VERSION 5.8 ;
BUSBITCHARS "[]" ;
DIVIDERCHAR "/" ;
UNITS
    DATABASE MICRONS 1000 ;
END UNITS

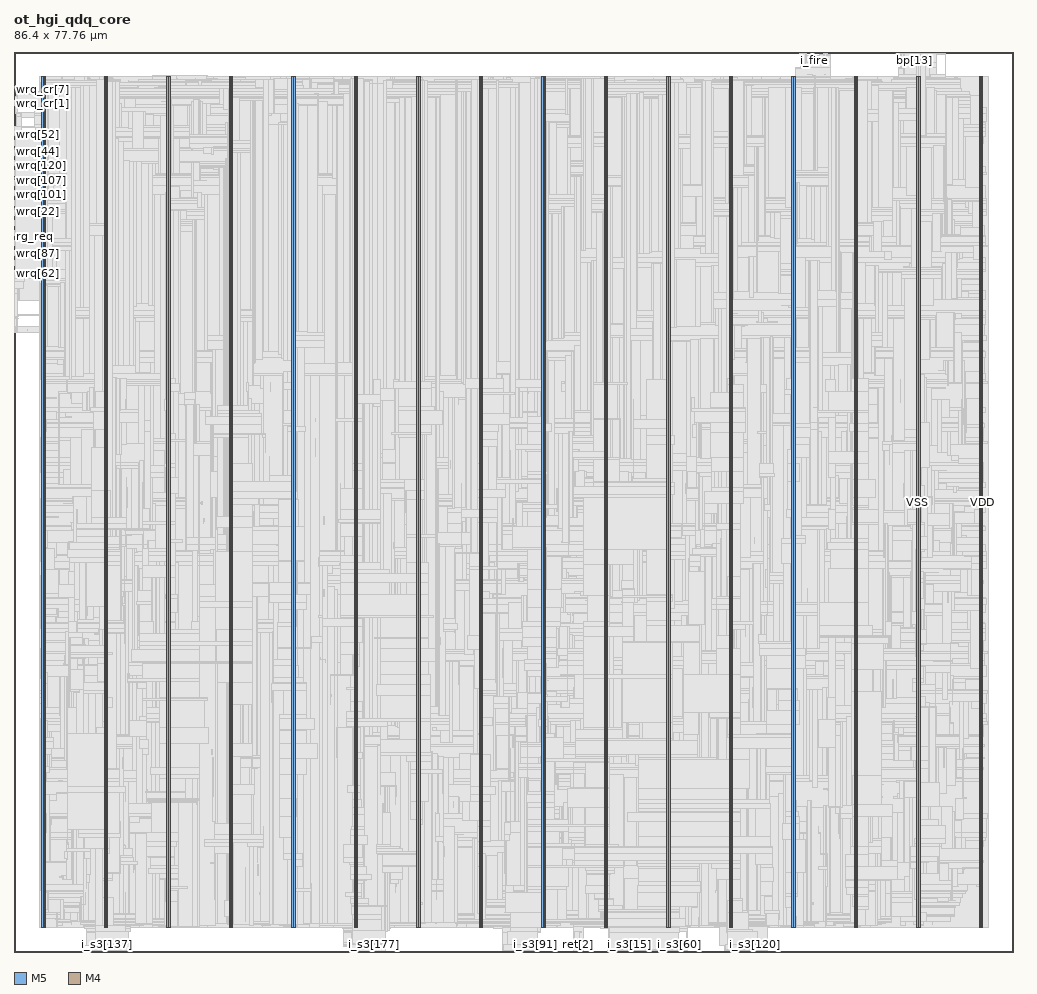
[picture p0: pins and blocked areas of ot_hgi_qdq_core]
MACRO ot_hgi_qdq_core
  FOREIGN ot_hgi_qdq_core 0 0 ;
  CLASS BLOCK ;
  SIZE 86.4 BY 77.76 ;
  PIN asm_rst_n
    DIRECTION OUTPUT ;
    USE SIGNAL ;
    PORT
      LAYER M5 ;
        RECT  76.464 77.676 76.488 77.76 ;
    END
  END asm_rst_n
  PIN bp[0]
    DIRECTION OUTPUT ;
    USE SIGNAL ;
    PORT
      LAYER M5 ;
        RECT  76.56 77.676 76.584 77.76 ;
    END
  END bp[0]
  PIN bp[10]
    DIRECTION OUTPUT ;
    USE SIGNAL ;
    PORT
      LAYER M5 ;
        RECT  77.52 77.676 77.544 77.76 ;
    END
  END bp[10]
  PIN bp[11]
    DIRECTION OUTPUT ;
    USE SIGNAL ;
    PORT
      LAYER M5 ;
        RECT  77.616 77.676 77.64 77.76 ;
    END
  END bp[11]
  PIN bp[12]
    DIRECTION OUTPUT ;
    USE SIGNAL ;
    PORT
      LAYER M5 ;
        RECT  77.712 77.676 77.736 77.76 ;
    END
  END bp[12]
  PIN bp[13]
    DIRECTION OUTPUT ;
    USE SIGNAL ;
    PORT
      LAYER M5 ;
        RECT  77.808 77.676 77.832 77.76 ;
    END
  END bp[13]
  PIN bp[14]
    DIRECTION OUTPUT ;
    USE SIGNAL ;
    PORT
      LAYER M5 ;
        RECT  77.904 77.676 77.928 77.76 ;
    END
  END bp[14]
  PIN bp[15]
    DIRECTION OUTPUT ;
    USE SIGNAL ;
    PORT
      LAYER M5 ;
        RECT  78 77.676 78.024 77.76 ;
    END
  END bp[15]
  PIN bp[16]
    DIRECTION OUTPUT ;
    USE SIGNAL ;
    PORT
      LAYER M5 ;
        RECT  78.096 77.676 78.12 77.76 ;
    END
  END bp[16]
  PIN bp[17]
    DIRECTION OUTPUT ;
    USE SIGNAL ;
    PORT
      LAYER M5 ;
        RECT  78.192 77.676 78.216 77.76 ;
    END
  END bp[17]
  PIN bp[18]
    DIRECTION OUTPUT ;
    USE SIGNAL ;
    PORT
      LAYER M5 ;
        RECT  78.288 77.676 78.312 77.76 ;
    END
  END bp[18]
  PIN bp[19]
    DIRECTION OUTPUT ;
    USE SIGNAL ;
    PORT
      LAYER M5 ;
        RECT  78.384 77.676 78.408 77.76 ;
    END
  END bp[19]
  PIN bp[1]
    DIRECTION OUTPUT ;
    USE SIGNAL ;
    PORT
      LAYER M5 ;
        RECT  76.656 77.676 76.68 77.76 ;
    END
  END bp[1]
  PIN bp[20]
    DIRECTION OUTPUT ;
    USE SIGNAL ;
    PORT
      LAYER M5 ;
        RECT  78.48 77.676 78.504 77.76 ;
    END
  END bp[20]
  PIN bp[21]
    DIRECTION OUTPUT ;
    USE SIGNAL ;
    PORT
      LAYER M5 ;
        RECT  78.576 77.676 78.6 77.76 ;
    END
  END bp[21]
  PIN bp[22]
    DIRECTION OUTPUT ;
    USE SIGNAL ;
    PORT
      LAYER M5 ;
        RECT  78.672 77.676 78.696 77.76 ;
    END
  END bp[22]
  PIN bp[23]
    DIRECTION OUTPUT ;
    USE SIGNAL ;
    PORT
      LAYER M5 ;
        RECT  78.768 77.676 78.792 77.76 ;
    END
  END bp[23]
  PIN bp[24]
    DIRECTION OUTPUT ;
    USE SIGNAL ;
    PORT
      LAYER M5 ;
        RECT  78.864 77.676 78.888 77.76 ;
    END
  END bp[24]
  PIN bp[25]
    DIRECTION OUTPUT ;
    USE SIGNAL ;
    PORT
      LAYER M5 ;
        RECT  78.96 77.676 78.984 77.76 ;
    END
  END bp[25]
  PIN bp[26]
    DIRECTION OUTPUT ;
    USE SIGNAL ;
    PORT
      LAYER M5 ;
        RECT  79.056 77.676 79.08 77.76 ;
    END
  END bp[26]
  PIN bp[27]
    DIRECTION OUTPUT ;
    USE SIGNAL ;
    PORT
      LAYER M5 ;
        RECT  79.152 77.676 79.176 77.76 ;
    END
  END bp[27]
  PIN bp[28]
    DIRECTION OUTPUT ;
    USE SIGNAL ;
    PORT
      LAYER M5 ;
        RECT  79.248 77.676 79.272 77.76 ;
    END
  END bp[28]
  PIN bp[29]
    DIRECTION OUTPUT ;
    USE SIGNAL ;
    PORT
      LAYER M5 ;
        RECT  79.344 77.676 79.368 77.76 ;
    END
  END bp[29]
  PIN bp[2]
    DIRECTION OUTPUT ;
    USE SIGNAL ;
    PORT
      LAYER M5 ;
        RECT  76.752 77.676 76.776 77.76 ;
    END
  END bp[2]
  PIN bp[30]
    DIRECTION OUTPUT ;
    USE SIGNAL ;
    PORT
      LAYER M5 ;
        RECT  79.44 77.676 79.464 77.76 ;
    END
  END bp[30]
  PIN bp[31]
    DIRECTION OUTPUT ;
    USE SIGNAL ;
    PORT
      LAYER M5 ;
        RECT  67.92 77.676 67.944 77.76 ;
    END
  END bp[31]
  PIN bp[32]
    DIRECTION OUTPUT ;
    USE SIGNAL ;
    PORT
      LAYER M5 ;
        RECT  68.016 77.676 68.04 77.76 ;
    END
  END bp[32]
  PIN bp[33]
    DIRECTION OUTPUT ;
    USE SIGNAL ;
    PORT
      LAYER M5 ;
        RECT  68.112 77.676 68.136 77.76 ;
    END
  END bp[33]
  PIN bp[34]
    DIRECTION OUTPUT ;
    USE SIGNAL ;
    PORT
      LAYER M5 ;
        RECT  68.208 77.676 68.232 77.76 ;
    END
  END bp[34]
  PIN bp[35]
    DIRECTION OUTPUT ;
    USE SIGNAL ;
    PORT
      LAYER M5 ;
        RECT  68.304 77.676 68.328 77.76 ;
    END
  END bp[35]
  PIN bp[36]
    DIRECTION OUTPUT ;
    USE SIGNAL ;
    PORT
      LAYER M5 ;
        RECT  68.4 77.676 68.424 77.76 ;
    END
  END bp[36]
  PIN bp[37]
    DIRECTION OUTPUT ;
    USE SIGNAL ;
    PORT
      LAYER M5 ;
        RECT  68.496 77.676 68.52 77.76 ;
    END
  END bp[37]
  PIN bp[38]
    DIRECTION OUTPUT ;
    USE SIGNAL ;
    PORT
      LAYER M5 ;
        RECT  68.592 77.676 68.616 77.76 ;
    END
  END bp[38]
  PIN bp[39]
    DIRECTION OUTPUT ;
    USE SIGNAL ;
    PORT
      LAYER M5 ;
        RECT  68.688 77.676 68.712 77.76 ;
    END
  END bp[39]
  PIN bp[3]
    DIRECTION OUTPUT ;
    USE SIGNAL ;
    PORT
      LAYER M5 ;
        RECT  76.848 77.676 76.872 77.76 ;
    END
  END bp[3]
  PIN bp[4]
    DIRECTION OUTPUT ;
    USE SIGNAL ;
    PORT
      LAYER M5 ;
        RECT  76.944 77.676 76.968 77.76 ;
    END
  END bp[4]
  PIN bp[5]
    DIRECTION OUTPUT ;
    USE SIGNAL ;
    PORT
      LAYER M5 ;
        RECT  77.04 77.676 77.064 77.76 ;
    END
  END bp[5]
  PIN bp[6]
    DIRECTION OUTPUT ;
    USE SIGNAL ;
    PORT
      LAYER M5 ;
        RECT  77.136 77.676 77.16 77.76 ;
    END
  END bp[6]
  PIN bp[7]
    DIRECTION OUTPUT ;
    USE SIGNAL ;
    PORT
      LAYER M5 ;
        RECT  77.232 77.676 77.256 77.76 ;
    END
  END bp[7]
  PIN bp[8]
    DIRECTION OUTPUT ;
    USE SIGNAL ;
    PORT
      LAYER M5 ;
        RECT  77.328 77.676 77.352 77.76 ;
    END
  END bp[8]
  PIN bp[9]
    DIRECTION OUTPUT ;
    USE SIGNAL ;
    PORT
      LAYER M5 ;
        RECT  77.424 77.676 77.448 77.76 ;
    END
  END bp[9]
  PIN bp_v
    DIRECTION OUTPUT ;
    USE SIGNAL ;
    PORT
      LAYER M5 ;
        RECT  68.784 77.676 68.808 77.76 ;
    END
  END bp_v
  PIN clk
    DIRECTION INPUT ;
    USE SIGNAL ;
    PORT
      LAYER M5 ;
        RECT  51.408 0 51.432 0.084 ;
    END
  END clk
  PIN i_abad
    DIRECTION INPUT ;
    USE SIGNAL ;
    PORT
      LAYER M5 ;
        RECT  68.88 77.676 68.904 77.76 ;
    END
  END i_abad
  PIN i_aidle
    DIRECTION INPUT ;
    USE SIGNAL ;
    PORT
      LAYER M5 ;
        RECT  68.976 77.676 69 77.76 ;
    END
  END i_aidle
  PIN i_fin
    DIRECTION INPUT ;
    USE SIGNAL ;
    PORT
      LAYER M5 ;
        RECT  69.072 77.676 69.096 77.76 ;
    END
  END i_fin
  PIN i_fire
    DIRECTION INPUT ;
    USE SIGNAL ;
    PORT
      LAYER M5 ;
        RECT  69.168 77.676 69.192 77.76 ;
    END
  END i_fire
  PIN i_nfault
    DIRECTION INPUT ;
    USE SIGNAL ;
    PORT
      LAYER M5 ;
        RECT  51.504 0 51.528 0.084 ;
    END
  END i_nfault
  PIN i_pop[0]
    DIRECTION INPUT ;
    USE SIGNAL ;
    PORT
      LAYER M5 ;
        RECT  69.264 77.676 69.288 77.76 ;
    END
  END i_pop[0]
  PIN i_pop[1]
    DIRECTION INPUT ;
    USE SIGNAL ;
    PORT
      LAYER M5 ;
        RECT  69.36 77.676 69.384 77.76 ;
    END
  END i_pop[1]
  PIN i_pop[2]
    DIRECTION INPUT ;
    USE SIGNAL ;
    PORT
      LAYER M5 ;
        RECT  69.456 77.676 69.48 77.76 ;
    END
  END i_pop[2]
  PIN i_pop[3]
    DIRECTION INPUT ;
    USE SIGNAL ;
    PORT
      LAYER M5 ;
        RECT  69.552 77.676 69.576 77.76 ;
    END
  END i_pop[3]
  PIN i_pop[4]
    DIRECTION INPUT ;
    USE SIGNAL ;
    PORT
      LAYER M5 ;
        RECT  69.648 77.676 69.672 77.76 ;
    END
  END i_pop[4]
  PIN i_pop[5]
    DIRECTION INPUT ;
    USE SIGNAL ;
    PORT
      LAYER M5 ;
        RECT  69.744 77.676 69.768 77.76 ;
    END
  END i_pop[5]
  PIN i_pop[6]
    DIRECTION INPUT ;
    USE SIGNAL ;
    PORT
      LAYER M5 ;
        RECT  69.84 77.676 69.864 77.76 ;
    END
  END i_pop[6]
  PIN i_pop[7]
    DIRECTION INPUT ;
    USE SIGNAL ;
    PORT
      LAYER M5 ;
        RECT  69.936 77.676 69.96 77.76 ;
    END
  END i_pop[7]
  PIN i_s1_v
    DIRECTION INPUT ;
    USE SIGNAL ;
    PORT
      LAYER M5 ;
        RECT  51.6 0 51.624 0.084 ;
    END
  END i_s1_v
  PIN i_s3[0]
    DIRECTION INPUT ;
    USE SIGNAL ;
    PORT
      LAYER M5 ;
        RECT  51.696 0 51.72 0.084 ;
    END
  END i_s3[0]
  PIN i_s3[100]
    DIRECTION INPUT ;
    USE SIGNAL ;
    PORT
      LAYER M5 ;
        RECT  62.064 0 62.088 0.084 ;
    END
  END i_s3[100]
  PIN i_s3[101]
    DIRECTION INPUT ;
    USE SIGNAL ;
    PORT
      LAYER M5 ;
        RECT  62.16 0 62.184 0.084 ;
    END
  END i_s3[101]
  PIN i_s3[102]
    DIRECTION INPUT ;
    USE SIGNAL ;
    PORT
      LAYER M5 ;
        RECT  62.256 0 62.28 0.084 ;
    END
  END i_s3[102]
  PIN i_s3[103]
    DIRECTION INPUT ;
    USE SIGNAL ;
    PORT
      LAYER M5 ;
        RECT  62.352 0 62.376 0.084 ;
    END
  END i_s3[103]
  PIN i_s3[104]
    DIRECTION INPUT ;
    USE SIGNAL ;
    PORT
      LAYER M5 ;
        RECT  62.448 0 62.472 0.084 ;
    END
  END i_s3[104]
  PIN i_s3[105]
    DIRECTION INPUT ;
    USE SIGNAL ;
    PORT
      LAYER M5 ;
        RECT  62.544 0 62.568 0.084 ;
    END
  END i_s3[105]
  PIN i_s3[106]
    DIRECTION INPUT ;
    USE SIGNAL ;
    PORT
      LAYER M5 ;
        RECT  62.64 0 62.664 0.084 ;
    END
  END i_s3[106]
  PIN i_s3[107]
    DIRECTION INPUT ;
    USE SIGNAL ;
    PORT
      LAYER M5 ;
        RECT  62.736 0 62.76 0.084 ;
    END
  END i_s3[107]
  PIN i_s3[108]
    DIRECTION INPUT ;
    USE SIGNAL ;
    PORT
      LAYER M5 ;
        RECT  62.832 0 62.856 0.084 ;
    END
  END i_s3[108]
  PIN i_s3[109]
    DIRECTION INPUT ;
    USE SIGNAL ;
    PORT
      LAYER M5 ;
        RECT  62.928 0 62.952 0.084 ;
    END
  END i_s3[109]
  PIN i_s3[10]
    DIRECTION INPUT ;
    USE SIGNAL ;
    PORT
      LAYER M5 ;
        RECT  52.656 0 52.68 0.084 ;
    END
  END i_s3[10]
  PIN i_s3[110]
    DIRECTION INPUT ;
    USE SIGNAL ;
    PORT
      LAYER M5 ;
        RECT  63.024 0 63.048 0.084 ;
    END
  END i_s3[110]
  PIN i_s3[111]
    DIRECTION INPUT ;
    USE SIGNAL ;
    PORT
      LAYER M5 ;
        RECT  63.12 0 63.144 0.084 ;
    END
  END i_s3[111]
  PIN i_s3[112]
    DIRECTION INPUT ;
    USE SIGNAL ;
    PORT
      LAYER M5 ;
        RECT  63.216 0 63.24 0.084 ;
    END
  END i_s3[112]
  PIN i_s3[113]
    DIRECTION INPUT ;
    USE SIGNAL ;
    PORT
      LAYER M5 ;
        RECT  63.312 0 63.336 0.084 ;
    END
  END i_s3[113]
  PIN i_s3[114]
    DIRECTION INPUT ;
    USE SIGNAL ;
    PORT
      LAYER M5 ;
        RECT  63.408 0 63.432 0.084 ;
    END
  END i_s3[114]
  PIN i_s3[115]
    DIRECTION INPUT ;
    USE SIGNAL ;
    PORT
      LAYER M5 ;
        RECT  63.504 0 63.528 0.084 ;
    END
  END i_s3[115]
  PIN i_s3[116]
    DIRECTION INPUT ;
    USE SIGNAL ;
    PORT
      LAYER M5 ;
        RECT  63.6 0 63.624 0.084 ;
    END
  END i_s3[116]
  PIN i_s3[117]
    DIRECTION INPUT ;
    USE SIGNAL ;
    PORT
      LAYER M5 ;
        RECT  63.696 0 63.72 0.084 ;
    END
  END i_s3[117]
  PIN i_s3[118]
    DIRECTION INPUT ;
    USE SIGNAL ;
    PORT
      LAYER M5 ;
        RECT  63.792 0 63.816 0.084 ;
    END
  END i_s3[118]
  PIN i_s3[119]
    DIRECTION INPUT ;
    USE SIGNAL ;
    PORT
      LAYER M5 ;
        RECT  63.888 0 63.912 0.084 ;
    END
  END i_s3[119]
  PIN i_s3[11]
    DIRECTION INPUT ;
    USE SIGNAL ;
    PORT
      LAYER M5 ;
        RECT  52.752 0 52.776 0.084 ;
    END
  END i_s3[11]
  PIN i_s3[120]
    DIRECTION INPUT ;
    USE SIGNAL ;
    PORT
      LAYER M5 ;
        RECT  63.984 0 64.008 0.084 ;
    END
  END i_s3[120]
  PIN i_s3[121]
    DIRECTION INPUT ;
    USE SIGNAL ;
    PORT
      LAYER M5 ;
        RECT  64.08 0 64.104 0.084 ;
    END
  END i_s3[121]
  PIN i_s3[122]
    DIRECTION INPUT ;
    USE SIGNAL ;
    PORT
      LAYER M5 ;
        RECT  64.176 0 64.2 0.084 ;
    END
  END i_s3[122]
  PIN i_s3[123]
    DIRECTION INPUT ;
    USE SIGNAL ;
    PORT
      LAYER M5 ;
        RECT  64.272 0 64.296 0.084 ;
    END
  END i_s3[123]
  PIN i_s3[124]
    DIRECTION INPUT ;
    USE SIGNAL ;
    PORT
      LAYER M5 ;
        RECT  64.368 0 64.392 0.084 ;
    END
  END i_s3[124]
  PIN i_s3[125]
    DIRECTION INPUT ;
    USE SIGNAL ;
    PORT
      LAYER M5 ;
        RECT  6.864 0 6.888 0.084 ;
    END
  END i_s3[125]
  PIN i_s3[126]
    DIRECTION INPUT ;
    USE SIGNAL ;
    PORT
      LAYER M5 ;
        RECT  6.96 0 6.984 0.084 ;
    END
  END i_s3[126]
  PIN i_s3[127]
    DIRECTION INPUT ;
    USE SIGNAL ;
    PORT
      LAYER M5 ;
        RECT  7.056 0 7.08 0.084 ;
    END
  END i_s3[127]
  PIN i_s3[128]
    DIRECTION INPUT ;
    USE SIGNAL ;
    PORT
      LAYER M5 ;
        RECT  7.152 0 7.176 0.084 ;
    END
  END i_s3[128]
  PIN i_s3[129]
    DIRECTION INPUT ;
    USE SIGNAL ;
    PORT
      LAYER M5 ;
        RECT  7.248 0 7.272 0.084 ;
    END
  END i_s3[129]
  PIN i_s3[12]
    DIRECTION INPUT ;
    USE SIGNAL ;
    PORT
      LAYER M5 ;
        RECT  52.848 0 52.872 0.084 ;
    END
  END i_s3[12]
  PIN i_s3[130]
    DIRECTION INPUT ;
    USE SIGNAL ;
    PORT
      LAYER M5 ;
        RECT  7.344 0 7.368 0.084 ;
    END
  END i_s3[130]
  PIN i_s3[131]
    DIRECTION INPUT ;
    USE SIGNAL ;
    PORT
      LAYER M5 ;
        RECT  7.44 0 7.464 0.084 ;
    END
  END i_s3[131]
  PIN i_s3[132]
    DIRECTION INPUT ;
    USE SIGNAL ;
    PORT
      LAYER M5 ;
        RECT  7.536 0 7.56 0.084 ;
    END
  END i_s3[132]
  PIN i_s3[133]
    DIRECTION INPUT ;
    USE SIGNAL ;
    PORT
      LAYER M5 ;
        RECT  7.632 0 7.656 0.084 ;
    END
  END i_s3[133]
  PIN i_s3[134]
    DIRECTION INPUT ;
    USE SIGNAL ;
    PORT
      LAYER M5 ;
        RECT  7.728 0 7.752 0.084 ;
    END
  END i_s3[134]
  PIN i_s3[135]
    DIRECTION INPUT ;
    USE SIGNAL ;
    PORT
      LAYER M5 ;
        RECT  7.824 0 7.848 0.084 ;
    END
  END i_s3[135]
  PIN i_s3[136]
    DIRECTION INPUT ;
    USE SIGNAL ;
    PORT
      LAYER M5 ;
        RECT  7.92 0 7.944 0.084 ;
    END
  END i_s3[136]
  PIN i_s3[137]
    DIRECTION INPUT ;
    USE SIGNAL ;
    PORT
      LAYER M5 ;
        RECT  8.016 0 8.04 0.084 ;
    END
  END i_s3[137]
  PIN i_s3[138]
    DIRECTION INPUT ;
    USE SIGNAL ;
    PORT
      LAYER M5 ;
        RECT  8.112 0 8.136 0.084 ;
    END
  END i_s3[138]
  PIN i_s3[139]
    DIRECTION INPUT ;
    USE SIGNAL ;
    PORT
      LAYER M5 ;
        RECT  8.208 0 8.232 0.084 ;
    END
  END i_s3[139]
  PIN i_s3[13]
    DIRECTION INPUT ;
    USE SIGNAL ;
    PORT
      LAYER M5 ;
        RECT  52.944 0 52.968 0.084 ;
    END
  END i_s3[13]
  PIN i_s3[140]
    DIRECTION INPUT ;
    USE SIGNAL ;
    PORT
      LAYER M5 ;
        RECT  8.304 0 8.328 0.084 ;
    END
  END i_s3[140]
  PIN i_s3[141]
    DIRECTION INPUT ;
    USE SIGNAL ;
    PORT
      LAYER M5 ;
        RECT  8.4 0 8.424 0.084 ;
    END
  END i_s3[141]
  PIN i_s3[142]
    DIRECTION INPUT ;
    USE SIGNAL ;
    PORT
      LAYER M5 ;
        RECT  8.496 0 8.52 0.084 ;
    END
  END i_s3[142]
  PIN i_s3[143]
    DIRECTION INPUT ;
    USE SIGNAL ;
    PORT
      LAYER M5 ;
        RECT  8.592 0 8.616 0.084 ;
    END
  END i_s3[143]
  PIN i_s3[144]
    DIRECTION INPUT ;
    USE SIGNAL ;
    PORT
      LAYER M5 ;
        RECT  8.688 0 8.712 0.084 ;
    END
  END i_s3[144]
  PIN i_s3[145]
    DIRECTION INPUT ;
    USE SIGNAL ;
    PORT
      LAYER M5 ;
        RECT  8.784 0 8.808 0.084 ;
    END
  END i_s3[145]
  PIN i_s3[146]
    DIRECTION INPUT ;
    USE SIGNAL ;
    PORT
      LAYER M5 ;
        RECT  8.88 0 8.904 0.084 ;
    END
  END i_s3[146]
  PIN i_s3[147]
    DIRECTION INPUT ;
    USE SIGNAL ;
    PORT
      LAYER M5 ;
        RECT  8.976 0 9 0.084 ;
    END
  END i_s3[147]
  PIN i_s3[148]
    DIRECTION INPUT ;
    USE SIGNAL ;
    PORT
      LAYER M5 ;
        RECT  9.072 0 9.096 0.084 ;
    END
  END i_s3[148]
  PIN i_s3[149]
    DIRECTION INPUT ;
    USE SIGNAL ;
    PORT
      LAYER M5 ;
        RECT  9.168 0 9.192 0.084 ;
    END
  END i_s3[149]
  PIN i_s3[14]
    DIRECTION INPUT ;
    USE SIGNAL ;
    PORT
      LAYER M5 ;
        RECT  53.04 0 53.064 0.084 ;
    END
  END i_s3[14]
  PIN i_s3[150]
    DIRECTION INPUT ;
    USE SIGNAL ;
    PORT
      LAYER M5 ;
        RECT  9.264 0 9.288 0.084 ;
    END
  END i_s3[150]
  PIN i_s3[151]
    DIRECTION INPUT ;
    USE SIGNAL ;
    PORT
      LAYER M5 ;
        RECT  9.36 0 9.384 0.084 ;
    END
  END i_s3[151]
  PIN i_s3[152]
    DIRECTION INPUT ;
    USE SIGNAL ;
    PORT
      LAYER M5 ;
        RECT  9.456 0 9.48 0.084 ;
    END
  END i_s3[152]
  PIN i_s3[153]
    DIRECTION INPUT ;
    USE SIGNAL ;
    PORT
      LAYER M5 ;
        RECT  9.552 0 9.576 0.084 ;
    END
  END i_s3[153]
  PIN i_s3[154]
    DIRECTION INPUT ;
    USE SIGNAL ;
    PORT
      LAYER M5 ;
        RECT  9.648 0 9.672 0.084 ;
    END
  END i_s3[154]
  PIN i_s3[155]
    DIRECTION INPUT ;
    USE SIGNAL ;
    PORT
      LAYER M5 ;
        RECT  9.744 0 9.768 0.084 ;
    END
  END i_s3[155]
  PIN i_s3[156]
    DIRECTION INPUT ;
    USE SIGNAL ;
    PORT
      LAYER M5 ;
        RECT  9.84 0 9.864 0.084 ;
    END
  END i_s3[156]
  PIN i_s3[157]
    DIRECTION INPUT ;
    USE SIGNAL ;
    PORT
      LAYER M5 ;
        RECT  29.136 0 29.16 0.084 ;
    END
  END i_s3[157]
  PIN i_s3[158]
    DIRECTION INPUT ;
    USE SIGNAL ;
    PORT
      LAYER M5 ;
        RECT  29.232 0 29.256 0.084 ;
    END
  END i_s3[158]
  PIN i_s3[159]
    DIRECTION INPUT ;
    USE SIGNAL ;
    PORT
      LAYER M5 ;
        RECT  29.328 0 29.352 0.084 ;
    END
  END i_s3[159]
  PIN i_s3[15]
    DIRECTION INPUT ;
    USE SIGNAL ;
    PORT
      LAYER M5 ;
        RECT  53.136 0 53.16 0.084 ;
    END
  END i_s3[15]
  PIN i_s3[160]
    DIRECTION INPUT ;
    USE SIGNAL ;
    PORT
      LAYER M5 ;
        RECT  29.424 0 29.448 0.084 ;
    END
  END i_s3[160]
  PIN i_s3[161]
    DIRECTION INPUT ;
    USE SIGNAL ;
    PORT
      LAYER M5 ;
        RECT  29.52 0 29.544 0.084 ;
    END
  END i_s3[161]
  PIN i_s3[162]
    DIRECTION INPUT ;
    USE SIGNAL ;
    PORT
      LAYER M5 ;
        RECT  29.616 0 29.64 0.084 ;
    END
  END i_s3[162]
  PIN i_s3[163]
    DIRECTION INPUT ;
    USE SIGNAL ;
    PORT
      LAYER M5 ;
        RECT  29.712 0 29.736 0.084 ;
    END
  END i_s3[163]
  PIN i_s3[164]
    DIRECTION INPUT ;
    USE SIGNAL ;
    PORT
      LAYER M5 ;
        RECT  29.808 0 29.832 0.084 ;
    END
  END i_s3[164]
  PIN i_s3[165]
    DIRECTION INPUT ;
    USE SIGNAL ;
    PORT
      LAYER M5 ;
        RECT  29.904 0 29.928 0.084 ;
    END
  END i_s3[165]
  PIN i_s3[166]
    DIRECTION INPUT ;
    USE SIGNAL ;
    PORT
      LAYER M5 ;
        RECT  30 0 30.024 0.084 ;
    END
  END i_s3[166]
  PIN i_s3[167]
    DIRECTION INPUT ;
    USE SIGNAL ;
    PORT
      LAYER M5 ;
        RECT  30.096 0 30.12 0.084 ;
    END
  END i_s3[167]
  PIN i_s3[168]
    DIRECTION INPUT ;
    USE SIGNAL ;
    PORT
      LAYER M5 ;
        RECT  30.192 0 30.216 0.084 ;
    END
  END i_s3[168]
  PIN i_s3[169]
    DIRECTION INPUT ;
    USE SIGNAL ;
    PORT
      LAYER M5 ;
        RECT  30.288 0 30.312 0.084 ;
    END
  END i_s3[169]
  PIN i_s3[16]
    DIRECTION INPUT ;
    USE SIGNAL ;
    PORT
      LAYER M5 ;
        RECT  53.232 0 53.256 0.084 ;
    END
  END i_s3[16]
  PIN i_s3[170]
    DIRECTION INPUT ;
    USE SIGNAL ;
    PORT
      LAYER M5 ;
        RECT  30.384 0 30.408 0.084 ;
    END
  END i_s3[170]
  PIN i_s3[171]
    DIRECTION INPUT ;
    USE SIGNAL ;
    PORT
      LAYER M5 ;
        RECT  30.48 0 30.504 0.084 ;
    END
  END i_s3[171]
  PIN i_s3[172]
    DIRECTION INPUT ;
    USE SIGNAL ;
    PORT
      LAYER M5 ;
        RECT  30.576 0 30.6 0.084 ;
    END
  END i_s3[172]
  PIN i_s3[173]
    DIRECTION INPUT ;
    USE SIGNAL ;
    PORT
      LAYER M5 ;
        RECT  30.672 0 30.696 0.084 ;
    END
  END i_s3[173]
  PIN i_s3[174]
    DIRECTION INPUT ;
    USE SIGNAL ;
    PORT
      LAYER M5 ;
        RECT  30.768 0 30.792 0.084 ;
    END
  END i_s3[174]
  PIN i_s3[175]
    DIRECTION INPUT ;
    USE SIGNAL ;
    PORT
      LAYER M5 ;
        RECT  30.864 0 30.888 0.084 ;
    END
  END i_s3[175]
  PIN i_s3[176]
    DIRECTION INPUT ;
    USE SIGNAL ;
    PORT
      LAYER M5 ;
        RECT  30.96 0 30.984 0.084 ;
    END
  END i_s3[176]
  PIN i_s3[177]
    DIRECTION INPUT ;
    USE SIGNAL ;
    PORT
      LAYER M5 ;
        RECT  31.056 0 31.08 0.084 ;
    END
  END i_s3[177]
  PIN i_s3[178]
    DIRECTION INPUT ;
    USE SIGNAL ;
    PORT
      LAYER M5 ;
        RECT  31.152 0 31.176 0.084 ;
    END
  END i_s3[178]
  PIN i_s3[179]
    DIRECTION INPUT ;
    USE SIGNAL ;
    PORT
      LAYER M5 ;
        RECT  31.248 0 31.272 0.084 ;
    END
  END i_s3[179]
  PIN i_s3[17]
    DIRECTION INPUT ;
    USE SIGNAL ;
    PORT
      LAYER M5 ;
        RECT  53.328 0 53.352 0.084 ;
    END
  END i_s3[17]
  PIN i_s3[180]
    DIRECTION INPUT ;
    USE SIGNAL ;
    PORT
      LAYER M5 ;
        RECT  31.344 0 31.368 0.084 ;
    END
  END i_s3[180]
  PIN i_s3[181]
    DIRECTION INPUT ;
    USE SIGNAL ;
    PORT
      LAYER M5 ;
        RECT  31.44 0 31.464 0.084 ;
    END
  END i_s3[181]
  PIN i_s3[182]
    DIRECTION INPUT ;
    USE SIGNAL ;
    PORT
      LAYER M5 ;
        RECT  31.536 0 31.56 0.084 ;
    END
  END i_s3[182]
  PIN i_s3[183]
    DIRECTION INPUT ;
    USE SIGNAL ;
    PORT
      LAYER M5 ;
        RECT  31.632 0 31.656 0.084 ;
    END
  END i_s3[183]
  PIN i_s3[184]
    DIRECTION INPUT ;
    USE SIGNAL ;
    PORT
      LAYER M5 ;
        RECT  31.728 0 31.752 0.084 ;
    END
  END i_s3[184]
  PIN i_s3[185]
    DIRECTION INPUT ;
    USE SIGNAL ;
    PORT
      LAYER M5 ;
        RECT  31.824 0 31.848 0.084 ;
    END
  END i_s3[185]
  PIN i_s3[186]
    DIRECTION INPUT ;
    USE SIGNAL ;
    PORT
      LAYER M5 ;
        RECT  31.92 0 31.944 0.084 ;
    END
  END i_s3[186]
  PIN i_s3[187]
    DIRECTION INPUT ;
    USE SIGNAL ;
    PORT
      LAYER M5 ;
        RECT  32.016 0 32.04 0.084 ;
    END
  END i_s3[187]
  PIN i_s3[188]
    DIRECTION INPUT ;
    USE SIGNAL ;
    PORT
      LAYER M5 ;
        RECT  32.112 0 32.136 0.084 ;
    END
  END i_s3[188]
  PIN i_s3[189]
    DIRECTION INPUT ;
    USE SIGNAL ;
    PORT
      LAYER M5 ;
        RECT  48.336 0 48.36 0.084 ;
    END
  END i_s3[189]
  PIN i_s3[18]
    DIRECTION INPUT ;
    USE SIGNAL ;
    PORT
      LAYER M5 ;
        RECT  53.424 0 53.448 0.084 ;
    END
  END i_s3[18]
  PIN i_s3[19]
    DIRECTION INPUT ;
    USE SIGNAL ;
    PORT
      LAYER M5 ;
        RECT  53.52 0 53.544 0.084 ;
    END
  END i_s3[19]
  PIN i_s3[1]
    DIRECTION INPUT ;
    USE SIGNAL ;
    PORT
      LAYER M5 ;
        RECT  51.792 0 51.816 0.084 ;
    END
  END i_s3[1]
  PIN i_s3[20]
    DIRECTION INPUT ;
    USE SIGNAL ;
    PORT
      LAYER M5 ;
        RECT  53.616 0 53.64 0.084 ;
    END
  END i_s3[20]
  PIN i_s3[21]
    DIRECTION INPUT ;
    USE SIGNAL ;
    PORT
      LAYER M5 ;
        RECT  53.712 0 53.736 0.084 ;
    END
  END i_s3[21]
  PIN i_s3[22]
    DIRECTION INPUT ;
    USE SIGNAL ;
    PORT
      LAYER M5 ;
        RECT  53.808 0 53.832 0.084 ;
    END
  END i_s3[22]
  PIN i_s3[23]
    DIRECTION INPUT ;
    USE SIGNAL ;
    PORT
      LAYER M5 ;
        RECT  53.904 0 53.928 0.084 ;
    END
  END i_s3[23]
  PIN i_s3[24]
    DIRECTION INPUT ;
    USE SIGNAL ;
    PORT
      LAYER M5 ;
        RECT  54 0 54.024 0.084 ;
    END
  END i_s3[24]
  PIN i_s3[25]
    DIRECTION INPUT ;
    USE SIGNAL ;
    PORT
      LAYER M5 ;
        RECT  54.096 0 54.12 0.084 ;
    END
  END i_s3[25]
  PIN i_s3[26]
    DIRECTION INPUT ;
    USE SIGNAL ;
    PORT
      LAYER M5 ;
        RECT  54.192 0 54.216 0.084 ;
    END
  END i_s3[26]
  PIN i_s3[27]
    DIRECTION INPUT ;
    USE SIGNAL ;
    PORT
      LAYER M5 ;
        RECT  54.288 0 54.312 0.084 ;
    END
  END i_s3[27]
  PIN i_s3[28]
    DIRECTION INPUT ;
    USE SIGNAL ;
    PORT
      LAYER M5 ;
        RECT  54.384 0 54.408 0.084 ;
    END
  END i_s3[28]
  PIN i_s3[29]
    DIRECTION INPUT ;
    USE SIGNAL ;
    PORT
      LAYER M5 ;
        RECT  54.48 0 54.504 0.084 ;
    END
  END i_s3[29]
  PIN i_s3[2]
    DIRECTION INPUT ;
    USE SIGNAL ;
    PORT
      LAYER M5 ;
        RECT  51.888 0 51.912 0.084 ;
    END
  END i_s3[2]
  PIN i_s3[30]
    DIRECTION INPUT ;
    USE SIGNAL ;
    PORT
      LAYER M5 ;
        RECT  54.576 0 54.6 0.084 ;
    END
  END i_s3[30]
  PIN i_s3[31]
    DIRECTION INPUT ;
    USE SIGNAL ;
    PORT
      LAYER M5 ;
        RECT  54.672 0 54.696 0.084 ;
    END
  END i_s3[31]
  PIN i_s3[32]
    DIRECTION INPUT ;
    USE SIGNAL ;
    PORT
      LAYER M5 ;
        RECT  54.768 0 54.792 0.084 ;
    END
  END i_s3[32]
  PIN i_s3[33]
    DIRECTION INPUT ;
    USE SIGNAL ;
    PORT
      LAYER M5 ;
        RECT  54.864 0 54.888 0.084 ;
    END
  END i_s3[33]
  PIN i_s3[34]
    DIRECTION INPUT ;
    USE SIGNAL ;
    PORT
      LAYER M5 ;
        RECT  54.96 0 54.984 0.084 ;
    END
  END i_s3[34]
  PIN i_s3[35]
    DIRECTION INPUT ;
    USE SIGNAL ;
    PORT
      LAYER M5 ;
        RECT  55.056 0 55.08 0.084 ;
    END
  END i_s3[35]
  PIN i_s3[36]
    DIRECTION INPUT ;
    USE SIGNAL ;
    PORT
      LAYER M5 ;
        RECT  55.152 0 55.176 0.084 ;
    END
  END i_s3[36]
  PIN i_s3[37]
    DIRECTION INPUT ;
    USE SIGNAL ;
    PORT
      LAYER M5 ;
        RECT  55.248 0 55.272 0.084 ;
    END
  END i_s3[37]
  PIN i_s3[38]
    DIRECTION INPUT ;
    USE SIGNAL ;
    PORT
      LAYER M5 ;
        RECT  55.344 0 55.368 0.084 ;
    END
  END i_s3[38]
  PIN i_s3[39]
    DIRECTION INPUT ;
    USE SIGNAL ;
    PORT
      LAYER M5 ;
        RECT  55.44 0 55.464 0.084 ;
    END
  END i_s3[39]
  PIN i_s3[3]
    DIRECTION INPUT ;
    USE SIGNAL ;
    PORT
      LAYER M5 ;
        RECT  51.984 0 52.008 0.084 ;
    END
  END i_s3[3]
  PIN i_s3[40]
    DIRECTION INPUT ;
    USE SIGNAL ;
    PORT
      LAYER M5 ;
        RECT  55.536 0 55.56 0.084 ;
    END
  END i_s3[40]
  PIN i_s3[41]
    DIRECTION INPUT ;
    USE SIGNAL ;
    PORT
      LAYER M5 ;
        RECT  55.632 0 55.656 0.084 ;
    END
  END i_s3[41]
  PIN i_s3[42]
    DIRECTION INPUT ;
    USE SIGNAL ;
    PORT
      LAYER M5 ;
        RECT  55.728 0 55.752 0.084 ;
    END
  END i_s3[42]
  PIN i_s3[43]
    DIRECTION INPUT ;
    USE SIGNAL ;
    PORT
      LAYER M5 ;
        RECT  55.824 0 55.848 0.084 ;
    END
  END i_s3[43]
  PIN i_s3[44]
    DIRECTION INPUT ;
    USE SIGNAL ;
    PORT
      LAYER M5 ;
        RECT  55.92 0 55.944 0.084 ;
    END
  END i_s3[44]
  PIN i_s3[45]
    DIRECTION INPUT ;
    USE SIGNAL ;
    PORT
      LAYER M5 ;
        RECT  56.016 0 56.04 0.084 ;
    END
  END i_s3[45]
  PIN i_s3[46]
    DIRECTION INPUT ;
    USE SIGNAL ;
    PORT
      LAYER M5 ;
        RECT  56.112 0 56.136 0.084 ;
    END
  END i_s3[46]
  PIN i_s3[47]
    DIRECTION INPUT ;
    USE SIGNAL ;
    PORT
      LAYER M5 ;
        RECT  56.208 0 56.232 0.084 ;
    END
  END i_s3[47]
  PIN i_s3[48]
    DIRECTION INPUT ;
    USE SIGNAL ;
    PORT
      LAYER M5 ;
        RECT  56.304 0 56.328 0.084 ;
    END
  END i_s3[48]
  PIN i_s3[49]
    DIRECTION INPUT ;
    USE SIGNAL ;
    PORT
      LAYER M5 ;
        RECT  56.4 0 56.424 0.084 ;
    END
  END i_s3[49]
  PIN i_s3[4]
    DIRECTION INPUT ;
    USE SIGNAL ;
    PORT
      LAYER M5 ;
        RECT  52.08 0 52.104 0.084 ;
    END
  END i_s3[4]
  PIN i_s3[50]
    DIRECTION INPUT ;
    USE SIGNAL ;
    PORT
      LAYER M5 ;
        RECT  56.496 0 56.52 0.084 ;
    END
  END i_s3[50]
  PIN i_s3[51]
    DIRECTION INPUT ;
    USE SIGNAL ;
    PORT
      LAYER M5 ;
        RECT  56.592 0 56.616 0.084 ;
    END
  END i_s3[51]
  PIN i_s3[52]
    DIRECTION INPUT ;
    USE SIGNAL ;
    PORT
      LAYER M5 ;
        RECT  56.688 0 56.712 0.084 ;
    END
  END i_s3[52]
  PIN i_s3[53]
    DIRECTION INPUT ;
    USE SIGNAL ;
    PORT
      LAYER M5 ;
        RECT  56.784 0 56.808 0.084 ;
    END
  END i_s3[53]
  PIN i_s3[54]
    DIRECTION INPUT ;
    USE SIGNAL ;
    PORT
      LAYER M5 ;
        RECT  56.88 0 56.904 0.084 ;
    END
  END i_s3[54]
  PIN i_s3[55]
    DIRECTION INPUT ;
    USE SIGNAL ;
    PORT
      LAYER M5 ;
        RECT  56.976 0 57 0.084 ;
    END
  END i_s3[55]
  PIN i_s3[56]
    DIRECTION INPUT ;
    USE SIGNAL ;
    PORT
      LAYER M5 ;
        RECT  57.072 0 57.096 0.084 ;
    END
  END i_s3[56]
  PIN i_s3[57]
    DIRECTION INPUT ;
    USE SIGNAL ;
    PORT
      LAYER M5 ;
        RECT  57.168 0 57.192 0.084 ;
    END
  END i_s3[57]
  PIN i_s3[58]
    DIRECTION INPUT ;
    USE SIGNAL ;
    PORT
      LAYER M5 ;
        RECT  57.264 0 57.288 0.084 ;
    END
  END i_s3[58]
  PIN i_s3[59]
    DIRECTION INPUT ;
    USE SIGNAL ;
    PORT
      LAYER M5 ;
        RECT  57.36 0 57.384 0.084 ;
    END
  END i_s3[59]
  PIN i_s3[5]
    DIRECTION INPUT ;
    USE SIGNAL ;
    PORT
      LAYER M5 ;
        RECT  52.176 0 52.2 0.084 ;
    END
  END i_s3[5]
  PIN i_s3[60]
    DIRECTION INPUT ;
    USE SIGNAL ;
    PORT
      LAYER M5 ;
        RECT  57.456 0 57.48 0.084 ;
    END
  END i_s3[60]
  PIN i_s3[61]
    DIRECTION INPUT ;
    USE SIGNAL ;
    PORT
      LAYER M5 ;
        RECT  42.192 0 42.216 0.084 ;
    END
  END i_s3[61]
  PIN i_s3[62]
    DIRECTION INPUT ;
    USE SIGNAL ;
    PORT
      LAYER M5 ;
        RECT  42.288 0 42.312 0.084 ;
    END
  END i_s3[62]
  PIN i_s3[63]
    DIRECTION INPUT ;
    USE SIGNAL ;
    PORT
      LAYER M5 ;
        RECT  42.384 0 42.408 0.084 ;
    END
  END i_s3[63]
  PIN i_s3[64]
    DIRECTION INPUT ;
    USE SIGNAL ;
    PORT
      LAYER M5 ;
        RECT  42.48 0 42.504 0.084 ;
    END
  END i_s3[64]
  PIN i_s3[65]
    DIRECTION INPUT ;
    USE SIGNAL ;
    PORT
      LAYER M5 ;
        RECT  42.576 0 42.6 0.084 ;
    END
  END i_s3[65]
  PIN i_s3[66]
    DIRECTION INPUT ;
    USE SIGNAL ;
    PORT
      LAYER M5 ;
        RECT  42.672 0 42.696 0.084 ;
    END
  END i_s3[66]
  PIN i_s3[67]
    DIRECTION INPUT ;
    USE SIGNAL ;
    PORT
      LAYER M5 ;
        RECT  42.768 0 42.792 0.084 ;
    END
  END i_s3[67]
  PIN i_s3[68]
    DIRECTION INPUT ;
    USE SIGNAL ;
    PORT
      LAYER M5 ;
        RECT  42.864 0 42.888 0.084 ;
    END
  END i_s3[68]
  PIN i_s3[69]
    DIRECTION INPUT ;
    USE SIGNAL ;
    PORT
      LAYER M5 ;
        RECT  42.96 0 42.984 0.084 ;
    END
  END i_s3[69]
  PIN i_s3[6]
    DIRECTION INPUT ;
    USE SIGNAL ;
    PORT
      LAYER M5 ;
        RECT  52.272 0 52.296 0.084 ;
    END
  END i_s3[6]
  PIN i_s3[70]
    DIRECTION INPUT ;
    USE SIGNAL ;
    PORT
      LAYER M5 ;
        RECT  43.056 0 43.08 0.084 ;
    END
  END i_s3[70]
  PIN i_s3[71]
    DIRECTION INPUT ;
    USE SIGNAL ;
    PORT
      LAYER M5 ;
        RECT  43.152 0 43.176 0.084 ;
    END
  END i_s3[71]
  PIN i_s3[72]
    DIRECTION INPUT ;
    USE SIGNAL ;
    PORT
      LAYER M5 ;
        RECT  43.248 0 43.272 0.084 ;
    END
  END i_s3[72]
  PIN i_s3[73]
    DIRECTION INPUT ;
    USE SIGNAL ;
    PORT
      LAYER M5 ;
        RECT  43.344 0 43.368 0.084 ;
    END
  END i_s3[73]
  PIN i_s3[74]
    DIRECTION INPUT ;
    USE SIGNAL ;
    PORT
      LAYER M5 ;
        RECT  43.44 0 43.464 0.084 ;
    END
  END i_s3[74]
  PIN i_s3[75]
    DIRECTION INPUT ;
    USE SIGNAL ;
    PORT
      LAYER M5 ;
        RECT  43.536 0 43.56 0.084 ;
    END
  END i_s3[75]
  PIN i_s3[76]
    DIRECTION INPUT ;
    USE SIGNAL ;
    PORT
      LAYER M5 ;
        RECT  43.632 0 43.656 0.084 ;
    END
  END i_s3[76]
  PIN i_s3[77]
    DIRECTION INPUT ;
    USE SIGNAL ;
    PORT
      LAYER M5 ;
        RECT  43.728 0 43.752 0.084 ;
    END
  END i_s3[77]
  PIN i_s3[78]
    DIRECTION INPUT ;
    USE SIGNAL ;
    PORT
      LAYER M5 ;
        RECT  43.824 0 43.848 0.084 ;
    END
  END i_s3[78]
  PIN i_s3[79]
    DIRECTION INPUT ;
    USE SIGNAL ;
    PORT
      LAYER M5 ;
        RECT  43.92 0 43.944 0.084 ;
    END
  END i_s3[79]
  PIN i_s3[7]
    DIRECTION INPUT ;
    USE SIGNAL ;
    PORT
      LAYER M5 ;
        RECT  52.368 0 52.392 0.084 ;
    END
  END i_s3[7]
  PIN i_s3[80]
    DIRECTION INPUT ;
    USE SIGNAL ;
    PORT
      LAYER M5 ;
        RECT  44.016 0 44.04 0.084 ;
    END
  END i_s3[80]
  PIN i_s3[81]
    DIRECTION INPUT ;
    USE SIGNAL ;
    PORT
      LAYER M5 ;
        RECT  44.112 0 44.136 0.084 ;
    END
  END i_s3[81]
  PIN i_s3[82]
    DIRECTION INPUT ;
    USE SIGNAL ;
    PORT
      LAYER M5 ;
        RECT  44.208 0 44.232 0.084 ;
    END
  END i_s3[82]
  PIN i_s3[83]
    DIRECTION INPUT ;
    USE SIGNAL ;
    PORT
      LAYER M5 ;
        RECT  44.304 0 44.328 0.084 ;
    END
  END i_s3[83]
  PIN i_s3[84]
    DIRECTION INPUT ;
    USE SIGNAL ;
    PORT
      LAYER M5 ;
        RECT  44.4 0 44.424 0.084 ;
    END
  END i_s3[84]
  PIN i_s3[85]
    DIRECTION INPUT ;
    USE SIGNAL ;
    PORT
      LAYER M5 ;
        RECT  44.496 0 44.52 0.084 ;
    END
  END i_s3[85]
  PIN i_s3[86]
    DIRECTION INPUT ;
    USE SIGNAL ;
    PORT
      LAYER M5 ;
        RECT  44.592 0 44.616 0.084 ;
    END
  END i_s3[86]
  PIN i_s3[87]
    DIRECTION INPUT ;
    USE SIGNAL ;
    PORT
      LAYER M5 ;
        RECT  44.688 0 44.712 0.084 ;
    END
  END i_s3[87]
  PIN i_s3[88]
    DIRECTION INPUT ;
    USE SIGNAL ;
    PORT
      LAYER M5 ;
        RECT  44.784 0 44.808 0.084 ;
    END
  END i_s3[88]
  PIN i_s3[89]
    DIRECTION INPUT ;
    USE SIGNAL ;
    PORT
      LAYER M5 ;
        RECT  44.88 0 44.904 0.084 ;
    END
  END i_s3[89]
  PIN i_s3[8]
    DIRECTION INPUT ;
    USE SIGNAL ;
    PORT
      LAYER M5 ;
        RECT  52.464 0 52.488 0.084 ;
    END
  END i_s3[8]
  PIN i_s3[90]
    DIRECTION INPUT ;
    USE SIGNAL ;
    PORT
      LAYER M5 ;
        RECT  44.976 0 45 0.084 ;
    END
  END i_s3[90]
  PIN i_s3[91]
    DIRECTION INPUT ;
    USE SIGNAL ;
    PORT
      LAYER M5 ;
        RECT  45.072 0 45.096 0.084 ;
    END
  END i_s3[91]
  PIN i_s3[92]
    DIRECTION INPUT ;
    USE SIGNAL ;
    PORT
      LAYER M5 ;
        RECT  45.168 0 45.192 0.084 ;
    END
  END i_s3[92]
  PIN i_s3[93]
    DIRECTION INPUT ;
    USE SIGNAL ;
    PORT
      LAYER M5 ;
        RECT  61.392 0 61.416 0.084 ;
    END
  END i_s3[93]
  PIN i_s3[94]
    DIRECTION INPUT ;
    USE SIGNAL ;
    PORT
      LAYER M5 ;
        RECT  61.488 0 61.512 0.084 ;
    END
  END i_s3[94]
  PIN i_s3[95]
    DIRECTION INPUT ;
    USE SIGNAL ;
    PORT
      LAYER M5 ;
        RECT  61.584 0 61.608 0.084 ;
    END
  END i_s3[95]
  PIN i_s3[96]
    DIRECTION INPUT ;
    USE SIGNAL ;
    PORT
      LAYER M5 ;
        RECT  61.68 0 61.704 0.084 ;
    END
  END i_s3[96]
  PIN i_s3[97]
    DIRECTION INPUT ;
    USE SIGNAL ;
    PORT
      LAYER M5 ;
        RECT  61.776 0 61.8 0.084 ;
    END
  END i_s3[97]
  PIN i_s3[98]
    DIRECTION INPUT ;
    USE SIGNAL ;
    PORT
      LAYER M5 ;
        RECT  61.872 0 61.896 0.084 ;
    END
  END i_s3[98]
  PIN i_s3[99]
    DIRECTION INPUT ;
    USE SIGNAL ;
    PORT
      LAYER M5 ;
        RECT  61.968 0 61.992 0.084 ;
    END
  END i_s3[99]
  PIN i_s3[9]
    DIRECTION INPUT ;
    USE SIGNAL ;
    PORT
      LAYER M5 ;
        RECT  52.56 0 52.584 0.084 ;
    END
  END i_s3[9]
  PIN i_s3_v
    DIRECTION INPUT ;
    USE SIGNAL ;
    PORT
      LAYER M5 ;
        RECT  48.432 0 48.456 0.084 ;
    END
  END i_s3_v
  PIN i_wbad
    DIRECTION INPUT ;
    USE SIGNAL ;
    PORT
      LAYER M5 ;
        RECT  70.032 77.676 70.056 77.76 ;
    END
  END i_wbad
  PIN i_widle
    DIRECTION INPUT ;
    USE SIGNAL ;
    PORT
      LAYER M5 ;
        RECT  70.128 77.676 70.152 77.76 ;
    END
  END i_widle
  PIN o_act
    DIRECTION OUTPUT ;
    USE SIGNAL ;
    PORT
      LAYER M5 ;
        RECT  70.224 77.676 70.248 77.76 ;
    END
  END o_act
  PIN ret[0]
    DIRECTION OUTPUT ;
    USE SIGNAL ;
    PORT
      LAYER M5 ;
        RECT  48.528 0 48.552 0.084 ;
    END
  END ret[0]
  PIN ret[1]
    DIRECTION OUTPUT ;
    USE SIGNAL ;
    PORT
      LAYER M5 ;
        RECT  48.624 0 48.648 0.084 ;
    END
  END ret[1]
  PIN ret[2]
    DIRECTION OUTPUT ;
    USE SIGNAL ;
    PORT
      LAYER M5 ;
        RECT  48.72 0 48.744 0.084 ;
    END
  END ret[2]
  PIN rg_gnt
    DIRECTION INPUT ;
    USE SIGNAL ;
    PORT
      LAYER M4 ;
        RECT  0 61.68 0.084 61.704 ;
    END
  END rg_gnt
  PIN rg_req
    DIRECTION OUTPUT ;
    USE SIGNAL ;
    PORT
      LAYER M4 ;
        RECT  0 61.776 0.084 61.8 ;
    END
  END rg_req
  PIN rst_n
    DIRECTION INPUT ;
    USE SIGNAL ;
    PORT
      LAYER M5 ;
        RECT  48.816 0 48.84 0.084 ;
    END
  END rst_n
  PIN wrq[0]
    DIRECTION OUTPUT ;
    USE SIGNAL ;
    PORT
      LAYER M4 ;
        RECT  0 61.872 0.084 61.896 ;
    END
  END wrq[0]
  PIN wrq[100]
    DIRECTION OUTPUT ;
    USE SIGNAL ;
    PORT
      LAYER M4 ;
        RECT  0 65.328 0.084 65.352 ;
    END
  END wrq[100]
  PIN wrq[101]
    DIRECTION OUTPUT ;
    USE SIGNAL ;
    PORT
      LAYER M4 ;
        RECT  0 65.424 0.084 65.448 ;
    END
  END wrq[101]
  PIN wrq[102]
    DIRECTION OUTPUT ;
    USE SIGNAL ;
    PORT
      LAYER M4 ;
        RECT  0 65.52 0.084 65.544 ;
    END
  END wrq[102]
  PIN wrq[103]
    DIRECTION OUTPUT ;
    USE SIGNAL ;
    PORT
      LAYER M4 ;
        RECT  0 65.616 0.084 65.64 ;
    END
  END wrq[103]
  PIN wrq[104]
    DIRECTION OUTPUT ;
    USE SIGNAL ;
    PORT
      LAYER M4 ;
        RECT  0 65.712 0.084 65.736 ;
    END
  END wrq[104]
  PIN wrq[105]
    DIRECTION OUTPUT ;
    USE SIGNAL ;
    PORT
      LAYER M4 ;
        RECT  0 65.808 0.084 65.832 ;
    END
  END wrq[105]
  PIN wrq[106]
    DIRECTION OUTPUT ;
    USE SIGNAL ;
    PORT
      LAYER M4 ;
        RECT  0 65.904 0.084 65.928 ;
    END
  END wrq[106]
  PIN wrq[107]
    DIRECTION OUTPUT ;
    USE SIGNAL ;
    PORT
      LAYER M4 ;
        RECT  0 66 0.084 66.024 ;
    END
  END wrq[107]
  PIN wrq[108]
    DIRECTION OUTPUT ;
    USE SIGNAL ;
    PORT
      LAYER M4 ;
        RECT  0 66.096 0.084 66.12 ;
    END
  END wrq[108]
  PIN wrq[109]
    DIRECTION OUTPUT ;
    USE SIGNAL ;
    PORT
      LAYER M4 ;
        RECT  0 66.192 0.084 66.216 ;
    END
  END wrq[109]
  PIN wrq[10]
    DIRECTION OUTPUT ;
    USE SIGNAL ;
    PORT
      LAYER M4 ;
        RECT  0 62.832 0.084 62.856 ;
    END
  END wrq[10]
  PIN wrq[110]
    DIRECTION OUTPUT ;
    USE SIGNAL ;
    PORT
      LAYER M4 ;
        RECT  0 66.288 0.084 66.312 ;
    END
  END wrq[110]
  PIN wrq[111]
    DIRECTION OUTPUT ;
    USE SIGNAL ;
    PORT
      LAYER M4 ;
        RECT  0 66.384 0.084 66.408 ;
    END
  END wrq[111]
  PIN wrq[112]
    DIRECTION OUTPUT ;
    USE SIGNAL ;
    PORT
      LAYER M4 ;
        RECT  0 66.48 0.084 66.504 ;
    END
  END wrq[112]
  PIN wrq[113]
    DIRECTION OUTPUT ;
    USE SIGNAL ;
    PORT
      LAYER M4 ;
        RECT  0 66.576 0.084 66.6 ;
    END
  END wrq[113]
  PIN wrq[114]
    DIRECTION OUTPUT ;
    USE SIGNAL ;
    PORT
      LAYER M4 ;
        RECT  0 66.672 0.084 66.696 ;
    END
  END wrq[114]
  PIN wrq[115]
    DIRECTION OUTPUT ;
    USE SIGNAL ;
    PORT
      LAYER M4 ;
        RECT  0 66.768 0.084 66.792 ;
    END
  END wrq[115]
  PIN wrq[116]
    DIRECTION OUTPUT ;
    USE SIGNAL ;
    PORT
      LAYER M4 ;
        RECT  0 66.864 0.084 66.888 ;
    END
  END wrq[116]
  PIN wrq[117]
    DIRECTION OUTPUT ;
    USE SIGNAL ;
    PORT
      LAYER M4 ;
        RECT  0 66.96 0.084 66.984 ;
    END
  END wrq[117]
  PIN wrq[118]
    DIRECTION OUTPUT ;
    USE SIGNAL ;
    PORT
      LAYER M4 ;
        RECT  0 67.056 0.084 67.08 ;
    END
  END wrq[118]
  PIN wrq[119]
    DIRECTION OUTPUT ;
    USE SIGNAL ;
    PORT
      LAYER M4 ;
        RECT  0 67.152 0.084 67.176 ;
    END
  END wrq[119]
  PIN wrq[11]
    DIRECTION OUTPUT ;
    USE SIGNAL ;
    PORT
      LAYER M4 ;
        RECT  0 62.928 0.084 62.952 ;
    END
  END wrq[11]
  PIN wrq[120]
    DIRECTION OUTPUT ;
    USE SIGNAL ;
    PORT
      LAYER M4 ;
        RECT  0 67.248 0.084 67.272 ;
    END
  END wrq[120]
  PIN wrq[121]
    DIRECTION OUTPUT ;
    USE SIGNAL ;
    PORT
      LAYER M4 ;
        RECT  0 67.344 0.084 67.368 ;
    END
  END wrq[121]
  PIN wrq[122]
    DIRECTION OUTPUT ;
    USE SIGNAL ;
    PORT
      LAYER M4 ;
        RECT  0 67.44 0.084 67.464 ;
    END
  END wrq[122]
  PIN wrq[123]
    DIRECTION OUTPUT ;
    USE SIGNAL ;
    PORT
      LAYER M4 ;
        RECT  0 67.536 0.084 67.56 ;
    END
  END wrq[123]
  PIN wrq[124]
    DIRECTION OUTPUT ;
    USE SIGNAL ;
    PORT
      LAYER M4 ;
        RECT  0 67.632 0.084 67.656 ;
    END
  END wrq[124]
  PIN wrq[125]
    DIRECTION OUTPUT ;
    USE SIGNAL ;
    PORT
      LAYER M4 ;
        RECT  0 67.728 0.084 67.752 ;
    END
  END wrq[125]
  PIN wrq[126]
    DIRECTION OUTPUT ;
    USE SIGNAL ;
    PORT
      LAYER M4 ;
        RECT  0 73.008 0.084 73.032 ;
    END
  END wrq[126]
  PIN wrq[127]
    DIRECTION OUTPUT ;
    USE SIGNAL ;
    PORT
      LAYER M4 ;
        RECT  0 73.104 0.084 73.128 ;
    END
  END wrq[127]
  PIN wrq[12]
    DIRECTION OUTPUT ;
    USE SIGNAL ;
    PORT
      LAYER M4 ;
        RECT  0 63.024 0.084 63.048 ;
    END
  END wrq[12]
  PIN wrq[13]
    DIRECTION OUTPUT ;
    USE SIGNAL ;
    PORT
      LAYER M4 ;
        RECT  0 63.12 0.084 63.144 ;
    END
  END wrq[13]
  PIN wrq[14]
    DIRECTION OUTPUT ;
    USE SIGNAL ;
    PORT
      LAYER M4 ;
        RECT  0 63.216 0.084 63.24 ;
    END
  END wrq[14]
  PIN wrq[15]
    DIRECTION OUTPUT ;
    USE SIGNAL ;
    PORT
      LAYER M4 ;
        RECT  0 63.312 0.084 63.336 ;
    END
  END wrq[15]
  PIN wrq[16]
    DIRECTION OUTPUT ;
    USE SIGNAL ;
    PORT
      LAYER M4 ;
        RECT  0 63.408 0.084 63.432 ;
    END
  END wrq[16]
  PIN wrq[17]
    DIRECTION OUTPUT ;
    USE SIGNAL ;
    PORT
      LAYER M4 ;
        RECT  0 63.504 0.084 63.528 ;
    END
  END wrq[17]
  PIN wrq[18]
    DIRECTION OUTPUT ;
    USE SIGNAL ;
    PORT
      LAYER M4 ;
        RECT  0 63.6 0.084 63.624 ;
    END
  END wrq[18]
  PIN wrq[19]
    DIRECTION OUTPUT ;
    USE SIGNAL ;
    PORT
      LAYER M4 ;
        RECT  0 63.696 0.084 63.72 ;
    END
  END wrq[19]
  PIN wrq[1]
    DIRECTION OUTPUT ;
    USE SIGNAL ;
    PORT
      LAYER M4 ;
        RECT  0 61.968 0.084 61.992 ;
    END
  END wrq[1]
  PIN wrq[20]
    DIRECTION OUTPUT ;
    USE SIGNAL ;
    PORT
      LAYER M4 ;
        RECT  0 63.792 0.084 63.816 ;
    END
  END wrq[20]
  PIN wrq[21]
    DIRECTION OUTPUT ;
    USE SIGNAL ;
    PORT
      LAYER M4 ;
        RECT  0 63.888 0.084 63.912 ;
    END
  END wrq[21]
  PIN wrq[22]
    DIRECTION OUTPUT ;
    USE SIGNAL ;
    PORT
      LAYER M4 ;
        RECT  0 63.984 0.084 64.008 ;
    END
  END wrq[22]
  PIN wrq[23]
    DIRECTION OUTPUT ;
    USE SIGNAL ;
    PORT
      LAYER M4 ;
        RECT  0 64.08 0.084 64.104 ;
    END
  END wrq[23]
  PIN wrq[24]
    DIRECTION OUTPUT ;
    USE SIGNAL ;
    PORT
      LAYER M4 ;
        RECT  0 64.176 0.084 64.2 ;
    END
  END wrq[24]
  PIN wrq[25]
    DIRECTION OUTPUT ;
    USE SIGNAL ;
    PORT
      LAYER M4 ;
        RECT  0 64.272 0.084 64.296 ;
    END
  END wrq[25]
  PIN wrq[26]
    DIRECTION OUTPUT ;
    USE SIGNAL ;
    PORT
      LAYER M4 ;
        RECT  0 64.368 0.084 64.392 ;
    END
  END wrq[26]
  PIN wrq[27]
    DIRECTION OUTPUT ;
    USE SIGNAL ;
    PORT
      LAYER M4 ;
        RECT  0 64.464 0.084 64.488 ;
    END
  END wrq[27]
  PIN wrq[28]
    DIRECTION OUTPUT ;
    USE SIGNAL ;
    PORT
      LAYER M4 ;
        RECT  0 64.56 0.084 64.584 ;
    END
  END wrq[28]
  PIN wrq[29]
    DIRECTION OUTPUT ;
    USE SIGNAL ;
    PORT
      LAYER M4 ;
        RECT  0 64.656 0.084 64.68 ;
    END
  END wrq[29]
  PIN wrq[2]
    DIRECTION OUTPUT ;
    USE SIGNAL ;
    PORT
      LAYER M4 ;
        RECT  0 62.064 0.084 62.088 ;
    END
  END wrq[2]
  PIN wrq[30]
    DIRECTION OUTPUT ;
    USE SIGNAL ;
    PORT
      LAYER M4 ;
        RECT  0 67.824 0.084 67.848 ;
    END
  END wrq[30]
  PIN wrq[31]
    DIRECTION OUTPUT ;
    USE SIGNAL ;
    PORT
      LAYER M4 ;
        RECT  0 67.92 0.084 67.944 ;
    END
  END wrq[31]
  PIN wrq[32]
    DIRECTION OUTPUT ;
    USE SIGNAL ;
    PORT
      LAYER M4 ;
        RECT  0 68.016 0.084 68.04 ;
    END
  END wrq[32]
  PIN wrq[33]
    DIRECTION OUTPUT ;
    USE SIGNAL ;
    PORT
      LAYER M4 ;
        RECT  0 68.112 0.084 68.136 ;
    END
  END wrq[33]
  PIN wrq[34]
    DIRECTION OUTPUT ;
    USE SIGNAL ;
    PORT
      LAYER M4 ;
        RECT  0 68.208 0.084 68.232 ;
    END
  END wrq[34]
  PIN wrq[35]
    DIRECTION OUTPUT ;
    USE SIGNAL ;
    PORT
      LAYER M4 ;
        RECT  0 68.304 0.084 68.328 ;
    END
  END wrq[35]
  PIN wrq[36]
    DIRECTION OUTPUT ;
    USE SIGNAL ;
    PORT
      LAYER M4 ;
        RECT  0 68.4 0.084 68.424 ;
    END
  END wrq[36]
  PIN wrq[37]
    DIRECTION OUTPUT ;
    USE SIGNAL ;
    PORT
      LAYER M4 ;
        RECT  0 68.496 0.084 68.52 ;
    END
  END wrq[37]
  PIN wrq[38]
    DIRECTION OUTPUT ;
    USE SIGNAL ;
    PORT
      LAYER M4 ;
        RECT  0 68.592 0.084 68.616 ;
    END
  END wrq[38]
  PIN wrq[39]
    DIRECTION OUTPUT ;
    USE SIGNAL ;
    PORT
      LAYER M4 ;
        RECT  0 68.688 0.084 68.712 ;
    END
  END wrq[39]
  PIN wrq[3]
    DIRECTION OUTPUT ;
    USE SIGNAL ;
    PORT
      LAYER M4 ;
        RECT  0 62.16 0.084 62.184 ;
    END
  END wrq[3]
  PIN wrq[40]
    DIRECTION OUTPUT ;
    USE SIGNAL ;
    PORT
      LAYER M4 ;
        RECT  0 68.784 0.084 68.808 ;
    END
  END wrq[40]
  PIN wrq[41]
    DIRECTION OUTPUT ;
    USE SIGNAL ;
    PORT
      LAYER M4 ;
        RECT  0 68.88 0.084 68.904 ;
    END
  END wrq[41]
  PIN wrq[42]
    DIRECTION OUTPUT ;
    USE SIGNAL ;
    PORT
      LAYER M4 ;
        RECT  0 68.976 0.084 69 ;
    END
  END wrq[42]
  PIN wrq[43]
    DIRECTION OUTPUT ;
    USE SIGNAL ;
    PORT
      LAYER M4 ;
        RECT  0 69.072 0.084 69.096 ;
    END
  END wrq[43]
  PIN wrq[44]
    DIRECTION OUTPUT ;
    USE SIGNAL ;
    PORT
      LAYER M4 ;
        RECT  0 69.168 0.084 69.192 ;
    END
  END wrq[44]
  PIN wrq[45]
    DIRECTION OUTPUT ;
    USE SIGNAL ;
    PORT
      LAYER M4 ;
        RECT  0 69.264 0.084 69.288 ;
    END
  END wrq[45]
  PIN wrq[46]
    DIRECTION OUTPUT ;
    USE SIGNAL ;
    PORT
      LAYER M4 ;
        RECT  0 69.36 0.084 69.384 ;
    END
  END wrq[46]
  PIN wrq[47]
    DIRECTION OUTPUT ;
    USE SIGNAL ;
    PORT
      LAYER M4 ;
        RECT  0 69.456 0.084 69.48 ;
    END
  END wrq[47]
  PIN wrq[48]
    DIRECTION OUTPUT ;
    USE SIGNAL ;
    PORT
      LAYER M4 ;
        RECT  0 69.552 0.084 69.576 ;
    END
  END wrq[48]
  PIN wrq[49]
    DIRECTION OUTPUT ;
    USE SIGNAL ;
    PORT
      LAYER M4 ;
        RECT  0 69.648 0.084 69.672 ;
    END
  END wrq[49]
  PIN wrq[4]
    DIRECTION OUTPUT ;
    USE SIGNAL ;
    PORT
      LAYER M4 ;
        RECT  0 62.256 0.084 62.28 ;
    END
  END wrq[4]
  PIN wrq[50]
    DIRECTION OUTPUT ;
    USE SIGNAL ;
    PORT
      LAYER M4 ;
        RECT  0 69.744 0.084 69.768 ;
    END
  END wrq[50]
  PIN wrq[51]
    DIRECTION OUTPUT ;
    USE SIGNAL ;
    PORT
      LAYER M4 ;
        RECT  0 69.84 0.084 69.864 ;
    END
  END wrq[51]
  PIN wrq[52]
    DIRECTION OUTPUT ;
    USE SIGNAL ;
    PORT
      LAYER M4 ;
        RECT  0 69.936 0.084 69.96 ;
    END
  END wrq[52]
  PIN wrq[53]
    DIRECTION OUTPUT ;
    USE SIGNAL ;
    PORT
      LAYER M4 ;
        RECT  0 70.032 0.084 70.056 ;
    END
  END wrq[53]
  PIN wrq[54]
    DIRECTION OUTPUT ;
    USE SIGNAL ;
    PORT
      LAYER M4 ;
        RECT  0 70.128 0.084 70.152 ;
    END
  END wrq[54]
  PIN wrq[55]
    DIRECTION OUTPUT ;
    USE SIGNAL ;
    PORT
      LAYER M4 ;
        RECT  0 70.224 0.084 70.248 ;
    END
  END wrq[55]
  PIN wrq[56]
    DIRECTION OUTPUT ;
    USE SIGNAL ;
    PORT
      LAYER M4 ;
        RECT  0 70.32 0.084 70.344 ;
    END
  END wrq[56]
  PIN wrq[57]
    DIRECTION OUTPUT ;
    USE SIGNAL ;
    PORT
      LAYER M4 ;
        RECT  0 70.416 0.084 70.44 ;
    END
  END wrq[57]
  PIN wrq[58]
    DIRECTION OUTPUT ;
    USE SIGNAL ;
    PORT
      LAYER M4 ;
        RECT  0 70.512 0.084 70.536 ;
    END
  END wrq[58]
  PIN wrq[59]
    DIRECTION OUTPUT ;
    USE SIGNAL ;
    PORT
      LAYER M4 ;
        RECT  0 70.608 0.084 70.632 ;
    END
  END wrq[59]
  PIN wrq[5]
    DIRECTION OUTPUT ;
    USE SIGNAL ;
    PORT
      LAYER M4 ;
        RECT  0 62.352 0.084 62.376 ;
    END
  END wrq[5]
  PIN wrq[60]
    DIRECTION OUTPUT ;
    USE SIGNAL ;
    PORT
      LAYER M4 ;
        RECT  0 70.704 0.084 70.728 ;
    END
  END wrq[60]
  PIN wrq[61]
    DIRECTION OUTPUT ;
    USE SIGNAL ;
    PORT
      LAYER M4 ;
        RECT  0 70.8 0.084 70.824 ;
    END
  END wrq[61]
  PIN wrq[62]
    DIRECTION OUTPUT ;
    USE SIGNAL ;
    PORT
      LAYER M4 ;
        RECT  0 58.608 0.084 58.632 ;
    END
  END wrq[62]
  PIN wrq[63]
    DIRECTION OUTPUT ;
    USE SIGNAL ;
    PORT
      LAYER M4 ;
        RECT  0 58.704 0.084 58.728 ;
    END
  END wrq[63]
  PIN wrq[64]
    DIRECTION OUTPUT ;
    USE SIGNAL ;
    PORT
      LAYER M4 ;
        RECT  0 58.8 0.084 58.824 ;
    END
  END wrq[64]
  PIN wrq[65]
    DIRECTION OUTPUT ;
    USE SIGNAL ;
    PORT
      LAYER M4 ;
        RECT  0 58.896 0.084 58.92 ;
    END
  END wrq[65]
  PIN wrq[66]
    DIRECTION OUTPUT ;
    USE SIGNAL ;
    PORT
      LAYER M4 ;
        RECT  0 58.992 0.084 59.016 ;
    END
  END wrq[66]
  PIN wrq[67]
    DIRECTION OUTPUT ;
    USE SIGNAL ;
    PORT
      LAYER M4 ;
        RECT  0 59.088 0.084 59.112 ;
    END
  END wrq[67]
  PIN wrq[68]
    DIRECTION OUTPUT ;
    USE SIGNAL ;
    PORT
      LAYER M4 ;
        RECT  0 59.184 0.084 59.208 ;
    END
  END wrq[68]
  PIN wrq[69]
    DIRECTION OUTPUT ;
    USE SIGNAL ;
    PORT
      LAYER M4 ;
        RECT  0 59.28 0.084 59.304 ;
    END
  END wrq[69]
  PIN wrq[6]
    DIRECTION OUTPUT ;
    USE SIGNAL ;
    PORT
      LAYER M4 ;
        RECT  0 62.448 0.084 62.472 ;
    END
  END wrq[6]
  PIN wrq[70]
    DIRECTION OUTPUT ;
    USE SIGNAL ;
    PORT
      LAYER M4 ;
        RECT  0 59.376 0.084 59.4 ;
    END
  END wrq[70]
  PIN wrq[71]
    DIRECTION OUTPUT ;
    USE SIGNAL ;
    PORT
      LAYER M4 ;
        RECT  0 59.472 0.084 59.496 ;
    END
  END wrq[71]
  PIN wrq[72]
    DIRECTION OUTPUT ;
    USE SIGNAL ;
    PORT
      LAYER M4 ;
        RECT  0 59.568 0.084 59.592 ;
    END
  END wrq[72]
  PIN wrq[73]
    DIRECTION OUTPUT ;
    USE SIGNAL ;
    PORT
      LAYER M4 ;
        RECT  0 59.664 0.084 59.688 ;
    END
  END wrq[73]
  PIN wrq[74]
    DIRECTION OUTPUT ;
    USE SIGNAL ;
    PORT
      LAYER M4 ;
        RECT  0 59.76 0.084 59.784 ;
    END
  END wrq[74]
  PIN wrq[75]
    DIRECTION OUTPUT ;
    USE SIGNAL ;
    PORT
      LAYER M4 ;
        RECT  0 59.856 0.084 59.88 ;
    END
  END wrq[75]
  PIN wrq[76]
    DIRECTION OUTPUT ;
    USE SIGNAL ;
    PORT
      LAYER M4 ;
        RECT  0 59.952 0.084 59.976 ;
    END
  END wrq[76]
  PIN wrq[77]
    DIRECTION OUTPUT ;
    USE SIGNAL ;
    PORT
      LAYER M4 ;
        RECT  0 60.048 0.084 60.072 ;
    END
  END wrq[77]
  PIN wrq[78]
    DIRECTION OUTPUT ;
    USE SIGNAL ;
    PORT
      LAYER M4 ;
        RECT  0 60.144 0.084 60.168 ;
    END
  END wrq[78]
  PIN wrq[79]
    DIRECTION OUTPUT ;
    USE SIGNAL ;
    PORT
      LAYER M4 ;
        RECT  0 60.24 0.084 60.264 ;
    END
  END wrq[79]
  PIN wrq[7]
    DIRECTION OUTPUT ;
    USE SIGNAL ;
    PORT
      LAYER M4 ;
        RECT  0 62.544 0.084 62.568 ;
    END
  END wrq[7]
  PIN wrq[80]
    DIRECTION OUTPUT ;
    USE SIGNAL ;
    PORT
      LAYER M4 ;
        RECT  0 60.336 0.084 60.36 ;
    END
  END wrq[80]
  PIN wrq[81]
    DIRECTION OUTPUT ;
    USE SIGNAL ;
    PORT
      LAYER M4 ;
        RECT  0 60.432 0.084 60.456 ;
    END
  END wrq[81]
  PIN wrq[82]
    DIRECTION OUTPUT ;
    USE SIGNAL ;
    PORT
      LAYER M4 ;
        RECT  0 60.528 0.084 60.552 ;
    END
  END wrq[82]
  PIN wrq[83]
    DIRECTION OUTPUT ;
    USE SIGNAL ;
    PORT
      LAYER M4 ;
        RECT  0 60.624 0.084 60.648 ;
    END
  END wrq[83]
  PIN wrq[84]
    DIRECTION OUTPUT ;
    USE SIGNAL ;
    PORT
      LAYER M4 ;
        RECT  0 60.72 0.084 60.744 ;
    END
  END wrq[84]
  PIN wrq[85]
    DIRECTION OUTPUT ;
    USE SIGNAL ;
    PORT
      LAYER M4 ;
        RECT  0 60.816 0.084 60.84 ;
    END
  END wrq[85]
  PIN wrq[86]
    DIRECTION OUTPUT ;
    USE SIGNAL ;
    PORT
      LAYER M4 ;
        RECT  0 60.912 0.084 60.936 ;
    END
  END wrq[86]
  PIN wrq[87]
    DIRECTION OUTPUT ;
    USE SIGNAL ;
    PORT
      LAYER M4 ;
        RECT  0 61.008 0.084 61.032 ;
    END
  END wrq[87]
  PIN wrq[88]
    DIRECTION OUTPUT ;
    USE SIGNAL ;
    PORT
      LAYER M4 ;
        RECT  0 61.104 0.084 61.128 ;
    END
  END wrq[88]
  PIN wrq[89]
    DIRECTION OUTPUT ;
    USE SIGNAL ;
    PORT
      LAYER M4 ;
        RECT  0 61.2 0.084 61.224 ;
    END
  END wrq[89]
  PIN wrq[8]
    DIRECTION OUTPUT ;
    USE SIGNAL ;
    PORT
      LAYER M4 ;
        RECT  0 62.64 0.084 62.664 ;
    END
  END wrq[8]
  PIN wrq[90]
    DIRECTION OUTPUT ;
    USE SIGNAL ;
    PORT
      LAYER M4 ;
        RECT  0 61.296 0.084 61.32 ;
    END
  END wrq[90]
  PIN wrq[91]
    DIRECTION OUTPUT ;
    USE SIGNAL ;
    PORT
      LAYER M4 ;
        RECT  0 61.392 0.084 61.416 ;
    END
  END wrq[91]
  PIN wrq[92]
    DIRECTION OUTPUT ;
    USE SIGNAL ;
    PORT
      LAYER M4 ;
        RECT  0 61.488 0.084 61.512 ;
    END
  END wrq[92]
  PIN wrq[93]
    DIRECTION OUTPUT ;
    USE SIGNAL ;
    PORT
      LAYER M4 ;
        RECT  0 61.584 0.084 61.608 ;
    END
  END wrq[93]
  PIN wrq[94]
    DIRECTION OUTPUT ;
    USE SIGNAL ;
    PORT
      LAYER M4 ;
        RECT  0 64.752 0.084 64.776 ;
    END
  END wrq[94]
  PIN wrq[95]
    DIRECTION OUTPUT ;
    USE SIGNAL ;
    PORT
      LAYER M4 ;
        RECT  0 64.848 0.084 64.872 ;
    END
  END wrq[95]
  PIN wrq[96]
    DIRECTION OUTPUT ;
    USE SIGNAL ;
    PORT
      LAYER M4 ;
        RECT  0 64.944 0.084 64.968 ;
    END
  END wrq[96]
  PIN wrq[97]
    DIRECTION OUTPUT ;
    USE SIGNAL ;
    PORT
      LAYER M4 ;
        RECT  0 65.04 0.084 65.064 ;
    END
  END wrq[97]
  PIN wrq[98]
    DIRECTION OUTPUT ;
    USE SIGNAL ;
    PORT
      LAYER M4 ;
        RECT  0 65.136 0.084 65.16 ;
    END
  END wrq[98]
  PIN wrq[99]
    DIRECTION OUTPUT ;
    USE SIGNAL ;
    PORT
      LAYER M4 ;
        RECT  0 65.232 0.084 65.256 ;
    END
  END wrq[99]
  PIN wrq[9]
    DIRECTION OUTPUT ;
    USE SIGNAL ;
    PORT
      LAYER M4 ;
        RECT  0 62.736 0.084 62.76 ;
    END
  END wrq[9]
  PIN wrq_cr[0]
    DIRECTION INPUT ;
    USE SIGNAL ;
    PORT
      LAYER M4 ;
        RECT  0 73.2 0.084 73.224 ;
    END
  END wrq_cr[0]
  PIN wrq_cr[1]
    DIRECTION INPUT ;
    USE SIGNAL ;
    PORT
      LAYER M4 ;
        RECT  0 73.296 0.084 73.32 ;
    END
  END wrq_cr[1]
  PIN wrq_cr[2]
    DIRECTION INPUT ;
    USE SIGNAL ;
    PORT
      LAYER M4 ;
        RECT  0 73.392 0.084 73.416 ;
    END
  END wrq_cr[2]
  PIN wrq_cr[3]
    DIRECTION INPUT ;
    USE SIGNAL ;
    PORT
      LAYER M4 ;
        RECT  0 73.488 0.084 73.512 ;
    END
  END wrq_cr[3]
  PIN wrq_cr[4]
    DIRECTION INPUT ;
    USE SIGNAL ;
    PORT
      LAYER M4 ;
        RECT  0 73.584 0.084 73.608 ;
    END
  END wrq_cr[4]
  PIN wrq_cr[5]
    DIRECTION INPUT ;
    USE SIGNAL ;
    PORT
      LAYER M4 ;
        RECT  0 73.68 0.084 73.704 ;
    END
  END wrq_cr[5]
  PIN wrq_cr[6]
    DIRECTION INPUT ;
    USE SIGNAL ;
    PORT
      LAYER M4 ;
        RECT  0 73.776 0.084 73.8 ;
    END
  END wrq_cr[6]
  PIN wrq_cr[7]
    DIRECTION INPUT ;
    USE SIGNAL ;
    PORT
      LAYER M4 ;
        RECT  0 73.872 0.084 73.896 ;
    END
  END wrq_cr[7]
  PIN VDD
    DIRECTION INOUT ;
    USE POWER ;
    PORT
      LAYER M5 ;
        RECT  83.592 2.151 83.712 75.609 ;
        RECT  78.192 2.151 78.312 75.609 ;
        RECT  72.792 2.151 72.912 75.609 ;
        RECT  67.392 2.151 67.512 75.609 ;
        RECT  61.992 2.151 62.112 75.609 ;
        RECT  56.592 2.151 56.712 75.609 ;
        RECT  51.192 2.151 51.312 75.609 ;
        RECT  45.792 2.151 45.912 75.609 ;
        RECT  40.392 2.151 40.512 75.609 ;
        RECT  34.992 2.151 35.112 75.609 ;
        RECT  29.592 2.151 29.712 75.609 ;
        RECT  24.192 2.151 24.312 75.609 ;
        RECT  18.792 2.151 18.912 75.609 ;
        RECT  13.392 2.151 13.512 75.609 ;
        RECT  7.992 2.151 8.112 75.609 ;
        RECT  2.592 2.151 2.712 75.609 ;
    END
  END VDD
  PIN VSS
    DIRECTION INOUT ;
    USE GROUND ;
    PORT
      LAYER M5 ;
        RECT  83.4 2.137 83.52 75.623 ;
        RECT  78 2.137 78.12 75.623 ;
        RECT  72.6 2.137 72.72 75.623 ;
        RECT  67.2 2.137 67.32 75.623 ;
        RECT  61.8 2.137 61.92 75.623 ;
        RECT  56.4 2.137 56.52 75.623 ;
        RECT  51 2.137 51.12 75.623 ;
        RECT  45.6 2.137 45.72 75.623 ;
        RECT  40.2 2.137 40.32 75.623 ;
        RECT  34.8 2.137 34.92 75.623 ;
        RECT  29.4 2.137 29.52 75.623 ;
        RECT  24 2.137 24.12 75.623 ;
        RECT  18.6 2.137 18.72 75.623 ;
        RECT  13.2 2.137 13.32 75.623 ;
        RECT  7.8 2.137 7.92 75.623 ;
        RECT  2.4 2.137 2.52 75.623 ;
    END
  END VSS
  # OT_OBS_CLOSED layer=M5 d_um=1.536 added=846
  OBS
    LAYER RVTN ;
     RECT  2.16 2.16 84.24 2.295 ;
     RECT  2.16 2.565 84.24 2.835 ;
     RECT  2.16 3.105 84.24 3.375 ;
     RECT  2.16 3.645 84.24 3.915 ;
     RECT  2.16 4.185 84.24 4.455 ;
     RECT  2.16 4.725 84.24 4.995 ;
     RECT  2.16 5.265 84.24 5.535 ;
     RECT  2.16 5.805 84.24 6.075 ;
     RECT  2.16 6.345 84.24 6.615 ;
     RECT  2.16 6.885 84.24 7.155 ;
     RECT  2.16 7.425 84.24 7.695 ;
     RECT  2.16 7.965 84.24 8.235 ;
     RECT  2.16 8.505 84.24 8.775 ;
     RECT  2.16 9.045 84.24 9.315 ;
     RECT  2.16 9.585 84.24 9.855 ;
     RECT  2.16 10.125 84.24 10.395 ;
     RECT  2.16 10.665 84.24 10.935 ;
     RECT  2.16 11.205 84.24 11.475 ;
     RECT  2.16 11.745 84.24 12.015 ;
     RECT  2.16 12.285 84.24 12.555 ;
     RECT  2.16 12.825 84.24 13.095 ;
     RECT  2.16 13.365 84.24 13.635 ;
     RECT  2.16 13.905 84.24 14.175 ;
     RECT  2.16 14.445 84.24 14.715 ;
     RECT  2.16 14.985 84.24 15.255 ;
     RECT  2.16 15.525 84.24 15.795 ;
     RECT  2.16 16.065 84.24 16.335 ;
     RECT  2.16 16.605 84.24 16.875 ;
     RECT  2.16 17.145 84.24 17.415 ;
     RECT  2.16 17.685 84.24 17.955 ;
     RECT  2.16 18.225 84.24 18.495 ;
     RECT  2.16 18.765 84.24 19.035 ;
     RECT  2.16 19.305 84.24 19.575 ;
     RECT  2.16 19.845 84.24 20.115 ;
     RECT  2.16 20.385 84.24 20.655 ;
     RECT  2.16 20.925 84.24 21.195 ;
     RECT  2.16 21.465 84.24 21.735 ;
     RECT  2.16 22.005 84.24 22.275 ;
     RECT  2.16 22.545 84.24 22.815 ;
     RECT  2.16 23.085 84.24 23.355 ;
     RECT  2.16 23.625 84.24 23.895 ;
     RECT  2.16 24.165 84.24 24.435 ;
     RECT  2.16 24.705 84.24 24.975 ;
     RECT  2.16 25.245 84.24 25.515 ;
     RECT  2.16 25.785 84.24 26.055 ;
     RECT  2.16 26.325 84.24 26.595 ;
     RECT  2.16 26.865 84.24 27.135 ;
     RECT  2.16 27.405 84.24 27.675 ;
     RECT  2.16 27.945 84.24 28.215 ;
     RECT  2.16 28.485 84.24 28.755 ;
     RECT  2.16 29.025 84.24 29.295 ;
     RECT  2.16 29.565 84.24 29.835 ;
     RECT  2.16 30.105 84.24 30.375 ;
     RECT  2.16 30.645 84.24 30.915 ;
     RECT  2.16 31.185 84.24 31.455 ;
     RECT  2.16 31.725 84.24 31.995 ;
     RECT  2.16 32.265 84.24 32.535 ;
     RECT  2.16 32.805 84.24 33.075 ;
     RECT  2.16 33.345 84.24 33.615 ;
     RECT  2.16 33.885 84.24 34.155 ;
     RECT  2.16 34.425 84.24 34.695 ;
     RECT  2.16 34.965 84.24 35.235 ;
     RECT  2.16 35.505 84.24 35.775 ;
     RECT  2.16 36.045 84.24 36.315 ;
     RECT  2.16 36.585 84.24 36.855 ;
     RECT  2.16 37.125 84.24 37.395 ;
     RECT  2.16 37.665 84.24 37.935 ;
     RECT  2.16 38.205 84.24 38.475 ;
     RECT  2.16 38.745 84.24 39.015 ;
     RECT  2.16 39.285 84.24 39.555 ;
     RECT  2.16 39.825 84.24 40.095 ;
     RECT  2.16 40.365 84.24 40.635 ;
     RECT  2.16 40.905 84.24 41.175 ;
     RECT  2.16 41.445 84.24 41.715 ;
     RECT  2.16 41.985 84.24 42.255 ;
     RECT  2.16 42.525 84.24 42.795 ;
     RECT  2.16 43.065 84.24 43.335 ;
     RECT  2.16 43.605 84.24 43.875 ;
     RECT  2.16 44.145 84.24 44.415 ;
     RECT  2.16 44.685 84.24 44.955 ;
     RECT  2.16 45.225 84.24 45.495 ;
     RECT  2.16 45.765 84.24 46.035 ;
     RECT  2.16 46.305 84.24 46.575 ;
     RECT  2.16 46.845 84.24 47.115 ;
     RECT  2.16 47.385 84.24 47.655 ;
     RECT  2.16 47.925 84.24 48.195 ;
     RECT  2.16 48.465 84.24 48.735 ;
     RECT  2.16 49.005 84.24 49.275 ;
     RECT  2.16 49.545 84.24 49.815 ;
     RECT  2.16 50.085 84.24 50.355 ;
     RECT  2.16 50.625 84.24 50.895 ;
     RECT  2.16 51.165 84.24 51.435 ;
     RECT  2.16 51.705 84.24 51.975 ;
     RECT  2.16 52.245 84.24 52.515 ;
     RECT  2.16 52.785 84.24 53.055 ;
     RECT  2.16 53.325 84.24 53.595 ;
     RECT  2.16 53.865 84.24 54.135 ;
     RECT  2.16 54.405 84.24 54.675 ;
     RECT  2.16 54.945 84.24 55.215 ;
     RECT  2.16 55.485 84.24 55.755 ;
     RECT  2.16 56.025 84.24 56.295 ;
     RECT  2.16 56.565 84.24 56.835 ;
     RECT  2.16 57.105 84.24 57.375 ;
     RECT  2.16 57.645 84.24 57.915 ;
     RECT  2.16 58.185 84.24 58.455 ;
     RECT  2.16 58.725 84.24 58.995 ;
     RECT  2.16 59.265 84.24 59.535 ;
     RECT  2.16 59.805 84.24 60.075 ;
     RECT  2.16 60.345 84.24 60.615 ;
     RECT  2.16 60.885 84.24 61.155 ;
     RECT  2.16 61.425 84.24 61.695 ;
     RECT  2.16 61.965 84.24 62.235 ;
     RECT  2.16 62.505 84.24 62.775 ;
     RECT  2.16 63.045 84.24 63.315 ;
     RECT  2.16 63.585 84.24 63.855 ;
     RECT  2.16 64.125 84.24 64.395 ;
     RECT  2.16 64.665 84.24 64.935 ;
     RECT  2.16 65.205 84.24 65.475 ;
     RECT  2.16 65.745 84.24 66.015 ;
     RECT  2.16 66.285 84.24 66.555 ;
     RECT  2.16 66.825 84.24 67.095 ;
     RECT  2.16 67.365 84.24 67.635 ;
     RECT  2.16 67.905 84.24 68.175 ;
     RECT  2.16 68.445 84.24 68.715 ;
     RECT  2.16 68.985 84.24 69.255 ;
     RECT  2.16 69.525 84.24 69.795 ;
     RECT  2.16 70.065 84.24 70.335 ;
     RECT  2.16 70.605 84.24 70.875 ;
     RECT  2.16 71.145 84.24 71.415 ;
     RECT  2.16 71.685 84.24 71.955 ;
     RECT  2.16 72.225 84.24 72.495 ;
     RECT  2.16 72.765 84.24 73.035 ;
     RECT  2.16 73.305 84.24 73.575 ;
     RECT  2.16 73.845 84.24 74.115 ;
     RECT  2.16 74.385 84.24 74.655 ;
     RECT  2.16 74.925 84.24 75.195 ;
     RECT  2.16 75.465 84.24 75.6 ;
    LAYER RVTP ;
     RECT  2.16 2.295 84.24 2.565 ;
     RECT  2.16 2.835 84.24 3.105 ;
     RECT  2.16 3.375 84.24 3.645 ;
     RECT  2.16 3.915 84.24 4.185 ;
     RECT  2.16 4.455 84.24 4.725 ;
     RECT  2.16 4.995 84.24 5.265 ;
     RECT  2.16 5.535 84.24 5.805 ;
     RECT  2.16 6.075 84.24 6.345 ;
     RECT  2.16 6.615 84.24 6.885 ;
     RECT  2.16 7.155 84.24 7.425 ;
     RECT  2.16 7.695 84.24 7.965 ;
     RECT  2.16 8.235 84.24 8.505 ;
     RECT  2.16 8.775 84.24 9.045 ;
     RECT  2.16 9.315 84.24 9.585 ;
     RECT  2.16 9.855 84.24 10.125 ;
     RECT  2.16 10.395 84.24 10.665 ;
     RECT  2.16 10.935 84.24 11.205 ;
     RECT  2.16 11.475 84.24 11.745 ;
     RECT  2.16 12.015 84.24 12.285 ;
     RECT  2.16 12.555 84.24 12.825 ;
     RECT  2.16 13.095 84.24 13.365 ;
     RECT  2.16 13.635 84.24 13.905 ;
     RECT  2.16 14.175 84.24 14.445 ;
     RECT  2.16 14.715 84.24 14.985 ;
     RECT  2.16 15.255 84.24 15.525 ;
     RECT  2.16 15.795 84.24 16.065 ;
     RECT  2.16 16.335 84.24 16.605 ;
     RECT  2.16 16.875 84.24 17.145 ;
     RECT  2.16 17.415 84.24 17.685 ;
     RECT  2.16 17.955 84.24 18.225 ;
     RECT  2.16 18.495 84.24 18.765 ;
     RECT  2.16 19.035 84.24 19.305 ;
     RECT  2.16 19.575 84.24 19.845 ;
     RECT  2.16 20.115 84.24 20.385 ;
     RECT  2.16 20.655 84.24 20.925 ;
     RECT  2.16 21.195 84.24 21.465 ;
     RECT  2.16 21.735 84.24 22.005 ;
     RECT  2.16 22.275 84.24 22.545 ;
     RECT  2.16 22.815 84.24 23.085 ;
     RECT  2.16 23.355 84.24 23.625 ;
     RECT  2.16 23.895 84.24 24.165 ;
     RECT  2.16 24.435 84.24 24.705 ;
     RECT  2.16 24.975 84.24 25.245 ;
     RECT  2.16 25.515 84.24 25.785 ;
     RECT  2.16 26.055 84.24 26.325 ;
     RECT  2.16 26.595 84.24 26.865 ;
     RECT  2.16 27.135 84.24 27.405 ;
     RECT  2.16 27.675 84.24 27.945 ;
     RECT  2.16 28.215 84.24 28.485 ;
     RECT  2.16 28.755 84.24 29.025 ;
     RECT  2.16 29.295 84.24 29.565 ;
     RECT  2.16 29.835 84.24 30.105 ;
     RECT  2.16 30.375 84.24 30.645 ;
     RECT  2.16 30.915 84.24 31.185 ;
     RECT  2.16 31.455 84.24 31.725 ;
     RECT  2.16 31.995 84.24 32.265 ;
     RECT  2.16 32.535 84.24 32.805 ;
     RECT  2.16 33.075 84.24 33.345 ;
     RECT  2.16 33.615 84.24 33.885 ;
     RECT  2.16 34.155 84.24 34.425 ;
     RECT  2.16 34.695 84.24 34.965 ;
     RECT  2.16 35.235 84.24 35.505 ;
     RECT  2.16 35.775 84.24 36.045 ;
     RECT  2.16 36.315 84.24 36.585 ;
     RECT  2.16 36.855 84.24 37.125 ;
     RECT  2.16 37.395 84.24 37.665 ;
     RECT  2.16 37.935 84.24 38.205 ;
     RECT  2.16 38.475 84.24 38.745 ;
     RECT  2.16 39.015 84.24 39.285 ;
     RECT  2.16 39.555 84.24 39.825 ;
     RECT  2.16 40.095 84.24 40.365 ;
     RECT  2.16 40.635 84.24 40.905 ;
     RECT  2.16 41.175 84.24 41.445 ;
     RECT  2.16 41.715 84.24 41.985 ;
     RECT  2.16 42.255 84.24 42.525 ;
     RECT  2.16 42.795 84.24 43.065 ;
     RECT  2.16 43.335 84.24 43.605 ;
     RECT  2.16 43.875 84.24 44.145 ;
     RECT  2.16 44.415 84.24 44.685 ;
     RECT  2.16 44.955 84.24 45.225 ;
     RECT  2.16 45.495 84.24 45.765 ;
     RECT  2.16 46.035 84.24 46.305 ;
     RECT  2.16 46.575 84.24 46.845 ;
     RECT  2.16 47.115 84.24 47.385 ;
     RECT  2.16 47.655 84.24 47.925 ;
     RECT  2.16 48.195 84.24 48.465 ;
     RECT  2.16 48.735 84.24 49.005 ;
     RECT  2.16 49.275 84.24 49.545 ;
     RECT  2.16 49.815 84.24 50.085 ;
     RECT  2.16 50.355 84.24 50.625 ;
     RECT  2.16 50.895 84.24 51.165 ;
     RECT  2.16 51.435 84.24 51.705 ;
     RECT  2.16 51.975 84.24 52.245 ;
     RECT  2.16 52.515 84.24 52.785 ;
     RECT  2.16 53.055 84.24 53.325 ;
     RECT  2.16 53.595 84.24 53.865 ;
     RECT  2.16 54.135 84.24 54.405 ;
     RECT  2.16 54.675 84.24 54.945 ;
     RECT  2.16 55.215 84.24 55.485 ;
     RECT  2.16 55.755 84.24 56.025 ;
     RECT  2.16 56.295 84.24 56.565 ;
     RECT  2.16 56.835 84.24 57.105 ;
     RECT  2.16 57.375 84.24 57.645 ;
     RECT  2.16 57.915 84.24 58.185 ;
     RECT  2.16 58.455 84.24 58.725 ;
     RECT  2.16 58.995 84.24 59.265 ;
     RECT  2.16 59.535 84.24 59.805 ;
     RECT  2.16 60.075 84.24 60.345 ;
     RECT  2.16 60.615 84.24 60.885 ;
     RECT  2.16 61.155 84.24 61.425 ;
     RECT  2.16 61.695 84.24 61.965 ;
     RECT  2.16 62.235 84.24 62.505 ;
     RECT  2.16 62.775 84.24 63.045 ;
     RECT  2.16 63.315 84.24 63.585 ;
     RECT  2.16 63.855 84.24 64.125 ;
     RECT  2.16 64.395 84.24 64.665 ;
     RECT  2.16 64.935 84.24 65.205 ;
     RECT  2.16 65.475 84.24 65.745 ;
     RECT  2.16 66.015 84.24 66.285 ;
     RECT  2.16 66.555 84.24 66.825 ;
     RECT  2.16 67.095 84.24 67.365 ;
     RECT  2.16 67.635 84.24 67.905 ;
     RECT  2.16 68.175 84.24 68.445 ;
     RECT  2.16 68.715 84.24 68.985 ;
     RECT  2.16 69.255 84.24 69.525 ;
     RECT  2.16 69.795 84.24 70.065 ;
     RECT  2.16 70.335 84.24 70.605 ;
     RECT  2.16 70.875 84.24 71.145 ;
     RECT  2.16 71.415 84.24 71.685 ;
     RECT  2.16 71.955 84.24 72.225 ;
     RECT  2.16 72.495 84.24 72.765 ;
     RECT  2.16 73.035 84.24 73.305 ;
     RECT  2.16 73.575 84.24 73.845 ;
     RECT  2.16 74.115 84.24 74.385 ;
     RECT  2.16 74.655 84.24 74.925 ;
     RECT  2.16 75.195 84.24 75.465 ;
    LAYER M1 ;
     RECT  2.16 2.151 84.24 75.609 ;
    LAYER M2 ;
     RECT  0.031 54.801 0.067 54.819 ;
     RECT  0.031 60.048 0.067 60.066 ;
     RECT  0.031 53.496 0.103 53.514 ;
     RECT  0.067 54.801 0.103 55.044 ;
     RECT  0.067 59.742 0.103 60.066 ;
     RECT  0.067 71.271 0.103 71.289 ;
     RECT  0.103 59.742 0.139 60.714 ;
     RECT  0.103 61.551 0.139 62.424 ;
     RECT  0.103 70.686 0.139 71.289 ;
     RECT  0.139 59.742 0.167 62.424 ;
     RECT  0.067 67.446 0.167 67.464 ;
     RECT  0.103 53.496 0.175 53.694 ;
     RECT  0.103 54.72 0.175 55.044 ;
     RECT  0.103 64.566 0.175 64.584 ;
     RECT  0.031 63.288 0.239 63.306 ;
     RECT  0.175 64.566 0.247 64.926 ;
     RECT  0.175 53.496 0.275 55.044 ;
     RECT  0.211 56.304 0.319 56.322 ;
     RECT  0.283 57.276 0.319 57.294 ;
     RECT  0.275 54.882 0.347 55.044 ;
     RECT  0.139 58.536 0.355 58.554 ;
     RECT  0.355 58.464 0.391 58.554 ;
     RECT  0.319 56.304 0.427 57.294 ;
     RECT  0.391 58.086 0.427 58.554 ;
     RECT  0.427 56.304 0.463 58.554 ;
     RECT  0.247 64.206 0.535 64.926 ;
     RECT  0.139 70.686 0.535 71.334 ;
     RECT  0.103 72.432 0.571 72.45 ;
     RECT  0.535 70.074 0.599 71.334 ;
     RECT  0.571 72.432 0.607 72.522 ;
     RECT  0.607 72.198 0.643 72.522 ;
     RECT  0.103 65.826 1.147 65.844 ;
     RECT  0.211 67.716 1.147 67.734 ;
     RECT  1.147 65.718 1.175 65.844 ;
     RECT  1.147 67.536 1.175 67.734 ;
     RECT  0.175 74.196 1.723 74.214 ;
     RECT  1.723 73.854 1.759 74.214 ;
     RECT  1.759 73.854 1.795 74.304 ;
     RECT  0.643 72.126 1.831 72.522 ;
     RECT  1.795 73.818 1.831 74.304 ;
     RECT  0.275 53.496 2.16 54.054 ;
     RECT  0.347 55.026 2.16 55.044 ;
     RECT  0.463 56.304 2.16 58.644 ;
     RECT  0.167 59.814 2.16 62.424 ;
     RECT  0.535 63.666 2.16 64.926 ;
     RECT  1.175 65.718 2.16 65.736 ;
     RECT  1.175 67.536 2.16 67.554 ;
     RECT  1.723 69.264 2.16 69.282 ;
     RECT  0.599 70.074 2.16 70.092 ;
     RECT  0.599 71.271 2.16 71.334 ;
     RECT  1.831 72.126 2.16 74.304 ;
     RECT  2.16 2.151 6.115 75.609 ;
     RECT  6.115 2.034 6.475 75.609 ;
     RECT  6.475 2.034 7.367 75.654 ;
     RECT  7.367 2.151 11.947 75.654 ;
     RECT  11.947 2.151 16.691 75.726 ;
     RECT  16.691 2.151 23.539 75.654 ;
     RECT  23.539 2.106 23.963 75.654 ;
     RECT  23.963 2.106 25.547 75.609 ;
     RECT  25.547 2.151 27.643 75.609 ;
     RECT  27.643 2.106 28.363 75.609 ;
     RECT  28.363 2.07 29.147 75.609 ;
     RECT  29.147 2.106 31.387 75.609 ;
     RECT  31.963 1.152 32.063 1.17 ;
     RECT  31.387 2.07 32.567 75.609 ;
     RECT  32.567 2.106 32.891 75.609 ;
     RECT  32.891 2.151 40.999 75.609 ;
     RECT  40.999 2.106 41.395 75.609 ;
     RECT  41.395 2.034 42.287 75.609 ;
     RECT  42.287 2.106 44.635 75.609 ;
     RECT  44.635 2.07 45.383 75.609 ;
     RECT  45.383 2.106 50.647 75.609 ;
     RECT  50.647 2.07 51.899 75.609 ;
     RECT  54.823 1.152 54.959 1.17 ;
     RECT  51.899 2.106 61.051 75.609 ;
     RECT  61.051 2.07 61.267 75.609 ;
     RECT  61.267 1.998 62.123 75.609 ;
     RECT  63.859 1.152 63.959 1.17 ;
     RECT  62.123 2.106 66.227 75.609 ;
     RECT  76.747 76.896 76.883 76.914 ;
     RECT  66.227 2.151 84.24 75.609 ;
    LAYER M3 ;
     RECT  30.348 0.091 30.798 0.139 ;
     RECT  31.968 0.091 31.986 0.139 ;
     RECT  48.744 0.091 48.762 0.139 ;
     RECT  53.46 0.091 54.162 0.139 ;
     RECT  57.276 0.091 57.294 0.139 ;
     RECT  63.54 0.091 63.558 0.139 ;
     RECT  65.052 0.091 65.07 0.139 ;
     RECT  6.768 0.091 7.506 0.187 ;
     RECT  53.172 0.139 54.162 0.187 ;
     RECT  42.192 0.091 42.606 0.475 ;
     RECT  43.344 0.091 43.974 0.475 ;
     RECT  52.884 0.187 54.162 0.475 ;
     RECT  55.332 0.091 55.53 0.475 ;
     RECT  6.732 0.187 7.614 0.523 ;
     RECT  28.476 0.475 28.494 0.523 ;
     RECT  48.744 0.139 49.194 0.523 ;
     RECT  51.552 0.091 52.11 0.523 ;
     RECT  52.884 0.475 55.53 0.523 ;
     RECT  57.204 0.139 57.294 0.523 ;
     RECT  61.452 0.091 61.47 0.523 ;
     RECT  62.964 0.139 63.558 0.523 ;
     RECT  64.404 0.139 65.07 0.523 ;
     RECT  28.476 0.523 28.89 0.571 ;
     RECT  42.192 0.475 43.974 0.571 ;
     RECT  61.452 0.523 65.07 0.571 ;
     RECT  28.476 0.571 29.142 0.667 ;
     RECT  28.476 0.667 29.358 0.797 ;
     RECT  8.388 0.091 8.406 1.099 ;
     RECT  30.348 0.139 31.986 1.147 ;
     RECT  6.228 0.523 7.614 1.723 ;
     RECT  8.388 1.099 9.126 1.723 ;
     RECT  28.476 0.797 29.178 1.723 ;
     RECT  30.348 1.147 32.058 1.723 ;
     RECT  42.192 0.571 44.514 1.723 ;
     RECT  6.228 1.723 9.774 1.771 ;
     RECT  28.476 1.723 32.058 1.771 ;
     RECT  51.372 0.523 57.294 1.771 ;
     RECT  58.14 0.091 58.158 1.771 ;
     RECT  28.476 1.771 32.238 1.819 ;
     RECT  6.228 1.771 10.026 2.029 ;
     RECT  28.476 1.819 32.454 2.065 ;
     RECT  51.372 1.771 58.158 2.065 ;
     RECT  28.368 2.065 32.562 2.101 ;
     RECT  41.4 2.029 41.418 2.101 ;
     RECT  23.544 2.101 23.562 2.143 ;
     RECT  24.516 2.101 24.534 2.143 ;
     RECT  41.004 2.101 41.418 2.143 ;
     RECT  42.192 1.723 45.45 2.143 ;
     RECT  23.544 2.143 24.534 2.191 ;
     RECT  40.215 2.143 41.418 2.191 ;
     RECT  42.192 2.143 45.705 2.191 ;
     RECT  48.312 0.523 49.194 2.191 ;
     RECT  50.652 2.065 58.158 2.191 ;
     RECT  60.984 0.571 65.07 2.191 ;
     RECT  67.215 2.143 67.305 2.191 ;
     RECT  72.615 2.143 72.705 2.191 ;
     RECT  6.12 2.029 10.026 2.227 ;
     RECT  13.215 2.143 13.305 2.227 ;
     RECT  60.552 2.191 65.07 2.227 ;
     RECT  66.204 2.101 66.222 2.227 ;
     RECT  67.215 2.191 67.374 2.227 ;
     RECT  71.712 2.191 72.705 2.227 ;
     RECT  60.552 2.227 65.286 2.251 ;
     RECT  3.708 2.227 3.726 2.263 ;
     RECT  5.976 2.227 10.026 2.263 ;
     RECT  10.8 2.191 10.818 2.263 ;
     RECT  12.492 2.227 13.305 2.263 ;
     RECT  23.292 2.191 24.534 2.263 ;
     RECT  26.388 2.191 26.406 2.263 ;
     RECT  27.648 2.101 32.886 2.263 ;
     RECT  34.815 2.143 34.905 2.263 ;
     RECT  38.196 2.227 38.214 2.263 ;
     RECT  40.215 2.191 45.705 2.263 ;
     RECT  46.908 2.191 46.926 2.263 ;
     RECT  59.94 2.251 65.286 2.263 ;
     RECT  68.184 2.227 68.202 2.263 ;
     RECT  69.12 2.191 69.138 2.263 ;
     RECT  74.016 2.227 74.034 2.263 ;
     RECT  78.015 2.143 78.105 2.263 ;
     RECT  15.408 2.203 16.002 2.299 ;
     RECT  20.34 2.293 20.358 2.299 ;
     RECT  21.492 2.227 21.51 2.299 ;
     RECT  26.388 2.263 26.766 2.299 ;
     RECT  27.648 2.263 33.066 2.299 ;
     RECT  34.092 2.263 34.905 2.299 ;
     RECT  59.868 2.263 65.286 2.299 ;
     RECT  74.016 2.263 74.538 2.299 ;
     RECT  5.976 2.263 11.214 2.335 ;
     RECT  12.024 2.263 13.305 2.335 ;
     RECT  15.336 2.299 16.434 2.335 ;
     RECT  17.388 2.299 17.406 2.335 ;
     RECT  18.615 2.143 18.705 2.335 ;
     RECT  22.968 2.263 24.534 2.335 ;
     RECT  25.524 2.101 25.542 2.335 ;
     RECT  68.184 2.263 69.138 2.335 ;
     RECT  70.92 2.251 70.938 2.335 ;
     RECT  20.34 2.299 20.646 2.347 ;
     RECT  21.42 2.299 22.158 2.347 ;
     RECT  5.976 2.335 13.305 2.371 ;
     RECT  14.256 2.191 14.274 2.371 ;
     RECT  15.336 2.335 17.406 2.371 ;
     RECT  20.34 2.347 22.158 2.371 ;
     RECT  22.968 2.335 25.542 2.371 ;
     RECT  48.312 2.191 58.482 2.371 ;
     RECT  59.4 2.299 65.286 2.371 ;
     RECT  74.016 2.299 74.574 2.371 ;
     RECT  78.015 2.263 78.606 2.371 ;
     RECT  2.415 2.143 2.505 2.413 ;
     RECT  5.724 2.371 13.374 2.413 ;
     RECT  66.204 2.227 67.374 2.413 ;
     RECT  68.184 2.335 69.174 2.413 ;
     RECT  83.415 2.143 83.505 2.413 ;
     RECT  26.388 2.299 35.154 2.461 ;
     RECT  38.196 2.263 38.322 2.461 ;
     RECT  39.096 2.191 39.114 2.461 ;
     RECT  48.096 2.371 58.59 2.461 ;
     RECT  59.328 2.371 65.286 2.461 ;
     RECT  66.204 2.413 69.174 2.461 ;
     RECT  70.812 2.335 70.938 2.461 ;
     RECT  71.712 2.227 73.134 2.461 ;
     RECT  73.98 2.371 74.97 2.461 ;
     RECT  20.16 2.371 25.542 2.489 ;
     RECT  18.432 2.335 19.422 2.491 ;
     RECT  36.468 2.461 36.486 2.497 ;
     RECT  38.196 2.461 39.114 2.497 ;
     RECT  40.215 2.263 47.214 2.497 ;
     RECT  3.708 2.263 4.194 2.533 ;
     RECT  4.932 2.371 4.95 2.533 ;
     RECT  5.724 2.413 13.497 2.533 ;
     RECT  14.256 2.371 17.406 2.533 ;
     RECT  38.124 2.497 47.214 2.533 ;
     RECT  48.096 2.461 65.286 2.533 ;
     RECT  66.204 2.461 69.534 2.533 ;
     RECT  36.432 2.497 36.486 2.539 ;
     RECT  22.932 2.489 25.542 2.569 ;
     RECT  38.124 2.533 65.286 2.569 ;
     RECT  66.132 2.533 69.534 2.569 ;
     RECT  73.98 2.461 75.258 2.569 ;
     RECT  70.812 2.461 73.134 2.587 ;
     RECT  73.98 2.569 75.798 2.587 ;
     RECT  3.708 2.533 4.95 2.605 ;
     RECT  5.724 2.533 17.406 2.605 ;
     RECT  18.36 2.491 19.422 2.605 ;
     RECT  38.124 2.569 69.534 2.605 ;
     RECT  79.38 2.371 79.398 2.605 ;
     RECT  77.724 2.371 78.606 2.632 ;
     RECT  79.38 2.605 80.118 2.632 ;
     RECT  3.708 2.605 19.422 2.641 ;
     RECT  20.16 2.489 22.194 2.641 ;
     RECT  22.932 2.569 25.578 2.641 ;
     RECT  26.388 2.461 35.514 2.641 ;
     RECT  37.8 2.605 70.038 2.641 ;
     RECT  70.812 2.587 75.798 2.641 ;
     RECT  76.572 2.299 76.986 2.641 ;
     RECT  77.724 2.632 80.118 2.641 ;
     RECT  22.932 2.641 35.658 2.731 ;
     RECT  36.432 2.539 36.522 2.731 ;
     RECT  3.708 2.641 22.194 2.767 ;
     RECT  22.932 2.731 36.522 2.767 ;
     RECT  37.8 2.641 75.798 2.839 ;
     RECT  2.415 2.413 2.697 2.875 ;
     RECT  3.564 2.767 22.194 2.875 ;
     RECT  37.62 2.839 75.798 2.875 ;
     RECT  22.932 2.767 36.63 2.911 ;
     RECT  37.44 2.875 75.798 2.911 ;
     RECT  76.572 2.641 80.946 3.073 ;
     RECT  76.572 3.073 81.09 3.109 ;
     RECT  22.932 2.911 75.834 3.181 ;
     RECT  76.572 3.109 81.27 3.181 ;
     RECT  2.415 2.875 22.194 3.259 ;
     RECT  22.932 3.181 81.27 3.259 ;
     RECT  2.415 3.259 81.27 3.883 ;
     RECT  2.415 3.883 81.306 3.955 ;
     RECT  2.376 3.955 81.306 3.991 ;
     RECT  2.376 3.991 81.702 4.261 ;
     RECT  2.376 4.261 81.81 4.693 ;
     RECT  2.376 4.693 81.918 5.071 ;
     RECT  2.376 5.071 82.206 5.233 ;
     RECT  2.376 5.233 82.314 5.305 ;
     RECT  83.415 2.413 83.697 5.701 ;
     RECT  2.304 5.305 82.422 5.845 ;
     RECT  83.196 5.701 83.697 5.845 ;
     RECT  2.304 5.845 83.697 7.771 ;
     RECT  2.304 7.771 83.79 7.925 ;
     RECT  2.304 7.925 83.697 9.085 ;
     RECT  2.304 9.085 83.754 9.661 ;
     RECT  2.304 9.661 83.898 9.859 ;
     RECT  2.304 9.859 84.042 10.319 ;
     RECT  2.304 10.319 84.006 11.515 ;
     RECT  2.304 11.515 84.114 11.939 ;
     RECT  2.304 11.939 83.697 14.719 ;
     RECT  2.232 14.719 83.697 14.957 ;
     RECT  2.304 14.957 83.697 15.799 ;
     RECT  2.304 15.799 83.754 15.899 ;
     RECT  2.304 15.899 83.697 16.681 ;
     RECT  2.304 16.681 83.862 16.835 ;
     RECT  2.304 16.835 83.697 17.761 ;
     RECT  2.304 17.761 83.826 17.915 ;
     RECT  2.304 17.915 83.697 18.661 ;
     RECT  2.304 18.661 83.754 18.733 ;
     RECT  2.268 18.733 83.754 19.651 ;
     RECT  2.268 19.651 84.114 19.913 ;
     RECT  2.268 19.913 84.042 20.155 ;
     RECT  2.232 20.155 84.042 20.579 ;
     RECT  2.232 20.579 83.898 20.615 ;
     RECT  2.232 20.615 83.826 21.433 ;
     RECT  2.232 21.433 84.006 22.351 ;
     RECT  2.232 22.351 84.114 22.613 ;
     RECT  2.232 22.613 83.697 23.657 ;
     RECT  2.304 23.657 83.697 23.827 ;
     RECT  2.304 23.827 84.006 24.773 ;
     RECT  2.304 24.773 83.862 25.169 ;
     RECT  2.415 25.169 83.862 25.825 ;
     RECT  2.415 25.825 84.114 25.979 ;
     RECT  2.415 25.979 83.754 26.941 ;
     RECT  2.415 26.941 83.97 27.607 ;
     RECT  2.34 27.607 83.97 27.913 ;
     RECT  2.304 27.913 83.97 28.409 ;
     RECT  2.304 28.409 83.862 28.445 ;
     RECT  2.304 28.445 83.697 29.371 ;
     RECT  2.304 29.371 83.898 30.001 ;
     RECT  2.304 30.001 84.042 30.569 ;
     RECT  2.304 30.569 83.898 30.605 ;
     RECT  2.304 30.605 83.697 31.801 ;
     RECT  2.304 31.801 83.754 32.099 ;
     RECT  2.304 32.099 83.697 32.531 ;
     RECT  2.34 32.531 83.697 33.115 ;
     RECT  2.34 33.115 84.006 33.781 ;
     RECT  2.304 33.781 84.006 34.231 ;
     RECT  2.304 34.231 84.042 34.619 ;
     RECT  2.304 34.619 83.898 35.195 ;
     RECT  2.304 35.195 83.697 36.391 ;
     RECT  2.304 36.391 83.97 36.779 ;
     RECT  2.304 36.779 83.862 36.815 ;
     RECT  2.304 36.815 83.697 37.975 ;
     RECT  2.304 37.975 83.97 38.551 ;
     RECT  2.304 38.551 84.042 38.939 ;
     RECT  2.304 38.939 83.898 38.975 ;
     RECT  2.304 38.975 83.697 39.209 ;
     RECT  2.34 39.209 83.697 40.055 ;
     RECT  2.415 40.055 83.697 40.099 ;
     RECT  2.415 40.099 83.934 40.559 ;
     RECT  2.415 40.559 83.79 40.595 ;
     RECT  2.415 40.595 83.754 40.945 ;
     RECT  2.376 40.945 83.754 41.449 ;
     RECT  2.304 41.449 83.754 42.061 ;
     RECT  2.304 42.061 83.79 42.323 ;
     RECT  2.304 42.323 83.697 43.915 ;
     RECT  2.304 43.915 84.114 44.069 ;
     RECT  2.304 44.069 83.754 44.447 ;
     RECT  2.34 44.447 83.754 45.301 ;
     RECT  2.34 45.301 83.826 45.689 ;
     RECT  2.34 45.689 83.754 45.725 ;
     RECT  2.34 45.725 83.697 46.651 ;
     RECT  2.34 46.651 83.934 47.039 ;
     RECT  2.34 47.039 83.79 47.075 ;
     RECT  2.34 47.075 83.697 49.081 ;
     RECT  2.34 49.081 84.114 49.271 ;
     RECT  2.34 49.271 83.934 49.441 ;
     RECT  2.304 49.441 83.934 50.009 ;
     RECT  2.304 50.009 83.826 51.331 ;
     RECT  2.304 51.331 83.97 51.899 ;
     RECT  2.304 51.899 83.862 51.935 ;
     RECT  2.304 51.935 83.697 52.861 ;
     RECT  2.304 52.861 84.042 53.249 ;
     RECT  2.304 53.249 83.898 53.285 ;
     RECT  0.036 53.491 0.054 53.671 ;
     RECT  1.152 53.671 1.17 53.789 ;
     RECT  0.036 53.671 0.126 54.031 ;
     RECT  2.304 53.285 83.826 54.175 ;
     RECT  2.268 54.175 83.826 54.211 ;
     RECT  0.036 54.031 0.198 54.715 ;
     RECT  0.036 54.715 0.342 54.824 ;
     RECT  2.268 54.211 83.934 54.841 ;
     RECT  0.072 54.824 0.342 54.905 ;
     RECT  2.268 54.841 83.97 54.977 ;
     RECT  2.304 54.977 83.97 55.409 ;
     RECT  2.304 55.409 83.862 55.445 ;
     RECT  2.304 55.445 83.697 56.371 ;
     RECT  0.072 54.905 0.27 56.911 ;
     RECT  2.304 56.371 83.898 57.173 ;
     RECT  0.072 56.911 0.342 57.307 ;
     RECT  2.304 57.173 83.697 57.649 ;
     RECT  2.268 57.649 83.697 57.713 ;
     RECT  2.268 57.713 17.226 57.721 ;
     RECT  0.072 57.307 0.846 57.919 ;
     RECT  2.232 57.721 17.226 57.991 ;
     RECT  0.072 57.919 0.882 58.189 ;
     RECT  1.764 57.991 17.226 58.189 ;
     RECT  18.432 57.713 83.697 58.495 ;
     RECT  17.964 58.495 83.697 58.801 ;
     RECT  0.072 58.189 17.226 58.999 ;
     RECT  17.964 58.801 83.934 58.999 ;
     RECT  0.072 58.999 83.934 59.611 ;
     RECT  0.072 59.611 83.97 59.999 ;
     RECT  0.072 59.999 83.862 60.035 ;
     RECT  0.072 60.035 83.697 60.043 ;
     RECT  0.036 60.043 83.697 60.925 ;
     RECT  0.036 60.925 84.114 61.079 ;
     RECT  0.036 61.079 83.97 61.325 ;
     RECT  1.404 61.325 83.97 61.805 ;
     RECT  1.764 61.805 83.97 61.889 ;
     RECT  1.764 61.889 83.898 61.925 ;
     RECT  0.036 61.325 0.594 62.669 ;
     RECT  1.764 61.925 83.862 62.735 ;
     RECT  1.764 62.735 83.697 62.957 ;
     RECT  2.268 62.957 83.697 63.149 ;
     RECT  0.036 62.669 0.558 63.311 ;
     RECT  2.304 63.149 83.697 63.661 ;
     RECT  0.108 63.311 0.558 63.821 ;
     RECT  0.144 63.821 0.558 64.013 ;
     RECT  2.304 63.661 84.042 64.021 ;
     RECT  2.268 64.021 84.042 64.171 ;
     RECT  0.144 64.013 0.27 64.561 ;
     RECT  2.232 64.171 84.042 64.699 ;
     RECT  0.108 64.561 0.27 64.877 ;
     RECT  2.196 64.699 84.042 64.931 ;
     RECT  0.108 64.877 0.198 65.069 ;
     RECT  2.268 64.931 84.042 65.129 ;
     RECT  1.152 65.713 1.17 65.849 ;
     RECT  0.108 65.069 0.162 66.187 ;
     RECT  2.268 65.129 83.97 66.209 ;
     RECT  2.304 66.209 83.862 66.245 ;
     RECT  0.108 66.187 0.342 66.317 ;
     RECT  0.108 66.317 0.126 66.701 ;
     RECT  2.304 66.245 83.697 66.955 ;
     RECT  2.268 66.955 83.697 67.051 ;
     RECT  2.232 67.051 83.697 67.171 ;
     RECT  2.232 67.171 84.042 67.361 ;
     RECT  0.216 67.387 0.234 67.432 ;
     RECT  0.144 67.432 0.234 67.441 ;
     RECT  2.232 67.361 83.934 67.865 ;
     RECT  2.232 67.865 83.697 67.915 ;
     RECT  1.152 67.531 1.17 68.107 ;
     RECT  2.196 67.915 83.697 68.107 ;
     RECT  0.072 67.441 0.234 68.237 ;
     RECT  1.152 68.107 83.697 68.333 ;
     RECT  0.072 68.237 0.162 69.067 ;
     RECT  1.728 68.333 83.697 69.287 ;
     RECT  2.268 69.287 83.697 69.449 ;
     RECT  0.072 69.067 0.63 69.835 ;
     RECT  2.304 69.449 83.697 69.871 ;
     RECT  2.304 69.871 83.754 70.411 ;
     RECT  1.98 70.411 83.754 70.501 ;
     RECT  1.98 70.501 83.97 70.891 ;
     RECT  1.836 70.891 83.97 71.266 ;
     RECT  0.072 69.835 0.666 71.294 ;
     RECT  0.144 71.294 0.666 71.339 ;
     RECT  1.728 71.266 83.97 71.501 ;
     RECT  22.86 71.501 83.97 71.681 ;
     RECT  23.04 71.681 83.97 71.761 ;
     RECT  0.18 71.339 0.666 72.149 ;
     RECT  0.18 72.149 0.63 72.221 ;
     RECT  1.728 71.501 22.014 72.301 ;
     RECT  23.04 71.761 84.042 72.419 ;
     RECT  0.18 72.221 0.594 72.427 ;
     RECT  1.728 72.301 22.23 72.463 ;
     RECT  23.04 72.419 49.878 72.463 ;
     RECT  0.108 72.427 0.594 72.527 ;
     RECT  1.728 72.463 49.878 72.959 ;
     RECT  50.832 72.419 84.042 72.959 ;
     RECT  10.296 72.959 49.878 72.995 ;
     RECT  50.832 72.959 83.898 72.995 ;
     RECT  10.476 72.995 49.878 73.237 ;
     RECT  50.832 72.995 83.697 73.237 ;
     RECT  0.108 72.527 0.342 73.325 ;
     RECT  0.108 73.325 0.306 73.517 ;
     RECT  1.728 72.959 9.558 73.741 ;
     RECT  10.476 73.237 83.697 73.741 ;
     RECT  1.728 73.741 83.697 73.841 ;
     RECT  0.144 73.517 0.306 73.853 ;
     RECT  1.728 73.841 82.674 73.877 ;
     RECT  1.764 73.877 82.674 74.048 ;
     RECT  0.18 73.853 0.306 74.093 ;
     RECT  0.18 74.093 0.198 74.219 ;
     RECT  1.764 74.048 82.53 74.309 ;
     RECT  2.304 74.309 81.882 74.579 ;
     RECT  2.304 74.579 81.738 74.638 ;
     RECT  2.304 74.638 25.002 74.885 ;
     RECT  26.208 74.638 81.738 74.921 ;
     RECT  26.208 74.921 31.194 75.029 ;
     RECT  2.304 74.885 24.966 75.119 ;
     RECT  31.932 74.921 81.738 75.155 ;
     RECT  58.752 75.155 75.042 75.191 ;
     RECT  9.9 75.119 24.966 75.227 ;
     RECT  31.932 75.155 43.038 75.227 ;
     RECT  2.415 75.119 9.162 75.263 ;
     RECT  9.9 75.227 9.918 75.263 ;
     RECT  44.604 75.155 51.858 75.263 ;
     RECT  31.932 75.227 35.406 75.293 ;
     RECT  58.752 75.191 74.97 75.293 ;
     RECT  26.208 75.029 31.014 75.299 ;
     RECT  36.324 75.227 43.038 75.347 ;
     RECT  44.604 75.263 46.746 75.347 ;
     RECT  47.52 75.263 51.858 75.347 ;
     RECT  83.415 73.841 83.697 75.347 ;
     RECT  75.78 75.155 81.738 75.361 ;
     RECT  2.415 75.263 5.238 75.389 ;
     RECT  6.372 75.263 9.162 75.389 ;
     RECT  10.764 75.227 24.966 75.389 ;
     RECT  26.208 75.299 26.298 75.389 ;
     RECT  27.072 75.299 31.014 75.389 ;
     RECT  32.148 75.293 35.406 75.389 ;
     RECT  36.324 75.347 40.305 75.389 ;
     RECT  41.184 75.347 43.038 75.389 ;
     RECT  46.584 75.347 46.746 75.389 ;
     RECT  47.52 75.347 51.105 75.389 ;
     RECT  52.776 75.155 57.87 75.389 ;
     RECT  58.752 75.293 59.562 75.389 ;
     RECT  60.336 75.293 74.97 75.389 ;
     RECT  75.78 75.361 81.81 75.389 ;
     RECT  6.372 75.389 8.91 75.395 ;
     RECT  37.044 75.389 37.062 75.395 ;
     RECT  38.34 75.389 38.358 75.395 ;
     RECT  39.528 75.389 40.305 75.395 ;
     RECT  2.415 75.389 4.158 75.425 ;
     RECT  7.704 75.395 8.91 75.425 ;
     RECT  10.764 75.389 10.782 75.425 ;
     RECT  11.916 75.389 14.67 75.425 ;
     RECT  15.696 75.389 20.214 75.425 ;
     RECT  21.636 75.389 24.426 75.425 ;
     RECT  29.088 75.389 30.87 75.425 ;
     RECT  32.688 75.389 32.814 75.425 ;
     RECT  41.184 75.389 42.858 75.425 ;
     RECT  52.776 75.389 52.794 75.425 ;
     RECT  55.224 75.389 56.505 75.425 ;
     RECT  57.564 75.389 57.87 75.425 ;
     RECT  58.752 75.389 58.842 75.425 ;
     RECT  60.552 75.389 63.846 75.425 ;
     RECT  67.215 75.389 72.99 75.425 ;
     RECT  74.628 75.389 74.79 75.425 ;
     RECT  23.004 75.425 24.138 75.437 ;
     RECT  26.1 75.397 26.118 75.437 ;
     RECT  27.684 75.389 27.702 75.437 ;
     RECT  29.088 75.425 30.186 75.437 ;
     RECT  44.604 75.347 45.705 75.437 ;
     RECT  46.584 75.389 46.602 75.437 ;
     RECT  47.772 75.389 48.942 75.437 ;
     RECT  50.256 75.389 50.274 75.437 ;
     RECT  51.84 75.347 51.858 75.437 ;
     RECT  15.696 75.425 15.714 75.461 ;
     RECT  16.668 75.425 17.622 75.461 ;
     RECT  23.94 75.437 24.138 75.461 ;
     RECT  75.96 75.389 81.81 75.461 ;
     RECT  6.372 75.395 6.606 75.497 ;
     RECT  7.704 75.425 8.586 75.497 ;
     RECT  14.04 75.425 14.166 75.497 ;
     RECT  47.772 75.437 48.366 75.497 ;
     RECT  55.224 75.425 55.242 75.497 ;
     RECT  57.564 75.425 57.726 75.497 ;
     RECT  58.752 75.425 58.77 75.497 ;
     RECT  60.552 75.425 60.57 75.497 ;
     RECT  66.132 75.389 66.15 75.497 ;
     RECT  71.82 75.425 72.705 75.497 ;
     RECT  4.14 75.425 4.158 75.533 ;
     RECT  5.22 75.389 5.238 75.533 ;
     RECT  7.704 75.497 8.478 75.533 ;
     RECT  32.688 75.425 32.706 75.533 ;
     RECT  34.815 75.389 35.262 75.533 ;
     RECT  41.184 75.425 41.346 75.533 ;
     RECT  42.588 75.425 42.858 75.533 ;
     RECT  61.815 75.425 62.478 75.533 ;
     RECT  63.828 75.425 63.846 75.533 ;
     RECT  64.584 75.389 64.602 75.533 ;
     RECT  74.628 75.425 74.646 75.533 ;
     RECT  75.96 75.461 80.478 75.533 ;
     RECT  6.372 75.497 6.498 75.569 ;
     RECT  7.704 75.533 7.905 75.569 ;
     RECT  18.615 75.425 20.034 75.569 ;
     RECT  41.328 75.533 41.346 75.569 ;
     RECT  42.588 75.533 42.606 75.569 ;
     RECT  45.036 75.437 45.705 75.569 ;
     RECT  57.564 75.497 57.582 75.569 ;
     RECT  67.215 75.425 70.578 75.569 ;
     RECT  72.432 75.497 72.705 75.569 ;
     RECT  81.288 75.461 81.522 75.569 ;
     RECT  2.415 75.425 2.505 75.617 ;
     RECT  7.815 75.569 7.905 75.617 ;
     RECT  11.952 75.425 13.305 75.617 ;
     RECT  18.615 75.569 19.926 75.617 ;
     RECT  23.94 75.461 24.105 75.617 ;
     RECT  29.415 75.437 29.505 75.617 ;
     RECT  34.815 75.533 34.905 75.617 ;
     RECT  40.215 75.395 40.305 75.617 ;
     RECT  45.615 75.569 45.705 75.617 ;
     RECT  51.015 75.389 51.105 75.617 ;
     RECT  56.415 75.425 56.505 75.617 ;
     RECT  61.815 75.533 61.905 75.617 ;
     RECT  67.215 75.569 70.542 75.617 ;
     RECT  72.615 75.569 72.705 75.617 ;
     RECT  83.415 75.347 83.505 75.617 ;
     RECT  6.48 75.569 6.498 75.659 ;
     RECT  11.952 75.617 12.654 75.659 ;
     RECT  16.668 75.461 17.226 75.659 ;
     RECT  19.26 75.617 19.926 75.659 ;
     RECT  22.176 75.425 22.194 75.659 ;
     RECT  23.004 75.437 23.022 75.659 ;
     RECT  23.94 75.617 23.958 75.659 ;
     RECT  11.952 75.659 11.97 75.731 ;
     RECT  14.04 75.497 14.058 75.731 ;
     RECT  16.668 75.659 16.686 75.731 ;
     RECT  76.464 75.533 80.478 75.821 ;
     RECT  67.536 75.617 70.542 76.397 ;
     RECT  76.464 75.821 79.722 76.397 ;
     RECT  76.572 76.397 77.922 76.925 ;
     RECT  78.66 76.397 79.722 76.925 ;
     RECT  67.932 76.397 70.542 76.973 ;
     RECT  69.912 76.973 70.542 77.453 ;
     RECT  69.912 77.453 70.506 77.501 ;
     RECT  70.02 77.501 70.506 77.549 ;
     RECT  78.66 76.925 79.686 77.549 ;
     RECT  70.02 77.549 70.11 77.597 ;
     RECT  78.66 77.549 78.822 77.597 ;
     RECT  80.46 75.821 80.478 77.597 ;
     RECT  67.932 76.973 68.49 77.645 ;
     RECT  70.02 77.597 70.038 77.645 ;
     RECT  76.572 76.925 77.85 77.645 ;
     RECT  78.804 77.597 78.822 77.645 ;
     RECT  79.668 77.549 79.686 77.645 ;
    LAYER M4 ;
     RECT  0.06 58.608 0.097 70.824 ;
     RECT  0.06 73.008 0.277 73.896 ;
     RECT  0.169 54.72 0.353 54.744 ;
     RECT  2.221 14.928 2.329 14.952 ;
     RECT  2.293 12.48 2.365 12.504 ;
     RECT  2.365 10.992 2.401 12.552 ;
     RECT  2.329 14.736 2.401 14.952 ;
     RECT  2.401 7.92 2.408 7.944 ;
     RECT  2.401 10.32 2.408 12.552 ;
     RECT  2.401 14.736 2.408 15.576 ;
     RECT  2.293 18.192 2.408 18.216 ;
     RECT  2.329 21.984 2.408 22.008 ;
     RECT  2.293 25.056 2.408 25.224 ;
     RECT  2.293 26.208 2.408 26.232 ;
     RECT  2.365 28.464 2.408 28.488 ;
     RECT  2.293 32.208 2.408 32.232 ;
     RECT  2.365 34.896 2.408 34.92 ;
     RECT  2.365 43.296 2.408 43.32 ;
     RECT  2.293 52.176 2.408 52.2 ;
     RECT  2.293 57.024 2.408 57.624 ;
     RECT  0.097 58.608 2.408 70.92 ;
     RECT  0.277 73.008 2.408 74.088 ;
     RECT  2.408 2.148 2.512 75.612 ;
     RECT  2.512 2.418 2.704 75.342 ;
     RECT  2.704 14.736 2.801 19.992 ;
     RECT  2.704 44.976 2.837 45 ;
     RECT  2.801 15.552 2.867 19.992 ;
     RECT  2.704 21.168 2.867 24.12 ;
     RECT  2.704 52.32 2.867 57.624 ;
     RECT  2.867 15.552 2.909 19.368 ;
     RECT  2.704 34.128 2.909 36.408 ;
     RECT  2.704 58.992 2.909 74.376 ;
     RECT  2.704 3.408 2.945 5.16 ;
     RECT  2.909 64.896 3.017 74.376 ;
     RECT  2.704 7.824 3.053 13.608 ;
     RECT  2.909 15.552 3.059 19.032 ;
     RECT  3.053 7.824 3.161 11.688 ;
     RECT  3.059 15.984 3.233 19.032 ;
     RECT  3.233 16.512 3.251 19.032 ;
     RECT  3.161 10.992 3.269 11.688 ;
     RECT  2.704 25.2 3.305 25.224 ;
     RECT  2.909 58.992 3.305 63.816 ;
     RECT  3.017 64.896 3.413 66.312 ;
     RECT  2.909 36.384 3.557 36.408 ;
     RECT  3.053 13.104 3.629 13.608 ;
     RECT  2.909 34.128 3.629 35.352 ;
     RECT  2.704 45.984 3.629 46.728 ;
     RECT  2.704 47.856 3.629 47.88 ;
     RECT  2.704 28.464 3.635 29.688 ;
     RECT  3.305 58.992 3.665 60.648 ;
     RECT  2.704 50.88 3.733 51.192 ;
     RECT  3.653 2.256 3.737 2.28 ;
     RECT  2.704 30.96 3.829 33.048 ;
     RECT  3.629 45.984 3.836 46.632 ;
     RECT  2.704 37.584 3.845 37.608 ;
     RECT  2.704 40.464 3.877 41.016 ;
     RECT  2.704 42.768 3.877 43.32 ;
     RECT  2.867 52.32 3.877 57.48 ;
     RECT  3.635 28.944 3.881 29.688 ;
     RECT  3.017 67.296 3.905 74.376 ;
     RECT  2.867 21.168 3.913 23.832 ;
     RECT  3.829 30.672 3.916 33.048 ;
     RECT  3.836 45.36 3.923 46.632 ;
     RECT  2.945 3.408 3.985 4.536 ;
     RECT  3.251 17.616 4.021 19.032 ;
     RECT  3.913 20.4 4.021 23.832 ;
     RECT  3.877 52.272 4.021 57.48 ;
     RECT  3.949 6.48 4.129 6.504 ;
     RECT  3.805 14.832 4.169 14.856 ;
     RECT  4.129 6.48 4.201 6.6 ;
     RECT  4.201 6.288 4.237 6.6 ;
     RECT  3.877 40.416 4.237 41.016 ;
     RECT  2.704 49.728 4.273 49.752 ;
     RECT  3.733 50.736 4.273 51.192 ;
     RECT  3.985 2.784 4.277 4.536 ;
     RECT  3.251 16.512 4.345 16.536 ;
     RECT  4.021 17.616 4.345 23.832 ;
     RECT  4.237 24.864 4.345 24.888 ;
     RECT  4.273 49.728 4.345 51.192 ;
     RECT  4.021 52.272 4.345 57.864 ;
     RECT  4.277 2.784 4.385 3.672 ;
     RECT  4.345 49.728 4.417 57.864 ;
     RECT  3.665 58.992 4.417 60.6 ;
     RECT  3.923 46.224 4.421 46.632 ;
     RECT  4.345 24.864 4.453 25.608 ;
     RECT  2.704 26.736 4.453 26.76 ;
     RECT  3.305 61.632 4.453 63.816 ;
     RECT  3.413 64.896 4.453 66.216 ;
     RECT  4.237 6.288 4.525 6.648 ;
     RECT  3.161 7.824 4.525 9.72 ;
     RECT  4.453 61.632 4.525 66.216 ;
     RECT  3.905 67.296 4.525 74.712 ;
     RECT  4.345 16.512 4.556 23.832 ;
     RECT  3.877 48.288 4.595 48.456 ;
     RECT  3.697 13.728 4.597 13.752 ;
     RECT  4.597 13.056 4.633 13.752 ;
     RECT  4.556 15.84 4.643 23.832 ;
     RECT  3.629 34.368 4.645 35.352 ;
     RECT  4.643 15.936 4.705 23.832 ;
     RECT  4.453 24.864 4.705 27.672 ;
     RECT  4.417 5.28 4.709 5.304 ;
     RECT  3.269 11.664 4.741 11.688 ;
     RECT  4.645 34.128 4.741 35.352 ;
     RECT  4.417 49.728 4.789 60.6 ;
     RECT  4.705 15.936 4.813 27.672 ;
     RECT  4.385 2.784 4.849 3.432 ;
     RECT  4.237 40.416 4.849 41.688 ;
     RECT  3.877 42.768 4.849 44.184 ;
     RECT  3.916 30.912 4.885 33.048 ;
     RECT  4.595 48.288 4.885 48.312 ;
     RECT  4.849 40.416 4.921 44.184 ;
     RECT  4.813 15.936 4.925 27.864 ;
     RECT  4.421 46.224 4.925 46.248 ;
     RECT  4.789 49.488 4.925 60.6 ;
     RECT  4.921 37.104 4.957 37.128 ;
     RECT  4.925 49.728 4.957 60.6 ;
     RECT  4.525 61.632 4.957 74.712 ;
     RECT  4.525 6.288 4.981 9.72 ;
     RECT  4.741 11.424 4.981 11.688 ;
     RECT  4.885 47.808 4.993 48.312 ;
     RECT  4.237 38.736 5.029 38.76 ;
     RECT  4.981 6.288 5.065 11.688 ;
     RECT  4.741 34.128 5.065 35.448 ;
     RECT  5.065 34.128 5.105 35.496 ;
     RECT  5.105 35.328 5.137 35.496 ;
     RECT  4.957 36.48 5.137 37.128 ;
     RECT  5.029 38.736 5.137 39.336 ;
     RECT  5.065 5.856 5.173 11.688 ;
     RECT  4.633 13.056 5.173 14.184 ;
     RECT  4.925 24.864 5.173 27.864 ;
     RECT  3.881 28.944 5.173 29.4 ;
     RECT  4.885 30.432 5.209 33.048 ;
     RECT  4.957 49.728 5.285 74.712 ;
     RECT  5.173 5.856 5.365 14.184 ;
     RECT  4.849 2.688 5.461 3.432 ;
     RECT  5.173 24.864 5.501 29.4 ;
     RECT  5.461 2.64 5.641 3.432 ;
     RECT  5.501 28.752 5.677 29.4 ;
     RECT  5.209 30.432 5.677 34.008 ;
     RECT  5.285 55.68 5.708 74.712 ;
     RECT  5.641 2.64 5.749 4.296 ;
     RECT  5.749 2.64 5.785 4.584 ;
     RECT  4.921 40.416 5.821 44.472 ;
     RECT  5.785 2.64 5.825 4.824 ;
     RECT  5.501 24.864 5.891 27.576 ;
     RECT  4.993 47.424 5.893 48.312 ;
     RECT  5.285 49.728 5.969 54.696 ;
     RECT  4.925 15.936 5.989 23.88 ;
     RECT  5.891 24.864 5.989 27.096 ;
     RECT  5.825 2.688 6.001 4.824 ;
     RECT  5.365 5.856 6.001 14.52 ;
     RECT  5.989 15.936 6.035 27.096 ;
     RECT  5.708 55.68 6.037 74.856 ;
     RECT  6.035 23.328 6.077 27.096 ;
     RECT  5.677 28.752 6.145 34.008 ;
     RECT  6.145 28.752 6.245 34.248 ;
     RECT  5.137 35.328 6.245 39.336 ;
     RECT  5.893 46.8 6.289 48.312 ;
     RECT  6.289 46.752 6.361 48.312 ;
     RECT  6.077 24.864 6.401 27.096 ;
     RECT  6.001 2.688 6.469 14.52 ;
     RECT  6.035 15.936 6.469 22.296 ;
     RECT  6.361 46.752 6.505 48.456 ;
     RECT  5.969 50.016 6.505 54.696 ;
     RECT  6.037 55.68 6.505 74.904 ;
     RECT  6.505 50.016 6.545 74.904 ;
     RECT  6.217 0.528 6.721 0.552 ;
     RECT  6.721 0.192 6.757 0.552 ;
     RECT  5.821 40.416 6.829 45.144 ;
     RECT  6.505 46.752 6.829 48.792 ;
     RECT  6.245 28.752 6.833 39.336 ;
     RECT  6.757 0.096 6.937 0.552 ;
     RECT  6.829 40.416 6.973 48.792 ;
     RECT  6.545 50.016 6.973 61.944 ;
     RECT  6.469 2.688 7.004 22.296 ;
     RECT  6.545 62.976 7.093 74.904 ;
     RECT  6.077 23.328 7.189 23.88 ;
     RECT  6.401 24.864 7.189 26.472 ;
     RECT  6.937 27.456 7.292 27.48 ;
     RECT  7.189 23.328 7.405 26.472 ;
     RECT  7.292 27.456 7.405 27.912 ;
     RECT  6.937 0.096 7.417 0.6 ;
     RECT  7.417 0.096 7.475 0.504 ;
     RECT  6.833 28.944 7.621 39.336 ;
     RECT  6.973 40.416 7.621 61.944 ;
     RECT  7.004 2.256 7.685 22.296 ;
     RECT  7.685 1.728 7.808 22.296 ;
     RECT  7.405 23.328 7.808 27.912 ;
     RECT  7.621 28.944 7.808 61.944 ;
     RECT  7.093 62.976 7.808 75.384 ;
     RECT  7.808 1.728 7.912 75.612 ;
     RECT  7.912 1.728 8.104 75.342 ;
     RECT  7.475 0.096 8.243 0.216 ;
     RECT  8.104 35.904 8.489 75.24 ;
     RECT  8.243 0.096 8.723 0.12 ;
     RECT  8.489 35.904 8.777 49.608 ;
     RECT  8.489 50.64 8.777 75.24 ;
     RECT  8.104 15.84 8.849 27.48 ;
     RECT  8.777 35.904 8.849 41.928 ;
     RECT  8.777 42.96 8.885 49.608 ;
     RECT  8.777 50.64 9.029 70.248 ;
     RECT  8.104 1.728 9.097 2.28 ;
     RECT  8.104 3.36 9.097 14.712 ;
     RECT  8.849 15.84 9.097 17.592 ;
     RECT  8.885 42.96 9.101 49.512 ;
     RECT  9.097 1.104 9.107 2.28 ;
     RECT  8.777 71.232 9.107 75.24 ;
     RECT  8.104 34.752 9.133 34.92 ;
     RECT  8.849 35.904 9.133 41.784 ;
     RECT  9.107 74.688 9.137 75.24 ;
     RECT  8.104 28.608 9.205 33.384 ;
     RECT  9.133 34.752 9.205 41.784 ;
     RECT  8.849 18.816 9.208 27.48 ;
     RECT  9.101 46.752 9.209 49.512 ;
     RECT  9.101 42.96 9.251 45.768 ;
     RECT  9.205 28.608 9.281 41.784 ;
     RECT  9.107 71.232 9.317 73.272 ;
     RECT  9.107 1.104 9.395 1.8 ;
     RECT  9.281 28.608 9.421 31.176 ;
     RECT  9.097 3.36 9.425 17.592 ;
     RECT  9.029 50.64 9.461 70.056 ;
     RECT  9.208 18.816 9.601 27.528 ;
     RECT  9.421 28.512 9.601 31.176 ;
     RECT  9.281 32.208 9.677 35.016 ;
     RECT  9.209 46.896 9.677 49.512 ;
     RECT  9.251 43.872 9.713 45.768 ;
     RECT  9.395 1.728 9.82 1.8 ;
     RECT  9.425 3.36 9.857 14.712 ;
     RECT  9.317 71.232 9.889 72.648 ;
     RECT  9.601 18.816 9.929 31.176 ;
     RECT  9.929 18.816 9.936 24.072 ;
     RECT  9.857 3.36 9.965 11.736 ;
     RECT  9.936 18.816 9.973 23.88 ;
     RECT  9.461 50.64 10.001 68.424 ;
     RECT  9.82 1.776 10.037 1.8 ;
     RECT  9.281 36 10.109 41.784 ;
     RECT  9.425 15.696 10.213 17.592 ;
     RECT  9.973 18.672 10.213 23.88 ;
     RECT  9.461 69.456 10.213 70.056 ;
     RECT  9.889 71.136 10.213 72.648 ;
     RECT  9.929 25.056 10.249 31.176 ;
     RECT  9.677 32.208 10.249 34.824 ;
     RECT  10.001 50.64 10.289 68.28 ;
     RECT  10.249 25.056 10.433 34.824 ;
     RECT  9.965 3.36 10.469 10.248 ;
     RECT  10.289 50.64 10.469 54.744 ;
     RECT  10.469 50.64 10.501 54.504 ;
     RECT  10.469 3.36 10.537 10.2 ;
     RECT  10.433 34.512 10.541 34.824 ;
     RECT  10.289 55.776 10.577 68.28 ;
     RECT  9.857 12.816 10.609 14.712 ;
     RECT  10.213 15.696 10.609 23.88 ;
     RECT  9.137 74.688 10.681 74.712 ;
     RECT  10.433 25.056 10.685 33.384 ;
     RECT  10.541 34.512 10.685 34.536 ;
     RECT  10.109 36.096 10.717 41.784 ;
     RECT  10.685 27.36 10.721 33.384 ;
     RECT  9.713 43.92 10.753 45.768 ;
     RECT  10.721 27.36 10.757 33.144 ;
     RECT  10.753 43.92 10.789 45.864 ;
     RECT  9.677 46.896 10.789 48.984 ;
     RECT  10.681 74.688 10.793 74.856 ;
     RECT  10.717 36.096 10.825 42.168 ;
     RECT  9.965 11.232 10.865 11.736 ;
     RECT  10.757 27.408 10.865 33.144 ;
     RECT  10.501 50.112 10.883 54.504 ;
     RECT  10.577 56.016 10.973 68.28 ;
     RECT  10.793 74.832 11.045 74.856 ;
     RECT  10.609 12.816 11.077 23.88 ;
     RECT  10.685 25.056 11.077 26.328 ;
     RECT  10.825 36.096 11.189 42.504 ;
     RECT  10.213 69.456 11.225 72.648 ;
     RECT  11.189 36.528 11.257 42.504 ;
     RECT  10.789 43.92 11.257 48.984 ;
     RECT  11.225 71.424 11.369 72.648 ;
     RECT  10.537 2.448 11.461 10.2 ;
     RECT  11.077 12.816 11.477 26.328 ;
     RECT  10.973 56.016 11.617 68.136 ;
     RECT  11.545 34.8 11.651 35.544 ;
     RECT  11.257 36.528 11.765 48.984 ;
     RECT  10.883 50.112 11.797 50.904 ;
     RECT  10.865 11.664 11.845 11.736 ;
     RECT  11.477 12.816 11.845 19.848 ;
     RECT  11.617 55.824 11.939 68.136 ;
     RECT  11.461 2.448 11.945 10.296 ;
     RECT  11.765 36.528 11.945 41.016 ;
     RECT  11.939 66.72 11.945 68.136 ;
     RECT  11.477 21.12 11.989 26.328 ;
     RECT  10.865 27.456 11.989 33.144 ;
     RECT  11.765 42.048 12.017 48.984 ;
     RECT  11.369 71.424 12.017 72.36 ;
     RECT  11.797 49.968 12.157 50.904 ;
     RECT  10.883 51.984 12.157 54.504 ;
     RECT  11.939 55.824 12.157 65.448 ;
     RECT  11.945 2.928 12.193 10.296 ;
     RECT  11.845 11.664 12.193 19.848 ;
     RECT  11.945 36.528 12.197 38.712 ;
     RECT  11.945 67.056 12.197 68.136 ;
     RECT  11.989 21.12 12.229 33.144 ;
     RECT  11.651 34.848 12.265 35.544 ;
     RECT  12.197 36.528 12.265 38.616 ;
     RECT  12.229 21.12 12.337 33.384 ;
     RECT  12.121 74.688 12.445 74.712 ;
     RECT  12.197 67.296 12.517 68.136 ;
     RECT  11.225 69.456 12.517 70.296 ;
     RECT  12.193 2.928 12.589 19.848 ;
     RECT  12.337 21.12 12.589 33.72 ;
     RECT  12.517 67.296 12.661 70.296 ;
     RECT  12.017 71.424 12.661 72.264 ;
     RECT  12.017 44.352 12.697 48.984 ;
     RECT  12.157 49.968 12.697 65.448 ;
     RECT  12.589 2.928 12.985 33.72 ;
     RECT  11.945 39.744 12.997 41.016 ;
     RECT  12.017 42.048 12.997 43.32 ;
     RECT  12.997 39.744 13.052 43.32 ;
     RECT  12.697 44.352 13.052 65.448 ;
     RECT  13.052 39.744 13.085 65.448 ;
     RECT  12.985 2.304 13.208 33.72 ;
     RECT  12.265 34.848 13.208 38.616 ;
     RECT  13.085 39.744 13.208 65.592 ;
     RECT  12.661 67.296 13.208 72.264 ;
     RECT  12.733 73.488 13.208 73.512 ;
     RECT  12.445 74.688 13.208 74.76 ;
     RECT  13.208 2.148 13.312 75.612 ;
     RECT  13.312 2.208 13.504 75.342 ;
     RECT  13.504 34.704 13.529 64.152 ;
     RECT  13.504 67.248 13.601 73.848 ;
     RECT  13.529 34.704 13.745 64.104 ;
     RECT  13.601 67.248 13.781 73.128 ;
     RECT  13.504 2.208 14.213 33.672 ;
     RECT  13.745 39.312 14.213 64.104 ;
     RECT  13.504 65.136 14.285 66.12 ;
     RECT  13.781 67.248 14.321 70.296 ;
     RECT  14.213 48.288 14.357 64.104 ;
     RECT  14.285 65.136 14.357 65.832 ;
     RECT  13.504 74.832 14.821 74.856 ;
     RECT  13.745 34.704 14.857 38.28 ;
     RECT  14.213 39.312 14.857 47.304 ;
     RECT  14.857 34.704 14.861 47.304 ;
     RECT  14.821 74.832 14.861 75.288 ;
     RECT  14.357 63.264 14.897 64.104 ;
     RECT  13.781 71.424 15.001 73.128 ;
     RECT  14.321 69.504 15.157 70.296 ;
     RECT  15.001 71.376 15.157 73.128 ;
     RECT  15.157 69.504 15.203 73.128 ;
     RECT  15.203 69.504 15.257 69.528 ;
     RECT  14.357 65.232 15.325 65.832 ;
     RECT  14.321 67.248 15.325 68.232 ;
     RECT  15.203 70.656 15.361 73.128 ;
     RECT  15.325 65.232 15.365 68.232 ;
     RECT  15.301 69.36 15.388 69.384 ;
     RECT  14.357 48.288 15.397 62.28 ;
     RECT  14.897 63.264 15.397 63.288 ;
     RECT  14.213 2.208 15.433 33.432 ;
     RECT  14.861 34.704 15.433 34.728 ;
     RECT  15.361 70.656 15.469 73.512 ;
     RECT  14.861 35.808 15.473 47.304 ;
     RECT  15.365 65.232 15.473 68.184 ;
     RECT  15.473 44.064 15.637 47.304 ;
     RECT  15.397 48.288 15.637 63.288 ;
     RECT  15.637 44.064 15.724 63.288 ;
     RECT  15.724 48.432 15.725 63.288 ;
     RECT  15.724 44.064 15.761 47.304 ;
     RECT  15.433 2.208 15.833 34.728 ;
     RECT  15.473 65.232 15.865 65.592 ;
     RECT  15.833 34.464 15.901 34.728 ;
     RECT  15.473 35.808 15.901 42.888 ;
     RECT  15.469 70.656 15.932 73.656 ;
     RECT  14.861 75.264 15.973 75.288 ;
     RECT  15.901 34.464 16.012 42.888 ;
     RECT  15.833 2.208 16.013 33.432 ;
     RECT  15.761 44.112 16.013 47.304 ;
     RECT  15.932 70.656 16.019 73.752 ;
     RECT  15.473 66.672 16.049 68.184 ;
     RECT  16.049 66.672 16.085 67.8 ;
     RECT  16.019 70.656 16.121 73.608 ;
     RECT  15.973 74.832 16.157 75.288 ;
     RECT  15.865 64.368 16.163 65.592 ;
     RECT  16.121 70.656 16.265 73.512 ;
     RECT  15.725 51.984 16.477 63.288 ;
     RECT  16.163 64.368 16.477 65.448 ;
     RECT  16.085 66.672 16.589 66.696 ;
     RECT  16.265 70.656 16.625 73.272 ;
     RECT  16.477 51.984 16.697 65.448 ;
     RECT  16.625 72.24 16.979 73.272 ;
     RECT  16.012 34.464 17.017 34.728 ;
     RECT  16.012 35.808 17.017 42.888 ;
     RECT  16.013 44.112 17.017 46.776 ;
     RECT  15.725 48.432 17.017 50.952 ;
     RECT  17.017 35.808 17.053 46.776 ;
     RECT  17.017 48.288 17.053 50.952 ;
     RECT  16.157 75.264 17.057 75.288 ;
     RECT  16.405 68.976 17.077 69.528 ;
     RECT  17.053 35.808 17.161 50.952 ;
     RECT  16.697 51.984 17.161 52.056 ;
     RECT  16.085 67.68 17.197 67.8 ;
     RECT  17.077 68.88 17.219 69.528 ;
     RECT  16.013 31.776 17.269 33.432 ;
     RECT  17.017 34.464 17.269 34.776 ;
     RECT  17.219 69.504 17.269 69.528 ;
     RECT  17.161 35.808 17.381 52.056 ;
     RECT  16.013 2.304 17.417 30.696 ;
     RECT  17.417 2.496 17.557 30.696 ;
     RECT  17.269 31.776 17.557 34.776 ;
     RECT  17.197 67.584 17.629 67.8 ;
     RECT  16.697 53.232 17.729 65.448 ;
     RECT  17.629 67.056 17.729 67.8 ;
     RECT  16.979 73.248 17.737 73.272 ;
     RECT  17.381 36.048 18.061 52.056 ;
     RECT  17.729 53.232 18.061 67.8 ;
     RECT  17.737 73.248 18.097 74.616 ;
     RECT  18.061 36.048 18.205 67.8 ;
     RECT  18.205 36.048 18.277 67.848 ;
     RECT  16.625 70.656 18.277 71.016 ;
     RECT  17.557 2.496 18.349 34.776 ;
     RECT  18.277 36.048 18.349 68.52 ;
     RECT  18.349 2.496 18.421 68.52 ;
     RECT  17.269 69.504 18.421 69.576 ;
     RECT  18.277 70.656 18.421 71.688 ;
     RECT  18.421 2.352 18.457 68.52 ;
     RECT  18.421 69.504 18.457 71.688 ;
     RECT  18.457 2.352 18.529 71.688 ;
     RECT  18.097 72.816 18.529 74.616 ;
     RECT  18.529 2.352 18.608 74.616 ;
     RECT  18.608 2.148 18.712 75.612 ;
     RECT  18.712 2.352 18.904 75.384 ;
     RECT  18.904 2.352 19.001 34.2 ;
     RECT  18.904 35.184 19.325 69.096 ;
     RECT  19.325 35.184 19.397 37.656 ;
     RECT  18.904 70.08 19.516 73.848 ;
     RECT  18.904 75.216 19.533 75.384 ;
     RECT  19.325 38.736 19.577 69.096 ;
     RECT  19.001 17.04 19.721 34.2 ;
     RECT  19.721 17.04 19.829 33.96 ;
     RECT  19.577 38.736 19.829 54.504 ;
     RECT  19.397 35.184 20.044 37.608 ;
     RECT  19.829 39.024 20.189 54.504 ;
     RECT  19.829 17.04 20.221 33.432 ;
     RECT  20.044 36.24 20.297 37.608 ;
     RECT  19.001 2.352 20.329 15.96 ;
     RECT  19.577 55.488 20.437 69.096 ;
     RECT  19.516 70.08 20.437 73.56 ;
     RECT  20.189 39.024 20.513 47.832 ;
     RECT  20.221 16.944 20.549 33.432 ;
     RECT  20.297 36.624 20.549 37.608 ;
     RECT  20.189 48.96 20.617 54.504 ;
     RECT  20.437 55.488 20.617 73.56 ;
     RECT  20.329 2.304 20.657 15.96 ;
     RECT  20.549 36.768 20.689 37.608 ;
     RECT  20.617 48.96 20.693 73.56 ;
     RECT  20.657 2.352 20.729 15.96 ;
     RECT  20.693 50.88 20.765 73.56 ;
     RECT  20.689 36.768 20.797 38.04 ;
     RECT  20.513 39.024 20.797 47.352 ;
     RECT  20.765 50.928 20.873 73.56 ;
     RECT  19.533 75.36 20.905 75.384 ;
     RECT  20.044 35.184 20.909 35.208 ;
     RECT  20.549 16.944 20.945 30.744 ;
     RECT  20.945 16.944 21.053 30.696 ;
     RECT  20.797 36.768 21.197 47.352 ;
     RECT  21.197 36.768 21.233 37.416 ;
     RECT  20.693 48.96 21.301 49.848 ;
     RECT  20.729 2.64 21.337 15.96 ;
     RECT  21.053 16.944 21.337 27.624 ;
     RECT  20.873 51.216 21.485 73.56 ;
     RECT  21.197 38.64 21.553 47.352 ;
     RECT  21.301 48.72 21.553 49.848 ;
     RECT  21.485 51.888 21.553 73.56 ;
     RECT  20.905 74.688 21.553 75.384 ;
     RECT  21.053 28.704 21.98 30.696 ;
     RECT  20.549 31.968 21.98 33.432 ;
     RECT  21.553 51.888 22.025 75.384 ;
     RECT  21.337 2.64 22.093 27.624 ;
     RECT  22.093 2.352 22.345 27.624 ;
     RECT  22.345 2.352 22.417 27.672 ;
     RECT  21.98 28.704 22.417 33.432 ;
     RECT  21.233 36.864 22.453 37.416 ;
     RECT  22.025 72.48 22.453 75.384 ;
     RECT  22.453 72.48 22.499 75.432 ;
     RECT  22.669 35.136 22.885 35.16 ;
     RECT  22.025 51.888 22.885 71.496 ;
     RECT  22.885 35.136 22.921 35.304 ;
     RECT  22.453 36.816 22.921 37.416 ;
     RECT  22.921 35.136 23.029 37.416 ;
     RECT  22.885 51.648 23.137 71.496 ;
     RECT  23.029 34.464 23.209 37.416 ;
     RECT  21.553 38.64 23.209 49.848 ;
     RECT  23.137 51.312 23.245 71.496 ;
     RECT  23.209 34.464 23.281 49.992 ;
     RECT  23.245 51.12 23.605 71.496 ;
     RECT  22.499 72.48 23.605 73.224 ;
     RECT  22.417 2.352 23.641 33.432 ;
     RECT  23.281 34.464 23.641 50.136 ;
     RECT  23.605 51.12 23.641 73.224 ;
     RECT  22.499 74.544 23.641 75.432 ;
     RECT  23.641 2.352 24.008 50.136 ;
     RECT  23.641 51.12 24.008 75.432 ;
     RECT  24.008 2.148 24.112 75.612 ;
     RECT  24.112 2.352 24.304 75.432 ;
     RECT  24.304 53.616 24.437 73.848 ;
     RECT  24.304 2.352 24.473 52.2 ;
     RECT  24.473 31.92 24.509 52.2 ;
     RECT  24.437 53.616 24.581 73.272 ;
     RECT  24.473 2.352 25.049 30.888 ;
     RECT  24.509 31.968 25.085 52.2 ;
     RECT  24.581 53.616 25.369 73.128 ;
     RECT  25.049 2.496 25.621 30.888 ;
     RECT  25.085 31.968 25.621 49.848 ;
     RECT  24.304 75.408 25.621 75.432 ;
     RECT  25.621 74.592 25.715 75.432 ;
     RECT  25.369 53.52 26.197 73.128 ;
     RECT  25.981 74.112 26.197 74.136 ;
     RECT  26.197 53.52 26.237 74.136 ;
     RECT  26.237 67.296 26.273 74.136 ;
     RECT  25.621 2.496 26.417 49.848 ;
     RECT  26.237 53.52 26.633 66.264 ;
     RECT  26.417 2.496 26.665 33.432 ;
     RECT  25.085 50.88 26.845 52.2 ;
     RECT  26.633 53.52 26.845 65.448 ;
     RECT  26.665 2.448 27.065 33.432 ;
     RECT  26.273 67.296 27.101 73.512 ;
     RECT  27.065 32.736 27.497 33.432 ;
     RECT  27.101 67.296 27.529 73.128 ;
     RECT  27.457 74.112 27.637 74.136 ;
     RECT  25.715 75.168 27.637 75.432 ;
     RECT  27.065 2.448 27.677 31.56 ;
     RECT  27.637 74.112 27.713 75.432 ;
     RECT  26.417 34.704 27.781 49.848 ;
     RECT  26.845 50.88 27.781 65.448 ;
     RECT  27.781 34.704 27.889 65.448 ;
     RECT  27.529 66.864 27.889 73.128 ;
     RECT  27.677 2.448 27.929 31.32 ;
     RECT  27.929 2.448 27.965 31.176 ;
     RECT  27.889 34.704 27.965 73.128 ;
     RECT  27.713 74.112 28.019 75.24 ;
     RECT  27.497 33.36 28.105 33.432 ;
     RECT  27.965 50.928 28.453 73.128 ;
     RECT  28.019 74.112 28.453 74.136 ;
     RECT  28.321 32.304 28.465 32.328 ;
     RECT  28.105 33.36 28.465 33.576 ;
     RECT  28.465 32.304 28.549 33.576 ;
     RECT  27.965 34.704 28.549 49.848 ;
     RECT  28.465 0.48 28.861 0.504 ;
     RECT  28.453 50.928 29.005 74.136 ;
     RECT  28.019 75.168 29.005 75.24 ;
     RECT  29.005 50.928 29.077 75.24 ;
     RECT  28.861 0.48 29.113 0.552 ;
     RECT  29.113 0.48 29.149 0.6 ;
     RECT  27.965 2.448 29.221 30.888 ;
     RECT  29.221 1.728 29.257 30.984 ;
     RECT  28.549 32.304 29.257 49.848 ;
     RECT  29.077 50.928 29.257 75.432 ;
     RECT  29.149 0.48 29.269 0.696 ;
     RECT  29.257 1.728 29.269 31.224 ;
     RECT  29.269 0.48 29.369 31.224 ;
     RECT  29.369 0.48 29.404 0.696 ;
     RECT  29.369 1.728 29.408 31.224 ;
     RECT  29.257 32.304 29.408 75.432 ;
     RECT  29.404 0.48 29.459 0.552 ;
     RECT  29.408 1.728 29.512 75.612 ;
     RECT  29.459 0.48 29.747 0.504 ;
     RECT  29.512 1.728 30.197 75.432 ;
     RECT  30.197 1.728 30.269 75.192 ;
     RECT  30.269 18.72 30.701 75.192 ;
     RECT  30.337 0.096 30.812 0.12 ;
     RECT  30.701 18.72 30.989 75 ;
     RECT  30.269 1.728 31.381 17.736 ;
     RECT  30.989 19.008 31.421 75 ;
     RECT  30.812 0.096 31.571 0.552 ;
     RECT  31.421 19.008 31.673 47.64 ;
     RECT  31.673 40.848 31.852 47.64 ;
     RECT  31.421 48.672 31.921 75 ;
     RECT  31.673 19.008 31.925 39.624 ;
     RECT  31.571 0.096 31.997 0.12 ;
     RECT  31.381 1.728 32.053 17.88 ;
     RECT  32.053 1.728 32.077 18.408 ;
     RECT  31.921 48.672 32.213 75.288 ;
     RECT  32.077 1.776 32.249 18.408 ;
     RECT  32.249 1.824 32.465 18.408 ;
     RECT  31.925 19.536 32.573 39.624 ;
     RECT  32.213 74.592 32.681 75.288 ;
     RECT  32.681 74.928 32.825 75.288 ;
     RECT  32.573 19.536 32.867 39.048 ;
     RECT  31.852 43.392 32.893 47.64 ;
     RECT  32.213 48.672 32.893 73.416 ;
     RECT  31.852 40.848 32.965 42.168 ;
     RECT  32.893 43.392 32.965 73.416 ;
     RECT  32.867 19.536 33.001 33.96 ;
     RECT  33.001 19.488 33.145 33.96 ;
     RECT  32.825 74.928 33.221 74.952 ;
     RECT  32.965 40.848 33.325 73.416 ;
     RECT  32.465 2.544 33.361 18.408 ;
     RECT  33.145 19.44 33.361 33.96 ;
     RECT  32.867 34.944 33.733 39.048 ;
     RECT  33.325 40.848 33.733 73.848 ;
     RECT  33.733 34.944 33.761 73.848 ;
     RECT  33.761 38.016 33.833 73.848 ;
     RECT  33.361 2.544 34.045 33.96 ;
     RECT  33.761 34.944 34.045 36.936 ;
     RECT  33.833 40.416 34.333 73.848 ;
     RECT  34.045 2.544 34.765 36.936 ;
     RECT  34.765 2.544 34.808 37.032 ;
     RECT  33.833 38.016 34.808 39.096 ;
     RECT  34.333 40.416 34.808 73.944 ;
     RECT  34.808 2.148 34.912 75.612 ;
     RECT  34.912 2.418 35.104 75.342 ;
     RECT  35.104 19.536 35.315 75.288 ;
     RECT  35.104 2.544 35.453 18.024 ;
     RECT  35.315 20.592 35.453 75.288 ;
     RECT  35.453 2.544 35.489 17.736 ;
     RECT  35.453 20.592 35.633 48.744 ;
     RECT  35.315 19.536 35.669 19.56 ;
     RECT  35.453 49.728 35.699 75.288 ;
     RECT  35.699 49.728 35.741 75.144 ;
     RECT  35.489 2.544 36.101 17.352 ;
     RECT  36.101 6.24 36.137 17.352 ;
     RECT  35.633 21.216 36.457 48.744 ;
     RECT  35.741 49.728 36.457 73.848 ;
     RECT  36.169 19.104 36.533 19.368 ;
     RECT  36.457 21.216 36.533 73.848 ;
     RECT  36.533 21.216 36.569 41.784 ;
     RECT  36.137 6.24 36.605 17.16 ;
     RECT  36.569 21.216 36.637 35.304 ;
     RECT  35.741 75.12 36.641 75.144 ;
     RECT  36.569 36.288 36.677 41.784 ;
     RECT  36.605 6.24 36.713 16.968 ;
     RECT  36.637 20.4 36.785 35.304 ;
     RECT  36.533 42.768 36.785 73.848 ;
     RECT  36.533 19.104 36.817 19.128 ;
     RECT  36.785 49.824 36.817 73.848 ;
     RECT  36.713 6.24 37.073 16.92 ;
     RECT  36.785 42.768 37.073 48.456 ;
     RECT  36.101 2.544 37.105 5.256 ;
     RECT  37.073 6.24 37.105 10.872 ;
     RECT  37.073 42.768 37.132 48.12 ;
     RECT  37.073 11.952 37.145 16.92 ;
     RECT  36.785 20.4 37.289 35.064 ;
     RECT  36.677 36.288 37.469 38.472 ;
     RECT  37.145 11.952 37.505 16.824 ;
     RECT  36.677 39.504 37.573 41.784 ;
     RECT  37.132 42.768 37.573 47.88 ;
     RECT  36.817 18.144 37.609 19.128 ;
     RECT  37.289 20.4 37.609 25.128 ;
     RECT  37.469 38.304 37.861 38.472 ;
     RECT  37.573 39.504 37.861 47.88 ;
     RECT  37.609 18.144 37.865 25.128 ;
     RECT  37.505 14.448 37.973 16.824 ;
     RECT  37.105 2.544 38.081 10.872 ;
     RECT  37.861 38.304 38.081 47.88 ;
     RECT  36.817 49.824 38.113 74.088 ;
     RECT  37.033 75.36 38.113 75.384 ;
     RECT  37.289 26.112 38.153 35.064 ;
     RECT  38.113 49.824 38.257 75.384 ;
     RECT  38.081 2.544 38.297 10.152 ;
     RECT  38.257 49.488 38.297 75.384 ;
     RECT  38.297 3.312 38.333 10.152 ;
     RECT  37.505 11.952 38.441 13.464 ;
     RECT  38.441 11.952 38.477 13.368 ;
     RECT  37.865 19.104 38.505 25.128 ;
     RECT  37.973 15.744 38.509 16.824 ;
     RECT  38.477 11.952 38.513 13.176 ;
     RECT  38.297 49.488 38.689 74.376 ;
     RECT  37.469 36.288 38.725 36.984 ;
     RECT  38.513 11.952 38.761 12.984 ;
     RECT  38.153 32.208 38.761 35.064 ;
     RECT  38.689 49.248 38.797 74.376 ;
     RECT  38.333 10.128 38.837 10.152 ;
     RECT  38.153 26.112 38.941 31.224 ;
     RECT  38.081 38.448 39.013 47.88 ;
     RECT  38.797 49.008 39.013 74.376 ;
     RECT  38.725 36.288 39.049 37.176 ;
     RECT  38.761 32.208 39.089 35.208 ;
     RECT  39.049 36.288 39.121 37.464 ;
     RECT  39.013 38.448 39.121 74.376 ;
     RECT  39.089 33.6 39.445 35.208 ;
     RECT  39.121 36.288 39.445 74.376 ;
     RECT  39.445 33.6 39.541 74.376 ;
     RECT  38.297 75.36 39.541 75.384 ;
     RECT  38.761 11.376 39.553 12.984 ;
     RECT  38.333 3.312 39.589 9 ;
     RECT  38.505 19.104 39.661 24.648 ;
     RECT  38.509 15.744 39.697 17.16 ;
     RECT  39.661 18.192 39.697 24.648 ;
     RECT  38.941 25.728 39.697 31.224 ;
     RECT  39.089 32.208 39.697 32.616 ;
     RECT  39.589 3.312 39.805 9.816 ;
     RECT  39.553 11.376 39.841 13.368 ;
     RECT  37.973 14.448 39.841 14.712 ;
     RECT  39.841 11.376 40.021 14.712 ;
     RECT  39.697 15.744 40.021 24.648 ;
     RECT  40.021 15.744 40.057 24.744 ;
     RECT  39.697 25.728 40.057 32.616 ;
     RECT  40.057 15.744 40.069 32.616 ;
     RECT  39.541 33.6 40.069 75.384 ;
     RECT  39.805 2.832 40.208 9.816 ;
     RECT  40.021 10.896 40.208 14.712 ;
     RECT  40.069 15.744 40.208 75.384 ;
     RECT  40.208 2.148 40.312 75.612 ;
     RECT  40.312 2.418 40.504 75.342 ;
     RECT  40.504 2.832 40.709 8.52 ;
     RECT  40.709 2.832 40.745 8.328 ;
     RECT  40.745 3.888 40.781 8.328 ;
     RECT  40.745 2.832 40.925 2.856 ;
     RECT  40.504 32.208 41.033 74.616 ;
     RECT  40.504 30.576 41.105 31.176 ;
     RECT  41.033 32.208 41.105 34.2 ;
     RECT  41.105 30.576 41.357 30.936 ;
     RECT  40.504 15.696 41.429 22.152 ;
     RECT  41.357 30.672 41.429 30.936 ;
     RECT  41.105 32.208 41.501 33.624 ;
     RECT  41.429 15.696 41.573 21.048 ;
     RECT  40.504 23.52 41.641 29.256 ;
     RECT  41.033 35.184 41.653 74.616 ;
     RECT  41.653 35.184 41.681 75.288 ;
     RECT  41.641 23.328 41.701 29.256 ;
     RECT  41.429 22.08 41.713 22.152 ;
     RECT  41.701 23.328 41.713 29.592 ;
     RECT  41.573 15.696 41.717 18.744 ;
     RECT  40.781 4.512 41.749 8.328 ;
     RECT  41.749 4.512 41.785 8.472 ;
     RECT  41.713 22.08 41.788 29.592 ;
     RECT  40.504 9.6 41.821 14.712 ;
     RECT  41.681 51.024 41.897 75.288 ;
     RECT  41.788 22.08 41.933 29.256 ;
     RECT  41.429 30.912 42.109 30.936 ;
     RECT  41.501 32.208 42.109 33.048 ;
     RECT  41.681 35.184 42.145 49.896 ;
     RECT  41.821 9.6 42.149 14.856 ;
     RECT  41.785 4.512 42.221 8.616 ;
     RECT  42.145 34.8 42.221 49.896 ;
     RECT  42.181 0.096 42.253 0.12 ;
     RECT  41.933 22.08 42.257 26.952 ;
     RECT  42.253 0.096 42.325 0.6 ;
     RECT  42.325 0.096 42.419 0.648 ;
     RECT  42.109 30.912 42.473 33.048 ;
     RECT  42.221 5.712 42.505 8.616 ;
     RECT  42.149 9.6 42.505 13.848 ;
     RECT  42.505 5.712 42.545 13.848 ;
     RECT  42.397 3.408 42.685 3.432 ;
     RECT  42.221 4.512 42.685 4.728 ;
     RECT  41.573 19.872 42.721 21.048 ;
     RECT  42.257 22.08 42.721 22.104 ;
     RECT  42.149 14.832 42.757 14.856 ;
     RECT  41.717 15.84 42.757 18.744 ;
     RECT  42.721 19.872 42.757 22.104 ;
     RECT  41.933 27.984 42.757 29.256 ;
     RECT  42.221 37.056 42.803 49.896 ;
     RECT  42.757 14.832 42.833 22.104 ;
     RECT  42.419 0.096 42.841 0.552 ;
     RECT  42.803 46.224 42.865 49.896 ;
     RECT  41.897 51.024 42.865 74.664 ;
     RECT  42.841 0.096 42.995 0.504 ;
     RECT  42.833 20.688 43.013 22.104 ;
     RECT  42.257 23.232 43.049 26.952 ;
     RECT  42.545 11.28 43.261 13.848 ;
     RECT  42.833 14.832 43.261 19.512 ;
     RECT  43.261 11.28 43.301 19.512 ;
     RECT  42.803 37.056 43.301 45.192 ;
     RECT  42.221 34.8 43.333 36.072 ;
     RECT  42.865 46.224 43.333 74.664 ;
     RECT  43.013 21.024 43.441 22.104 ;
     RECT  43.049 23.232 43.441 25.224 ;
     RECT  43.333 34.752 43.441 36.072 ;
     RECT  43.301 37.056 43.441 38.808 ;
     RECT  42.473 32.304 43.513 33.048 ;
     RECT  43.301 39.792 43.553 45.192 ;
     RECT  43.441 21.024 43.571 25.224 ;
     RECT  43.513 32.304 43.585 33.576 ;
     RECT  43.333 46.224 43.585 74.712 ;
     RECT  43.301 11.28 43.589 18.168 ;
     RECT  43.585 46.224 43.667 75.144 ;
     RECT  43.585 32.016 43.697 33.576 ;
     RECT  42.641 1.728 43.729 1.752 ;
     RECT  42.545 5.712 43.729 10.296 ;
     RECT  43.589 11.28 43.729 15.048 ;
     RECT  43.589 16.272 43.733 18.168 ;
     RECT  42.757 27.984 43.837 30.168 ;
     RECT  43.049 26.208 43.841 26.952 ;
     RECT  43.553 40.032 43.877 45.192 ;
     RECT  43.441 34.752 43.907 38.808 ;
     RECT  43.667 46.224 43.913 48.456 ;
     RECT  42.995 0.096 43.985 0.12 ;
     RECT  43.697 32.016 44.021 32.376 ;
     RECT  43.837 27.984 44.053 30.84 ;
     RECT  42.685 3.408 44.089 4.728 ;
     RECT  43.729 5.712 44.089 15.048 ;
     RECT  44.021 32.064 44.093 32.376 ;
     RECT  43.907 34.752 44.165 35.448 ;
     RECT  43.301 19.488 44.233 19.512 ;
     RECT  44.053 27.84 44.237 30.84 ;
     RECT  44.089 3.408 44.243 15.048 ;
     RECT  43.733 18.144 44.269 18.168 ;
     RECT  44.233 19.488 44.269 20.424 ;
     RECT  43.729 1.728 44.305 1.8 ;
     RECT  43.571 21.744 44.309 25.224 ;
     RECT  44.309 22.416 44.348 25.224 ;
     RECT  43.841 26.208 44.348 26.616 ;
     RECT  43.877 41.088 44.413 45.192 ;
     RECT  44.413 41.088 44.417 45.288 ;
     RECT  43.697 33.36 44.449 33.576 ;
     RECT  44.237 28.512 44.453 30.84 ;
     RECT  44.243 3.6 44.489 15.048 ;
     RECT  44.485 0.576 44.569 0.6 ;
     RECT  43.667 49.488 44.593 75.144 ;
     RECT  44.305 1.728 44.627 2.28 ;
     RECT  44.165 34.752 44.633 34.92 ;
     RECT  43.877 40.032 44.633 40.056 ;
     RECT  43.913 46.704 44.953 48.456 ;
     RECT  44.593 49.488 44.953 75.432 ;
     RECT  44.093 32.16 45.025 32.376 ;
     RECT  44.449 33.36 45.025 33.768 ;
     RECT  44.348 22.416 45.061 26.616 ;
     RECT  44.269 18.144 45.169 20.424 ;
     RECT  44.489 3.6 45.205 11.16 ;
     RECT  44.417 42.288 45.205 45.288 ;
     RECT  44.953 46.704 45.205 75.432 ;
     RECT  43.733 16.272 45.349 16.776 ;
     RECT  45.169 18.144 45.385 21.144 ;
     RECT  45.025 32.16 45.385 33.768 ;
     RECT  45.385 31.92 45.421 33.768 ;
     RECT  44.633 34.752 45.421 34.776 ;
     RECT  45.205 2.784 45.452 11.16 ;
     RECT  44.489 12.144 45.452 14.808 ;
     RECT  45.205 42.288 45.452 75.432 ;
     RECT  44.417 41.088 45.457 41.112 ;
     RECT  45.452 42.144 45.457 75.432 ;
     RECT  44.627 1.728 45.461 1.8 ;
     RECT  45.349 16.272 45.493 16.824 ;
     RECT  45.385 18.144 45.529 21.384 ;
     RECT  45.061 22.416 45.529 26.952 ;
     RECT  45.452 2.784 45.608 14.808 ;
     RECT  45.493 16.272 45.608 16.92 ;
     RECT  45.529 18.144 45.608 21.432 ;
     RECT  45.529 22.416 45.608 27.624 ;
     RECT  44.453 28.656 45.608 30.84 ;
     RECT  45.421 31.92 45.608 34.776 ;
     RECT  43.907 36.576 45.608 38.808 ;
     RECT  45.205 39.84 45.608 39.864 ;
     RECT  45.457 41.088 45.608 75.432 ;
     RECT  45.608 2.148 45.712 75.612 ;
     RECT  45.712 2.418 45.904 75.432 ;
     RECT  45.904 12.24 45.929 13.416 ;
     RECT  45.904 37.584 45.965 51.768 ;
     RECT  45.929 12.336 46.037 13.416 ;
     RECT  45.904 29.808 46.037 34.968 ;
     RECT  45.904 52.752 46.037 71.736 ;
     RECT  45.965 37.68 46.109 51.768 ;
     RECT  45.904 14.448 46.145 20.376 ;
     RECT  45.904 10.656 46.181 11.208 ;
     RECT  45.904 23.472 46.181 23.496 ;
     RECT  46.109 37.68 46.181 51.192 ;
     RECT  46.037 52.8 46.181 71.736 ;
     RECT  46.181 65.424 46.253 71.736 ;
     RECT  46.145 14.448 46.361 19.896 ;
     RECT  46.181 52.8 46.469 63.768 ;
     RECT  46.469 52.896 46.541 63.768 ;
     RECT  46.181 37.68 46.685 51.144 ;
     RECT  46.361 14.448 46.757 19.656 ;
     RECT  46.253 65.424 46.829 71.688 ;
     RECT  46.757 14.448 46.865 15.432 ;
     RECT  45.904 24.624 46.892 25.32 ;
     RECT  45.904 26.352 46.892 27.96 ;
     RECT  46.757 16.512 46.901 19.656 ;
     RECT  45.904 21.408 46.901 22.488 ;
     RECT  46.865 14.448 46.969 15.384 ;
     RECT  45.904 2.832 46.988 9.624 ;
     RECT  46.933 36.624 47.005 36.648 ;
     RECT  46.685 37.68 47.005 44.808 ;
     RECT  46.969 14.016 47.009 15.384 ;
     RECT  46.541 52.992 47.009 63.768 ;
     RECT  47.009 15.264 47.045 15.384 ;
     RECT  46.892 24.624 47.081 27.96 ;
     RECT  46.181 10.8 47.105 11.208 ;
     RECT  46.037 12.336 47.105 12.552 ;
     RECT  47.081 25.104 47.113 27.96 ;
     RECT  47.113 25.104 47.117 28.152 ;
     RECT  46.901 21.408 47.221 22.296 ;
     RECT  47.221 21.168 47.297 22.296 ;
     RECT  46.037 29.808 47.315 34.2 ;
     RECT  46.988 2.832 47.329 9.768 ;
     RECT  47.105 10.8 47.329 12.552 ;
     RECT  47.009 53.04 47.329 63.768 ;
     RECT  47.329 35.424 47.401 35.448 ;
     RECT  47.005 36.624 47.401 44.808 ;
     RECT  47.315 32.256 47.404 34.2 ;
     RECT  47.329 2.832 47.405 12.552 ;
     RECT  47.405 8.976 47.437 12.552 ;
     RECT  46.901 16.512 47.459 19.512 ;
     RECT  47.329 53.04 47.477 64.392 ;
     RECT  47.459 16.56 47.5 19.512 ;
     RECT  47.315 29.808 47.509 30.984 ;
     RECT  47.477 53.088 47.603 64.392 ;
     RECT  45.904 72.768 47.612 74.328 ;
     RECT  47.509 29.328 47.621 30.984 ;
     RECT  46.685 46.128 47.653 51.144 ;
     RECT  47.612 72.384 47.689 74.328 ;
     RECT  45.904 75.408 47.689 75.432 ;
     RECT  47.405 2.832 47.747 7.992 ;
     RECT  47.404 32.256 47.765 33.096 ;
     RECT  47.621 29.328 47.797 29.352 ;
     RECT  46.829 65.424 47.836 71.256 ;
     RECT  47.689 72.384 47.837 75.432 ;
     RECT  47.117 25.296 47.843 28.152 ;
     RECT  47.765 32.256 47.873 32.808 ;
     RECT  47.401 35.424 47.893 44.808 ;
     RECT  47.437 8.976 47.939 12.888 ;
     RECT  47.836 70.512 47.977 71.256 ;
     RECT  47.837 72.384 47.977 74.616 ;
     RECT  47.893 35.232 47.98 45 ;
     RECT  47.297 21.168 47.981 22.2 ;
     RECT  47.843 26.208 47.981 28.152 ;
     RECT  47.98 35.232 47.987 36.216 ;
     RECT  47.797 29.184 48.049 29.352 ;
     RECT  47.977 70.512 48.053 74.616 ;
     RECT  47.836 65.424 48.076 69.48 ;
     RECT  47.939 10.848 48.085 12.888 ;
     RECT  47.009 14.016 48.085 14.28 ;
     RECT  47.5 18.144 48.085 19.512 ;
     RECT  47.404 34.08 48.121 34.2 ;
     RECT  47.653 46.128 48.157 51.528 ;
     RECT  47.939 8.976 48.205 9.72 ;
     RECT  47.747 3.552 48.269 7.992 ;
     RECT  47.981 26.208 48.269 27.432 ;
     RECT  47.98 37.584 48.275 45 ;
     RECT  48.085 10.848 48.284 14.28 ;
     RECT  47.045 15.36 48.284 15.384 ;
     RECT  47.981 21.936 48.301 22.2 ;
     RECT  48.049 28.416 48.305 29.352 ;
     RECT  48.275 37.584 48.371 43.416 ;
     RECT  48.275 44.64 48.373 45 ;
     RECT  48.157 46.128 48.373 51.912 ;
     RECT  48.301 21.936 48.409 22.824 ;
     RECT  47.221 23.904 48.409 23.976 ;
     RECT  47.621 30.96 48.409 30.984 ;
     RECT  48.371 39.6 48.413 41.592 ;
     RECT  48.373 44.64 48.419 51.912 ;
     RECT  48.205 8.976 48.421 9.384 ;
     RECT  48.419 46.8 48.445 51.912 ;
     RECT  47.603 53.568 48.445 64.392 ;
     RECT  48.076 65.424 48.445 67.032 ;
     RECT  48.269 26.208 48.449 27.336 ;
     RECT  48.419 44.64 48.46 45.576 ;
     RECT  48.413 39.792 48.485 41.592 ;
     RECT  48.284 0.528 48.517 0.552 ;
     RECT  47.5 16.56 48.553 17.064 ;
     RECT  48.085 18.144 48.553 19.992 ;
     RECT  48.121 34.08 48.557 34.248 ;
     RECT  48.517 0.096 48.572 0.552 ;
     RECT  48.337 1.728 48.572 1.752 ;
     RECT  48.371 37.584 48.593 38.568 ;
     RECT  48.445 53.568 48.62 67.032 ;
     RECT  47.873 32.256 48.629 32.472 ;
     RECT  48.572 0.096 48.659 1.752 ;
     RECT  48.593 37.584 48.701 38.472 ;
     RECT  48.269 3.552 48.769 7.464 ;
     RECT  48.659 0.096 48.773 0.168 ;
     RECT  48.371 42.72 48.864 43.416 ;
     RECT  48.553 16.56 48.913 19.992 ;
     RECT  48.053 70.56 48.913 74.616 ;
     RECT  48.409 30.96 48.949 31.128 ;
     RECT  48.62 53.52 48.953 67.032 ;
     RECT  48.445 46.8 48.985 52.44 ;
     RECT  48.953 53.52 48.985 59.592 ;
     RECT  48.659 1.728 48.989 1.752 ;
     RECT  48.076 68.352 48.997 69.48 ;
     RECT  48.997 68.352 49.021 69.528 ;
     RECT  48.913 70.56 49.021 75.432 ;
     RECT  48.953 60.576 49.057 67.032 ;
     RECT  49.057 60.576 49.165 67.08 ;
     RECT  49.021 68.352 49.165 75.432 ;
     RECT  48.913 16.56 49.201 20.184 ;
     RECT  48.773 0.144 49.205 0.168 ;
     RECT  49.201 16.56 49.237 20.328 ;
     RECT  48.409 21.936 49.237 23.976 ;
     RECT  49.237 16.368 49.283 23.976 ;
     RECT  48.485 40.224 49.313 41.592 ;
     RECT  49.313 40.224 49.324 41.544 ;
     RECT  48.421 8.88 49.333 9.384 ;
     RECT  48.284 10.848 49.333 15.384 ;
     RECT  49.333 8.88 49.34 15.384 ;
     RECT  49.283 16.368 49.34 21.672 ;
     RECT  48.864 42.72 49.34 43.272 ;
     RECT  48.949 30.816 49.345 31.128 ;
     RECT  48.629 32.256 49.345 32.28 ;
     RECT  49.165 60.576 49.349 75.432 ;
     RECT  49.345 30.816 49.385 32.28 ;
     RECT  49.34 42.576 49.427 43.272 ;
     RECT  49.324 41.04 49.493 41.544 ;
     RECT  48.769 2.88 49.497 7.464 ;
     RECT  49.283 22.8 49.529 23.976 ;
     RECT  49.529 23.952 49.561 23.976 ;
     RECT  48.985 46.8 49.561 59.592 ;
     RECT  49.34 8.88 49.571 21.672 ;
     RECT  49.497 2.88 49.597 7.656 ;
     RECT  49.571 8.88 49.597 15.48 ;
     RECT  49.417 30.336 49.619 30.36 ;
     RECT  49.597 2.88 49.637 15.48 ;
     RECT  48.449 27.312 49.673 27.336 ;
     RECT  48.557 34.128 49.705 34.248 ;
     RECT  49.571 16.896 49.709 21.672 ;
     RECT  48.449 26.208 49.717 26.232 ;
     RECT  49.717 26.112 49.741 26.232 ;
     RECT  47.987 35.232 49.741 35.448 ;
     RECT  49.453 37.152 49.741 37.176 ;
     RECT  49.561 23.952 49.777 24.552 ;
     RECT  49.529 22.8 49.811 22.92 ;
     RECT  49.705 34.08 49.849 34.248 ;
     RECT  49.741 35.232 49.849 35.544 ;
     RECT  49.741 37.056 49.849 37.176 ;
     RECT  48.46 44.64 49.849 45 ;
     RECT  49.561 46.752 49.849 59.592 ;
     RECT  49.385 31.344 49.909 32.28 ;
     RECT  49.849 34.08 49.909 35.544 ;
     RECT  49.849 37.008 49.921 37.176 ;
     RECT  48.701 38.208 49.921 38.472 ;
     RECT  49.849 44.64 49.921 59.592 ;
     RECT  49.349 60.768 49.925 75.432 ;
     RECT  49.427 42.72 50.029 43.272 ;
     RECT  49.925 65.424 50.033 75.432 ;
     RECT  49.921 44.64 50.065 59.784 ;
     RECT  50.065 44.352 50.353 59.784 ;
     RECT  49.925 60.768 50.353 63.864 ;
     RECT  49.777 23.952 50.389 25.08 ;
     RECT  49.921 37.008 50.425 38.472 ;
     RECT  49.709 16.896 50.533 21.48 ;
     RECT  50.389 23.952 50.533 25.128 ;
     RECT  49.741 26.112 50.641 26.28 ;
     RECT  50.533 23.856 50.677 25.128 ;
     RECT  50.641 26.112 50.677 26.904 ;
     RECT  50.029 42.72 50.677 43.32 ;
     RECT  49.493 41.04 50.684 41.064 ;
     RECT  50.677 42.24 50.684 43.32 ;
     RECT  49.637 2.88 50.713 15.336 ;
     RECT  50.713 2.88 50.741 15.432 ;
     RECT  50.533 16.512 50.741 21.48 ;
     RECT  50.741 2.88 50.773 21.48 ;
     RECT  50.425 37.008 50.785 38.808 ;
     RECT  49.813 39.936 50.785 39.96 ;
     RECT  50.785 37.008 50.821 39.96 ;
     RECT  50.773 2.88 50.857 21.528 ;
     RECT  49.811 22.8 50.857 22.824 ;
     RECT  50.684 41.04 50.869 43.32 ;
     RECT  50.353 44.352 50.869 63.864 ;
     RECT  50.857 2.88 50.929 22.824 ;
     RECT  50.677 23.856 50.929 26.904 ;
     RECT  48.305 28.416 50.965 29.256 ;
     RECT  49.909 31.344 50.965 35.544 ;
     RECT  50.869 41.04 50.965 63.864 ;
     RECT  50.929 2.88 51.008 26.904 ;
     RECT  50.965 27.936 51.008 29.256 ;
     RECT  50.965 31.344 51.008 36.024 ;
     RECT  50.821 37.008 51.008 40.056 ;
     RECT  50.965 41.04 51.008 64.152 ;
     RECT  50.033 65.424 51.008 69.576 ;
     RECT  50.033 70.848 51.008 75.432 ;
     RECT  51.008 2.148 51.112 75.612 ;
     RECT  51.112 2.418 51.304 75.432 ;
     RECT  51.301 0.096 51.361 0.216 ;
     RECT  51.304 30.72 51.509 66.12 ;
     RECT  51.509 30.72 51.689 53.064 ;
     RECT  51.509 54.288 51.689 66.12 ;
     RECT  51.304 16.32 51.833 28.152 ;
     RECT  51.361 0.096 51.865 0.552 ;
     RECT  51.304 75.264 51.869 75.432 ;
     RECT  51.865 0.096 51.937 0.6 ;
     RECT  51.689 31.248 52.301 53.064 ;
     RECT  51.833 16.32 52.451 24.408 ;
     RECT  51.689 60 52.513 66.12 ;
     RECT  51.304 67.104 52.513 73.8 ;
     RECT  51.937 0.096 52.525 0.648 ;
     RECT  52.513 60 52.585 73.8 ;
     RECT  51.304 3.84 52.621 15.336 ;
     RECT  52.301 42.672 52.657 53.064 ;
     RECT  51.689 54.288 52.657 59.016 ;
     RECT  52.621 3.408 52.697 15.336 ;
     RECT  52.657 42.672 52.729 59.016 ;
     RECT  52.585 60 52.729 73.944 ;
     RECT  52.697 7.392 52.769 15.048 ;
     RECT  52.697 3.408 52.787 6.36 ;
     RECT  51.869 75.264 52.805 75.288 ;
     RECT  51.833 25.488 52.837 28.152 ;
     RECT  52.729 42.672 52.909 73.944 ;
     RECT  52.451 18.192 52.913 24.408 ;
     RECT  52.913 18.384 52.933 24.408 ;
     RECT  52.837 25.488 52.933 28.488 ;
     RECT  52.933 18.384 53.029 28.488 ;
     RECT  52.189 1.728 53.053 1.752 ;
     RECT  52.451 16.32 53.057 17.112 ;
     RECT  53.029 18.384 53.057 29.208 ;
     RECT  52.301 31.248 53.129 41.496 ;
     RECT  53.057 19.824 53.171 29.208 ;
     RECT  52.909 42.672 53.273 74.136 ;
     RECT  53.129 31.248 53.309 41.448 ;
     RECT  53.171 19.824 53.363 29.112 ;
     RECT  53.273 42.672 53.377 52.824 ;
     RECT  52.477 30.24 53.509 30.264 ;
     RECT  53.309 31.248 53.509 38.712 ;
     RECT  53.309 40.032 53.555 41.448 ;
     RECT  53.363 21.264 53.597 29.112 ;
     RECT  53.057 16.32 53.737 17.064 ;
     RECT  53.273 53.904 53.741 74.136 ;
     RECT  53.053 1.728 53.797 1.8 ;
     RECT  52.769 7.488 53.809 15.048 ;
     RECT  53.509 30.24 53.849 38.712 ;
     RECT  53.741 55.44 53.885 74.136 ;
     RECT  52.787 3.648 53.917 6.36 ;
     RECT  53.809 7.44 53.917 15.048 ;
     RECT  53.885 60.336 54.025 74.136 ;
     RECT  53.797 1.728 54.053 2.28 ;
     RECT  53.917 3.648 54.053 15.048 ;
     RECT  53.057 18.384 54.061 18.456 ;
     RECT  53.363 19.824 54.061 20.184 ;
     RECT  53.849 30.336 54.065 38.712 ;
     RECT  53.377 42.576 54.101 52.824 ;
     RECT  54.053 1.728 54.137 15.048 ;
     RECT  52.525 0.096 54.173 0.552 ;
     RECT  54.137 1.728 54.245 2.28 ;
     RECT  54.137 3.312 54.281 15.048 ;
     RECT  54.065 30.576 54.281 38.712 ;
     RECT  53.737 16.08 54.313 17.064 ;
     RECT  54.313 16.08 54.349 17.16 ;
     RECT  54.061 18.384 54.349 20.184 ;
     RECT  54.025 60.336 54.353 74.28 ;
     RECT  54.281 10.608 54.421 15.048 ;
     RECT  54.349 16.08 54.421 20.184 ;
     RECT  54.281 34.656 54.421 38.712 ;
     RECT  54.421 34.656 54.529 39.048 ;
     RECT  53.555 40.032 54.529 41.4 ;
     RECT  54.245 1.728 54.641 1.8 ;
     RECT  54.529 34.656 54.673 41.4 ;
     RECT  54.101 42.576 54.673 45.288 ;
     RECT  53.597 21.84 54.677 29.112 ;
     RECT  54.673 34.656 54.803 45.288 ;
     RECT  54.353 60.336 54.893 73.752 ;
     RECT  54.893 60.432 55.037 73.752 ;
     RECT  53.885 55.44 55.093 59.112 ;
     RECT  54.101 46.368 55.141 52.824 ;
     RECT  53.741 53.904 55.141 54.456 ;
     RECT  54.803 35.76 55.213 45.288 ;
     RECT  55.141 46.368 55.213 54.456 ;
     RECT  54.803 34.656 55.217 34.68 ;
     RECT  54.173 0.48 55.237 0.552 ;
     RECT  54.281 30.576 55.249 33.624 ;
     RECT  55.213 35.76 55.249 54.456 ;
     RECT  55.093 55.44 55.249 59.448 ;
     RECT  54.421 10.608 55.289 20.184 ;
     RECT  54.281 3.312 55.388 9.624 ;
     RECT  55.289 10.608 55.388 14.472 ;
     RECT  55.237 0.096 55.585 0.552 ;
     RECT  54.641 1.728 55.621 1.752 ;
     RECT  55.037 60.528 55.645 73.752 ;
     RECT  53.881 75.264 55.789 75.288 ;
     RECT  55.249 35.76 55.861 59.448 ;
     RECT  55.621 1.728 56.005 2.328 ;
     RECT  55.388 3.312 56.005 14.472 ;
     RECT  55.861 35.424 56.041 59.448 ;
     RECT  55.645 60.528 56.041 74.088 ;
     RECT  55.585 0.528 56.197 0.552 ;
     RECT  55.289 15.456 56.329 20.184 ;
     RECT  56.005 1.728 56.408 14.472 ;
     RECT  56.329 15.456 56.408 20.616 ;
     RECT  54.677 21.84 56.408 29.064 ;
     RECT  55.249 30.048 56.408 33.912 ;
     RECT  56.041 35.424 56.408 74.088 ;
     RECT  55.789 75.12 56.408 75.288 ;
     RECT  56.197 0.528 56.435 0.648 ;
     RECT  56.408 1.728 56.512 75.612 ;
     RECT  56.512 1.728 56.704 75.342 ;
     RECT  56.704 1.728 56.837 18.984 ;
     RECT  56.704 20.352 56.909 28.632 ;
     RECT  56.704 37.008 56.909 52.776 ;
     RECT  56.837 2.832 56.915 18.984 ;
     RECT  56.915 2.88 56.963 18.984 ;
     RECT  56.435 0.528 56.965 0.6 ;
     RECT  56.704 29.712 57.089 33.912 ;
     RECT  56.704 54 57.089 75.144 ;
     RECT  56.965 0.096 57.133 0.6 ;
     RECT  57.133 0.096 57.233 0.168 ;
     RECT  57.089 54 57.269 59.832 ;
     RECT  57.089 60.816 57.413 75.144 ;
     RECT  56.837 1.728 57.491 1.848 ;
     RECT  56.963 17.52 57.491 18.984 ;
     RECT  57.413 60.816 57.557 69.432 ;
     RECT  57.557 60.816 57.593 61.992 ;
     RECT  56.704 35.76 57.685 35.832 ;
     RECT  56.909 25.536 57.697 28.632 ;
     RECT  56.909 37.008 57.731 41.64 ;
     RECT  56.909 20.352 57.733 24.504 ;
     RECT  57.089 30.288 57.737 33.912 ;
     RECT  57.557 63.072 57.773 69.432 ;
     RECT  57.491 17.616 57.805 18.984 ;
     RECT  57.733 20.304 57.805 24.504 ;
     RECT  57.737 30.384 57.985 33.912 ;
     RECT  56.963 2.88 58.021 16.536 ;
     RECT  57.985 30.384 58.057 34.728 ;
     RECT  57.685 35.76 58.057 36.024 ;
     RECT  57.731 37.056 58.067 41.64 ;
     RECT  57.805 17.616 58.093 24.504 ;
     RECT  57.697 25.536 58.093 29.112 ;
     RECT  58.093 17.616 58.097 29.112 ;
     RECT  57.413 70.608 58.097 75.144 ;
     RECT  56.909 43.104 58.117 52.776 ;
     RECT  58.067 40.128 58.163 41.64 ;
     RECT  57.233 0.096 58.169 0.12 ;
     RECT  58.097 21.456 58.169 29.112 ;
     RECT  58.021 2.256 58.258 16.536 ;
     RECT  58.057 30.384 58.393 36.024 ;
     RECT  58.117 42.768 58.453 52.776 ;
     RECT  57.773 66.336 58.453 69.432 ;
     RECT  58.097 70.608 58.453 74.712 ;
     RECT  58.097 17.616 58.549 20.424 ;
     RECT  58.258 2.256 58.561 16.584 ;
     RECT  58.549 17.568 58.561 20.424 ;
     RECT  57.593 60.816 58.691 61.944 ;
     RECT  58.393 34.368 58.849 36.024 ;
     RECT  58.067 37.056 58.849 39 ;
     RECT  57.773 63.072 58.849 65.304 ;
     RECT  57.269 54.048 58.853 59.832 ;
     RECT  58.849 34.368 58.889 39 ;
     RECT  58.691 61.92 58.933 61.944 ;
     RECT  58.849 63.024 58.933 65.304 ;
     RECT  58.163 40.128 58.979 41.592 ;
     RECT  58.889 34.368 58.997 35.208 ;
     RECT  58.453 42.768 59.105 52.92 ;
     RECT  58.169 21.504 59.173 29.112 ;
     RECT  58.393 30.384 59.173 33.336 ;
     RECT  58.889 36.384 59.173 39 ;
     RECT  58.979 40.128 59.173 41.304 ;
     RECT  59.105 46.8 59.177 52.92 ;
     RECT  59.173 36.384 59.213 41.304 ;
     RECT  58.561 2.256 59.221 20.424 ;
     RECT  59.173 21.504 59.221 33.336 ;
     RECT  59.105 42.768 59.267 45.768 ;
     RECT  59.267 42.768 59.281 45.576 ;
     RECT  58.853 54.048 59.285 59.208 ;
     RECT  59.177 46.848 59.317 52.92 ;
     RECT  58.691 60.816 59.353 60.936 ;
     RECT  59.281 42.672 59.357 45.576 ;
     RECT  58.453 66.336 59.389 74.712 ;
     RECT  59.221 2.256 59.393 33.336 ;
     RECT  58.933 61.92 59.461 65.304 ;
     RECT  59.389 66.336 59.461 75.288 ;
     RECT  59.213 36.384 59.501 41.112 ;
     RECT  59.353 60.336 59.713 60.936 ;
     RECT  59.461 61.92 59.713 75.288 ;
     RECT  59.393 26.064 59.749 33.336 ;
     RECT  58.997 34.368 59.749 35.016 ;
     RECT  59.393 2.256 59.969 24.936 ;
     RECT  59.749 26.064 60.253 35.016 ;
     RECT  59.501 37.008 60.253 41.112 ;
     RECT  59.357 42.672 60.253 45.144 ;
     RECT  60.253 26.064 60.257 35.16 ;
     RECT  59.713 60.336 60.257 75.288 ;
     RECT  59.285 54.384 60.289 59.208 ;
     RECT  60.257 30.576 60.325 35.16 ;
     RECT  60.257 60.336 60.419 74.664 ;
     RECT  59.317 46.848 60.469 53.016 ;
     RECT  60.289 54.384 60.473 59.304 ;
     RECT  60.419 60.336 60.473 69.48 ;
     RECT  60.419 70.896 60.473 74.664 ;
     RECT  60.253 37.008 60.476 45.144 ;
     RECT  60.476 37.008 60.505 45.432 ;
     RECT  60.469 46.656 60.505 53.016 ;
     RECT  60.473 54.384 60.613 55.56 ;
     RECT  59.969 2.592 60.793 24.936 ;
     RECT  60.505 37.008 60.829 53.016 ;
     RECT  60.613 54.144 60.829 55.56 ;
     RECT  60.473 57.024 60.829 59.304 ;
     RECT  60.473 60.336 60.829 63.576 ;
     RECT  60.793 2.592 60.865 25.08 ;
     RECT  60.257 26.064 60.865 29.592 ;
     RECT  60.325 30.576 61.009 35.256 ;
     RECT  60.829 37.008 61.117 55.56 ;
     RECT  61.009 30.576 61.153 35.736 ;
     RECT  61.117 36.96 61.153 55.56 ;
     RECT  60.973 0.576 61.381 0.6 ;
     RECT  60.473 65.184 61.477 69.48 ;
     RECT  61.381 0.096 61.481 0.6 ;
     RECT  61.481 0.528 61.522 0.6 ;
     RECT  61.153 30.576 61.573 55.56 ;
     RECT  60.829 57.024 61.573 63.576 ;
     RECT  60.865 2.592 61.585 29.592 ;
     RECT  61.522 0.528 61.633 0.648 ;
     RECT  61.477 64.704 61.765 69.48 ;
     RECT  60.473 70.896 61.765 74.616 ;
     RECT  61.585 1.728 61.808 29.592 ;
     RECT  61.573 30.576 61.808 63.576 ;
     RECT  61.765 64.704 61.808 74.616 ;
     RECT  61.633 0.528 61.849 0.6 ;
     RECT  61.808 1.728 61.912 75.612 ;
     RECT  61.912 1.728 62.104 75.342 ;
     RECT  62.104 56.352 62.165 66.072 ;
     RECT  62.104 19.824 62.201 21.576 ;
     RECT  62.104 22.56 62.201 49.848 ;
     RECT  62.201 44.112 62.237 49.848 ;
     RECT  62.104 51.216 62.237 54.168 ;
     RECT  62.104 3.12 62.273 18.552 ;
     RECT  62.201 22.56 62.273 43.128 ;
     RECT  62.104 1.728 62.387 1.8 ;
     RECT  62.273 22.56 62.453 33.048 ;
     RECT  62.104 55.152 62.483 55.176 ;
     RECT  62.165 57.072 62.489 66.072 ;
     RECT  62.453 22.8 62.741 33.048 ;
     RECT  62.273 34.128 62.741 43.128 ;
     RECT  61.849 0.528 62.785 0.552 ;
     RECT  62.489 61.008 62.813 66.072 ;
     RECT  62.237 52.176 62.885 54.168 ;
     RECT  62.104 67.056 62.993 75.288 ;
     RECT  62.885 54.048 63.137 54.168 ;
     RECT  62.993 68.064 63.137 75.288 ;
     RECT  62.953 0.144 63.205 0.168 ;
     RECT  62.273 3.552 63.277 18.552 ;
     RECT  63.241 50.928 63.313 50.952 ;
     RECT  62.885 52.176 63.313 53.016 ;
     RECT  63.137 54.096 63.313 54.168 ;
     RECT  63.137 68.064 63.317 74.856 ;
     RECT  62.741 40.416 63.349 43.128 ;
     RECT  62.237 44.304 63.349 49.848 ;
     RECT  63.313 50.928 63.349 53.016 ;
     RECT  63.313 54.096 63.353 54.216 ;
     RECT  63.277 3.552 63.377 18.744 ;
     RECT  62.813 61.344 63.457 66.072 ;
     RECT  62.993 67.056 63.457 67.08 ;
     RECT  63.377 3.408 63.461 18.744 ;
     RECT  63.353 54.192 63.461 54.216 ;
     RECT  62.201 19.92 63.493 21.576 ;
     RECT  62.489 57.072 63.493 60.024 ;
     RECT  63.493 57.072 63.529 60.072 ;
     RECT  63.493 19.92 63.565 21.816 ;
     RECT  62.741 22.8 63.565 23.688 ;
     RECT  62.741 25.056 63.565 33.048 ;
     RECT  62.741 34.128 63.605 39.288 ;
     RECT  62.387 1.728 63.637 1.752 ;
     RECT  63.637 1.728 63.673 1.8 ;
     RECT  63.317 70.56 63.677 74.856 ;
     RECT  63.565 25.056 63.781 33.096 ;
     RECT  63.673 1.728 63.827 1.896 ;
     RECT  63.205 0.096 63.836 0.168 ;
     RECT  63.529 56.592 63.857 60.072 ;
     RECT  63.677 74.832 63.893 74.856 ;
     RECT  63.836 0.096 63.923 0.552 ;
     RECT  63.565 19.92 63.925 23.688 ;
     RECT  63.781 25.056 63.925 33.576 ;
     RECT  63.457 61.344 63.961 67.08 ;
     RECT  63.317 68.064 63.961 69.576 ;
     RECT  63.461 3.552 64.133 18.744 ;
     RECT  63.857 57.024 64.177 60.072 ;
     RECT  63.961 61.344 64.177 69.576 ;
     RECT  63.827 1.728 64.211 1.752 ;
     RECT  64.133 3.552 64.217 18.84 ;
     RECT  64.177 57.024 64.253 69.576 ;
     RECT  64.177 54.432 64.285 54.456 ;
     RECT  64.253 61.488 64.325 69.576 ;
     RECT  64.217 3.552 64.465 18.552 ;
     RECT  63.349 40.416 64.465 53.016 ;
     RECT  63.925 19.92 64.469 33.576 ;
     RECT  64.465 3.216 64.537 18.552 ;
     RECT  64.469 19.92 64.541 29.16 ;
     RECT  63.605 34.608 64.609 39.288 ;
     RECT  64.465 40.416 64.609 53.112 ;
     RECT  64.285 54.432 64.613 55.416 ;
     RECT  63.677 70.56 64.645 73.8 ;
     RECT  63.923 0.096 64.649 0.216 ;
     RECT  64.469 30.288 64.717 33.576 ;
     RECT  64.609 34.608 64.717 53.112 ;
     RECT  64.613 54.432 64.721 55.272 ;
     RECT  64.541 19.92 64.829 29.112 ;
     RECT  64.325 61.92 64.861 69.576 ;
     RECT  64.645 70.56 64.861 73.848 ;
     RECT  64.537 3.168 64.933 18.552 ;
     RECT  64.861 61.92 64.937 73.848 ;
     RECT  64.829 19.92 64.981 24.744 ;
     RECT  64.933 2.256 65.009 18.552 ;
     RECT  64.981 19.68 65.068 24.744 ;
     RECT  64.649 0.096 65.081 0.12 ;
     RECT  64.721 54.432 65.117 54.696 ;
     RECT  65.068 20.016 65.123 24.744 ;
     RECT  65.009 14.784 65.217 18.552 ;
     RECT  64.937 65.184 65.221 73.848 ;
     RECT  64.717 30.288 65.261 53.112 ;
     RECT  64.937 61.92 65.365 63.864 ;
     RECT  65.261 32.832 65.401 53.112 ;
     RECT  65.217 18.096 65.437 18.552 ;
     RECT  65.401 32.832 65.549 53.16 ;
     RECT  65.549 46.512 65.555 53.16 ;
     RECT  64.829 25.776 65.581 29.112 ;
     RECT  65.261 30.288 65.581 31.8 ;
     RECT  65.555 46.512 65.621 53.112 ;
     RECT  65.365 61.728 65.689 63.864 ;
     RECT  65.123 20.016 65.873 24.648 ;
     RECT  65.117 54.432 65.945 54.456 ;
     RECT  65.009 2.256 66.013 13.464 ;
     RECT  65.437 18.096 66.037 18.84 ;
     RECT  64.253 57.024 66.049 60.504 ;
     RECT  66.037 18.096 66.121 18.984 ;
     RECT  65.873 20.016 66.121 20.04 ;
     RECT  65.873 21.36 66.157 24.648 ;
     RECT  65.581 25.776 66.157 31.8 ;
     RECT  66.049 56.88 66.197 60.504 ;
     RECT  65.689 61.68 66.197 63.864 ;
     RECT  66.197 59.52 66.265 60.504 ;
     RECT  66.197 61.68 66.265 63.384 ;
     RECT  66.013 2.256 66.445 13.656 ;
     RECT  65.217 14.784 66.445 16.392 ;
     RECT  66.157 21.36 66.481 31.8 ;
     RECT  65.549 32.832 66.481 45.48 ;
     RECT  66.445 2.256 66.517 16.392 ;
     RECT  65.621 46.512 66.613 51.288 ;
     RECT  65.621 52.272 66.613 53.112 ;
     RECT  65.221 65.184 66.661 74.712 ;
     RECT  66.517 2.256 66.733 16.632 ;
     RECT  66.301 55.824 66.913 55.848 ;
     RECT  66.121 18.096 67.093 20.04 ;
     RECT  66.481 21.36 67.093 45.48 ;
     RECT  66.613 46.512 67.093 53.112 ;
     RECT  66.733 2.256 67.201 16.728 ;
     RECT  67.093 18.096 67.201 20.328 ;
     RECT  67.201 2.256 67.208 20.328 ;
     RECT  67.093 21.36 67.208 53.112 ;
     RECT  66.913 55.728 67.208 55.848 ;
     RECT  66.197 56.88 67.208 58.488 ;
     RECT  66.265 59.52 67.208 63.384 ;
     RECT  66.661 64.368 67.208 74.712 ;
     RECT  67.208 2.148 67.312 75.612 ;
     RECT  67.312 2.256 67.504 75.342 ;
     RECT  67.504 11.28 67.565 13.08 ;
     RECT  67.504 52.224 67.637 54.744 ;
     RECT  67.504 61.152 67.637 66.504 ;
     RECT  67.637 61.2 67.709 66.504 ;
     RECT  67.709 61.68 67.853 66.504 ;
     RECT  67.877 77.616 67.96 77.64 ;
     RECT  67.525 76.368 67.993 76.392 ;
     RECT  67.96 77.568 67.993 77.64 ;
     RECT  67.504 30.24 68.033 42.744 ;
     RECT  67.504 67.536 68.033 74.712 ;
     RECT  67.504 2.256 68.213 10.248 ;
     RECT  67.504 15.216 68.213 29.064 ;
     RECT  68.213 2.592 68.249 10.248 ;
     RECT  67.504 55.728 68.357 60.024 ;
     RECT  67.993 76.368 68.38 77.64 ;
     RECT  68.213 15.216 68.429 24.504 ;
     RECT  68.033 37.536 68.429 42.744 ;
     RECT  67.853 61.68 68.429 66.264 ;
     RECT  68.213 25.68 68.465 29.064 ;
     RECT  68.249 2.64 68.497 10.248 ;
     RECT  67.565 11.28 68.497 12.6 ;
     RECT  68.38 76.848 68.501 77.64 ;
     RECT  68.497 2.64 68.569 12.6 ;
     RECT  67.637 52.272 68.605 54.744 ;
     RECT  68.357 55.728 68.605 59.736 ;
     RECT  67.504 45.696 68.713 50.952 ;
     RECT  68.605 52.272 68.713 59.736 ;
     RECT  68.429 15.216 68.749 22.68 ;
     RECT  68.429 38.64 68.749 42.744 ;
     RECT  67.504 43.872 68.749 44.424 ;
     RECT  68.749 38.64 68.78 44.424 ;
     RECT  68.713 45.696 68.78 59.736 ;
     RECT  68.569 2.64 68.821 13.08 ;
     RECT  68.429 61.68 68.893 66.12 ;
     RECT  68.821 2.64 68.933 13.128 ;
     RECT  68.561 75.792 68.965 75.816 ;
     RECT  68.965 75.744 68.969 75.816 ;
     RECT  68.749 14.784 69.001 22.68 ;
     RECT  68.033 67.536 69.073 74.136 ;
     RECT  69.073 67.536 69.145 74.712 ;
     RECT  68.969 75.744 69.145 75.768 ;
     RECT  68.893 61.584 69.205 66.12 ;
     RECT  69.145 67.536 69.229 75.768 ;
     RECT  68.429 24 69.253 24.504 ;
     RECT  68.501 76.848 69.397 77.496 ;
     RECT  69.001 14.256 69.401 22.68 ;
     RECT  69.229 67.536 69.401 74.712 ;
     RECT  68.465 26.208 69.433 29.064 ;
     RECT  68.033 30.24 69.433 36.504 ;
     RECT  68.78 38.64 69.436 59.736 ;
     RECT  69.397 76.8 69.484 77.496 ;
     RECT  69.436 38.64 69.509 55.8 ;
     RECT  69.484 76.896 69.517 77.496 ;
     RECT  69.433 26.208 69.587 36.504 ;
     RECT  69.587 26.208 69.617 29.064 ;
     RECT  69.436 57.12 69.617 59.736 ;
     RECT  69.517 76.944 69.637 77.496 ;
     RECT  69.205 61.296 69.649 66.12 ;
     RECT  69.509 38.64 69.725 45 ;
     RECT  69.509 46.176 69.833 55.8 ;
     RECT  69.401 15.216 69.865 22.68 ;
     RECT  69.253 24 69.901 25.128 ;
     RECT  69.637 76.944 69.925 77.544 ;
     RECT  68.933 2.64 69.937 12.504 ;
     RECT  69.587 30.192 70.049 36.504 ;
     RECT  69.925 76.944 70.049 77.64 ;
     RECT  70.001 75.792 70.085 75.816 ;
     RECT  69.937 2.64 70.117 12.696 ;
     RECT  70.117 2.256 70.163 12.696 ;
     RECT  70.049 76.944 70.163 77.592 ;
     RECT  69.865 15.216 70.193 22.824 ;
     RECT  69.725 38.64 70.193 44.472 ;
     RECT  70.049 34.752 70.225 36.504 ;
     RECT  69.649 61.296 70.225 66.168 ;
     RECT  70.163 77.424 70.259 77.592 ;
     RECT  69.937 14.064 70.297 14.088 ;
     RECT  70.193 15.216 70.307 20.136 ;
     RECT  70.297 13.968 70.369 14.088 ;
     RECT  70.307 15.216 70.369 18.696 ;
     RECT  68.429 37.536 70.369 37.56 ;
     RECT  70.225 60.96 70.369 66.168 ;
     RECT  69.401 67.776 70.369 74.712 ;
     RECT  70.163 3.36 70.441 12.696 ;
     RECT  70.369 13.968 70.441 18.696 ;
     RECT  70.369 37.536 70.451 38.328 ;
     RECT  70.193 21.312 70.453 22.824 ;
     RECT  69.901 23.904 70.453 25.128 ;
     RECT  70.453 21.312 70.481 25.128 ;
     RECT  70.451 38.208 70.481 38.328 ;
     RECT  70.259 77.424 70.517 77.544 ;
     RECT  70.481 21.312 70.525 24.552 ;
     RECT  69.833 46.176 70.549 50.664 ;
     RECT  70.441 3.36 70.553 18.696 ;
     RECT  70.517 77.424 70.553 77.448 ;
     RECT  70.049 30.192 70.657 33.768 ;
     RECT  69.617 57.12 70.657 59.592 ;
     RECT  70.369 60.96 70.657 74.712 ;
     RECT  70.193 39.312 70.661 44.472 ;
     RECT  70.225 34.752 70.729 36.552 ;
     RECT  70.307 19.872 70.733 20.04 ;
     RECT  70.481 38.304 70.805 38.328 ;
     RECT  70.549 45.936 70.913 50.664 ;
     RECT  70.163 2.256 70.949 2.28 ;
     RECT  70.657 57.12 71.02 74.712 ;
     RECT  70.657 30.144 71.021 33.768 ;
     RECT  69.833 51.84 71.053 55.8 ;
     RECT  71.02 57.072 71.053 74.712 ;
     RECT  70.913 46.368 71.197 50.664 ;
     RECT  70.729 34.752 71.237 37.032 ;
     RECT  70.661 39.312 71.237 41.16 ;
     RECT  71.053 51.84 71.273 74.712 ;
     RECT  71.237 39.312 71.341 40.92 ;
     RECT  71.273 51.84 71.345 74.424 ;
     RECT  70.553 3.408 71.377 18.696 ;
     RECT  70.733 19.872 71.377 19.896 ;
     RECT  71.377 3.408 71.381 19.896 ;
     RECT  71.345 51.84 71.381 60.504 ;
     RECT  71.381 51.84 71.417 60.456 ;
     RECT  70.661 42.192 71.485 44.472 ;
     RECT  71.417 56.976 71.489 60.456 ;
     RECT  71.381 3.408 71.593 11.544 ;
     RECT  71.381 12.528 71.597 19.896 ;
     RECT  70.525 21.312 71.773 24.456 ;
     RECT  71.701 25.728 71.773 25.752 ;
     RECT  69.617 26.736 71.797 29.064 ;
     RECT  71.021 30.144 71.797 33.624 ;
     RECT  71.237 35.712 71.917 37.032 ;
     RECT  71.597 12.672 71.953 19.896 ;
     RECT  71.485 42.192 71.953 45 ;
     RECT  71.953 42.192 71.989 45.048 ;
     RECT  71.197 46.368 71.989 50.76 ;
     RECT  71.917 35.712 72.025 37.608 ;
     RECT  71.341 38.784 72.025 40.92 ;
     RECT  71.593 3.36 72.241 11.544 ;
     RECT  72.025 35.712 72.241 40.92 ;
     RECT  72.241 35.712 72.313 41.064 ;
     RECT  71.989 42.192 72.313 50.76 ;
     RECT  72.313 35.712 72.325 50.76 ;
     RECT  71.417 51.84 72.325 55.56 ;
     RECT  71.509 34.704 72.349 34.728 ;
     RECT  72.325 35.712 72.349 55.56 ;
     RECT  71.953 12.672 72.373 20.328 ;
     RECT  71.773 21.312 72.373 25.752 ;
     RECT  72.349 34.704 72.469 55.56 ;
     RECT  71.489 56.976 72.469 60.408 ;
     RECT  72.469 34.704 72.493 60.408 ;
     RECT  71.345 61.584 72.601 74.424 ;
     RECT  72.241 2.592 72.608 11.544 ;
     RECT  72.373 12.672 72.608 25.752 ;
     RECT  71.797 26.736 72.608 33.624 ;
     RECT  72.493 34.656 72.608 60.408 ;
     RECT  72.601 61.392 72.608 74.424 ;
     RECT  72.608 2.148 72.712 75.612 ;
     RECT  72.712 2.304 72.904 75.342 ;
     RECT  72.904 34.656 73.001 54.696 ;
     RECT  72.904 2.304 73.043 13.704 ;
     RECT  72.904 14.736 73.043 23.352 ;
     RECT  73.043 14.736 73.084 14.808 ;
     RECT  73.043 2.304 73.181 13.416 ;
     RECT  73.181 6.384 73.325 13.416 ;
     RECT  73.001 34.704 73.361 54.696 ;
     RECT  73.361 34.704 73.505 48.984 ;
     RECT  72.904 56.064 73.577 59.544 ;
     RECT  72.904 26.304 73.613 33.144 ;
     RECT  73.505 45.792 73.613 48.984 ;
     RECT  72.904 63.024 73.757 75.288 ;
     RECT  73.613 26.304 73.763 33.096 ;
     RECT  73.613 48.672 73.829 48.984 ;
     RECT  72.904 24.432 73.897 25.08 ;
     RECT  72.904 61.392 73.897 61.848 ;
     RECT  73.084 14.784 73.937 14.808 ;
     RECT  73.897 24.432 74.005 25.176 ;
     RECT  73.763 26.304 74.005 26.76 ;
     RECT  73.325 9.504 74.009 13.416 ;
     RECT  73.361 50.112 74.045 54.696 ;
     RECT  73.897 60.528 74.077 61.848 ;
     RECT  73.757 63.024 74.081 71.736 ;
     RECT  73.757 72.816 74.099 75.288 ;
     RECT  73.043 16.08 74.113 23.352 ;
     RECT  74.113 15.456 74.149 23.352 ;
     RECT  74.005 24.432 74.149 26.76 ;
     RECT  74.009 9.504 74.189 11.928 ;
     RECT  74.081 64.32 74.189 71.736 ;
     RECT  74.077 60.528 74.257 61.944 ;
     RECT  74.081 63.024 74.257 63.096 ;
     RECT  74.149 15.456 74.297 26.76 ;
     RECT  74.045 50.112 74.329 52.296 ;
     RECT  73.577 56.064 74.329 59.304 ;
     RECT  74.297 15.456 74.333 19.992 ;
     RECT  74.333 15.84 74.339 19.992 ;
     RECT  73.181 2.304 74.396 5.256 ;
     RECT  73.325 6.384 74.396 8.52 ;
     RECT  74.045 53.568 74.437 54.696 ;
     RECT  74.329 55.824 74.437 59.304 ;
     RECT  74.329 49.824 74.441 52.296 ;
     RECT  74.396 2.304 74.585 8.52 ;
     RECT  73.613 45.792 74.617 47.304 ;
     RECT  73.829 48.672 74.617 48.792 ;
     RECT  74.099 72.816 74.657 74.904 ;
     RECT  74.189 9.792 74.693 11.928 ;
     RECT  74.437 53.568 74.693 59.304 ;
     RECT  74.339 15.84 74.723 19.896 ;
     RECT  73.505 34.704 74.725 44.328 ;
     RECT  74.617 45.792 74.725 48.792 ;
     RECT  74.189 64.368 74.725 71.736 ;
     RECT  74.657 72.816 74.725 74.472 ;
     RECT  74.585 2.832 74.837 8.52 ;
     RECT  74.297 21.12 74.905 26.76 ;
     RECT  74.723 16.608 74.909 19.896 ;
     RECT  74.909 16.608 74.945 18.84 ;
     RECT  74.257 60.528 74.981 63.096 ;
     RECT  74.905 21.12 75.013 26.904 ;
     RECT  73.763 27.888 75.013 33.096 ;
     RECT  74.441 52.272 75.013 52.296 ;
     RECT  74.693 53.568 75.013 58.68 ;
     RECT  74.009 13.392 75.017 13.416 ;
     RECT  74.981 61.824 75.085 63.096 ;
     RECT  74.725 34.704 75.121 48.792 ;
     RECT  75.013 21.12 75.155 33.096 ;
     RECT  74.677 14.448 75.161 14.472 ;
     RECT  75.121 34.128 75.161 48.792 ;
     RECT  75.161 34.128 75.193 37.032 ;
     RECT  75.161 38.16 75.205 48.792 ;
     RECT  74.441 49.824 75.205 51.288 ;
     RECT  74.981 60.528 75.253 60.552 ;
     RECT  75.155 26.208 75.265 33.096 ;
     RECT  75.193 34.08 75.265 37.032 ;
     RECT  75.155 21.12 75.269 25.176 ;
     RECT  74.837 3.072 75.301 8.52 ;
     RECT  74.693 9.792 75.301 11.832 ;
     RECT  75.269 21.936 75.341 25.176 ;
     RECT  75.265 26.208 75.485 37.032 ;
     RECT  75.013 52.272 75.485 58.68 ;
     RECT  75.485 26.208 75.593 36.84 ;
     RECT  75.593 26.208 75.665 32.808 ;
     RECT  75.301 3.072 75.697 11.832 ;
     RECT  75.665 26.208 75.765 32.472 ;
     RECT  75.697 3.072 75.779 12.744 ;
     RECT  75.779 5.232 75.809 12.744 ;
     RECT  75.765 29.424 75.809 32.472 ;
     RECT  75.253 59.808 75.809 60.552 ;
     RECT  75.809 59.808 75.82 59.832 ;
     RECT  75.765 26.208 75.827 28.44 ;
     RECT  75.809 7.344 75.875 12.744 ;
     RECT  75.205 38.16 75.875 51.288 ;
     RECT  75.485 55.824 75.875 58.68 ;
     RECT  74.725 64.368 75.881 74.472 ;
     RECT  74.945 18.24 75.913 18.84 ;
     RECT  74.909 19.872 75.913 19.896 ;
     RECT  75.085 61.824 75.913 63.24 ;
     RECT  75.881 64.368 75.913 64.968 ;
     RECT  75.593 33.84 75.917 36.84 ;
     RECT  74.945 16.608 75.949 17.112 ;
     RECT  75.913 18.24 75.949 19.896 ;
     RECT  75.949 18.144 75.98 19.896 ;
     RECT  75.949 16.56 76.021 17.112 ;
     RECT  75.98 18.144 76.021 19.992 ;
     RECT  75.875 44.208 76.021 51.288 ;
     RECT  75.485 52.272 76.021 54.696 ;
     RECT  75.881 66.096 76.025 74.472 ;
     RECT  76.021 16.56 76.067 19.992 ;
     RECT  75.341 21.936 76.205 24.408 ;
     RECT  75.913 61.824 76.273 64.968 ;
     RECT  76.021 13.296 76.345 13.416 ;
     RECT  75.875 7.344 76.355 12.024 ;
     RECT  76.067 16.56 76.403 19.368 ;
     RECT  76.025 66.096 76.421 73.368 ;
     RECT  76.345 13.296 76.489 13.704 ;
     RECT  76.273 14.688 76.489 14.856 ;
     RECT  76.273 61.008 76.529 64.968 ;
     RECT  75.827 26.208 76.565 28.2 ;
     RECT  76.529 61.008 76.565 64.392 ;
     RECT  76.517 77.616 76.6 77.64 ;
     RECT  76.421 66.096 76.601 71.832 ;
     RECT  75.875 55.872 76.637 58.68 ;
     RECT  76.412 76.368 76.7 76.392 ;
     RECT  76.6 77.568 76.7 77.64 ;
     RECT  76.565 28.032 76.813 28.2 ;
     RECT  75.809 29.424 76.813 32.328 ;
     RECT  76.403 18.768 76.817 19.368 ;
     RECT  76.7 76.368 76.837 77.64 ;
     RECT  76.355 7.728 76.849 12.024 ;
     RECT  76.489 13.296 76.849 14.856 ;
     RECT  76.601 70.704 76.889 71.832 ;
     RECT  75.809 5.232 76.921 6.264 ;
     RECT  75.917 36.816 76.921 36.84 ;
     RECT  75.875 38.16 76.921 43.128 ;
     RECT  76.849 7.728 76.925 14.856 ;
     RECT  76.021 44.208 76.925 54.696 ;
     RECT  76.837 75.792 76.925 77.64 ;
     RECT  76.921 36.816 76.957 43.128 ;
     RECT  76.925 45.168 76.957 54.696 ;
     RECT  76.637 55.872 76.957 58.152 ;
     RECT  76.421 72.912 76.993 73.368 ;
     RECT  76.025 74.448 76.993 74.472 ;
     RECT  76.993 72.912 77.125 74.472 ;
     RECT  76.601 66.096 77.132 69.624 ;
     RECT  76.849 59.184 77.389 59.208 ;
     RECT  76.921 5.232 77.413 6.504 ;
     RECT  76.925 7.728 77.413 13.32 ;
     RECT  76.813 28.032 77.461 32.328 ;
     RECT  76.403 16.56 77.497 17.4 ;
     RECT  76.957 36.816 77.497 43.368 ;
     RECT  77.389 59.184 77.533 59.496 ;
     RECT  76.565 61.008 77.533 64.2 ;
     RECT  77.461 28.032 77.569 32.856 ;
     RECT  75.917 33.84 77.569 35.544 ;
     RECT  75.779 3.072 77.605 4.248 ;
     RECT  77.413 5.232 77.605 13.32 ;
     RECT  77.569 28.032 77.605 35.544 ;
     RECT  77.497 36.624 77.605 43.368 ;
     RECT  77.497 16.56 77.749 17.736 ;
     RECT  77.749 15.984 77.893 17.736 ;
     RECT  76.565 26.208 77.893 26.76 ;
     RECT  76.205 22.032 77.965 24.408 ;
     RECT  77.605 3.072 78.008 13.32 ;
     RECT  76.925 14.832 78.008 14.856 ;
     RECT  77.893 15.84 78.008 17.736 ;
     RECT  76.817 18.96 78.008 19.368 ;
     RECT  77.893 20.352 78.008 20.376 ;
     RECT  77.965 22.032 78.008 24.456 ;
     RECT  77.893 25.536 78.008 26.76 ;
     RECT  77.605 28.032 78.008 43.368 ;
     RECT  76.957 45.168 78.008 58.152 ;
     RECT  77.533 59.184 78.008 64.2 ;
     RECT  77.132 65.376 78.008 69.624 ;
     RECT  76.889 70.752 78.008 71.832 ;
     RECT  77.125 72.912 78.008 74.664 ;
     RECT  76.925 75.84 78.008 77.64 ;
     RECT  78.008 2.148 78.112 77.64 ;
     RECT  78.112 2.418 78.304 77.64 ;
     RECT  78.304 33.936 78.437 42.744 ;
     RECT  78.304 26.016 78.581 32.856 ;
     RECT  78.581 26.592 78.614 32.856 ;
     RECT  78.304 6.816 78.617 13.08 ;
     RECT  78.614 26.592 78.659 32.808 ;
     RECT  78.304 43.776 78.689 49.896 ;
     RECT  78.304 14.64 78.725 22.056 ;
     RECT  78.304 23.088 78.725 24.648 ;
     RECT  78.659 30.096 78.725 32.808 ;
     RECT  78.304 70.56 78.761 77.64 ;
     RECT  78.304 2.64 78.797 3.432 ;
     RECT  78.617 6.816 78.797 8.52 ;
     RECT  78.617 9.552 78.797 13.08 ;
     RECT  78.689 43.776 78.803 49.608 ;
     RECT  78.761 70.56 78.833 74.664 ;
     RECT  78.659 26.592 78.869 29.064 ;
     RECT  78.437 34.08 78.905 42.744 ;
     RECT  78.905 34.08 78.941 42.024 ;
     RECT  78.761 75.648 79.085 77.64 ;
     RECT  78.304 51.216 79.091 54.648 ;
     RECT  78.725 14.64 79.121 21.528 ;
     RECT  78.797 9.552 79.187 12.6 ;
     RECT  79.091 51.408 79.193 54.648 ;
     RECT  79.085 75.648 79.201 75.816 ;
     RECT  78.941 37.872 79.229 42.024 ;
     RECT  78.304 59.184 79.235 63.144 ;
     RECT  78.304 64.176 79.283 69.528 ;
     RECT  79.229 37.872 79.301 41.784 ;
     RECT  78.803 43.776 79.301 48.744 ;
     RECT  78.941 34.08 79.337 36.888 ;
     RECT  79.235 60.528 79.369 63.144 ;
     RECT  79.283 65.136 79.405 69.528 ;
     RECT  78.725 30.096 79.409 31.752 ;
     RECT  78.304 55.872 79.409 58.152 ;
     RECT  79.409 30.096 79.445 31.416 ;
     RECT  79.337 34.608 79.481 36.888 ;
     RECT  79.301 37.872 79.517 41.64 ;
     RECT  78.833 70.704 79.517 74.664 ;
     RECT  79.193 52.272 79.585 54.648 ;
     RECT  79.121 14.64 79.589 21.192 ;
     RECT  78.725 23.088 79.593 24.12 ;
     RECT  79.517 70.704 79.661 74.424 ;
     RECT  79.589 18.768 79.667 21.192 ;
     RECT  79.085 76.896 79.697 77.64 ;
     RECT  79.589 14.64 79.729 17.64 ;
     RECT  79.585 52.272 79.729 54.888 ;
     RECT  79.697 76.896 79.733 77.592 ;
     RECT  78.797 6.816 79.765 7.896 ;
     RECT  78.304 4.656 79.801 4.68 ;
     RECT  79.301 43.776 79.801 47.736 ;
     RECT  79.201 75.792 79.805 75.816 ;
     RECT  79.729 14.208 79.873 17.64 ;
     RECT  78.725 32.784 79.877 32.808 ;
     RECT  79.517 39.984 79.877 41.64 ;
     RECT  79.765 6.816 79.916 7.992 ;
     RECT  79.873 14.112 79.916 17.64 ;
     RECT  79.916 6.816 79.945 8.328 ;
     RECT  79.481 34.608 79.949 35.544 ;
     RECT  79.945 6.144 80.003 8.328 ;
     RECT  79.369 60.528 80.057 63.768 ;
     RECT  80.057 61.776 80.093 63.768 ;
     RECT  79.409 56.4 80.125 58.152 ;
     RECT  79.235 59.184 80.125 59.208 ;
     RECT  78.797 2.64 80.129 2.664 ;
     RECT  79.801 43.2 80.129 47.736 ;
     RECT  80.057 60.528 80.129 60.552 ;
     RECT  79.187 9.792 80.161 12.6 ;
     RECT  80.125 56.4 80.197 59.208 ;
     RECT  79.593 22.752 80.233 24.12 ;
     RECT  78.869 26.64 80.233 29.064 ;
     RECT  79.445 30.096 80.233 31.128 ;
     RECT  80.093 61.872 80.237 63.768 ;
     RECT  79.405 65.136 80.305 69.672 ;
     RECT  79.873 50.208 80.341 50.232 ;
     RECT  80.237 61.968 80.377 63.768 ;
     RECT  80.305 64.848 80.377 69.672 ;
     RECT  80.377 61.968 80.485 69.672 ;
     RECT  79.661 70.704 80.485 74.088 ;
     RECT  79.301 48.72 80.489 48.744 ;
     RECT  79.733 77.568 80.489 77.592 ;
     RECT  80.341 50.208 80.492 51.144 ;
     RECT  80.197 56.4 80.521 59.448 ;
     RECT  79.877 39.984 80.525 40.488 ;
     RECT  79.877 41.616 80.525 41.64 ;
     RECT  80.485 61.968 80.525 74.088 ;
     RECT  79.916 13.68 80.561 17.64 ;
     RECT  80.525 61.968 80.597 73.8 ;
     RECT  80.233 21.792 80.633 24.12 ;
     RECT  80.492 49.872 80.657 51.144 ;
     RECT  80.129 43.2 80.665 44.952 ;
     RECT  80.597 61.968 80.669 65.16 ;
     RECT  80.003 6.144 80.741 7.656 ;
     RECT  80.657 48.96 80.741 51.144 ;
     RECT  79.801 4.368 80.777 4.68 ;
     RECT  79.481 36.624 80.845 36.888 ;
     RECT  79.517 37.872 80.845 38.76 ;
     RECT  80.129 46.176 80.849 47.736 ;
     RECT  79.667 18.768 80.869 20.424 ;
     RECT  80.633 22.656 80.881 24.12 ;
     RECT  79.405 25.104 80.881 25.128 ;
     RECT  80.269 33.024 80.881 33.048 ;
     RECT  79.949 34.608 80.881 35.352 ;
     RECT  80.881 22.656 80.885 25.128 ;
     RECT  80.777 4.416 80.917 4.68 ;
     RECT  80.665 42.864 80.921 44.952 ;
     RECT  80.521 56.4 80.957 60.408 ;
     RECT  80.669 61.968 80.963 65.016 ;
     RECT  80.233 26.64 80.993 31.128 ;
     RECT  80.917 4.416 81.025 5.112 ;
     RECT  80.741 6.144 81.025 7.176 ;
     RECT  80.921 42.864 81.025 42.888 ;
     RECT  80.993 27.888 81.029 31.128 ;
     RECT  80.885 24.96 81.061 25.128 ;
     RECT  80.161 8.976 81.065 12.6 ;
     RECT  80.597 66.288 81.065 73.8 ;
     RECT  80.881 34.224 81.097 35.352 ;
     RECT  80.845 36.624 81.097 38.76 ;
     RECT  81.025 4.416 81.101 7.176 ;
     RECT  80.963 61.968 81.101 64.872 ;
     RECT  80.741 49.2 81.133 51.144 ;
     RECT  79.729 52.272 81.133 55.224 ;
     RECT  80.885 22.656 81.173 23.928 ;
     RECT  81.097 34.224 81.173 38.76 ;
     RECT  80.525 39.984 81.205 40.2 ;
     RECT  81.065 8.976 81.245 12.168 ;
     RECT  81.029 29.472 81.245 31.128 ;
     RECT  81.133 49.2 81.245 55.224 ;
     RECT  81.173 34.224 81.281 38.04 ;
     RECT  81.245 49.2 81.281 55.128 ;
     RECT  81.101 61.968 81.281 63.288 ;
     RECT  81.101 4.416 81.317 4.44 ;
     RECT  81.245 8.976 81.317 9.96 ;
     RECT  80.561 14.4 81.317 17.592 ;
     RECT  81.281 54.624 81.353 55.128 ;
     RECT  81.281 34.224 81.389 37.032 ;
     RECT  81.245 11.376 81.395 12.168 ;
     RECT  80.957 56.448 81.443 60.408 ;
     RECT  81.395 11.376 81.461 11.976 ;
     RECT  81.349 13.248 81.461 13.272 ;
     RECT  81.317 15.024 81.461 17.592 ;
     RECT  81.205 39.744 81.461 40.2 ;
     RECT  81.101 5.664 81.497 7.176 ;
     RECT  81.443 56.448 81.497 58.152 ;
     RECT  81.443 59.136 81.497 60.408 ;
     RECT  81.497 59.232 81.532 60.408 ;
     RECT  80.921 43.872 81.565 44.952 ;
     RECT  80.849 46.176 81.565 46.824 ;
     RECT  81.461 39.888 81.569 40.2 ;
     RECT  81.065 66.72 81.569 73.8 ;
     RECT  80.993 26.64 81.637 26.712 ;
     RECT  81.025 42.48 81.637 42.888 ;
     RECT  81.497 5.664 81.641 5.688 ;
     RECT  81.637 42.192 81.641 42.888 ;
     RECT  81.532 59.856 81.673 60.408 ;
     RECT  81.461 16.656 81.709 17.592 ;
     RECT  80.869 18.768 81.709 21.672 ;
     RECT  81.673 59.856 81.713 60.456 ;
     RECT  81.281 61.968 81.749 62.76 ;
     RECT  81.245 31.104 81.817 31.128 ;
     RECT  80.881 32.496 81.817 33.048 ;
     RECT  81.353 54.72 81.821 55.128 ;
     RECT  81.497 56.592 81.821 58.152 ;
     RECT  81.281 49.2 81.857 53.544 ;
     RECT  81.565 43.872 81.889 46.824 ;
     RECT  81.389 35.808 81.893 37.032 ;
     RECT  81.461 15.024 81.929 15.048 ;
     RECT  81.713 59.904 81.929 60.456 ;
     RECT  81.889 43.872 81.961 47.736 ;
     RECT  81.857 49.2 81.961 52.824 ;
     RECT  81.389 34.224 81.965 34.632 ;
     RECT  81.961 43.872 81.965 52.824 ;
     RECT  81.497 6.816 81.973 7.176 ;
     RECT  81.461 11.424 82.019 11.976 ;
     RECT  81.932 13.296 82.019 13.608 ;
     RECT  81.709 16.656 82.019 21.672 ;
     RECT  81.973 6.816 82.029 7.272 ;
     RECT  81.569 66.72 82.073 72.024 ;
     RECT  82.029 7.152 82.109 7.272 ;
     RECT  82.019 16.656 82.109 17.16 ;
     RECT  81.965 43.872 82.109 51.144 ;
     RECT  81.281 38.016 82.141 38.04 ;
     RECT  81.965 52.704 82.145 52.824 ;
     RECT  82.073 66.72 82.177 70.44 ;
     RECT  82.109 43.872 82.181 50.184 ;
     RECT  81.101 64.704 82.213 64.872 ;
     RECT  81.317 8.976 82.217 9.864 ;
     RECT  82.181 44.928 82.217 50.184 ;
     RECT  81.173 22.656 82.249 23.304 ;
     RECT  82.019 13.296 82.253 13.32 ;
     RECT  82.109 16.704 82.253 17.16 ;
     RECT  81.893 35.808 82.253 36.024 ;
     RECT  82.253 16.8 82.289 17.16 ;
     RECT  82.217 44.928 82.325 47.832 ;
     RECT  81.029 27.888 82.357 28.488 ;
     RECT  81.245 29.472 82.357 29.496 ;
     RECT  81.817 31.104 82.393 33.048 ;
     RECT  82.181 43.872 82.393 43.896 ;
     RECT  82.019 18.48 82.433 21.672 ;
     RECT  81.821 56.592 82.433 57.096 ;
     RECT  81.061 24.96 82.465 25.32 ;
     RECT  81.637 26.4 82.465 26.712 ;
     RECT  82.213 64.368 82.465 64.872 ;
     RECT  82.465 24.96 82.609 26.712 ;
     RECT  81.569 73.536 82.609 73.8 ;
     RECT  82.609 24.528 82.645 26.712 ;
     RECT  82.357 27.888 82.645 29.496 ;
     RECT  82.073 71.52 82.645 72.024 ;
     RECT  82.609 73.488 82.645 73.8 ;
     RECT  82.393 30.768 82.741 33.048 ;
     RECT  82.105 34.176 82.741 34.2 ;
     RECT  81.749 62.592 82.789 62.76 ;
     RECT  82.465 63.792 82.789 64.872 ;
     RECT  81.929 60.432 82.925 60.456 ;
     RECT  82.925 59.808 82.933 60.456 ;
     RECT  82.109 7.248 83.408 7.272 ;
     RECT  82.217 8.976 83.408 9.672 ;
     RECT  82.019 11.568 83.408 11.976 ;
     RECT  82.289 16.848 83.408 17.16 ;
     RECT  82.433 18.768 83.408 21.672 ;
     RECT  82.249 22.656 83.408 23.544 ;
     RECT  82.645 24.528 83.408 29.496 ;
     RECT  82.741 30.768 83.408 34.2 ;
     RECT  82.253 35.808 83.408 35.832 ;
     RECT  81.893 37.008 83.408 37.032 ;
     RECT  82.141 38.016 83.408 38.472 ;
     RECT  81.569 39.888 83.408 39.912 ;
     RECT  81.641 42.192 83.408 42.6 ;
     RECT  82.393 43.824 83.408 43.896 ;
     RECT  82.325 45.552 83.408 47.832 ;
     RECT  82.217 49.2 83.408 50.184 ;
     RECT  82.145 52.704 83.408 52.728 ;
     RECT  81.821 54.72 83.408 54.744 ;
     RECT  82.433 56.592 83.408 56.904 ;
     RECT  81.821 58.08 83.408 58.152 ;
     RECT  82.933 59.808 83.408 61.08 ;
     RECT  82.789 62.592 83.408 64.872 ;
     RECT  82.177 66.096 83.408 70.44 ;
     RECT  82.645 71.52 83.408 74.04 ;
     RECT  83.408 2.148 83.512 75.612 ;
     RECT  83.512 2.418 83.704 75.342 ;
    LAYER M5 ;
     RECT  51.408 0.016 57.48 0.085 ;
     RECT  6.864 0.016 9.864 0.131 ;
     RECT  42.192 0.016 45.192 0.131 ;
     RECT  51.312 0.085 57.48 0.131 ;
     RECT  61.392 0.016 64.392 0.131 ;
     RECT  51.312 0.131 57.384 0.227 ;
     RECT  61.488 0.131 64.392 0.227 ;
     RECT  48.336 0.016 48.84 0.563 ;
     RECT  6.96 0.131 9.864 0.611 ;
     RECT  29.136 0.016 32.136 0.611 ;
     RECT  42.288 0.131 45.192 0.611 ;
     RECT  61.488 0.227 64.2 0.611 ;
     RECT  42.384 0.611 45.192 0.659 ;
     RECT  61.584 0.611 64.2 0.659 ;
     RECT  29.232 0.611 32.136 0.707 ;
     RECT  51.456 0.227 57.384 1.717 ;
     RECT  42.672 0.659 45.192 1.763 ;
     RECT  48.432 0.563 48.84 1.763 ;
     RECT  61.68 0.659 64.2 1.763 ;
     RECT  7.056 0.611 9.864 1.811 ;
     RECT  29.28 0.707 32.136 1.859 ;
     RECT  61.68 1.763 63.816 1.907 ;
     RECT  42.864 1.763 45.192 2.137 ;
     RECT  51.456 1.717 57.48 2.137 ;
     RECT  2.4 2.137 2.52 2.151 ;
     RECT  13.2 2.137 13.32 2.151 ;
     RECT  18.6 2.137 18.72 2.151 ;
     RECT  24 2.137 24.12 2.151 ;
     RECT  34.8 2.137 34.92 2.151 ;
     RECT  40.2 2.137 40.32 2.151 ;
     RECT  42.864 2.137 45.72 2.151 ;
     RECT  67.2 2.137 67.32 2.151 ;
     RECT  72.6 2.137 72.72 2.151 ;
     RECT  78 2.137 78.12 2.151 ;
     RECT  83.4 2.137 83.52 2.151 ;
     RECT  13.2 2.151 13.512 2.197 ;
     RECT  51 2.137 57.48 2.245 ;
     RECT  67.2 2.151 67.512 2.245 ;
     RECT  7.056 1.811 9.672 2.291 ;
     RECT  72.6 2.151 72.912 2.293 ;
     RECT  29.28 1.859 31.752 2.821 ;
     RECT  66.048 2.245 66.072 2.821 ;
     RECT  51 2.245 58.056 2.915 ;
     RECT  59.184 2.245 59.208 3.011 ;
     RECT  67.2 2.245 67.608 3.059 ;
     RECT  18.6 2.151 18.912 3.061 ;
     RECT  29.232 2.821 31.752 3.253 ;
     RECT  40.2 2.151 40.512 3.301 ;
     RECT  64.944 3.301 64.968 3.349 ;
     RECT  66.048 2.821 66.12 3.349 ;
     RECT  42.864 2.151 45.912 3.397 ;
     RECT  51 2.915 57.48 3.397 ;
     RECT  3.696 2.245 3.72 3.443 ;
     RECT  61.68 1.907 63.432 3.443 ;
     RECT  50.736 3.397 57.48 3.541 ;
     RECT  64.848 3.349 66.12 3.587 ;
     RECT  50.544 3.541 57.48 3.683 ;
     RECT  2.4 2.151 2.712 3.685 ;
     RECT  72.6 2.293 73.56 3.685 ;
     RECT  67.2 3.059 67.512 3.829 ;
     RECT  29.136 3.253 31.752 3.925 ;
     RECT  53.904 3.683 57.48 3.925 ;
     RECT  58.56 3.877 59.016 3.925 ;
     RECT  72.6 3.685 73.848 3.925 ;
     RECT  29.136 3.925 32.28 4.019 ;
     RECT  50.544 3.683 52.584 4.019 ;
     RECT  5.76 2.821 5.784 4.069 ;
     RECT  5.76 4.069 6.168 4.115 ;
     RECT  34.8 2.151 35.112 4.117 ;
     RECT  29.136 4.019 30.6 4.213 ;
     RECT  34.8 4.117 35.304 4.307 ;
     RECT  69.024 4.117 69.048 4.307 ;
     RECT  13.2 2.197 14.136 4.405 ;
     RECT  18.192 3.061 18.912 4.451 ;
     RECT  61.68 3.443 62.952 4.451 ;
     RECT  50.544 4.019 51.816 4.501 ;
     RECT  78 2.151 78.312 4.501 ;
     RECT  29.088 4.213 30.6 4.595 ;
     RECT  32.256 4.019 32.28 4.595 ;
     RECT  50.16 4.501 51.816 4.595 ;
     RECT  61.8 4.451 62.952 4.595 ;
     RECT  7.632 2.291 8.616 4.691 ;
     RECT  64.848 3.587 65.496 4.789 ;
     RECT  29.088 4.595 30.024 4.837 ;
     RECT  66.672 3.829 67.512 4.837 ;
     RECT  72.48 3.925 73.848 4.837 ;
     RECT  64.848 4.789 65.544 4.885 ;
     RECT  72.432 4.837 73.848 4.981 ;
     RECT  50.16 4.595 51.48 5.029 ;
     RECT  75.264 4.453 75.288 5.029 ;
     RECT  66.672 4.837 67.704 5.077 ;
     RECT  21.168 4.981 21.192 5.123 ;
     RECT  53.904 3.925 59.016 5.125 ;
     RECT  2.4 3.685 2.904 5.171 ;
     RECT  6.144 4.115 6.168 5.171 ;
     RECT  9.648 2.291 9.672 5.171 ;
     RECT  28.608 4.837 30.024 5.171 ;
     RECT  42.432 3.397 45.912 5.171 ;
     RECT  24 2.151 24.312 5.269 ;
     RECT  25.68 2.485 25.704 5.269 ;
     RECT  60.576 5.173 60.6 5.315 ;
     RECT  13.104 4.405 14.136 5.317 ;
     RECT  44.352 5.171 45.912 5.365 ;
     RECT  46.944 2.821 47.736 5.365 ;
     RECT  24 5.269 25.704 5.507 ;
     RECT  13.104 5.317 14.232 5.509 ;
     RECT  71.904 4.981 73.848 5.557 ;
     RECT  13.104 5.509 15 5.651 ;
     RECT  13.104 5.651 14.232 5.653 ;
     RECT  32.976 5.125 33 5.653 ;
     RECT  44.352 5.365 47.736 5.653 ;
     RECT  70.128 2.245 70.152 5.653 ;
     RECT  42.432 5.171 43.176 5.747 ;
     RECT  49.344 5.029 51.48 5.747 ;
     RECT  53.904 5.125 59.352 5.747 ;
     RECT  25.68 5.507 25.704 5.891 ;
     RECT  32.976 5.653 33.048 5.893 ;
     RECT  29.4 5.171 30.024 5.941 ;
     RECT  32.688 5.893 33.048 5.941 ;
     RECT  6.24 5.461 6.264 6.037 ;
     RECT  53.952 5.747 59.352 6.131 ;
     RECT  64.512 4.885 65.544 6.133 ;
     RECT  7.632 4.691 8.112 6.181 ;
     RECT  29.4 5.941 30.168 6.181 ;
     RECT  71.808 5.557 73.848 6.181 ;
     RECT  75.264 5.029 75.768 6.181 ;
     RECT  29.4 6.181 30.456 6.229 ;
     RECT  71.808 6.181 75.768 6.229 ;
     RECT  36.48 4.501 36.504 6.275 ;
     RECT  13.056 5.653 14.232 6.277 ;
     RECT  32.544 5.941 33.192 6.277 ;
     RECT  60.672 5.317 60.696 6.277 ;
     RECT  61.8 4.595 62.808 6.277 ;
     RECT  7.632 6.181 8.52 6.323 ;
     RECT  42.432 5.747 42.456 6.323 ;
     RECT  12.624 6.277 14.232 6.325 ;
     RECT  29.088 6.229 30.888 6.659 ;
     RECT  6.24 6.037 6.504 6.661 ;
     RECT  49.488 5.747 51.48 6.661 ;
     RECT  7.8 6.323 8.52 6.805 ;
     RECT  12.528 6.325 14.232 6.805 ;
     RECT  49.488 6.661 51.576 6.805 ;
     RECT  32.544 6.277 33.528 6.853 ;
     RECT  7.8 6.805 9.24 6.899 ;
     RECT  66.624 5.077 67.704 6.901 ;
     RECT  49.488 6.805 51.912 7.045 ;
     RECT  70.128 5.653 70.248 7.093 ;
     RECT  10.32 6.901 10.344 7.141 ;
     RECT  11.664 6.805 14.232 7.187 ;
     RECT  53.952 6.131 59.016 7.189 ;
     RECT  60.672 6.277 62.808 7.237 ;
     RECT  77.76 4.501 78.312 7.237 ;
     RECT  81.984 6.805 82.008 7.283 ;
     RECT  19.968 2.629 19.992 7.331 ;
     RECT  64.512 6.133 65.64 7.331 ;
     RECT  44.352 5.653 47.928 7.333 ;
     RECT  49.392 7.045 51.912 7.333 ;
     RECT  29.088 6.659 30.456 7.379 ;
     RECT  69.504 7.093 70.248 7.379 ;
     RECT  71.808 6.229 76.344 7.379 ;
     RECT  24 5.507 24.312 7.381 ;
     RECT  31.872 6.853 33.528 7.381 ;
     RECT  34.8 4.307 35.112 7.381 ;
     RECT  40.08 3.301 40.512 7.381 ;
     RECT  53.952 7.189 59.256 7.429 ;
     RECT  11.76 7.187 14.232 7.475 ;
     RECT  44.352 7.333 52.632 7.475 ;
     RECT  31.872 7.381 35.112 7.477 ;
     RECT  29.088 7.379 30.168 7.525 ;
     RECT  21.072 6.613 21.096 7.571 ;
     RECT  9.216 6.899 9.24 7.573 ;
     RECT  10.32 7.141 10.392 7.573 ;
     RECT  64.512 7.331 65.496 7.573 ;
     RECT  17.328 4.501 17.352 7.621 ;
     RECT  53.904 7.429 59.256 7.669 ;
     RECT  60.288 7.237 62.808 7.669 ;
     RECT  77.424 7.237 78.312 7.717 ;
     RECT  16.944 7.621 17.352 7.763 ;
     RECT  28.992 7.525 30.168 7.765 ;
     RECT  9.216 7.573 10.68 7.859 ;
     RECT  77.424 7.717 79.032 7.861 ;
     RECT  74.928 7.379 76.344 7.907 ;
     RECT  48.432 7.475 52.632 7.909 ;
     RECT  53.904 7.669 62.808 7.909 ;
     RECT  24 7.381 24.936 8.005 ;
     RECT  4.608 7.957 4.632 8.053 ;
     RECT  6.24 6.661 6.6 8.101 ;
     RECT  9.216 7.859 10.344 8.147 ;
     RECT  11.76 7.475 13.896 8.149 ;
     RECT  28.464 7.765 30.168 8.195 ;
     RECT  11.664 8.149 13.896 8.293 ;
     RECT  77.424 7.861 79.8 8.293 ;
     RECT  9.216 8.147 10.248 8.339 ;
     RECT  31.824 7.477 35.112 8.389 ;
     RECT  71.808 7.379 73.848 8.435 ;
     RECT  70.224 7.379 70.248 8.437 ;
     RECT  23.28 8.005 24.936 8.483 ;
     RECT  69.696 8.437 70.248 8.483 ;
     RECT  7.8 6.899 8.112 8.485 ;
     RECT  48.432 7.909 62.808 8.485 ;
     RECT  64.08 7.573 65.496 8.485 ;
     RECT  40.032 7.381 40.512 8.531 ;
     RECT  17.328 7.763 17.352 8.533 ;
     RECT  18.6 4.451 18.912 8.533 ;
     RECT  31.44 8.389 35.112 8.533 ;
     RECT  4.32 8.053 4.632 8.675 ;
     RECT  4.56 8.675 4.632 8.677 ;
     RECT  6.096 8.101 6.6 8.677 ;
     RECT  31.344 8.533 35.112 8.723 ;
     RECT  4.56 8.677 6.6 8.915 ;
     RECT  6.096 8.915 6.6 8.917 ;
     RECT  7.8 8.485 8.232 8.917 ;
     RECT  9.504 8.339 10.248 8.963 ;
     RECT  31.344 8.723 33.528 8.963 ;
     RECT  21.024 7.765 21.048 9.061 ;
     RECT  44.352 7.475 47.352 9.061 ;
     RECT  48.432 8.485 65.496 9.061 ;
     RECT  31.344 8.963 33.336 9.107 ;
     RECT  44.352 9.061 65.496 9.107 ;
     RECT  72.288 8.435 73.848 9.107 ;
     RECT  11.424 8.293 13.896 9.109 ;
     RECT  17.328 8.533 18.912 9.109 ;
     RECT  11.424 9.109 14.04 9.155 ;
     RECT  37.152 8.293 37.176 9.155 ;
     RECT  53.952 9.107 65.496 9.155 ;
     RECT  72.384 9.107 73.848 9.155 ;
     RECT  77.424 8.293 79.992 9.155 ;
     RECT  21.024 9.061 21.576 9.157 ;
     RECT  9.504 8.963 9.624 9.203 ;
     RECT  31.344 9.107 32.568 9.251 ;
     RECT  28.464 8.195 30.12 9.253 ;
     RECT  4.56 8.915 4.728 9.299 ;
     RECT  9.504 9.203 9.528 9.299 ;
     RECT  28.464 9.253 30.552 9.299 ;
     RECT  49.344 9.107 52.248 9.299 ;
     RECT  44.352 9.107 48.168 9.347 ;
     RECT  77.76 9.155 79.992 9.349 ;
     RECT  4.608 9.299 4.728 9.443 ;
     RECT  16.464 9.109 18.912 9.493 ;
     RECT  20.208 9.157 21.576 9.493 ;
     RECT  11.472 9.155 14.04 9.541 ;
     RECT  37.056 9.445 37.08 9.541 ;
     RECT  40.08 8.531 40.512 9.589 ;
     RECT  42.384 6.805 42.408 9.637 ;
     RECT  16.464 9.493 21.576 9.683 ;
     RECT  48.144 9.347 48.168 9.731 ;
     RECT  66.624 6.901 68.376 9.731 ;
     RECT  66.624 9.731 67.896 9.733 ;
     RECT  77.76 9.349 80.52 9.827 ;
     RECT  6.096 8.917 8.232 9.925 ;
     RECT  23.28 8.483 24.312 9.925 ;
     RECT  74.928 7.907 75.768 9.925 ;
     RECT  36.432 9.541 37.08 10.019 ;
     RECT  53.952 9.155 65.4 10.019 ;
     RECT  29.04 9.299 30.552 10.067 ;
     RECT  17.328 9.683 21.576 10.115 ;
     RECT  42.384 9.637 42.792 10.165 ;
     RECT  69.696 8.483 69.72 10.213 ;
     RECT  5.616 9.925 9.192 10.259 ;
     RECT  71.328 9.829 71.352 10.261 ;
     RECT  11.472 9.541 14.232 10.307 ;
     RECT  69.504 10.213 69.72 10.307 ;
     RECT  2.4 5.171 2.712 10.309 ;
     RECT  44.352 9.347 47.16 10.453 ;
     RECT  4.608 9.443 4.632 10.549 ;
     RECT  5.616 10.259 8.112 10.549 ;
     RECT  29.04 10.067 30.264 10.595 ;
     RECT  29.136 10.595 30.264 10.835 ;
     RECT  44.352 10.453 47.928 10.837 ;
     RECT  49.344 9.299 51.48 10.837 ;
     RECT  21.552 10.115 21.576 10.883 ;
     RECT  69.504 10.307 69.528 10.883 ;
     RECT  40.08 9.589 41.208 10.885 ;
     RECT  78 9.827 80.52 10.931 ;
     RECT  44.352 10.837 51.48 10.979 ;
     RECT  34.8 8.723 35.112 10.981 ;
     RECT  17.328 10.115 20.52 11.123 ;
     RECT  66.384 9.733 67.896 11.123 ;
     RECT  42.384 10.165 42.936 11.171 ;
     RECT  9.168 10.259 9.192 11.267 ;
     RECT  17.328 11.123 17.352 11.269 ;
     RECT  53.952 10.019 62.808 11.269 ;
     RECT  17.136 11.269 17.352 11.315 ;
     RECT  40.032 10.885 41.208 11.365 ;
     RECT  81.84 9.013 81.864 11.365 ;
     RECT  34.8 10.981 35.256 11.413 ;
     RECT  81.36 11.365 81.864 11.413 ;
     RECT  44.352 10.979 47.928 11.459 ;
     RECT  78 10.931 79.848 11.459 ;
     RECT  71.28 10.261 71.352 11.507 ;
     RECT  66.624 11.123 67.896 11.699 ;
     RECT  22.944 9.925 24.312 11.749 ;
     RECT  72.432 9.155 73.848 11.749 ;
     RECT  74.928 9.925 75.864 11.749 ;
     RECT  29.232 10.835 30.264 11.891 ;
     RECT  36.432 10.019 36.792 11.939 ;
     RECT  71.28 11.507 71.304 11.941 ;
     RECT  2.4 10.309 2.808 11.987 ;
     RECT  31.872 9.251 32.568 12.035 ;
     RECT  36.432 11.939 36.456 12.035 ;
     RECT  53.04 11.269 62.808 12.035 ;
     RECT  53.952 12.035 62.808 12.179 ;
     RECT  66.624 11.699 67.752 12.179 ;
     RECT  54 12.179 62.808 12.421 ;
     RECT  64.08 10.019 65.4 12.421 ;
     RECT  44.352 11.459 46.728 12.467 ;
     RECT  2.4 11.987 2.712 12.469 ;
     RECT  70.944 11.941 71.304 12.469 ;
     RECT  29.28 11.891 30.264 12.515 ;
     RECT  47.808 11.459 47.928 12.517 ;
     RECT  49.344 10.979 51.48 12.517 ;
     RECT  70.416 12.469 71.304 12.563 ;
     RECT  78 11.459 79.032 12.565 ;
     RECT  72.432 11.749 75.864 12.755 ;
     RECT  31.872 12.035 31.896 12.803 ;
     RECT  54 12.421 65.4 12.803 ;
     RECT  11.856 10.307 14.232 12.901 ;
     RECT  15.744 12.709 15.768 12.901 ;
     RECT  44.352 12.467 46.68 12.901 ;
     RECT  37.968 12.517 37.992 12.995 ;
     RECT  39.36 11.365 41.208 12.995 ;
     RECT  11.616 12.901 15.768 12.997 ;
     RECT  34.224 11.413 35.256 13.045 ;
     RECT  11.52 12.997 15.768 13.093 ;
     RECT  29.28 12.515 30.024 13.139 ;
     RECT  54 12.803 65.304 13.139 ;
     RECT  11.52 13.093 16.056 13.189 ;
     RECT  11.472 13.189 16.056 13.235 ;
     RECT  22.944 11.749 24.408 13.237 ;
     RECT  81.36 11.413 82.008 13.283 ;
     RECT  17.136 11.315 17.16 13.429 ;
     RECT  32.976 12.757 33 13.477 ;
     RECT  44.304 12.901 46.68 13.619 ;
     RECT  18.6 11.123 20.52 13.621 ;
     RECT  39.456 12.995 41.208 13.621 ;
     RECT  11.472 13.235 14.856 13.765 ;
     RECT  29.28 13.139 29.928 13.765 ;
     RECT  4.608 10.549 8.112 13.813 ;
     RECT  9.648 13.045 9.672 13.813 ;
     RECT  11.328 13.765 14.856 13.859 ;
     RECT  44.352 13.619 46.68 13.859 ;
     RECT  11.328 13.859 11.544 13.907 ;
     RECT  11.52 13.907 11.544 14.003 ;
     RECT  47.808 12.517 51.48 14.147 ;
     RECT  54 13.139 63.288 14.149 ;
     RECT  48.048 14.147 51.48 14.243 ;
     RECT  4.608 13.813 9.672 14.291 ;
     RECT  39.456 13.621 41.64 14.291 ;
     RECT  4.608 14.291 8.664 14.339 ;
     RECT  9.648 14.291 9.672 14.339 ;
     RECT  31.632 13.621 31.656 14.341 ;
     RECT  32.976 13.477 33.048 14.341 ;
     RECT  28.848 13.765 29.928 14.387 ;
     RECT  31.632 14.341 33.048 14.387 ;
     RECT  37.056 13.669 37.08 14.389 ;
     RECT  18.6 13.621 20.808 14.435 ;
     RECT  78 12.565 79.992 14.675 ;
     RECT  42.912 11.171 42.936 14.869 ;
     RECT  12.528 13.859 14.856 14.965 ;
     RECT  16.032 13.235 16.056 14.965 ;
     RECT  42.912 14.869 43.272 15.107 ;
     RECT  72.432 12.755 74.952 15.253 ;
     RECT  12.528 14.965 16.056 15.349 ;
     RECT  22.944 13.237 24.456 15.349 ;
     RECT  64.992 13.139 65.304 15.349 ;
     RECT  66.624 12.179 67.512 15.349 ;
     RECT  48.048 14.243 48.36 15.395 ;
     RECT  34.224 13.045 35.784 15.397 ;
     RECT  37.008 14.389 37.08 15.397 ;
     RECT  34.224 15.397 37.08 15.443 ;
     RECT  31.632 14.387 33 15.491 ;
     RECT  42.912 15.107 43.128 15.539 ;
     RECT  2.304 12.469 2.712 15.541 ;
     RECT  64.992 15.349 67.512 15.541 ;
     RECT  34.224 15.443 37.032 15.779 ;
     RECT  20.544 14.435 20.808 15.829 ;
     RECT  78 14.675 79.032 15.829 ;
     RECT  11.808 15.349 16.056 15.923 ;
     RECT  20.544 15.829 21.048 15.971 ;
     RECT  2.304 15.541 3.048 16.019 ;
     RECT  64.944 15.541 67.512 16.019 ;
     RECT  48.336 15.395 48.36 16.357 ;
     RECT  49.344 14.243 51.48 16.357 ;
     RECT  34.224 15.779 36.072 16.501 ;
     RECT  45.6 13.859 46.68 16.501 ;
     RECT  48.336 16.357 51.48 16.501 ;
     RECT  77.904 15.829 79.032 16.549 ;
     RECT  54 14.149 63.528 16.595 ;
     RECT  45.6 16.501 51.48 16.691 ;
     RECT  22.944 15.349 25.272 16.693 ;
     RECT  29.4 14.387 29.928 16.741 ;
     RECT  9.408 15.829 9.432 16.787 ;
     RECT  17.136 13.429 17.208 16.787 ;
     RECT  54 16.595 60.696 16.835 ;
     RECT  18.6 14.435 19.56 16.933 ;
     RECT  20.544 15.971 20.568 16.933 ;
     RECT  48.528 16.691 51.48 16.933 ;
     RECT  52.896 16.501 52.92 16.933 ;
     RECT  31.632 15.491 32.568 16.981 ;
     RECT  33.888 16.501 36.072 16.981 ;
     RECT  11.424 16.501 11.448 17.029 ;
     RECT  48.528 16.933 52.92 17.029 ;
     RECT  54 16.835 59.016 17.029 ;
     RECT  39.456 14.291 41.208 17.075 ;
     RECT  2.304 16.019 2.856 17.077 ;
     RECT  11.136 17.029 11.448 17.077 ;
     RECT  39.456 17.075 40.512 17.123 ;
     RECT  31.632 16.981 36.072 17.219 ;
     RECT  29.4 16.741 30.072 17.267 ;
     RECT  17.088 17.029 17.112 17.507 ;
     RECT  42.912 15.539 42.936 17.555 ;
     RECT  11.136 17.077 11.592 17.557 ;
     RECT  81.984 13.283 82.008 17.603 ;
     RECT  2.304 17.077 3.24 17.605 ;
     RECT  61.8 16.595 63.528 17.605 ;
     RECT  64.992 16.019 67.512 17.605 ;
     RECT  80.352 15.973 80.376 17.651 ;
     RECT  70.416 12.563 70.968 17.653 ;
     RECT  77.52 16.549 79.032 17.747 ;
     RECT  18.6 16.933 20.568 17.987 ;
     RECT  22.944 16.693 26.184 17.987 ;
     RECT  12.576 15.923 16.056 18.037 ;
     RECT  2.304 17.605 3.432 18.227 ;
     RECT  48.528 17.029 59.016 18.275 ;
     RECT  10.848 17.557 11.592 18.371 ;
     RECT  31.632 17.219 36.024 18.371 ;
     RECT  48.528 18.275 56.856 18.419 ;
     RECT  54 18.419 56.856 18.467 ;
     RECT  61.8 17.605 67.512 18.517 ;
     RECT  2.4 18.227 3.432 18.563 ;
     RECT  45.6 16.691 47.448 18.563 ;
     RECT  10.848 18.371 11.448 18.661 ;
     RECT  43.104 17.653 43.128 18.709 ;
     RECT  42.768 18.709 43.128 18.755 ;
     RECT  61.68 18.517 67.512 18.755 ;
     RECT  40.2 17.123 40.512 18.757 ;
     RECT  57.888 18.275 59.016 18.805 ;
     RECT  76.368 18.133 76.392 18.805 ;
     RECT  45.6 18.563 46.68 18.851 ;
     RECT  64.176 18.755 67.512 18.851 ;
     RECT  4.608 14.339 8.112 18.899 ;
     RECT  40.032 18.757 40.512 18.899 ;
     RECT  76.032 18.805 76.392 18.995 ;
     RECT  22.944 17.987 25.272 19.141 ;
     RECT  48.528 18.419 52.584 19.235 ;
     RECT  22.896 19.141 25.272 19.237 ;
     RECT  49.248 19.235 52.584 19.379 ;
     RECT  27.888 16.789 27.912 19.381 ;
     RECT  29.4 17.267 29.928 19.381 ;
     RECT  7.152 18.899 8.112 19.427 ;
     RECT  12.576 18.037 16.776 19.427 ;
     RECT  27.888 19.381 29.928 19.427 ;
     RECT  28.704 19.427 29.928 19.477 ;
     RECT  31.632 18.371 32.28 19.477 ;
     RECT  45.6 18.851 46.104 19.477 ;
     RECT  42.768 18.755 42.792 19.523 ;
     RECT  40.2 18.899 40.512 19.573 ;
     RECT  64.992 18.851 67.512 19.621 ;
     RECT  81.168 18.757 81.192 19.765 ;
     RECT  80.88 19.765 81.192 19.811 ;
     RECT  52.56 19.379 52.584 19.813 ;
     RECT  54.288 18.467 56.856 19.813 ;
     RECT  28.704 19.477 32.28 19.909 ;
     RECT  33.264 18.371 36.024 19.909 ;
     RECT  7.68 19.427 8.112 19.955 ;
     RECT  2.4 18.563 2.856 20.003 ;
     RECT  9.984 18.661 11.448 20.003 ;
     RECT  76.032 18.995 76.056 20.003 ;
     RECT  45.36 19.477 46.104 20.051 ;
     RECT  69.504 17.653 70.968 20.051 ;
     RECT  22.896 19.237 25.944 20.147 ;
     RECT  28.704 19.909 36.024 20.147 ;
     RECT  60.192 16.835 60.696 20.197 ;
     RECT  61.68 18.755 62.808 20.197 ;
     RECT  40.2 19.573 41.352 20.291 ;
     RECT  60.192 20.197 62.808 20.293 ;
     RECT  10.848 20.003 11.448 20.339 ;
     RECT  22.896 20.147 25.272 20.531 ;
     RECT  57.888 18.805 59.112 20.725 ;
     RECT  60.096 20.293 62.808 20.725 ;
     RECT  28.704 20.147 30.12 20.819 ;
     RECT  64.992 19.621 67.848 20.867 ;
     RECT  44.352 13.859 44.376 21.013 ;
     RECT  83.4 2.151 83.712 21.061 ;
     RECT  80.88 19.811 80.904 21.107 ;
     RECT  4.608 18.899 5.4 21.155 ;
     RECT  7.8 19.955 8.112 21.157 ;
     RECT  78 17.747 79.032 21.157 ;
     RECT  78 21.157 79.656 21.203 ;
     RECT  18.6 17.987 19.56 21.397 ;
     RECT  20.544 17.987 20.568 21.397 ;
     RECT  22.32 21.301 22.344 21.491 ;
     RECT  45.6 20.051 46.104 21.637 ;
     RECT  29.04 20.819 30.12 21.683 ;
     RECT  82.752 21.061 83.712 21.683 ;
     RECT  66.048 20.867 67.848 21.731 ;
     RECT  11.136 20.339 11.448 21.733 ;
     RECT  12.576 19.427 16.488 21.733 ;
     RECT  11.136 21.733 16.68 21.875 ;
     RECT  7.8 21.157 8.472 21.971 ;
     RECT  12.576 21.875 16.68 21.971 ;
     RECT  70.272 20.051 70.968 22.019 ;
     RECT  45.6 21.637 47.832 22.067 ;
     RECT  27.36 21.397 27.384 22.069 ;
     RECT  31.632 20.147 36.024 22.165 ;
     RECT  27.36 22.069 27.432 22.211 ;
     RECT  45.6 22.067 46.104 22.259 ;
     RECT  47.184 22.067 47.832 22.307 ;
     RECT  43.536 21.013 44.376 22.451 ;
     RECT  5.136 21.155 5.4 22.453 ;
     RECT  44.352 22.451 44.376 22.453 ;
     RECT  72.384 15.253 74.952 22.499 ;
     RECT  5.136 22.453 5.688 22.549 ;
     RECT  78 21.203 78.312 22.549 ;
     RECT  22.272 21.589 22.296 22.597 ;
     RECT  23.328 20.531 25.272 22.597 ;
     RECT  4.848 22.549 5.688 22.693 ;
     RECT  29.04 21.683 29.712 22.693 ;
     RECT  64.992 20.867 65.016 22.693 ;
     RECT  66.048 21.731 67.656 22.693 ;
     RECT  40.2 20.291 40.512 22.741 ;
     RECT  64.992 22.693 67.656 22.787 ;
     RECT  79.632 21.203 79.656 22.787 ;
     RECT  11.136 21.875 11.448 22.789 ;
     RECT  63.84 21.157 63.864 22.835 ;
     RECT  28.704 22.693 29.712 22.883 ;
     RECT  31.296 22.165 36.024 23.075 ;
     RECT  22.272 22.597 25.272 23.171 ;
     RECT  2.4 20.003 2.712 23.173 ;
     RECT  22.416 23.171 25.272 23.315 ;
     RECT  10.656 22.789 11.448 23.317 ;
     RECT  18.6 21.397 20.568 23.317 ;
     RECT  77.616 22.549 78.312 23.317 ;
     RECT  7.8 21.971 8.112 23.365 ;
     RECT  9.84 23.317 11.448 23.365 ;
     RECT  12.576 21.971 16.056 23.365 ;
     RECT  75.936 21.925 75.96 23.555 ;
     RECT  81.072 21.397 81.096 23.555 ;
     RECT  77.616 23.317 78.6 23.603 ;
     RECT  49.248 19.379 51.48 23.605 ;
     RECT  52.56 19.813 56.856 23.605 ;
     RECT  9.84 23.365 16.056 23.651 ;
     RECT  22.416 23.315 25.032 23.699 ;
     RECT  44.352 22.453 44.568 23.845 ;
     RECT  45.6 22.259 46.008 23.845 ;
     RECT  27.36 22.211 27.384 23.893 ;
     RECT  29.088 22.883 29.712 23.893 ;
     RECT  31.632 23.075 36.024 23.939 ;
     RECT  27.36 23.893 29.712 23.987 ;
     RECT  49.248 23.605 56.856 23.987 ;
     RECT  57.888 20.725 62.808 23.987 ;
     RECT  9.84 23.651 9.864 24.083 ;
     RECT  2.4 23.173 2.856 24.131 ;
     RECT  44.352 23.845 46.008 24.325 ;
     RECT  4.848 22.693 6.024 24.419 ;
     RECT  72.384 22.499 74.184 24.421 ;
     RECT  64.992 22.787 67.512 24.469 ;
     RECT  78 23.603 78.6 24.659 ;
     RECT  29.4 23.987 29.712 24.709 ;
     RECT  22.416 23.699 24.552 24.755 ;
     RECT  7.248 23.365 8.112 24.901 ;
     RECT  44.064 24.325 46.008 24.947 ;
     RECT  11.136 23.651 16.056 24.949 ;
     RECT  17.616 23.317 20.568 24.949 ;
     RECT  27.936 23.987 28.2 25.043 ;
     RECT  2.4 24.131 2.712 25.045 ;
     RECT  11.136 24.949 20.568 25.045 ;
     RECT  10.176 25.045 20.568 25.091 ;
     RECT  38.448 23.125 38.472 25.139 ;
     RECT  31.632 23.939 35.784 25.141 ;
     RECT  22.416 24.755 24.312 25.235 ;
     RECT  44.064 24.947 45.912 25.235 ;
     RECT  26.928 25.045 26.952 25.237 ;
     RECT  26.496 25.237 26.952 25.283 ;
     RECT  4.848 24.419 5.448 25.381 ;
     RECT  26.496 25.283 26.52 25.427 ;
     RECT  4.848 25.381 6.168 25.429 ;
     RECT  7.2 24.901 8.112 25.429 ;
     RECT  78 24.659 78.312 25.525 ;
     RECT  47.808 22.307 47.832 25.621 ;
     RECT  64.992 24.469 68.376 25.621 ;
     RECT  4.848 25.429 8.112 25.717 ;
     RECT  28.176 25.043 28.2 25.717 ;
     RECT  29.4 24.709 29.88 25.717 ;
     RECT  4.848 25.717 8.472 25.859 ;
     RECT  10.176 25.091 16.056 26.099 ;
     RECT  39.792 22.741 40.512 26.149 ;
     RECT  22.8 25.235 24.312 26.197 ;
     RECT  2.304 25.045 2.712 26.243 ;
     RECT  31.632 25.141 36.456 26.243 ;
     RECT  42.24 23.701 42.264 26.243 ;
     RECT  46.944 25.621 47.832 26.243 ;
     RECT  60.672 23.987 62.808 26.243 ;
     RECT  64.416 25.621 68.376 26.243 ;
     RECT  22.8 26.197 25.704 26.339 ;
     RECT  44.352 25.235 45.912 26.437 ;
     RECT  4.848 25.859 8.112 26.483 ;
     RECT  10.848 26.099 16.056 26.485 ;
     RECT  17.52 25.091 20.568 26.485 ;
     RECT  4.848 26.483 6.168 26.531 ;
     RECT  77.904 25.525 78.312 26.581 ;
     RECT  64.416 26.243 67.512 26.629 ;
     RECT  72.384 24.421 75.144 26.629 ;
     RECT  77.904 26.581 78.84 26.629 ;
     RECT  25.68 26.339 25.704 26.725 ;
     RECT  28.176 25.717 29.88 26.725 ;
     RECT  52.56 23.987 56.856 26.725 ;
     RECT  57.888 23.987 59.256 26.725 ;
     RECT  80.88 23.893 80.904 26.771 ;
     RECT  52.56 26.725 59.256 26.819 ;
     RECT  64.368 26.629 67.512 26.819 ;
     RECT  10.848 26.485 20.568 26.867 ;
     RECT  31.632 26.243 35.784 27.061 ;
     RECT  36.864 26.581 36.888 27.155 ;
     RECT  31.152 27.061 35.784 27.203 ;
     RECT  4.848 26.531 5.88 27.205 ;
     RECT  9.552 26.629 9.576 27.205 ;
     RECT  43.968 26.437 45.912 27.205 ;
     RECT  70.416 22.019 70.968 27.205 ;
     RECT  72.384 26.629 75.576 27.205 ;
     RECT  25.68 26.725 26.664 27.299 ;
     RECT  49.248 23.987 51.48 27.301 ;
     RECT  52.56 26.819 53.496 27.301 ;
     RECT  69.552 27.205 75.576 27.301 ;
     RECT  39.216 26.149 40.512 27.347 ;
     RECT  60.672 26.243 62.112 27.347 ;
     RECT  69.552 27.301 75.816 27.347 ;
     RECT  64.368 26.819 65.016 27.395 ;
     RECT  10.848 26.867 16.056 27.491 ;
     RECT  4.704 27.205 5.88 27.587 ;
     RECT  38.064 27.589 38.088 27.733 ;
     RECT  61.8 27.347 62.112 27.829 ;
     RECT  63.216 27.301 63.24 27.829 ;
     RECT  13.2 27.491 16.056 27.875 ;
     RECT  77.856 26.629 78.84 27.875 ;
     RECT  7.632 26.483 8.112 27.877 ;
     RECT  17.52 26.867 20.568 27.877 ;
     RECT  37.152 27.733 38.088 27.877 ;
     RECT  49.248 27.301 53.496 28.115 ;
     RECT  22.8 26.339 24.312 28.117 ;
     RECT  26.64 27.299 26.664 28.117 ;
     RECT  28.176 26.725 30.072 28.117 ;
     RECT  43.968 27.205 46.872 28.117 ;
     RECT  54.624 26.819 59.256 28.211 ;
     RECT  69.552 27.347 74.184 28.211 ;
     RECT  58.32 28.211 59.256 28.261 ;
     RECT  77.856 27.875 78.408 28.261 ;
     RECT  61.8 27.829 63.24 28.309 ;
     RECT  37.152 27.877 38.328 28.403 ;
     RECT  2.4 26.243 2.712 28.453 ;
     RECT  13.2 27.875 13.992 28.453 ;
     RECT  22.8 28.117 24.408 28.499 ;
     RECT  4.704 27.587 5.4 28.547 ;
     RECT  15.36 27.875 16.056 28.547 ;
     RECT  43.968 28.117 47.256 28.547 ;
     RECT  48.24 28.405 48.264 28.547 ;
     RECT  49.248 28.115 51.48 28.547 ;
     RECT  61.8 28.309 63.864 28.547 ;
     RECT  75.264 27.347 75.816 28.547 ;
     RECT  10.848 27.491 12.024 28.595 ;
     RECT  13.104 28.453 13.992 28.595 ;
     RECT  54.624 28.211 57.048 28.643 ;
     RECT  26.64 28.117 30.072 28.787 ;
     RECT  37.152 28.403 38.136 28.787 ;
     RECT  26.64 28.787 26.664 28.885 ;
     RECT  28.176 28.787 30.072 28.933 ;
     RECT  31.632 27.203 35.784 28.933 ;
     RECT  15.84 28.547 16.056 29.027 ;
     RECT  2.4 28.453 3.624 29.029 ;
     RECT  26.352 28.885 26.664 29.075 ;
     RECT  28.176 28.933 36.264 29.075 ;
     RECT  64.992 27.395 65.016 29.077 ;
     RECT  2.4 29.029 3.72 29.123 ;
     RECT  26.64 29.075 26.664 29.123 ;
     RECT  63.84 28.547 63.864 29.123 ;
     RECT  64.992 29.077 65.112 29.123 ;
     RECT  67.104 26.819 67.512 29.123 ;
     RECT  48.288 29.077 48.312 29.219 ;
     RECT  13.2 28.595 13.992 29.365 ;
     RECT  77.52 28.261 78.408 29.459 ;
     RECT  22.848 28.499 24.408 29.557 ;
     RECT  77.856 29.459 78.408 29.557 ;
     RECT  38.064 28.787 38.136 29.651 ;
     RECT  3.696 29.123 3.72 29.699 ;
     RECT  16.032 29.027 16.056 29.797 ;
     RECT  17.376 27.877 20.568 29.797 ;
     RECT  44.352 28.547 47.256 29.797 ;
     RECT  6.288 29.077 6.312 29.893 ;
     RECT  7.344 27.877 8.112 29.893 ;
     RECT  9.552 27.205 9.624 29.941 ;
     RECT  75.696 28.547 75.816 30.035 ;
     RECT  10.848 28.595 11.88 30.037 ;
     RECT  9.36 29.941 9.624 30.083 ;
     RECT  36.768 30.037 36.792 30.179 ;
     RECT  22.848 29.557 25.272 30.181 ;
     RECT  69.552 28.211 73.848 30.227 ;
     RECT  52.56 28.115 53.496 30.229 ;
     RECT  10.608 30.037 11.88 30.275 ;
     RECT  16.032 29.797 20.568 30.275 ;
     RECT  54.624 28.643 56.712 30.325 ;
     RECT  77.856 29.557 78.648 30.563 ;
     RECT  13.2 29.365 14.088 30.565 ;
     RECT  60.672 27.347 60.696 30.565 ;
     RECT  61.8 28.547 62.808 30.565 ;
     RECT  4.704 28.547 5.256 30.661 ;
     RECT  52.56 30.229 53.592 30.661 ;
     RECT  54.624 30.325 56.904 30.661 ;
     RECT  60.672 30.565 62.808 30.707 ;
     RECT  9.36 30.083 9.576 30.755 ;
     RECT  52.56 30.661 56.904 30.803 ;
     RECT  49.584 28.547 51.48 30.805 ;
     RECT  13.056 30.565 14.088 30.851 ;
     RECT  54.624 30.803 56.904 30.851 ;
     RECT  75.792 30.035 75.816 30.851 ;
     RECT  13.2 30.851 14.088 30.899 ;
     RECT  22.032 30.181 25.272 30.899 ;
     RECT  28.176 29.075 35.784 30.899 ;
     RECT  80.688 30.181 80.712 31.139 ;
     RECT  10.704 30.275 11.88 31.235 ;
     RECT  52.56 30.803 53.592 31.285 ;
     RECT  26.784 30.709 26.808 31.331 ;
     RECT  44.352 29.797 47.304 31.331 ;
     RECT  47.232 31.331 47.304 31.379 ;
     RECT  52.464 31.285 53.592 31.379 ;
     RECT  68.544 30.229 68.568 31.379 ;
     RECT  65.088 29.123 65.112 31.525 ;
     RECT  3.84 30.661 5.256 31.715 ;
     RECT  77.856 30.563 78.312 31.909 ;
     RECT  22.032 30.899 24.408 31.955 ;
     RECT  28.176 30.899 32.472 31.957 ;
     RECT  33.888 30.899 35.784 31.957 ;
     RECT  52.464 31.379 53.544 32.099 ;
     RECT  77.856 31.909 78.6 32.243 ;
     RECT  11.136 31.235 11.88 32.389 ;
     RECT  13.2 30.899 13.992 32.389 ;
     RECT  61.68 30.707 62.808 32.435 ;
     RECT  9.552 30.755 9.576 32.437 ;
     RECT  28.176 31.957 35.784 32.723 ;
     RECT  47.28 31.379 47.304 32.771 ;
     RECT  58.32 28.261 59.688 32.867 ;
     RECT  4.704 31.715 5.256 32.915 ;
     RECT  2.4 29.123 2.712 33.013 ;
     RECT  83.4 21.683 83.712 33.013 ;
     RECT  28.176 32.723 32.472 33.059 ;
     RECT  64.944 31.525 65.112 33.059 ;
     RECT  39.36 27.347 40.512 33.061 ;
     RECT  41.712 29.557 41.736 33.061 ;
     RECT  44.352 31.331 45.912 33.061 ;
     RECT  70.416 30.227 73.848 33.155 ;
     RECT  39.36 33.061 41.736 33.347 ;
     RECT  11.136 32.389 13.992 33.395 ;
     RECT  49.248 30.805 51.48 33.445 ;
     RECT  52.56 32.099 53.544 33.445 ;
     RECT  82.752 33.013 83.712 33.539 ;
     RECT  67.2 29.123 67.512 33.589 ;
     RECT  33.888 32.723 35.784 33.635 ;
     RECT  28.176 33.059 31.656 33.683 ;
     RECT  4.8 32.915 5.256 33.685 ;
     RECT  6.288 29.893 8.112 33.685 ;
     RECT  22.848 31.955 24.408 33.781 ;
     RECT  22.848 33.781 25.032 33.829 ;
     RECT  58.32 32.867 58.344 33.971 ;
     RECT  65.088 33.059 65.112 34.021 ;
     RECT  26.304 33.301 26.328 34.067 ;
     RECT  47.328 33.397 47.352 34.115 ;
     RECT  4.8 33.685 8.112 34.117 ;
     RECT  59.328 32.867 59.688 34.165 ;
     RECT  60.672 30.707 60.696 34.165 ;
     RECT  28.176 33.683 30.072 34.259 ;
     RECT  59.328 34.165 60.696 34.357 ;
     RECT  38.064 29.651 38.088 34.453 ;
     RECT  39.36 33.347 40.512 34.453 ;
     RECT  38.064 34.453 40.512 34.499 ;
     RECT  77.856 32.243 78.312 34.597 ;
     RECT  17.376 30.275 20.568 34.643 ;
     RECT  44.352 33.061 46.008 34.741 ;
     RECT  49.248 33.445 53.544 34.741 ;
     RECT  54.624 30.851 56.712 34.741 ;
     RECT  70.512 33.155 73.848 34.741 ;
     RECT  77.856 34.597 78.648 34.741 ;
     RECT  4.656 34.117 8.112 34.787 ;
     RECT  77.856 34.741 78.888 34.787 ;
     RECT  43.872 34.741 46.008 34.789 ;
     RECT  11.136 33.395 11.64 34.835 ;
     RECT  38.064 34.499 38.76 34.835 ;
     RECT  58.656 34.357 60.696 34.835 ;
     RECT  2.4 33.013 3.528 34.883 ;
     RECT  2.4 34.883 2.808 34.931 ;
     RECT  43.104 34.789 46.008 34.931 ;
     RECT  59.328 34.835 60.696 34.979 ;
     RECT  9.552 32.437 9.72 35.027 ;
     RECT  38.64 34.835 38.76 35.075 ;
     RECT  16.032 30.275 16.056 35.125 ;
     RECT  65.088 34.021 65.304 35.171 ;
     RECT  15.936 35.125 16.056 35.267 ;
     RECT  66.288 33.589 67.512 35.317 ;
     RECT  4.8 34.787 8.112 35.363 ;
     RECT  32.832 34.837 32.856 35.363 ;
     RECT  70.272 34.741 73.848 35.363 ;
     RECT  13.2 33.395 13.992 35.413 ;
     RECT  47.904 34.165 47.928 35.413 ;
     RECT  13.2 35.413 14.568 35.651 ;
     RECT  66.288 35.317 68.424 35.747 ;
     RECT  70.512 35.363 73.848 35.747 ;
     RECT  63.984 35.269 64.008 35.843 ;
     RECT  33.888 33.635 35.112 35.845 ;
     RECT  36.432 34.501 36.456 35.845 ;
     RECT  78 34.787 78.888 35.891 ;
     RECT  5.424 35.363 8.112 35.893 ;
     RECT  28.176 34.259 28.2 35.941 ;
     RECT  29.28 34.259 30.072 35.941 ;
     RECT  67.2 35.747 68.424 35.987 ;
     RECT  33.888 35.845 36.456 36.083 ;
     RECT  9.648 35.027 9.72 36.085 ;
     RECT  11.136 34.835 11.16 36.085 ;
     RECT  47.904 35.413 47.976 36.227 ;
     RECT  9.648 36.085 11.16 36.421 ;
     RECT  5.424 35.893 8.328 36.469 ;
     RECT  9.552 36.421 11.16 36.469 ;
     RECT  60.672 34.979 60.696 36.469 ;
     RECT  61.8 32.435 62.808 36.469 ;
     RECT  17.376 34.643 17.544 36.515 ;
     RECT  59.328 34.979 59.688 36.515 ;
     RECT  70.512 35.747 70.968 36.517 ;
     RECT  5.424 36.469 11.16 36.563 ;
     RECT  36.432 36.083 36.456 36.563 ;
     RECT  11.136 36.563 11.16 36.613 ;
     RECT  17.52 36.515 17.544 36.661 ;
     RECT  18.6 34.643 20.568 36.661 ;
     RECT  80.976 35.317 81 36.707 ;
     RECT  22.848 33.829 25.128 36.803 ;
     RECT  43.104 34.931 45.912 36.803 ;
     RECT  11.136 36.613 11.688 36.949 ;
     RECT  13.2 35.651 13.992 36.949 ;
     RECT  72.384 35.747 73.848 36.949 ;
     RECT  78 35.891 78.648 36.949 ;
     RECT  5.424 36.563 9.72 36.995 ;
     RECT  83.4 33.539 83.712 36.997 ;
     RECT  16.032 35.267 16.056 37.043 ;
     RECT  47.904 36.227 47.928 37.043 ;
     RECT  57.696 35.989 57.72 37.043 ;
     RECT  60.672 36.469 62.808 37.043 ;
     RECT  28.176 35.941 30.072 37.045 ;
     RECT  31.632 33.683 31.656 37.045 ;
     RECT  77.232 36.949 78.648 37.091 ;
     RECT  40.08 34.499 40.512 37.093 ;
     RECT  41.712 33.347 41.736 37.093 ;
     RECT  72.384 36.949 74.664 37.139 ;
     RECT  28.176 37.045 31.656 37.141 ;
     RECT  16.368 37.045 16.392 37.189 ;
     RECT  11.136 36.949 13.992 37.235 ;
     RECT  28.08 37.141 31.656 37.331 ;
     RECT  16.368 37.189 16.44 37.379 ;
     RECT  16.416 37.379 16.44 37.475 ;
     RECT  43.104 36.803 43.128 37.475 ;
     RECT  6.672 36.995 9.72 37.571 ;
     RECT  38.64 35.075 38.664 37.573 ;
     RECT  40.08 37.093 41.736 37.573 ;
     RECT  65.088 35.171 65.112 37.573 ;
     RECT  67.2 35.987 67.512 37.573 ;
     RECT  17.52 36.661 20.568 37.619 ;
     RECT  26.784 36.949 26.808 37.619 ;
     RECT  59.664 36.515 59.688 37.861 ;
     RECT  60.672 37.043 60.792 37.861 ;
     RECT  44.352 36.803 45.912 38.101 ;
     RECT  65.088 37.573 65.4 38.149 ;
     RECT  5.424 36.995 5.448 38.195 ;
     RECT  38.64 37.573 41.736 38.195 ;
     RECT  72.432 37.139 74.664 38.195 ;
     RECT  77.232 37.091 78.312 38.195 ;
     RECT  28.176 37.331 31.656 38.243 ;
     RECT  66.72 37.573 67.512 38.243 ;
     RECT  70.416 36.517 70.968 38.243 ;
     RECT  82.992 36.997 83.712 38.243 ;
     RECT  11.136 37.235 11.688 38.339 ;
     RECT  43.968 38.101 45.912 38.341 ;
     RECT  46.896 38.101 46.92 38.341 ;
     RECT  9.696 37.571 9.72 38.389 ;
     RECT  72.432 38.195 73.8 38.437 ;
     RECT  72.384 38.437 73.8 38.579 ;
     RECT  43.968 38.341 46.92 38.627 ;
     RECT  64.848 38.149 65.4 38.675 ;
     RECT  18.6 37.619 20.568 38.677 ;
     RECT  16.224 38.677 16.248 38.725 ;
     RECT  59.664 37.861 60.792 38.725 ;
     RECT  61.8 37.043 62.808 38.725 ;
     RECT  43.968 38.627 45.912 38.819 ;
     RECT  15.984 38.725 16.248 38.867 ;
     RECT  16.224 38.867 16.248 38.915 ;
     RECT  33.888 36.083 35.112 39.061 ;
     RECT  22.848 36.803 24.6 39.107 ;
     RECT  64.848 38.675 65.112 39.155 ;
     RECT  18.6 38.677 21.144 39.157 ;
     RECT  22.848 39.107 24.504 39.157 ;
     RECT  17.52 37.619 17.544 39.253 ;
     RECT  49.248 34.741 56.712 39.253 ;
     RECT  40.08 38.195 41.736 39.301 ;
     RECT  72.432 38.579 73.8 39.301 ;
     RECT  78 38.195 78.312 39.301 ;
     RECT  79.296 38.677 79.32 39.301 ;
     RECT  78 39.301 79.32 39.395 ;
     RECT  48.336 39.253 56.712 39.541 ;
     RECT  13.2 37.235 13.992 39.589 ;
     RECT  18.6 39.157 24.504 39.779 ;
     RECT  59.664 38.725 63 39.779 ;
     RECT  6.672 37.571 8.328 39.875 ;
     RECT  33.888 39.061 35.448 39.877 ;
     RECT  40.08 39.301 42.504 39.923 ;
     RECT  28.176 38.243 30.072 40.019 ;
     RECT  46.896 38.627 46.92 40.067 ;
     RECT  9.696 38.389 9.816 40.163 ;
     RECT  60.288 39.779 63 40.163 ;
     RECT  48.336 39.541 57.048 40.259 ;
     RECT  78 39.395 78.648 40.307 ;
     RECT  28.176 40.019 28.2 40.451 ;
     RECT  58.032 39.589 58.056 40.451 ;
     RECT  76.896 39.301 76.92 40.451 ;
     RECT  41.712 39.923 42.504 40.453 ;
     RECT  44.352 38.819 45.912 40.453 ;
     RECT  38.64 38.195 38.664 40.499 ;
     RECT  11.136 38.339 11.16 40.595 ;
     RECT  50.064 40.259 57.048 40.595 ;
     RECT  18.6 39.779 24.408 40.643 ;
     RECT  66.864 38.243 67.512 40.645 ;
     RECT  50.064 40.595 56.712 40.691 ;
     RECT  33.744 39.877 35.448 40.835 ;
     RECT  41.712 40.453 45.912 40.835 ;
     RECT  72.432 39.301 74.424 40.835 ;
     RECT  33.744 40.835 35.112 40.837 ;
     RECT  53.472 40.691 56.712 40.883 ;
     RECT  44.352 40.835 45.912 40.885 ;
     RECT  65.088 39.155 65.112 40.981 ;
     RECT  70.512 38.243 70.968 40.981 ;
     RECT  9.696 40.163 9.72 41.027 ;
     RECT  13.2 39.589 14.184 41.027 ;
     RECT  41.712 40.835 42.888 41.027 ;
     RECT  64.416 40.981 65.112 41.077 ;
     RECT  53.472 40.883 53.544 41.123 ;
     RECT  22.032 40.643 24.408 41.171 ;
     RECT  44.352 40.885 46.008 41.221 ;
     RECT  64.416 41.077 65.688 41.315 ;
     RECT  16.992 39.253 17.544 41.507 ;
     RECT  44.352 41.221 46.104 41.555 ;
     RECT  48.336 40.259 48.36 41.557 ;
     RECT  58.128 41.269 58.152 41.557 ;
     RECT  60.288 40.163 60.552 41.557 ;
     RECT  61.8 40.163 63 41.557 ;
     RECT  29.4 40.019 30.072 41.605 ;
     RECT  13.2 41.027 13.992 41.845 ;
     RECT  78 40.307 78.312 41.893 ;
     RECT  13.008 41.845 13.992 42.179 ;
     RECT  66.864 40.645 67.848 42.179 ;
     RECT  70.416 40.981 70.968 42.181 ;
     RECT  72.432 40.835 73.8 42.181 ;
     RECT  18.6 40.643 20.568 42.227 ;
     RECT  29.28 41.605 30.072 42.227 ;
     RECT  40.08 39.923 40.512 42.227 ;
     RECT  64.416 41.315 65.592 42.227 ;
     RECT  37.728 41.749 37.752 42.467 ;
     RECT  48.336 41.557 48.792 42.565 ;
     RECT  50.064 40.691 52.344 42.565 ;
     RECT  31.632 38.243 31.656 42.709 ;
     RECT  48.336 42.565 52.344 42.709 ;
     RECT  48.24 42.709 52.44 42.755 ;
     RECT  60.288 41.557 63 42.757 ;
     RECT  22.032 41.171 22.056 42.803 ;
     RECT  58.128 41.557 58.968 42.803 ;
     RECT  17.232 41.507 17.544 42.853 ;
     RECT  9.216 41.749 9.24 42.995 ;
     RECT  31.632 42.709 31.8 43.091 ;
     RECT  52.32 42.755 52.44 43.235 ;
     RECT  48.24 42.755 51.312 43.283 ;
     RECT  70.416 42.181 73.8 43.283 ;
     RECT  44.352 41.555 45.912 43.285 ;
     RECT  42.864 41.027 42.888 43.331 ;
     RECT  75.648 42.085 75.672 43.333 ;
     RECT  66.864 42.179 67.512 43.379 ;
     RECT  48.24 43.283 48.792 43.427 ;
     RECT  44.208 43.285 45.912 43.429 ;
     RECT  6.672 39.875 8.112 43.571 ;
     RECT  40.2 42.227 40.512 43.717 ;
     RECT  41.712 41.027 41.736 43.717 ;
     RECT  64.992 42.227 65.016 43.765 ;
     RECT  48.24 43.427 48.264 43.811 ;
     RECT  54.624 40.883 56.712 43.813 ;
     RECT  43.344 43.429 45.912 43.859 ;
     RECT  75.024 43.333 75.672 43.861 ;
     RECT  75.024 43.861 75.864 44.099 ;
     RECT  13.104 42.179 13.992 44.101 ;
     RECT  40.2 43.717 41.736 44.245 ;
     RECT  13.104 44.101 14.856 44.291 ;
     RECT  26.064 42.853 26.088 44.339 ;
     RECT  17.232 42.853 17.592 44.437 ;
     RECT  18.6 42.227 20.28 44.437 ;
     RECT  21.744 43.189 21.768 44.437 ;
     RECT  33.312 40.837 35.112 44.437 ;
     RECT  58.944 42.803 58.968 44.437 ;
     RECT  54.624 43.813 57.096 44.627 ;
     RECT  75.84 44.099 75.864 44.627 ;
     RECT  33.216 44.437 35.112 44.677 ;
     RECT  17.232 44.437 20.28 44.725 ;
     RECT  21.456 44.437 21.768 44.725 ;
     RECT  13.104 44.291 13.992 44.771 ;
     RECT  64.752 43.765 65.016 44.773 ;
     RECT  17.232 44.725 21.768 44.819 ;
     RECT  32.64 44.677 36.072 44.867 ;
     RECT  60.192 42.757 63 44.869 ;
     RECT  2.4 34.931 2.712 44.965 ;
     RECT  11.808 43.861 11.832 44.965 ;
     RECT  44.352 43.859 45.912 44.965 ;
     RECT  72.432 43.283 73.8 44.965 ;
     RECT  47.904 44.341 47.928 45.011 ;
     RECT  64.272 44.773 65.016 45.011 ;
     RECT  23.616 41.171 24.408 45.013 ;
     RECT  40.2 44.245 41.784 45.013 ;
     RECT  43.344 43.859 43.368 45.059 ;
     RECT  7.056 43.571 8.112 45.109 ;
     RECT  69.408 40.405 69.432 45.109 ;
     RECT  53.52 41.123 53.544 45.253 ;
     RECT  54.624 44.627 56.712 45.253 ;
     RECT  23.616 45.013 25.176 45.443 ;
     RECT  23.616 45.443 24.312 45.493 ;
     RECT  17.232 44.819 21.384 45.541 ;
     RECT  40.2 45.013 41.832 45.541 ;
     RECT  58.656 44.437 58.968 45.587 ;
     RECT  33.216 44.867 36.072 45.589 ;
     RECT  23.184 45.493 24.312 45.635 ;
     RECT  44.352 44.965 46.44 45.683 ;
     RECT  72.192 44.965 73.8 45.683 ;
     RECT  68.832 45.109 69.432 45.731 ;
     RECT  78 41.893 79.08 45.731 ;
     RECT  58.752 45.587 58.968 45.733 ;
     RECT  60.192 44.869 63.24 45.733 ;
     RECT  27.792 45.397 27.816 45.829 ;
     RECT  29.4 42.227 30.072 45.829 ;
     RECT  11.28 44.965 11.832 45.923 ;
     RECT  53.52 45.253 56.712 45.971 ;
     RECT  2.4 44.965 2.808 46.019 ;
     RECT  50.064 43.283 51.312 46.021 ;
     RECT  52.416 43.235 52.44 46.021 ;
     RECT  26.064 45.877 26.088 46.067 ;
     RECT  27.792 45.829 30.072 46.067 ;
     RECT  50.064 46.021 52.44 46.067 ;
     RECT  48.384 45.541 48.408 46.163 ;
     RECT  69.408 45.731 69.432 46.165 ;
     RECT  70.416 43.283 70.968 46.165 ;
     RECT  16.512 45.541 21.384 46.259 ;
     RECT  27.792 46.067 27.816 46.259 ;
     RECT  44.352 45.683 46.008 46.259 ;
     RECT  13.104 44.771 13.512 46.357 ;
     RECT  40.2 45.541 42.792 46.499 ;
     RECT  17.616 46.259 21.384 46.547 ;
     RECT  69.408 46.165 70.968 46.645 ;
     RECT  72.432 45.683 73.8 46.645 ;
     RECT  6.912 45.109 8.112 46.741 ;
     RECT  58.752 45.733 63.24 46.741 ;
     RECT  16.512 46.259 16.536 46.787 ;
     RECT  17.616 46.547 21.192 46.787 ;
     RECT  23.328 45.635 24.312 46.787 ;
     RECT  33.216 45.589 37.032 46.787 ;
     RECT  69.408 46.645 73.8 46.787 ;
     RECT  13.056 46.357 13.512 46.789 ;
     RECT  82.032 45.541 82.056 46.931 ;
     RECT  58.512 46.741 63.24 46.979 ;
     RECT  6.624 46.741 8.112 47.027 ;
     RECT  69.408 46.787 69.432 47.029 ;
     RECT  60.192 46.979 63.24 47.075 ;
     RECT  69.072 47.029 69.432 47.075 ;
     RECT  33.216 46.787 36.36 47.123 ;
     RECT  31.632 43.091 31.656 47.125 ;
     RECT  45.6 46.259 46.008 47.171 ;
     RECT  17.616 46.787 20.28 47.219 ;
     RECT  29.4 46.067 30.072 47.413 ;
     RECT  31.104 47.125 31.656 47.413 ;
     RECT  38.4 47.269 38.424 47.701 ;
     RECT  9.648 46.885 9.672 47.747 ;
     RECT  13.008 46.789 13.512 47.747 ;
     RECT  53.52 45.971 53.544 47.747 ;
     RECT  14.688 47.221 14.712 47.749 ;
     RECT  38.4 47.701 39.048 47.891 ;
     RECT  58.512 46.979 58.776 47.939 ;
     RECT  29.4 47.413 31.656 48.131 ;
     RECT  67.2 43.379 67.512 48.133 ;
     RECT  40.2 46.499 42.312 48.181 ;
     RECT  44.352 46.259 44.376 48.229 ;
     RECT  78 45.731 78.312 48.229 ;
     RECT  3.888 40.405 3.912 48.277 ;
     RECT  14.688 47.749 15.672 48.323 ;
     RECT  40.2 48.181 43.224 48.323 ;
     RECT  60.192 47.075 63 48.371 ;
     RECT  64.992 45.011 65.016 48.373 ;
     RECT  70.416 46.787 73.8 48.419 ;
     RECT  7.056 47.027 8.112 48.421 ;
     RECT  20.256 47.219 20.28 48.421 ;
     RECT  44.352 48.229 44.424 48.421 ;
     RECT  45.6 47.171 45.912 48.421 ;
     RECT  47.616 46.405 47.64 48.421 ;
     RECT  3.888 48.277 4.584 48.467 ;
     RECT  13.2 47.747 13.512 48.469 ;
     RECT  70.416 48.419 70.968 48.469 ;
     RECT  66.528 48.133 67.512 48.563 ;
     RECT  23.616 46.787 24.312 48.613 ;
     RECT  33.216 47.123 36.072 48.661 ;
     RECT  39.024 47.891 39.048 48.661 ;
     RECT  40.2 48.323 42.312 48.661 ;
     RECT  44.352 48.421 45.912 48.757 ;
     RECT  61.632 48.371 63 48.995 ;
     RECT  64.464 48.373 65.016 48.995 ;
     RECT  50.064 46.067 52.104 48.997 ;
     RECT  64.896 48.995 65.016 49.043 ;
     RECT  47.28 48.421 47.64 49.091 ;
     RECT  13.2 48.469 14.28 49.139 ;
     RECT  22.176 48.421 22.2 49.187 ;
     RECT  23.328 48.613 24.312 49.187 ;
     RECT  20.112 48.421 20.28 49.235 ;
     RECT  50.064 48.997 53.016 49.235 ;
     RECT  32.784 48.661 36.072 49.283 ;
     RECT  47.28 49.091 47.592 49.333 ;
     RECT  76.56 47.461 76.584 49.427 ;
     RECT  43.296 48.757 45.912 49.475 ;
     RECT  4.56 48.467 4.584 49.477 ;
     RECT  31.104 48.131 31.656 49.477 ;
     RECT  32.784 49.283 33.24 49.477 ;
     RECT  54.624 45.971 56.712 49.477 ;
     RECT  70.08 48.469 70.968 49.477 ;
     RECT  13.2 49.139 13.944 49.525 ;
     RECT  61.632 48.995 62.112 49.525 ;
     RECT  66.768 48.563 67.512 49.525 ;
     RECT  72.384 48.419 73.8 49.525 ;
     RECT  39.024 48.661 42.312 49.571 ;
     RECT  60.192 48.371 60.216 49.619 ;
     RECT  70.08 49.477 71.16 49.619 ;
     RECT  78 48.229 78.792 49.619 ;
     RECT  70.416 49.619 71.16 49.667 ;
     RECT  25.584 46.405 25.608 49.715 ;
     RECT  58.752 47.939 58.776 49.717 ;
     RECT  58.752 49.717 58.968 49.763 ;
     RECT  29.4 48.131 30.072 49.765 ;
     RECT  31.104 49.477 33.24 49.765 ;
     RECT  80.688 48.949 80.712 49.861 ;
     RECT  11.808 45.923 11.832 50.003 ;
     RECT  17.616 47.219 18.912 50.003 ;
     RECT  6.576 48.421 8.112 50.051 ;
     RECT  75.216 49.381 75.24 50.101 ;
     RECT  34.224 49.283 36.072 50.195 ;
     RECT  75.168 50.101 75.24 50.243 ;
     RECT  52.992 49.235 53.016 50.389 ;
     RECT  54.528 49.477 56.712 50.389 ;
     RECT  52.992 50.389 56.712 50.435 ;
     RECT  43.296 49.475 44.424 50.485 ;
     RECT  45.6 49.475 45.912 50.485 ;
     RECT  43.296 50.485 45.912 50.531 ;
     RECT  17.184 50.149 17.208 50.533 ;
     RECT  39.984 49.571 40.776 50.533 ;
     RECT  47.088 49.333 47.592 50.677 ;
     RECT  78 49.619 78.312 50.677 ;
     RECT  80.544 49.861 80.712 50.677 ;
     RECT  29.4 49.765 33.24 50.723 ;
     RECT  66.72 49.525 67.512 50.725 ;
     RECT  39.456 50.533 40.776 50.771 ;
     RECT  53.952 50.435 56.712 50.771 ;
     RECT  61.584 49.525 62.112 50.773 ;
     RECT  75.168 50.243 75.192 50.867 ;
     RECT  60.816 50.773 62.112 50.963 ;
     RECT  39.456 50.771 40.68 50.965 ;
     RECT  42.288 49.571 42.312 51.013 ;
     RECT  61.584 50.963 62.112 51.155 ;
     RECT  50.064 49.235 51.312 51.157 ;
     RECT  33.216 50.723 33.24 51.203 ;
     RECT  37.056 48.085 37.08 51.203 ;
     RECT  13.104 49.525 13.944 51.205 ;
     RECT  18.6 50.003 18.912 51.205 ;
     RECT  77.52 50.677 78.312 51.205 ;
     RECT  20.64 49.525 20.952 51.251 ;
     RECT  13.104 51.205 14.28 51.253 ;
     RECT  66.624 50.725 67.512 51.253 ;
     RECT  16.992 50.533 17.208 51.347 ;
     RECT  6.72 50.051 8.112 51.395 ;
     RECT  26.304 51.253 26.328 51.395 ;
     RECT  38.496 50.965 40.68 51.395 ;
     RECT  80.544 50.677 81.384 51.493 ;
     RECT  10.848 50.101 10.872 51.539 ;
     RECT  13.104 51.253 14.808 51.635 ;
     RECT  29.4 50.723 31.656 51.637 ;
     RECT  64.992 49.043 65.016 51.685 ;
     RECT  66.48 51.253 67.512 51.685 ;
     RECT  50.064 51.157 52.296 51.781 ;
     RECT  4.56 49.477 4.824 51.923 ;
     RECT  43.632 50.531 45.912 51.923 ;
     RECT  47.088 50.677 48.216 51.923 ;
     RECT  77.52 51.205 79.08 51.923 ;
     RECT  80.544 51.493 81.672 51.923 ;
     RECT  29.28 51.637 31.656 51.973 ;
     RECT  34.704 50.195 36.072 52.019 ;
     RECT  6.72 51.395 6.744 52.067 ;
     RECT  2.4 46.019 2.712 52.165 ;
     RECT  23.616 49.187 24.312 52.165 ;
     RECT  42.192 51.013 42.312 52.211 ;
     RECT  58.944 49.763 58.968 52.211 ;
     RECT  34.8 52.019 36.072 52.309 ;
     RECT  13.2 51.635 14.808 52.403 ;
     RECT  29.28 51.973 32.376 52.405 ;
     RECT  49.488 51.781 52.296 52.451 ;
     RECT  18.24 51.205 18.912 52.499 ;
     RECT  23.232 52.165 24.312 52.739 ;
     RECT  50.064 52.451 52.296 52.739 ;
     RECT  2.304 52.165 2.712 52.933 ;
     RECT  61.632 51.155 62.112 52.933 ;
     RECT  72.288 49.525 73.8 52.981 ;
     RECT  61.584 52.933 62.112 53.075 ;
     RECT  64.992 51.685 67.512 53.123 ;
     RECT  72.24 52.981 73.8 53.123 ;
     RECT  64.992 53.123 65.544 53.171 ;
     RECT  9.36 52.405 9.384 53.219 ;
     RECT  77.52 51.923 78.312 53.267 ;
     RECT  81.648 51.923 81.672 53.555 ;
     RECT  70.416 49.667 70.968 53.557 ;
     RECT  47.088 51.923 47.592 53.603 ;
     RECT  43.632 51.923 44.424 53.845 ;
     RECT  34.8 52.309 36.888 53.893 ;
     RECT  34.704 53.893 36.888 54.083 ;
     RECT  18.6 52.499 18.912 54.085 ;
     RECT  24 52.739 24.312 54.085 ;
     RECT  61.68 53.075 62.112 54.085 ;
     RECT  69.072 47.075 69.096 54.085 ;
     RECT  70.416 53.557 71.112 54.085 ;
     RECT  72.288 53.123 73.8 54.085 ;
     RECT  27.696 53.653 27.72 54.277 ;
     RECT  80.544 51.923 80.568 54.277 ;
     RECT  80.4 54.277 80.568 54.323 ;
     RECT  43.632 53.845 44.472 54.419 ;
     RECT  69.072 54.085 71.112 54.419 ;
     RECT  80.4 54.323 80.424 54.419 ;
     RECT  54.624 50.771 56.712 54.421 ;
     RECT  42.288 52.211 42.312 54.517 ;
     RECT  45.6 51.923 45.912 54.565 ;
     RECT  27.696 54.277 28.104 54.659 ;
     RECT  50.064 52.739 51.312 54.659 ;
     RECT  6.576 54.565 6.6 54.707 ;
     RECT  4.56 51.923 4.584 54.755 ;
     RECT  24 54.085 24.408 54.755 ;
     RECT  48.672 53.509 48.696 54.755 ;
     RECT  39.456 51.395 40.68 54.803 ;
     RECT  13.2 52.403 14.424 54.853 ;
     RECT  54.624 54.421 57.048 54.901 ;
     RECT  61.68 54.085 62.472 55.187 ;
     RECT  28.08 54.659 28.104 55.235 ;
     RECT  45.12 54.565 45.912 55.237 ;
     RECT  72.288 54.085 74.568 55.331 ;
     RECT  43.632 54.419 43.656 55.429 ;
     RECT  45.12 55.237 46.776 55.429 ;
     RECT  29.28 52.405 33.336 55.667 ;
     RECT  69.504 54.419 71.112 55.667 ;
     RECT  69.504 55.667 70.968 55.715 ;
     RECT  7.8 51.395 8.112 55.813 ;
     RECT  9.744 53.509 9.768 55.813 ;
     RECT  42.288 54.517 42.456 55.813 ;
     RECT  76.464 54.373 76.488 55.813 ;
     RECT  7.8 55.813 9.768 55.859 ;
     RECT  12 53.941 12.024 55.859 ;
     RECT  18.24 54.085 18.912 55.859 ;
     RECT  24 54.755 24.312 55.861 ;
     RECT  22.176 54.709 22.2 55.907 ;
     RECT  75.84 55.813 76.488 55.907 ;
     RECT  13.2 54.853 14.808 55.955 ;
     RECT  29.28 55.667 32.76 56.003 ;
     RECT  68.976 55.813 69.384 56.003 ;
     RECT  20.928 51.251 20.952 56.149 ;
     RECT  42.144 55.813 42.456 56.149 ;
     RECT  43.632 55.429 46.776 56.149 ;
     RECT  34.8 54.083 36.888 56.197 ;
     RECT  39.456 54.803 40.512 56.245 ;
     RECT  34.8 56.197 37.08 56.339 ;
     RECT  42.144 56.149 46.776 56.339 ;
     RECT  61.68 55.187 62.112 56.341 ;
     RECT  7.8 55.859 9 56.387 ;
     RECT  39.456 56.245 40.632 56.387 ;
     RECT  20.832 56.149 20.952 56.435 ;
     RECT  45.6 56.339 46.776 56.869 ;
     RECT  83.4 38.243 83.712 56.869 ;
     RECT  42.144 56.339 44.472 56.915 ;
     RECT  16.992 51.347 17.016 56.917 ;
     RECT  13.2 55.955 14.424 57.013 ;
     RECT  2.304 52.933 2.856 57.059 ;
     RECT  16.992 56.917 17.112 57.059 ;
     RECT  34.8 56.339 37.032 57.059 ;
     RECT  45.6 56.869 47.112 57.059 ;
     RECT  79.872 56.389 79.896 57.059 ;
     RECT  13.2 57.013 14.712 57.155 ;
     RECT  75.84 55.907 75.864 57.155 ;
     RECT  78 53.267 78.312 57.205 ;
     RECT  54.624 54.901 57.192 57.443 ;
     RECT  2.4 57.059 2.856 57.445 ;
     RECT  72.288 55.331 73.8 57.493 ;
     RECT  67.2 53.123 67.512 57.541 ;
     RECT  70.416 55.715 70.968 57.541 ;
     RECT  72.288 57.493 74.136 57.541 ;
     RECT  69.36 56.003 69.384 57.587 ;
     RECT  24 55.861 24.408 57.635 ;
     RECT  26.208 55.717 26.232 57.635 ;
     RECT  34.8 57.059 36.072 57.637 ;
     RECT  32.352 56.003 32.76 57.685 ;
     RECT  29.28 56.003 31.128 57.733 ;
     RECT  29.232 57.733 31.128 57.781 ;
     RECT  32.352 57.685 33.048 57.781 ;
     RECT  78 57.205 78.408 57.781 ;
     RECT  29.232 57.781 33.048 57.827 ;
     RECT  18.432 55.859 18.912 57.923 ;
     RECT  77.904 57.781 78.408 57.971 ;
     RECT  42.288 56.915 43.656 58.067 ;
     RECT  29.232 57.827 32.376 58.069 ;
     RECT  82.656 56.869 83.712 58.115 ;
     RECT  29.184 58.069 32.376 58.117 ;
     RECT  39.456 56.387 40.512 58.117 ;
     RECT  45.6 57.059 45.912 58.213 ;
     RECT  47.088 57.059 47.112 58.213 ;
     RECT  61.584 56.341 62.112 58.451 ;
     RECT  34.704 57.637 36.072 58.453 ;
     RECT  43.632 58.067 43.656 58.499 ;
     RECT  48.912 57.685 48.936 58.499 ;
     RECT  16.992 57.059 17.016 58.597 ;
     RECT  70.416 57.541 74.136 58.643 ;
     RECT  7.8 56.387 8.112 58.645 ;
     RECT  28.224 58.117 32.376 58.645 ;
     RECT  39.456 58.117 40.776 58.645 ;
     RECT  50.544 54.659 51.312 58.645 ;
     RECT  67.2 57.541 67.848 58.691 ;
     RECT  72.288 58.643 74.136 58.691 ;
     RECT  58.128 58.117 58.152 58.693 ;
     RECT  34.56 58.453 36.072 59.029 ;
     RECT  16.992 58.597 17.064 59.077 ;
     RECT  21.504 58.117 21.528 59.171 ;
     RECT  81.408 57.541 81.432 59.171 ;
     RECT  64.992 53.171 65.016 59.173 ;
     RECT  70.416 58.643 70.968 59.221 ;
     RECT  27.456 58.645 32.376 59.365 ;
     RECT  33.888 59.029 36.072 59.365 ;
     RECT  69.504 59.221 70.968 59.411 ;
     RECT  27.456 59.365 36.072 59.459 ;
     RECT  67.2 58.691 67.512 59.509 ;
     RECT  34.56 59.459 36.072 59.557 ;
     RECT  39.12 58.645 40.776 59.557 ;
     RECT  69.504 59.411 69.528 59.605 ;
     RECT  39.12 59.557 41.064 59.701 ;
     RECT  39.024 59.701 41.064 59.795 ;
     RECT  13.2 57.155 14.328 59.797 ;
     RECT  70.944 59.411 70.968 59.797 ;
     RECT  78 57.971 78.408 59.797 ;
     RECT  83.4 58.115 83.712 59.797 ;
     RECT  34.56 59.557 36.12 59.843 ;
     RECT  42.288 58.067 42.456 59.845 ;
     RECT  42.192 59.845 42.456 59.891 ;
     RECT  81.456 59.221 81.48 59.891 ;
     RECT  27.456 59.459 33.144 59.987 ;
     RECT  19.968 56.533 19.992 60.037 ;
     RECT  21.12 59.557 21.336 60.037 ;
     RECT  16.896 59.077 17.064 60.083 ;
     RECT  24 57.635 24.312 60.133 ;
     RECT  19.968 60.037 21.336 60.179 ;
     RECT  27.456 59.987 32.376 60.275 ;
     RECT  34.56 59.843 36.072 60.275 ;
     RECT  5.76 59.605 5.784 60.323 ;
     RECT  23.52 60.133 24.312 60.371 ;
     RECT  39.024 59.795 40.872 60.371 ;
     RECT  70.944 59.797 71.16 60.419 ;
     RECT  64.992 59.173 65.256 60.515 ;
     RECT  75.264 59.797 75.768 60.563 ;
     RECT  78 59.797 79.224 60.563 ;
     RECT  18.48 57.923 18.912 60.659 ;
     RECT  66.624 59.509 67.512 60.659 ;
     RECT  12.864 59.797 14.328 60.709 ;
     RECT  19.968 60.179 21.144 60.803 ;
     RECT  49.824 58.645 51.312 60.805 ;
     RECT  19.968 60.803 21.048 60.995 ;
     RECT  58.128 58.693 58.68 60.995 ;
     RECT  23.904 60.371 24.312 60.997 ;
     RECT  2.4 57.445 3.192 61.043 ;
     RECT  23.904 60.997 24.888 61.043 ;
     RECT  37.92 59.749 37.944 61.043 ;
     RECT  27.504 60.275 32.376 61.091 ;
     RECT  82.944 59.797 83.712 61.091 ;
     RECT  18.6 60.659 18.912 61.093 ;
     RECT  19.968 60.995 20.328 61.093 ;
     RECT  24 61.043 24.888 61.139 ;
     RECT  28.224 61.091 32.376 61.141 ;
     RECT  18.6 61.093 20.328 61.235 ;
     RECT  42.192 59.891 42.216 61.237 ;
     RECT  43.344 60.997 43.368 61.237 ;
     RECT  69.216 59.605 69.528 61.331 ;
     RECT  70.944 60.419 70.968 61.573 ;
     RECT  75.744 60.563 75.768 61.621 ;
     RECT  12.096 60.709 14.328 61.667 ;
     RECT  67.2 60.659 67.512 61.717 ;
     RECT  67.2 61.717 67.848 61.813 ;
     RECT  72.288 58.691 73.8 61.813 ;
     RECT  78 60.563 78.312 61.813 ;
     RECT  69.504 61.331 69.528 61.859 ;
     RECT  74.928 61.621 75.768 61.859 ;
     RECT  28.224 61.141 32.904 61.907 ;
     RECT  24 61.139 24.408 61.955 ;
     RECT  18.6 61.235 18.912 62.053 ;
     RECT  17.04 60.083 17.064 62.099 ;
     RECT  10.272 59.269 10.296 62.147 ;
     RECT  20.304 61.235 20.328 62.195 ;
     RECT  28.224 61.907 31.128 62.195 ;
     RECT  42.192 61.237 43.368 62.195 ;
     RECT  28.224 62.195 30.792 62.197 ;
     RECT  61.68 58.451 62.112 62.243 ;
     RECT  70.656 61.573 70.968 62.435 ;
     RECT  74.928 61.859 74.952 62.435 ;
     RECT  32.352 61.907 32.904 62.533 ;
     RECT  39.024 60.371 40.728 62.533 ;
     RECT  42.192 62.195 42.36 62.533 ;
     RECT  58.128 60.995 58.152 62.581 ;
     RECT  59.472 62.197 59.496 62.581 ;
     RECT  83.4 61.091 83.712 62.629 ;
     RECT  39.024 62.533 42.36 62.677 ;
     RECT  28.032 62.197 30.792 62.723 ;
     RECT  18.288 62.053 18.912 62.725 ;
     RECT  15.984 60.613 16.008 62.771 ;
     RECT  26.208 60.901 26.232 62.773 ;
     RECT  28.224 62.723 30.792 62.867 ;
     RECT  12.864 61.667 14.328 62.963 ;
     RECT  28.224 62.867 29.712 63.011 ;
     RECT  38.784 62.677 42.36 63.107 ;
     RECT  64.992 60.515 65.016 63.109 ;
     RECT  77.184 61.813 78.312 63.109 ;
     RECT  13.2 62.963 14.328 63.203 ;
     RECT  64.464 63.109 65.016 63.203 ;
     RECT  54.624 57.443 56.712 63.205 ;
     RECT  40.08 63.107 42.36 63.251 ;
     RECT  49.248 60.805 51.312 63.253 ;
     RECT  72 61.813 73.8 63.299 ;
     RECT  81.072 60.373 81.096 63.299 ;
     RECT  38.784 63.107 39.048 63.301 ;
     RECT  26.208 62.773 26.568 63.347 ;
     RECT  32.352 62.533 33.096 63.347 ;
     RECT  38.16 63.301 39.048 63.347 ;
     RECT  40.08 63.251 40.728 63.347 ;
     RECT  17.76 62.725 18.912 63.349 ;
     RECT  6.864 58.645 8.112 63.491 ;
     RECT  83.088 62.629 83.712 63.491 ;
     RECT  58.128 62.581 59.496 63.539 ;
     RECT  32.832 63.347 33.096 63.541 ;
     RECT  42.192 63.251 42.36 63.587 ;
     RECT  45.6 58.213 47.112 63.589 ;
     RECT  32.832 63.541 33.24 63.731 ;
     RECT  32.832 63.731 32.904 63.827 ;
     RECT  48.48 63.253 51.312 63.827 ;
     RECT  58.944 63.539 59.496 63.827 ;
     RECT  24 61.955 24.312 63.829 ;
     RECT  26.544 63.347 26.568 63.829 ;
     RECT  34.56 60.275 35.112 63.877 ;
     RECT  38.16 63.347 38.808 64.019 ;
     RECT  32.832 63.827 32.856 64.067 ;
     RECT  26.544 63.829 26.808 64.117 ;
     RECT  28.224 63.011 28.248 64.117 ;
     RECT  64.464 63.203 64.488 64.165 ;
     RECT  63.84 64.165 64.488 64.211 ;
     RECT  52.656 62.149 52.68 64.309 ;
     RECT  13.2 63.203 13.512 64.357 ;
     RECT  17.04 63.349 18.912 64.357 ;
     RECT  45.6 63.589 47.352 64.357 ;
     RECT  16.128 64.357 18.912 64.403 ;
     RECT  43.344 62.195 43.368 64.405 ;
     RECT  52.608 64.309 52.68 64.405 ;
     RECT  43.344 64.405 43.56 64.451 ;
     RECT  23.424 63.829 24.312 64.597 ;
     RECT  34.56 63.877 35.208 64.597 ;
     RECT  59.472 63.827 59.496 64.645 ;
     RECT  30.768 62.867 30.792 64.739 ;
     RECT  20.976 64.357 21 64.789 ;
     RECT  11.904 63.781 11.928 64.883 ;
     RECT  20.64 64.789 21 64.931 ;
     RECT  7.152 63.491 8.112 64.933 ;
     RECT  72.384 63.299 73.8 64.933 ;
     RECT  26.544 64.117 28.248 64.979 ;
     RECT  76.08 63.541 76.104 64.979 ;
     RECT  63.84 64.211 63.864 65.027 ;
     RECT  80.928 64.165 80.952 65.027 ;
     RECT  6.432 64.933 8.112 65.125 ;
     RECT  54.624 63.205 57.144 65.125 ;
     RECT  32.4 64.453 32.424 65.171 ;
     RECT  52.608 64.405 53.16 65.171 ;
     RECT  20.976 64.931 21 65.219 ;
     RECT  5.664 65.125 8.328 65.267 ;
     RECT  70.944 62.435 70.968 65.269 ;
     RECT  34.56 64.597 35.928 65.317 ;
     RECT  23.424 64.597 24.456 65.363 ;
     RECT  70.704 65.269 70.968 65.411 ;
     RECT  77.184 63.109 79.272 65.411 ;
     RECT  42.192 63.587 42.216 65.413 ;
     RECT  34.56 65.317 36.696 65.459 ;
     RECT  67.2 61.813 68.328 65.509 ;
     RECT  42 65.413 42.216 65.555 ;
     RECT  13.104 64.357 13.512 65.603 ;
     RECT  16.128 64.403 16.152 65.603 ;
     RECT  23.616 65.363 24.456 65.603 ;
     RECT  27.6 64.979 28.248 65.603 ;
     RECT  43.536 64.451 43.56 65.651 ;
     RECT  2.4 61.043 2.712 65.653 ;
     RECT  34.56 65.459 35.928 65.747 ;
     RECT  72.048 64.933 73.8 65.893 ;
     RECT  54.624 65.125 57.24 65.939 ;
     RECT  71.952 65.893 73.8 65.939 ;
     RECT  29.4 63.011 29.712 66.085 ;
     RECT  30.72 65.797 30.744 66.085 ;
     RECT  49.248 63.827 51.312 66.085 ;
     RECT  52.608 65.171 52.632 66.085 ;
     RECT  54.624 65.939 57.144 66.085 ;
     RECT  77.184 65.411 78.312 66.085 ;
     RECT  17.76 64.403 18.912 66.179 ;
     RECT  6.432 65.267 8.112 66.227 ;
     RECT  59.472 64.645 59.688 66.227 ;
     RECT  42.192 65.555 42.216 66.275 ;
     RECT  24 65.603 24.456 66.323 ;
     RECT  2.304 65.653 2.712 66.419 ;
     RECT  76.944 66.085 78.312 66.421 ;
     RECT  34.56 65.747 35.88 66.517 ;
     RECT  0.144 66.277 0.168 66.563 ;
     RECT  76.944 66.421 78.936 66.659 ;
     RECT  83.4 63.491 83.712 66.661 ;
     RECT  11.904 66.085 11.928 66.755 ;
     RECT  45.6 64.357 47.592 66.803 ;
     RECT  7.152 66.227 8.112 66.899 ;
     RECT  40.2 63.347 40.728 67.043 ;
     RECT  49.248 66.085 52.632 67.093 ;
     RECT  61.8 62.243 62.112 67.141 ;
     RECT  5.088 65.797 5.112 67.283 ;
     RECT  26.544 64.979 26.568 67.285 ;
     RECT  27.6 65.603 28.056 67.285 ;
     RECT  34.464 66.517 35.88 67.285 ;
     RECT  54.144 66.085 57.144 67.285 ;
     RECT  19.92 66.709 19.944 67.331 ;
     RECT  54.144 67.285 57.72 67.331 ;
     RECT  49.248 67.093 52.92 67.427 ;
     RECT  42 66.661 42.024 67.429 ;
     RECT  49.248 67.427 52.44 67.571 ;
     RECT  66.672 65.509 68.328 67.571 ;
     RECT  26.544 67.285 28.056 67.667 ;
     RECT  29.4 66.085 30.744 67.715 ;
     RECT  71.952 65.939 72.912 67.715 ;
     RECT  83.088 66.661 83.712 67.717 ;
     RECT  13.2 65.603 13.512 67.765 ;
     RECT  18 66.179 18.912 67.765 ;
     RECT  47.088 66.803 47.592 67.765 ;
     RECT  24 66.323 24.312 67.813 ;
     RECT  26.544 67.667 27.624 67.813 ;
     RECT  9.408 66.613 9.432 67.859 ;
     RECT  33.12 67.333 33.144 67.907 ;
     RECT  34.464 67.285 36.168 68.003 ;
     RECT  64.368 66.661 64.392 68.053 ;
     RECT  36.144 68.003 36.168 68.147 ;
     RECT  76.944 66.659 78.456 68.147 ;
     RECT  24 67.813 24.456 68.195 ;
     RECT  70.944 65.411 70.968 68.197 ;
     RECT  75.36 67.717 75.384 68.197 ;
     RECT  75.36 68.197 75.816 68.243 ;
     RECT  54.624 67.331 57.72 68.341 ;
     RECT  81.456 66.949 81.48 68.341 ;
     RECT  41.664 67.429 42.024 68.387 ;
     RECT  66.672 67.571 68.088 68.437 ;
     RECT  52.416 67.571 52.44 68.581 ;
     RECT  52.416 68.581 53.4 68.627 ;
     RECT  29.4 67.715 29.712 68.629 ;
     RECT  49.248 67.571 51.312 68.675 ;
     RECT  64.32 68.053 64.392 68.675 ;
     RECT  76.944 68.147 78.312 68.677 ;
     RECT  66.144 68.437 68.088 68.771 ;
     RECT  75.792 68.243 75.816 68.771 ;
     RECT  54.624 68.341 58.488 68.867 ;
     RECT  17.184 67.765 18.912 68.869 ;
     RECT  42 68.387 42.024 68.915 ;
     RECT  2.4 66.419 2.712 68.917 ;
     RECT  4.08 66.085 4.104 68.917 ;
     RECT  49.248 68.675 49.704 68.917 ;
     RECT  61.8 67.141 62.664 68.917 ;
     RECT  47.088 67.765 48.024 68.963 ;
     RECT  59.472 66.227 59.496 68.963 ;
     RECT  29.28 68.629 29.712 68.965 ;
     RECT  45.6 66.803 45.912 68.965 ;
     RECT  17.088 68.869 18.912 69.011 ;
     RECT  55.008 68.867 58.488 69.011 ;
     RECT  53.376 68.627 53.4 69.059 ;
     RECT  45.12 68.965 45.912 69.107 ;
     RECT  82.656 67.717 83.712 69.155 ;
     RECT  38.16 64.019 38.472 69.157 ;
     RECT  25.824 67.813 27.624 69.203 ;
     RECT  70.944 68.197 71.256 69.301 ;
     RECT  55.008 69.011 57.72 69.443 ;
     RECT  21.696 68.341 21.72 69.491 ;
     RECT  76.896 68.677 78.312 69.491 ;
     RECT  0.144 69.253 0.168 69.539 ;
     RECT  49.008 68.917 49.704 69.539 ;
     RECT  2.4 68.917 4.104 69.541 ;
     RECT  24 68.195 24.408 69.541 ;
     RECT  25.824 69.203 25.848 69.541 ;
     RECT  30.72 67.715 30.744 69.587 ;
     RECT  47.088 68.963 47.784 69.587 ;
     RECT  64.32 68.675 64.344 69.587 ;
     RECT  24 69.541 25.848 69.635 ;
     RECT  29.232 68.965 29.712 69.875 ;
     RECT  34.464 68.003 35.112 69.877 ;
     RECT  12.528 67.765 13.512 69.971 ;
     RECT  55.008 69.443 57.144 70.019 ;
     RECT  74.112 67.717 74.136 70.019 ;
     RECT  29.28 69.875 29.712 70.069 ;
     RECT  55.008 70.019 55.032 70.115 ;
     RECT  66.144 68.771 66.168 70.117 ;
     RECT  67.2 68.771 68.088 70.117 ;
     RECT  66.144 70.117 68.088 70.163 ;
     RECT  70.704 69.301 71.256 70.211 ;
     RECT  47.568 69.587 47.784 70.259 ;
     RECT  61.8 68.917 62.808 70.259 ;
     RECT  6 70.021 6.024 70.261 ;
     RECT  7.392 66.899 8.112 70.261 ;
     RECT  15.312 69.349 15.336 70.261 ;
     RECT  34.464 69.877 35.784 70.261 ;
     RECT  80.688 68.341 81.48 70.307 ;
     RECT  40.2 67.043 40.632 70.309 ;
     RECT  38.016 69.157 38.472 70.403 ;
     RECT  47.568 70.259 47.592 70.547 ;
     RECT  80.688 70.307 81.288 70.597 ;
     RECT  0.192 70.453 0.216 70.643 ;
     RECT  18 69.011 18.912 70.691 ;
     RECT  6 70.261 8.112 70.739 ;
     RECT  49.536 69.539 49.704 70.739 ;
     RECT  2.4 69.541 4.728 70.789 ;
     RECT  18.192 70.691 18.912 70.835 ;
     RECT  61.8 70.259 62.28 70.835 ;
     RECT  66.672 70.163 68.088 70.835 ;
     RECT  69.408 66.037 69.432 70.835 ;
     RECT  70.704 70.211 71.016 70.835 ;
     RECT  2.4 70.789 4.776 70.931 ;
     RECT  29.28 70.069 29.976 70.933 ;
     RECT  40.2 70.309 41.544 71.075 ;
     RECT  60.384 70.069 60.408 71.077 ;
     RECT  60.384 71.077 60.648 71.123 ;
     RECT  43.488 68.341 43.512 71.173 ;
     RECT  27.6 69.203 27.624 71.221 ;
     RECT  34.464 70.261 36.024 71.221 ;
     RECT  70.704 70.835 70.728 71.221 ;
     RECT  20.544 70.549 20.568 71.315 ;
     RECT  52.704 69.733 52.728 71.315 ;
     RECT  65.232 70.789 65.256 71.317 ;
     RECT  6.384 70.739 8.112 71.459 ;
     RECT  51 68.675 51.312 71.461 ;
     RECT  29.28 70.933 30.888 71.557 ;
     RECT  34.368 71.221 36.024 71.557 ;
     RECT  24 69.635 25.752 71.603 ;
     RECT  27.264 71.221 27.624 71.605 ;
     RECT  80.64 70.597 81.288 71.605 ;
     RECT  43.488 71.173 44.28 71.747 ;
     RECT  74.064 71.317 74.088 71.747 ;
     RECT  6.384 71.459 6.408 71.749 ;
     RECT  80.4 71.605 81.288 71.797 ;
     RECT  29.232 71.557 30.888 71.843 ;
     RECT  70.512 71.221 70.728 71.843 ;
     RECT  72.384 67.715 72.912 71.843 ;
     RECT  69.072 70.933 69.096 71.845 ;
     RECT  27.264 71.605 28.056 71.891 ;
     RECT  32.496 70.261 32.52 71.941 ;
     RECT  32.496 71.941 32.904 71.987 ;
     RECT  15.168 70.261 15.336 72.035 ;
     RECT  18.6 70.835 18.912 72.037 ;
     RECT  38.016 70.403 38.04 72.037 ;
     RECT  64.416 71.317 65.256 72.037 ;
     RECT  66.672 70.835 67.848 72.037 ;
     RECT  69.024 71.845 69.096 72.085 ;
     RECT  15.168 72.035 15.192 72.131 ;
     RECT  34.272 71.557 36.024 72.179 ;
     RECT  49.536 70.739 49.56 72.181 ;
     RECT  34.272 72.179 35.784 72.229 ;
     RECT  40.2 71.075 41.064 72.275 ;
     RECT  69.024 72.085 69.192 72.325 ;
     RECT  2.4 70.931 4.728 72.419 ;
     RECT  27.6 71.891 28.056 72.419 ;
     RECT  43.488 71.747 43.512 72.419 ;
     RECT  47.664 71.221 47.688 72.419 ;
     RECT  69.024 72.325 69.432 72.421 ;
     RECT  28.032 72.419 28.056 72.467 ;
     RECT  50.88 71.461 51.312 72.467 ;
     RECT  56.4 70.019 57.144 72.467 ;
     RECT  29.232 71.843 30.744 72.515 ;
     RECT  76.08 70.645 76.104 72.515 ;
     RECT  72.6 71.843 72.912 72.517 ;
     RECT  9.648 71.221 9.672 72.563 ;
     RECT  70.704 71.843 70.728 72.563 ;
     RECT  34.224 72.229 35.784 72.659 ;
     RECT  38.016 72.037 38.76 72.659 ;
     RECT  80.4 71.797 81.384 72.707 ;
     RECT  32.88 71.987 32.904 72.755 ;
     RECT  68.976 72.421 69.432 72.805 ;
     RECT  83.4 69.155 83.712 72.805 ;
     RECT  7.392 71.459 8.112 72.851 ;
     RECT  25.728 71.603 25.752 72.851 ;
     RECT  64.416 72.037 67.848 72.901 ;
     RECT  68.976 72.805 69.96 72.901 ;
     RECT  3.744 72.419 4.728 72.947 ;
     RECT  29.232 72.515 30.024 72.949 ;
     RECT  5.76 71.749 6.408 72.995 ;
     RECT  64.416 72.901 69.96 72.995 ;
     RECT  31.872 72.901 31.896 73.043 ;
     RECT  80.4 72.707 80.664 73.043 ;
     RECT  34.224 72.659 35.688 73.235 ;
     RECT  15.648 73.189 15.672 73.237 ;
     RECT  16.944 72.229 16.968 73.237 ;
     RECT  15.648 73.237 16.968 73.283 ;
     RECT  48.768 72.181 49.56 73.283 ;
     RECT  0.144 73.045 0.168 73.331 ;
     RECT  7.8 72.851 8.112 73.477 ;
     RECT  43.872 72.901 43.896 73.477 ;
     RECT  43.344 73.477 43.896 73.523 ;
     RECT  72.6 72.517 73.224 73.523 ;
     RECT  15.648 73.283 16.008 73.571 ;
     RECT  66.672 72.995 69.96 73.571 ;
     RECT  80.64 73.043 80.664 73.571 ;
     RECT  28.464 72.949 30.024 73.715 ;
     RECT  45.6 69.107 45.912 73.765 ;
     RECT  49.392 73.283 49.56 73.811 ;
     RECT  67.2 73.571 69.96 73.811 ;
     RECT  18.6 72.037 19.416 73.813 ;
     RECT  38.736 72.659 38.76 73.859 ;
     RECT  40.2 72.275 40.512 73.861 ;
     RECT  29.232 73.715 30.024 74.003 ;
     RECT  82.656 72.805 83.712 74.051 ;
     RECT  7.8 73.477 8.568 74.053 ;
     RECT  77.136 69.491 78.312 74.053 ;
     RECT  3.744 72.947 3.96 74.147 ;
     RECT  60.624 71.123 60.648 74.147 ;
     RECT  7.104 74.053 8.568 74.149 ;
     RECT  49.536 73.811 49.56 74.339 ;
     RECT  79.392 74.053 79.416 74.339 ;
     RECT  75.072 73.477 75.096 74.483 ;
     RECT  40.032 73.861 40.512 74.581 ;
     RECT  22.464 72.901 22.488 74.629 ;
     RECT  77.136 74.053 78.408 74.675 ;
     RECT  3.936 74.147 3.96 74.723 ;
     RECT  27.984 74.101 28.008 74.723 ;
     RECT  29.232 74.003 29.832 74.723 ;
     RECT  43.344 73.523 43.368 74.723 ;
     RECT  65.232 72.995 65.256 74.723 ;
     RECT  5.76 72.995 5.784 74.867 ;
     RECT  15.984 73.571 16.008 74.867 ;
     RECT  29.4 74.723 29.832 75.061 ;
     RECT  29.4 75.061 30.168 75.203 ;
     RECT  7.104 74.149 9.096 75.251 ;
     RECT  18.6 73.813 19.464 75.251 ;
     RECT  34.8 73.235 35.688 75.299 ;
     RECT  41.664 72.997 41.688 75.299 ;
     RECT  74.064 74.629 74.088 75.299 ;
     RECT  7.104 75.251 8.112 75.395 ;
     RECT  21.648 74.629 22.488 75.395 ;
     RECT  39.552 74.581 40.512 75.395 ;
     RECT  22.464 75.395 22.488 75.443 ;
     RECT  25.68 74.581 25.704 75.443 ;
     RECT  29.4 75.203 29.832 75.443 ;
     RECT  45.024 73.765 45.912 75.443 ;
     RECT  2.4 72.419 2.712 75.609 ;
     RECT  7.8 75.395 8.112 75.609 ;
     RECT  13.2 69.971 13.512 75.609 ;
     RECT  18.6 75.251 18.912 75.609 ;
     RECT  24 71.603 24.312 75.609 ;
     RECT  29.4 75.443 29.712 75.609 ;
     RECT  34.8 75.299 35.112 75.609 ;
     RECT  40.2 75.395 40.512 75.609 ;
     RECT  45.6 75.443 45.912 75.609 ;
     RECT  51 72.467 51.312 75.609 ;
     RECT  56.4 72.467 56.712 75.609 ;
     RECT  61.8 70.835 62.112 75.609 ;
     RECT  72.6 73.523 72.912 75.609 ;
     RECT  83.4 74.051 83.712 75.609 ;
     RECT  2.4 75.609 2.52 75.623 ;
     RECT  7.8 75.609 7.92 75.623 ;
     RECT  13.2 75.609 13.32 75.623 ;
     RECT  18.6 75.609 18.72 75.623 ;
     RECT  24 75.609 24.12 75.623 ;
     RECT  29.4 75.609 29.52 75.623 ;
     RECT  34.8 75.609 34.92 75.623 ;
     RECT  40.2 75.609 40.32 75.623 ;
     RECT  45.6 75.609 45.72 75.623 ;
     RECT  51 75.609 51.12 75.623 ;
     RECT  56.4 75.609 56.52 75.623 ;
     RECT  61.8 75.609 61.92 75.623 ;
     RECT  67.2 73.811 67.512 75.623 ;
     RECT  72.6 75.609 72.72 75.623 ;
     RECT  83.4 75.609 83.52 75.623 ;
     RECT  77.376 74.675 78.408 75.637 ;
     RECT  68.88 73.811 69.96 75.781 ;
     RECT  77.376 75.637 79.176 75.781 ;
     RECT  68.592 75.781 70.056 76.357 ;
     RECT  76.848 75.781 79.464 76.357 ;
     RECT  68.208 76.357 70.056 76.885 ;
     RECT  68.112 76.885 70.056 76.933 ;
     RECT  68.112 76.933 70.152 77.557 ;
     RECT  68.016 77.557 70.248 77.605 ;
     RECT  67.92 77.605 70.248 77.712 ;
     RECT  76.464 76.357 79.464 77.712 ;
     RECT  63.432 1.907 63.816 3.301 ;
     RECT  2.712 2.245 3.696 3.443 ;
     RECT  58.056 2.245 59.184 2.915 ;
     RECT  66.072 2.245 67.2 2.821 ;
     RECT  8.616 2.291 9.648 4.691 ;
     RECT  24.312 2.485 25.68 5.269 ;
     RECT  18.912 2.629 19.968 7.331 ;
     RECT  45.912 2.821 46.944 5.365 ;
     RECT  66.12 2.821 67.2 3.587 ;
     RECT  57.48 2.915 59.184 3.011 ;
     RECT  57.48 3.011 59.016 3.877 ;
     RECT  67.512 3.059 67.608 4.117 ;
     RECT  63.432 3.301 64.944 3.349 ;
     RECT  64.968 3.301 66.048 3.349 ;
     RECT  63.432 3.349 64.848 3.443 ;
     RECT  2.712 3.443 2.904 3.685 ;
     RECT  64.512 3.443 64.848 4.885 ;
     RECT  65.496 3.587 67.2 3.829 ;
     RECT  52.584 3.683 53.904 4.019 ;
     RECT  65.496 3.829 66.672 4.789 ;
     RECT  57.48 3.877 58.56 3.925 ;
     RECT  6.168 4.069 7.632 5.171 ;
     RECT  67.512 4.117 69.024 4.307 ;
     RECT  69.048 4.117 70.128 4.307 ;
     RECT  35.112 4.307 35.304 4.501 ;
     RECT  67.512 4.307 67.704 4.837 ;
     RECT  18.192 4.451 18.6 4.501 ;
     RECT  61.68 4.451 61.8 5.173 ;
     RECT  73.848 4.453 75.264 6.181 ;
     RECT  17.352 4.501 18.6 8.533 ;
     RECT  35.112 4.501 36.48 6.275 ;
     RECT  30.024 4.595 30.168 5.941 ;
     RECT  8.112 4.691 9.648 5.171 ;
     RECT  65.544 4.789 66.672 5.077 ;
     RECT  19.992 4.981 21.168 5.123 ;
     RECT  65.544 5.077 66.624 6.133 ;
     RECT  19.992 5.123 21.096 6.613 ;
     RECT  6.24 5.171 7.632 5.461 ;
     RECT  8.112 5.171 8.52 6.181 ;
     RECT  29.088 5.171 29.4 6.229 ;
     RECT  43.176 5.171 44.352 5.747 ;
     RECT  59.352 5.173 60.576 5.315 ;
     RECT  60.6 5.173 61.8 5.315 ;
     RECT  59.352 5.315 61.8 5.317 ;
     RECT  59.352 5.317 60.672 6.131 ;
     RECT  60.696 5.317 61.8 6.277 ;
     RECT  6.264 5.461 7.632 6.037 ;
     RECT  24.312 5.507 25.68 5.891 ;
     RECT  47.928 5.653 49.344 5.747 ;
     RECT  47.928 5.747 49.488 7.045 ;
     RECT  24.312 5.891 24.936 7.381 ;
     RECT  6.504 6.037 7.632 6.323 ;
     RECT  59.016 6.131 60.672 7.189 ;
     RECT  65.64 6.133 66.624 7.331 ;
     RECT  76.344 6.229 77.76 7.237 ;
     RECT  33.528 6.277 34.8 7.381 ;
     RECT  6.504 6.323 7.8 6.661 ;
     RECT  19.992 6.613 21.072 7.331 ;
     RECT  30.456 6.659 30.888 6.853 ;
     RECT  6.6 6.661 7.8 8.917 ;
     RECT  82.008 6.805 83.4 7.283 ;
     RECT  30.456 6.853 31.872 7.379 ;
     RECT  8.112 6.899 9.216 8.339 ;
     RECT  9.24 6.901 10.32 7.573 ;
     RECT  10.344 6.901 11.664 7.141 ;
     RECT  47.928 7.045 49.392 7.333 ;
     RECT  68.376 7.093 69.504 7.379 ;
     RECT  10.392 7.141 11.664 7.187 ;
     RECT  10.392 7.187 11.76 7.573 ;
     RECT  59.256 7.189 60.672 7.237 ;
     RECT  59.256 7.237 60.288 7.669 ;
     RECT  76.344 7.237 77.424 7.907 ;
     RECT  21.024 7.331 21.072 7.571 ;
     RECT  65.496 7.331 66.624 9.155 ;
     RECT  52.632 7.333 53.952 7.429 ;
     RECT  30.168 7.379 31.872 7.477 ;
     RECT  68.376 7.379 70.224 8.437 ;
     RECT  73.848 7.379 74.928 11.749 ;
     RECT  52.632 7.429 53.904 7.909 ;
     RECT  47.352 7.475 48.432 9.061 ;
     RECT  30.168 7.477 31.824 8.195 ;
     RECT  21.024 7.571 21.096 7.765 ;
     RECT  10.68 7.573 11.76 7.859 ;
     RECT  62.808 7.573 64.08 8.485 ;
     RECT  16.944 7.763 17.328 9.109 ;
     RECT  21.048 7.765 21.096 9.061 ;
     RECT  10.344 7.859 11.76 8.147 ;
     RECT  4.632 8.101 6.096 8.677 ;
     RECT  10.248 8.147 11.76 8.149 ;
     RECT  10.248 8.149 11.664 8.293 ;
     RECT  30.12 8.195 31.824 8.389 ;
     RECT  10.248 8.293 11.424 8.963 ;
     RECT  8.112 8.339 9.504 8.485 ;
     RECT  30.12 8.389 31.44 8.533 ;
     RECT  71.808 8.435 72.288 9.107 ;
     RECT  68.376 8.437 69.696 9.731 ;
     RECT  8.232 8.485 9.504 9.299 ;
     RECT  30.12 8.533 31.344 9.251 ;
     RECT  33.528 8.723 34.8 8.963 ;
     RECT  4.728 8.915 6.096 9.443 ;
     RECT  33.336 8.963 34.8 9.107 ;
     RECT  48.168 9.107 49.344 9.731 ;
     RECT  71.808 9.107 72.384 9.155 ;
     RECT  65.4 9.155 66.624 9.733 ;
     RECT  71.808 9.155 72.432 9.829 ;
     RECT  18.912 9.157 20.208 9.493 ;
     RECT  30.12 9.251 31.872 9.253 ;
     RECT  30.552 9.253 31.872 10.067 ;
     RECT  8.232 9.299 9.192 9.925 ;
     RECT  47.16 9.347 48.144 9.731 ;
     RECT  80.52 9.349 81.84 10.931 ;
     RECT  4.632 9.443 6.096 9.925 ;
     RECT  35.112 9.541 36.432 10.981 ;
     RECT  41.208 9.589 42.384 11.171 ;
     RECT  47.16 9.731 49.344 10.453 ;
     RECT  69.504 9.731 69.696 10.213 ;
     RECT  65.4 9.733 66.384 11.123 ;
     RECT  71.352 9.829 72.432 11.507 ;
     RECT  4.632 9.925 5.616 10.549 ;
     RECT  21.576 9.925 22.944 10.883 ;
     RECT  62.808 10.019 64.08 12.421 ;
     RECT  20.52 10.115 21.552 10.883 ;
     RECT  42.936 10.165 44.352 12.901 ;
     RECT  8.112 10.259 9.168 11.267 ;
     RECT  47.928 10.453 49.344 10.837 ;
     RECT  79.848 10.931 81.84 11.365 ;
     RECT  47.928 10.979 49.344 12.517 ;
     RECT  35.256 10.981 36.432 12.035 ;
     RECT  17.352 11.123 18.6 11.315 ;
     RECT  65.4 11.123 66.624 12.803 ;
     RECT  17.16 11.315 18.6 13.429 ;
     RECT  79.848 11.365 81.36 11.459 ;
     RECT  82.008 11.413 83.4 17.603 ;
     RECT  46.728 11.459 47.808 12.467 ;
     RECT  79.032 11.459 81.36 12.565 ;
     RECT  71.304 11.507 72.432 12.563 ;
     RECT  31.896 12.035 32.568 12.757 ;
     RECT  35.256 12.035 35.784 13.045 ;
     RECT  46.68 12.467 47.808 14.147 ;
     RECT  37.992 12.517 39.36 12.995 ;
     RECT  70.968 12.563 72.432 15.253 ;
     RECT  79.992 12.565 81.36 13.283 ;
     RECT  14.232 12.709 15.744 12.901 ;
     RECT  15.768 12.709 17.136 13.093 ;
     RECT  31.896 12.757 32.976 12.803 ;
     RECT  33 12.757 34.224 13.477 ;
     RECT  31.872 12.803 32.976 13.621 ;
     RECT  65.304 12.803 66.624 15.349 ;
     RECT  42.936 12.901 44.304 13.619 ;
     RECT  16.056 13.093 17.136 16.787 ;
     RECT  63.288 13.139 64.992 14.149 ;
     RECT  14.856 13.235 16.032 14.965 ;
     RECT  17.208 13.429 18.6 16.787 ;
     RECT  33.048 13.477 34.224 14.387 ;
     RECT  42.936 13.619 44.352 14.869 ;
     RECT  31.656 13.621 32.976 14.341 ;
     RECT  41.64 13.621 42.912 14.291 ;
     RECT  35.784 13.669 37.056 14.389 ;
     RECT  11.544 13.859 12.528 14.003 ;
     RECT  44.376 13.859 45.6 19.477 ;
     RECT  11.808 14.003 12.528 15.349 ;
     RECT  46.68 14.147 48.048 15.395 ;
     RECT  63.528 14.149 64.992 15.541 ;
     RECT  48.36 14.243 49.344 16.357 ;
     RECT  8.664 14.291 9.648 14.339 ;
     RECT  8.112 14.339 9.432 15.829 ;
     RECT  33 14.387 34.224 15.491 ;
     RECT  35.784 14.389 37.008 15.397 ;
     RECT  19.56 14.435 20.544 16.933 ;
     RECT  79.032 14.675 79.992 15.973 ;
     RECT  43.272 14.869 44.352 15.107 ;
     RECT  43.128 15.107 44.352 15.539 ;
     RECT  70.968 15.253 72.384 27.205 ;
     RECT  46.68 15.395 48.336 16.501 ;
     RECT  32.568 15.491 34.224 16.501 ;
     RECT  42.936 15.539 44.352 17.555 ;
     RECT  63.528 15.541 64.944 16.019 ;
     RECT  8.112 15.829 9.408 16.787 ;
     RECT  11.808 15.923 12.576 16.501 ;
     RECT  79.032 15.973 80.352 17.651 ;
     RECT  2.856 16.019 3.048 17.077 ;
     RECT  63.528 16.019 64.992 17.605 ;
     RECT  11.448 16.501 12.576 17.077 ;
     RECT  32.568 16.501 33.888 16.981 ;
     RECT  51.48 16.501 52.896 16.933 ;
     RECT  52.92 16.501 54 17.029 ;
     RECT  60.696 16.595 61.8 18.517 ;
     RECT  47.448 16.691 48.528 18.563 ;
     RECT  16.056 16.787 18.6 17.029 ;
     RECT  27.912 16.789 29.4 19.381 ;
     RECT  59.016 16.835 60.192 18.805 ;
     RECT  16.056 17.029 17.088 17.507 ;
     RECT  17.112 17.029 18.6 17.507 ;
     RECT  3.24 17.077 4.608 17.605 ;
     RECT  11.592 17.077 12.576 18.371 ;
     RECT  16.056 17.507 16.776 18.037 ;
     RECT  42.912 17.555 44.352 17.653 ;
     RECT  3.432 17.605 4.608 18.563 ;
     RECT  42.912 17.653 43.104 18.709 ;
     RECT  43.128 17.653 44.352 18.755 ;
     RECT  19.56 17.987 20.544 21.397 ;
     RECT  25.272 17.987 25.944 19.237 ;
     RECT  74.952 18.133 76.368 18.805 ;
     RECT  56.856 18.275 57.888 26.725 ;
     RECT  11.448 18.371 12.576 21.733 ;
     RECT  32.28 18.371 33.264 19.909 ;
     RECT  52.584 18.419 54 18.467 ;
     RECT  52.584 18.467 54.288 19.813 ;
     RECT  60.696 18.517 61.68 20.197 ;
     RECT  62.808 18.755 64.176 18.851 ;
     RECT  59.112 18.805 60.192 20.293 ;
     RECT  74.952 18.805 76.032 20.003 ;
     RECT  51.48 19.379 52.56 23.605 ;
     RECT  44.376 19.477 45.36 20.051 ;
     RECT  44.376 20.051 45.6 22.453 ;
     RECT  30.12 20.147 31.632 21.683 ;
     RECT  59.112 20.293 60.096 20.725 ;
     RECT  22.896 20.531 23.328 21.301 ;
     RECT  65.016 20.867 66.048 22.693 ;
     RECT  80.88 21.107 80.904 21.157 ;
     RECT  4.848 21.155 5.136 22.549 ;
     RECT  62.808 21.157 63.84 22.835 ;
     RECT  63.864 21.157 64.992 22.835 ;
     RECT  79.656 21.157 80.904 21.397 ;
     RECT  78.312 21.203 79.632 22.787 ;
     RECT  22.344 21.301 23.328 21.491 ;
     RECT  79.656 21.397 81.072 22.787 ;
     RECT  22.32 21.491 23.328 21.589 ;
     RECT  22.296 21.589 23.328 22.597 ;
     RECT  47.832 21.637 49.248 26.243 ;
     RECT  31.296 21.683 31.632 22.165 ;
     RECT  11.448 21.875 12.576 23.365 ;
     RECT  74.952 21.925 75.936 22.499 ;
     RECT  46.104 22.067 47.184 22.259 ;
     RECT  27.384 22.211 27.432 22.693 ;
     RECT  46.008 22.259 47.184 22.307 ;
     RECT  44.568 22.453 45.6 23.845 ;
     RECT  27.384 22.693 28.704 22.883 ;
     RECT  78.312 22.787 78.6 23.317 ;
     RECT  80.88 22.787 81.072 23.555 ;
     RECT  27.384 22.883 29.088 23.893 ;
     RECT  38.472 23.125 39.792 25.139 ;
     RECT  6.024 23.365 7.248 24.419 ;
     RECT  80.88 23.555 80.904 23.893 ;
     RECT  9.864 23.651 11.136 24.083 ;
     RECT  35.784 23.939 36.024 25.141 ;
     RECT  27.36 23.987 27.936 25.043 ;
     RECT  28.2 23.987 29.4 25.717 ;
     RECT  51.48 23.987 52.56 27.301 ;
     RECT  59.256 23.987 60.672 28.261 ;
     RECT  10.176 24.083 11.136 25.045 ;
     RECT  5.448 24.419 7.248 24.901 ;
     RECT  24.312 24.755 24.552 26.197 ;
     RECT  5.448 24.901 7.2 25.381 ;
     RECT  45.912 24.947 46.008 25.621 ;
     RECT  27.36 25.043 28.176 25.045 ;
     RECT  26.952 25.045 28.176 25.283 ;
     RECT  16.056 25.091 17.52 26.485 ;
     RECT  39.216 25.139 39.792 26.149 ;
     RECT  44.064 25.235 44.352 26.437 ;
     RECT  26.52 25.283 28.176 25.427 ;
     RECT  6.168 25.381 7.2 25.429 ;
     RECT  26.496 25.427 28.176 26.197 ;
     RECT  45.912 25.621 46.944 26.243 ;
     RECT  8.112 25.859 8.472 26.629 ;
     RECT  10.176 26.099 10.848 26.629 ;
     RECT  25.704 26.197 28.176 26.725 ;
     RECT  35.784 26.243 36.456 26.581 ;
     RECT  45.912 26.243 46.872 27.205 ;
     RECT  62.112 26.243 62.808 27.301 ;
     RECT  24.312 26.339 25.68 27.299 ;
     RECT  6.168 26.483 7.632 26.531 ;
     RECT  5.88 26.531 7.632 27.587 ;
     RECT  35.784 26.581 36.864 27.155 ;
     RECT  8.112 26.629 9.552 29.941 ;
     RECT  9.576 26.629 10.848 27.205 ;
     RECT  26.664 26.725 28.176 28.117 ;
     RECT  53.496 26.819 54.624 30.229 ;
     RECT  16.056 26.867 17.52 27.877 ;
     RECT  30.072 27.061 31.152 27.203 ;
     RECT  35.784 27.155 36.888 27.589 ;
     RECT  9.624 27.205 10.848 30.037 ;
     RECT  24.312 27.299 24.408 28.117 ;
     RECT  62.112 27.301 63.216 27.829 ;
     RECT  63.24 27.301 64.368 27.395 ;
     RECT  39.216 27.347 39.36 27.589 ;
     RECT  60.696 27.347 61.8 30.565 ;
     RECT  74.184 27.347 75.264 28.211 ;
     RECT  63.24 27.395 64.992 28.309 ;
     RECT  12.024 27.491 13.2 28.453 ;
     RECT  5.4 27.587 7.632 27.877 ;
     RECT  35.784 27.589 38.064 27.733 ;
     RECT  38.088 27.589 39.36 27.877 ;
     RECT  35.784 27.733 37.152 28.787 ;
     RECT  13.992 27.875 15.36 28.547 ;
     RECT  5.4 27.877 7.344 28.547 ;
     RECT  16.056 27.877 17.376 29.797 ;
     RECT  38.328 27.877 39.36 28.403 ;
     RECT  51.48 28.115 52.56 31.285 ;
     RECT  57.048 28.211 58.32 28.643 ;
     RECT  73.848 28.211 75.264 28.547 ;
     RECT  59.688 28.261 60.672 34.165 ;
     RECT  63.864 28.309 64.992 29.123 ;
     RECT  38.136 28.403 39.36 29.651 ;
     RECT  47.256 28.405 48.24 28.547 ;
     RECT  48.264 28.405 49.248 28.547 ;
     RECT  3.624 28.453 4.704 29.029 ;
     RECT  12.024 28.453 13.104 28.595 ;
     RECT  5.256 28.547 7.344 29.077 ;
     RECT  13.992 28.547 14.088 29.365 ;
     RECT  47.256 28.547 49.584 29.077 ;
     RECT  62.808 28.547 63.84 29.123 ;
     RECT  11.88 28.595 13.2 30.565 ;
     RECT  26.664 28.787 28.176 29.123 ;
     RECT  35.784 28.787 38.064 28.933 ;
     RECT  36.264 28.933 38.064 29.075 ;
     RECT  3.72 29.029 4.704 29.699 ;
     RECT  35.784 29.075 38.064 30.037 ;
     RECT  5.256 29.077 6.288 33.685 ;
     RECT  6.312 29.077 7.344 29.893 ;
     RECT  47.256 29.077 48.288 29.219 ;
     RECT  48.312 29.077 49.584 29.219 ;
     RECT  2.712 29.123 3.696 29.699 ;
     RECT  47.256 29.219 47.304 29.797 ;
     RECT  40.512 29.557 41.712 33.061 ;
     RECT  38.088 29.651 39.36 34.453 ;
     RECT  2.712 29.699 4.704 30.661 ;
     RECT  8.112 29.941 9.36 30.755 ;
     RECT  9.624 30.037 10.608 30.083 ;
     RECT  35.784 30.037 36.768 30.179 ;
     RECT  36.792 30.037 38.064 30.179 ;
     RECT  9.576 30.083 10.608 30.275 ;
     RECT  20.568 30.181 22.032 31.955 ;
     RECT  53.592 30.229 54.624 30.661 ;
     RECT  67.512 30.229 68.544 31.379 ;
     RECT  9.576 30.275 10.704 31.235 ;
     RECT  16.056 30.275 17.376 36.515 ;
     RECT  56.904 30.325 58.32 30.851 ;
     RECT  78.312 30.563 78.6 31.909 ;
     RECT  11.88 30.565 13.056 30.851 ;
     RECT  2.712 30.661 3.84 31.715 ;
     RECT  60.696 30.707 61.68 32.435 ;
     RECT  25.272 30.709 26.784 30.899 ;
     RECT  26.808 30.709 28.176 31.331 ;
     RECT  8.112 30.755 9.552 35.027 ;
     RECT  53.592 30.803 54.624 31.379 ;
     RECT  11.88 30.851 13.2 32.389 ;
     RECT  32.472 30.899 33.888 31.957 ;
     RECT  9.576 31.235 11.136 32.437 ;
     RECT  51.48 31.285 52.464 32.099 ;
     RECT  45.912 31.331 47.232 31.379 ;
     RECT  45.912 31.379 47.28 32.771 ;
     RECT  53.544 31.379 54.624 34.741 ;
     RECT  2.712 31.715 4.704 32.915 ;
     RECT  51.48 32.099 52.56 33.445 ;
     RECT  60.696 32.435 61.8 36.469 ;
     RECT  9.72 32.437 11.136 36.085 ;
     RECT  32.472 32.723 33.888 33.059 ;
     RECT  45.912 32.771 47.304 33.061 ;
     RECT  58.344 32.867 59.328 33.971 ;
     RECT  2.712 32.915 4.8 33.013 ;
     RECT  3.528 33.013 4.8 34.117 ;
     RECT  46.008 33.061 47.304 33.397 ;
     RECT  40.512 33.347 41.712 37.093 ;
     RECT  46.008 33.397 47.328 34.115 ;
     RECT  65.112 33.589 66.288 34.021 ;
     RECT  35.112 33.635 35.784 34.501 ;
     RECT  25.032 33.781 26.304 33.829 ;
     RECT  25.128 33.829 26.304 34.067 ;
     RECT  58.656 33.971 59.328 34.357 ;
     RECT  65.304 34.021 66.288 35.171 ;
     RECT  3.528 34.117 4.656 34.787 ;
     RECT  47.928 34.165 49.248 35.413 ;
     RECT  28.2 34.259 29.28 35.941 ;
     RECT  38.76 34.499 40.08 35.075 ;
     RECT  35.112 34.501 36.432 35.845 ;
     RECT  17.544 34.643 18.6 36.661 ;
     RECT  3.528 34.787 4.8 34.883 ;
     RECT  41.736 34.789 43.104 37.475 ;
     RECT  31.656 34.837 32.832 35.363 ;
     RECT  32.856 34.837 33.888 35.363 ;
     RECT  59.688 34.979 60.672 37.861 ;
     RECT  8.112 35.027 9.648 35.893 ;
     RECT  38.664 35.075 40.08 37.573 ;
     RECT  65.112 35.171 66.288 35.747 ;
     RECT  15.936 35.267 16.032 35.413 ;
     RECT  62.808 35.269 63.984 35.843 ;
     RECT  64.008 35.269 65.088 35.843 ;
     RECT  70.416 35.363 70.512 36.517 ;
     RECT  14.568 35.413 16.032 35.651 ;
     RECT  47.976 35.413 49.248 36.227 ;
     RECT  70.968 35.747 72.384 37.139 ;
     RECT  8.328 35.893 9.648 36.421 ;
     RECT  56.712 35.989 57.696 37.043 ;
     RECT  35.112 36.083 36.432 36.563 ;
     RECT  47.928 36.227 49.248 37.043 ;
     RECT  8.328 36.421 9.552 36.469 ;
     RECT  16.056 36.515 17.52 37.043 ;
     RECT  9.72 36.563 11.136 38.389 ;
     RECT  11.688 36.613 13.2 36.949 ;
     RECT  43.128 36.803 44.352 37.475 ;
     RECT  26.808 36.949 28.176 37.141 ;
     RECT  5.448 36.995 6.672 38.195 ;
     RECT  16.368 37.043 17.52 37.045 ;
     RECT  60.792 37.043 61.8 38.725 ;
     RECT  16.392 37.045 17.52 37.189 ;
     RECT  70.968 37.139 72.432 38.437 ;
     RECT  26.808 37.141 28.08 37.331 ;
     RECT  16.44 37.189 17.52 37.475 ;
     RECT  11.688 37.235 13.2 38.339 ;
     RECT  26.808 37.331 28.176 37.619 ;
     RECT  16.368 37.379 16.416 37.475 ;
     RECT  16.368 37.475 17.52 38.677 ;
     RECT  43.968 37.475 44.352 38.101 ;
     RECT  8.328 37.571 9.696 39.875 ;
     RECT  65.4 37.573 66.72 38.243 ;
     RECT  17.544 37.619 18.6 42.853 ;
     RECT  45.912 38.101 46.896 38.341 ;
     RECT  38.664 38.195 40.08 40.499 ;
     RECT  73.8 38.195 74.424 39.301 ;
     RECT  77.232 38.195 78 39.301 ;
     RECT  65.4 38.243 66.864 38.675 ;
     RECT  9.816 38.389 11.136 40.163 ;
     RECT  70.968 38.437 72.384 38.579 ;
     RECT  70.968 38.579 72.432 42.181 ;
     RECT  45.912 38.627 46.896 40.067 ;
     RECT  16.248 38.677 17.52 38.915 ;
     RECT  78.312 38.677 79.296 39.301 ;
     RECT  16.992 38.915 17.52 39.253 ;
     RECT  46.92 39.253 48.336 40.067 ;
     RECT  76.92 39.301 78 40.451 ;
     RECT  57.048 39.589 58.032 40.451 ;
     RECT  40.512 39.923 41.712 43.717 ;
     RECT  28.2 40.019 29.4 40.451 ;
     RECT  45.912 40.067 46.104 40.885 ;
     RECT  9.72 40.163 11.136 40.595 ;
     RECT  60.552 40.163 61.8 41.557 ;
     RECT  48.36 40.259 50.064 41.557 ;
     RECT  2.712 40.405 3.888 44.965 ;
     RECT  69.432 40.405 70.512 40.981 ;
     RECT  29.28 40.451 29.4 41.605 ;
     RECT  57.048 40.451 58.056 40.595 ;
     RECT  56.712 40.595 58.056 41.269 ;
     RECT  20.568 40.643 22.032 42.227 ;
     RECT  52.344 40.691 53.472 41.123 ;
     RECT  42.888 40.835 44.352 43.285 ;
     RECT  53.544 40.883 54.624 45.253 ;
     RECT  46.008 40.885 46.104 41.221 ;
     RECT  63 40.981 64.416 42.227 ;
     RECT  69.432 40.981 70.416 46.165 ;
     RECT  41.736 41.027 42.864 43.331 ;
     RECT  65.688 41.077 66.864 41.315 ;
     RECT  52.344 41.123 53.52 42.709 ;
     RECT  56.712 41.269 58.128 42.803 ;
     RECT  65.592 41.315 66.864 42.227 ;
     RECT  48.792 41.557 50.064 42.565 ;
     RECT  58.968 41.557 60.288 42.757 ;
     RECT  8.112 41.749 9.216 42.995 ;
     RECT  20.28 42.227 22.032 42.803 ;
     RECT  31.8 42.709 33.312 43.091 ;
     RECT  52.44 42.709 53.52 46.067 ;
     RECT  51.312 42.755 52.32 43.235 ;
     RECT  58.968 42.757 60.192 45.733 ;
     RECT  20.28 42.803 21.768 43.189 ;
     RECT  56.712 42.803 57.096 43.813 ;
     RECT  17.592 42.853 18.6 44.437 ;
     RECT  33.216 43.091 33.312 44.437 ;
     RECT  20.28 43.189 21.744 44.437 ;
     RECT  51.312 43.235 52.416 46.021 ;
     RECT  48.792 43.283 50.064 43.427 ;
     RECT  70.968 43.283 72.432 44.965 ;
     RECT  42.888 43.285 44.208 43.331 ;
     RECT  41.736 43.331 41.784 44.245 ;
     RECT  43.344 43.331 44.208 43.429 ;
     RECT  73.8 43.333 75.024 44.099 ;
     RECT  43.368 43.859 44.352 45.059 ;
     RECT  11.832 43.861 13.104 46.357 ;
     RECT  20.28 44.437 21.456 44.725 ;
     RECT  31.656 44.677 32.64 44.867 ;
     RECT  63 44.773 64.272 44.869 ;
     RECT  63.24 44.869 64.272 45.011 ;
     RECT  2.808 44.965 3.888 46.019 ;
     RECT  46.44 44.965 47.904 45.011 ;
     RECT  70.968 44.965 72.192 45.683 ;
     RECT  46.44 45.011 47.928 45.541 ;
     RECT  41.832 45.013 43.344 45.059 ;
     RECT  41.832 45.059 42.792 45.541 ;
     RECT  67.512 45.109 68.832 45.731 ;
     RECT  24.312 45.443 25.176 45.877 ;
     RECT  46.44 45.541 48.384 45.683 ;
     RECT  82.056 45.541 83.4 46.931 ;
     RECT  58.656 45.587 58.752 46.741 ;
     RECT  47.616 45.683 48.384 46.163 ;
     RECT  70.968 45.683 72.432 46.645 ;
     RECT  69.072 45.731 69.408 47.029 ;
     RECT  24.312 45.877 26.064 46.067 ;
     RECT  53.544 45.971 54.624 47.747 ;
     RECT  2.712 46.019 3.888 48.467 ;
     RECT  24.312 46.067 25.608 46.405 ;
     RECT  52.104 46.067 53.52 47.747 ;
     RECT  47.616 46.163 47.64 46.405 ;
     RECT  16.536 46.259 17.616 46.787 ;
     RECT  44.376 46.259 45.6 48.229 ;
     RECT  11.832 46.357 13.056 46.789 ;
     RECT  24.312 46.405 25.584 49.715 ;
     RECT  36.36 46.787 37.032 47.123 ;
     RECT  69.432 46.787 70.416 47.075 ;
     RECT  11.832 46.789 13.008 47.747 ;
     RECT  58.776 46.979 60.192 49.619 ;
     RECT  6.624 47.027 7.056 48.421 ;
     RECT  63 47.075 63.24 48.373 ;
     RECT  69.096 47.075 70.416 48.469 ;
     RECT  36.072 47.123 37.032 47.269 ;
     RECT  30.072 47.125 31.104 47.413 ;
     RECT  45.912 47.171 46.008 48.421 ;
     RECT  18.912 47.219 20.256 48.421 ;
     RECT  13.512 47.221 14.688 48.323 ;
     RECT  36.072 47.269 38.4 47.891 ;
     RECT  76.584 47.461 78 49.427 ;
     RECT  39.048 47.701 40.2 48.661 ;
     RECT  11.832 47.747 13.2 49.525 ;
     RECT  52.104 47.747 53.016 48.997 ;
     RECT  36.072 47.891 37.08 48.085 ;
     RECT  36.072 48.085 37.056 51.203 ;
     RECT  30.072 48.131 31.104 49.765 ;
     RECT  65.016 48.133 66.528 48.563 ;
     RECT  43.224 48.181 44.352 48.323 ;
     RECT  44.424 48.229 45.6 48.421 ;
     RECT  13.512 48.323 14.28 48.469 ;
     RECT  42.312 48.323 44.352 48.757 ;
     RECT  60.216 48.371 61.632 49.525 ;
     RECT  63 48.373 64.464 48.995 ;
     RECT  70.968 48.419 72.384 49.477 ;
     RECT  18.912 48.421 20.112 49.235 ;
     RECT  22.2 48.421 23.616 48.613 ;
     RECT  45.912 48.421 47.28 49.333 ;
     RECT  69.096 48.469 70.08 49.619 ;
     RECT  66.72 48.563 66.768 49.525 ;
     RECT  22.2 48.613 23.328 49.187 ;
     RECT  31.656 48.661 32.784 49.477 ;
     RECT  42.312 48.757 43.296 50.531 ;
     RECT  33.24 49.283 34.224 50.195 ;
     RECT  45.912 49.333 47.088 53.603 ;
     RECT  73.8 49.381 75.216 50.101 ;
     RECT  75.24 49.381 76.56 49.427 ;
     RECT  77.52 49.427 78 50.677 ;
     RECT  44.424 49.475 45.6 50.485 ;
     RECT  53.016 49.477 54.528 50.389 ;
     RECT  71.16 49.477 72.384 49.525 ;
     RECT  11.832 49.525 13.104 50.003 ;
     RECT  60.216 49.525 61.584 49.619 ;
     RECT  71.16 49.525 72.288 49.667 ;
     RECT  39.024 49.571 39.984 50.533 ;
     RECT  40.776 49.571 42.288 50.771 ;
     RECT  58.776 49.619 58.968 49.717 ;
     RECT  60.816 49.619 61.584 50.773 ;
     RECT  69.096 49.619 70.416 54.085 ;
     RECT  70.968 49.667 72.288 52.981 ;
     RECT  17.616 50.003 18.6 50.149 ;
     RECT  73.8 50.101 75.168 50.867 ;
     RECT  17.208 50.149 18.6 51.205 ;
     RECT  33.24 50.195 34.704 51.203 ;
     RECT  42.312 50.531 43.632 54.517 ;
     RECT  39.024 50.533 39.456 50.965 ;
     RECT  31.656 50.723 33.216 51.203 ;
     RECT  40.68 50.771 42.288 51.013 ;
     RECT  37.08 50.965 38.496 51.203 ;
     RECT  40.68 51.013 42.192 52.211 ;
     RECT  31.656 51.203 34.704 51.973 ;
     RECT  36.072 51.203 36.888 52.309 ;
     RECT  17.208 51.205 18.24 51.347 ;
     RECT  79.08 51.205 80.544 51.923 ;
     RECT  65.016 51.253 66.48 51.685 ;
     RECT  17.016 51.347 18.24 52.499 ;
     RECT  6.744 51.395 7.8 52.067 ;
     RECT  48.216 51.781 49.488 51.923 ;
     RECT  44.424 51.923 45.6 53.845 ;
     RECT  80.568 51.923 81.648 53.555 ;
     RECT  32.376 51.973 34.704 52.019 ;
     RECT  32.376 52.019 34.8 52.405 ;
     RECT  8.112 52.405 9.36 53.219 ;
     RECT  33.336 52.405 34.8 53.893 ;
     RECT  49.488 52.451 50.064 53.509 ;
     RECT  70.968 52.981 72.24 53.123 ;
     RECT  70.968 53.123 72.288 53.557 ;
     RECT  77.52 53.267 78 54.373 ;
     RECT  47.592 53.509 48.672 53.603 ;
     RECT  48.696 53.509 50.064 54.659 ;
     RECT  71.112 53.557 72.288 55.667 ;
     RECT  44.472 53.845 45.6 54.419 ;
     RECT  33.336 53.893 34.704 54.083 ;
     RECT  12.024 53.941 13.2 55.859 ;
     RECT  33.336 54.083 34.8 55.667 ;
     RECT  17.016 54.085 18.24 55.859 ;
     RECT  28.104 54.277 29.28 55.235 ;
     RECT  76.488 54.373 78 55.907 ;
     RECT  43.656 54.419 45.6 54.565 ;
     RECT  69.072 54.419 69.504 55.715 ;
     RECT  42.456 54.517 43.632 56.149 ;
     RECT  6.6 54.565 7.8 54.707 ;
     RECT  43.656 54.565 45.12 55.429 ;
     RECT  20.952 54.709 22.176 55.907 ;
     RECT  24.312 54.755 24.408 55.861 ;
     RECT  40.512 54.803 40.68 55.813 ;
     RECT  70.968 55.667 72.288 57.541 ;
     RECT  69.072 55.715 70.416 55.813 ;
     RECT  40.512 55.813 42.144 56.245 ;
     RECT  67.512 55.813 68.976 56.003 ;
     RECT  69.384 55.813 70.416 57.587 ;
     RECT  17.016 55.859 18.432 56.917 ;
     RECT  14.424 55.955 14.712 57.013 ;
     RECT  31.128 56.003 32.352 57.781 ;
     RECT  40.632 56.245 42.144 56.387 ;
     RECT  44.472 56.339 45.6 56.915 ;
     RECT  18.912 56.533 19.968 61.093 ;
     RECT  42.144 56.915 42.288 58.117 ;
     RECT  17.112 56.917 18.432 57.059 ;
     RECT  17.016 57.059 18.432 57.923 ;
     RECT  45.912 57.059 47.088 58.213 ;
     RECT  56.712 57.443 57.192 58.117 ;
     RECT  67.848 57.541 69.36 57.587 ;
     RECT  81.432 57.541 82.656 58.115 ;
     RECT  32.376 57.827 33.048 58.453 ;
     RECT  17.016 57.923 18.48 58.597 ;
     RECT  42.456 58.067 43.632 58.499 ;
     RECT  81.432 58.115 81.48 59.171 ;
     RECT  19.992 58.117 21.504 59.171 ;
     RECT  40.776 58.117 42.288 59.557 ;
     RECT  56.712 58.117 58.128 63.205 ;
     RECT  32.376 58.453 34.56 59.029 ;
     RECT  17.064 58.597 18.48 60.659 ;
     RECT  70.968 58.643 72.288 59.797 ;
     RECT  73.8 58.691 74.136 59.797 ;
     RECT  32.376 59.029 33.888 59.365 ;
     RECT  19.992 59.171 21.336 59.557 ;
     RECT  81.456 59.171 81.48 59.221 ;
     RECT  69.528 59.411 70.944 61.573 ;
     RECT  33.144 59.459 34.56 59.987 ;
     RECT  65.256 59.509 66.624 60.515 ;
     RECT  19.992 59.557 21.12 60.037 ;
     RECT  41.064 59.557 42.288 59.795 ;
     RECT  5.784 59.605 6.864 60.323 ;
     RECT  37.944 59.749 39.024 61.043 ;
     RECT  40.872 59.795 42.288 59.845 ;
     RECT  71.16 59.797 72.288 60.419 ;
     RECT  73.8 59.797 75.264 60.563 ;
     RECT  81.48 59.797 82.944 59.891 ;
     RECT  40.872 59.845 42.192 60.371 ;
     RECT  42.216 59.891 42.456 60.997 ;
     RECT  32.376 59.987 32.904 61.141 ;
     RECT  16.896 60.083 17.04 60.613 ;
     RECT  27.456 60.275 27.504 60.901 ;
     RECT  40.728 60.371 42.192 62.533 ;
     RECT  70.968 60.419 72.288 61.813 ;
     RECT  73.8 60.563 75.744 61.621 ;
     RECT  16.008 60.613 17.04 62.099 ;
     RECT  17.064 60.659 18.6 62.053 ;
     RECT  26.232 60.901 27.504 61.091 ;
     RECT  58.152 60.995 58.68 62.197 ;
     RECT  24.888 60.997 26.208 61.139 ;
     RECT  42.216 60.997 43.344 61.237 ;
     RECT  28.032 61.091 28.224 62.197 ;
     RECT  18.912 61.235 20.304 62.195 ;
     RECT  69.216 61.331 69.504 61.717 ;
     RECT  69.528 61.573 70.656 61.859 ;
     RECT  73.8 61.621 74.928 62.435 ;
     RECT  67.848 61.717 69.504 61.813 ;
     RECT  68.328 61.813 69.504 61.859 ;
     RECT  70.968 61.813 72 63.299 ;
     RECT  75.768 61.813 77.184 61.859 ;
     RECT  31.128 61.907 32.352 62.195 ;
     RECT  17.064 62.053 18.288 62.099 ;
     RECT  16.008 62.099 18.288 62.725 ;
     RECT  51.312 62.149 52.656 64.309 ;
     RECT  42.36 62.195 43.344 63.587 ;
     RECT  58.152 62.197 59.472 62.581 ;
     RECT  33.096 62.533 34.56 63.541 ;
     RECT  28.032 62.723 28.224 62.773 ;
     RECT  16.008 62.725 17.76 62.771 ;
     RECT  17.04 62.771 17.76 63.349 ;
     RECT  26.568 62.773 28.224 63.829 ;
     RECT  29.712 62.867 30.768 64.739 ;
     RECT  12.864 62.963 13.2 63.781 ;
     RECT  28.248 63.011 29.4 65.603 ;
     RECT  39.048 63.107 40.08 63.347 ;
     RECT  57.144 63.205 58.128 63.539 ;
     RECT  40.728 63.251 42.192 65.413 ;
     RECT  47.112 63.253 48.48 63.589 ;
     RECT  70.968 63.299 72.384 64.933 ;
     RECT  32.4 63.347 32.832 64.067 ;
     RECT  38.808 63.347 40.2 64.019 ;
     RECT  6.864 63.491 7.152 64.933 ;
     RECT  33.24 63.541 34.56 63.731 ;
     RECT  76.104 63.541 77.184 64.979 ;
     RECT  42.216 63.587 43.344 64.451 ;
     RECT  47.352 63.589 48.48 63.827 ;
     RECT  11.928 63.781 13.2 64.357 ;
     RECT  47.352 63.827 47.592 64.357 ;
     RECT  26.808 63.829 28.224 64.117 ;
     RECT  32.4 64.067 32.424 64.453 ;
     RECT  51.312 64.309 52.608 66.085 ;
     RECT  11.928 64.357 13.104 64.883 ;
     RECT  53.16 64.405 54.624 65.171 ;
     RECT  42.216 64.451 43.536 65.651 ;
     RECT  29.712 64.739 30.744 65.797 ;
     RECT  11.904 64.883 13.104 65.603 ;
     RECT  70.968 64.933 72.048 65.893 ;
     RECT  26.568 64.979 27.6 67.285 ;
     RECT  76.944 64.979 77.184 66.085 ;
     RECT  52.632 65.171 54.624 66.085 ;
     RECT  5.664 65.267 6.432 65.797 ;
     RECT  8.112 65.267 8.328 66.613 ;
     RECT  36.696 65.317 38.16 65.459 ;
     RECT  70.704 65.411 70.944 66.037 ;
     RECT  78.312 65.411 78.936 66.421 ;
     RECT  40.728 65.413 42 65.555 ;
     RECT  40.728 65.555 42.192 66.275 ;
     RECT  11.904 65.603 13.2 66.085 ;
     RECT  28.056 65.603 29.4 67.667 ;
     RECT  5.112 65.797 6.432 66.227 ;
     RECT  29.712 65.797 30.72 66.085 ;
     RECT  70.968 65.893 71.952 67.715 ;
     RECT  57.144 65.939 57.24 67.285 ;
     RECT  68.328 66.037 69.408 67.571 ;
     RECT  69.432 66.037 70.944 69.301 ;
     RECT  2.712 66.085 4.08 68.917 ;
     RECT  4.104 66.085 5.088 67.283 ;
     RECT  11.928 66.085 13.2 66.755 ;
     RECT  52.632 66.085 54.144 67.093 ;
     RECT  40.728 66.275 42.024 66.661 ;
     RECT  24.312 66.323 24.456 67.813 ;
     RECT  8.112 66.613 9.408 67.859 ;
     RECT  40.728 66.661 42 67.043 ;
     RECT  18.912 66.709 19.92 67.331 ;
     RECT  12.528 66.755 13.2 67.765 ;
     RECT  45.912 66.803 47.088 69.587 ;
     RECT  40.632 67.043 42 67.429 ;
     RECT  52.92 67.093 54.144 67.331 ;
     RECT  52.92 67.331 54.624 67.427 ;
     RECT  33.144 67.333 34.464 67.907 ;
     RECT  52.44 67.427 54.624 68.581 ;
     RECT  40.632 67.429 41.664 68.387 ;
     RECT  51.312 67.571 52.416 68.627 ;
     RECT  68.088 67.571 69.408 70.835 ;
     RECT  29.232 67.667 29.4 68.629 ;
     RECT  29.712 67.715 30.72 69.587 ;
     RECT  70.968 67.715 72.384 68.197 ;
     RECT  72.912 67.717 74.112 70.019 ;
     RECT  74.136 67.717 75.36 68.243 ;
     RECT  81.48 67.717 82.656 69.155 ;
     RECT  48.024 67.765 49.248 68.917 ;
     RECT  24.456 67.813 25.824 68.195 ;
     RECT  35.112 68.003 36.144 68.147 ;
     RECT  24.408 68.195 25.824 69.541 ;
     RECT  71.256 68.197 72.384 70.211 ;
     RECT  75.816 68.197 76.944 68.677 ;
     RECT  42.024 68.341 43.488 68.915 ;
     RECT  58.488 68.341 59.472 68.963 ;
     RECT  40.632 68.387 42 68.915 ;
     RECT  53.4 68.581 54.624 68.867 ;
     RECT  51.312 68.627 53.376 69.059 ;
     RECT  29.232 68.629 29.28 68.965 ;
     RECT  49.704 68.675 51 70.739 ;
     RECT  75.816 68.677 76.896 68.771 ;
     RECT  66.168 68.771 67.2 70.117 ;
     RECT  40.632 68.915 41.544 70.309 ;
     RECT  48.024 68.917 49.008 68.963 ;
     RECT  62.808 68.917 64.32 69.587 ;
     RECT  47.784 68.963 49.008 69.539 ;
     RECT  51.312 69.059 52.728 69.733 ;
     RECT  69.432 69.301 70.704 70.835 ;
     RECT  76.896 69.491 77.136 70.645 ;
     RECT  29.712 69.587 30.744 70.069 ;
     RECT  51.312 69.733 52.704 71.315 ;
     RECT  55.032 70.019 56.4 70.115 ;
     RECT  72.912 70.019 74.088 71.317 ;
     RECT  4.728 70.021 6 70.739 ;
     RECT  6.024 70.021 7.392 70.261 ;
     RECT  29.976 70.069 30.744 70.933 ;
     RECT  60.408 70.069 61.8 71.077 ;
     RECT  66.144 70.163 66.672 70.789 ;
     RECT  71.016 70.211 72.384 70.835 ;
     RECT  47.592 70.259 47.688 70.547 ;
     RECT  81.288 70.307 81.384 71.797 ;
     RECT  47.664 70.547 47.688 71.221 ;
     RECT  76.104 70.645 77.136 72.515 ;
     RECT  4.728 70.739 6.384 70.789 ;
     RECT  49.56 70.739 51 71.461 ;
     RECT  4.776 70.789 6.384 70.931 ;
     RECT  65.256 70.789 66.672 72.037 ;
     RECT  67.848 70.835 70.704 70.933 ;
     RECT  4.728 70.931 6.384 71.749 ;
     RECT  67.848 70.933 69.072 71.845 ;
     RECT  69.096 70.933 70.704 71.221 ;
     RECT  60.648 71.077 61.8 74.147 ;
     RECT  44.28 71.173 45.6 71.747 ;
     RECT  25.752 71.221 27.264 71.891 ;
     RECT  69.096 71.221 70.512 71.843 ;
     RECT  72.912 71.317 74.064 71.747 ;
     RECT  6.408 71.459 7.392 72.851 ;
     RECT  49.56 71.461 50.88 72.467 ;
     RECT  24.312 71.603 25.728 72.851 ;
     RECT  28.056 71.605 29.232 72.467 ;
     RECT  43.512 71.747 43.896 72.419 ;
     RECT  72.912 71.747 73.224 72.517 ;
     RECT  4.728 71.749 5.76 72.947 ;
     RECT  69.096 71.843 70.704 72.085 ;
     RECT  67.848 71.845 69.024 72.421 ;
     RECT  32.904 71.941 34.272 72.229 ;
     RECT  38.76 72.037 40.2 73.859 ;
     RECT  69.192 72.085 70.704 72.325 ;
     RECT  47.688 72.181 48.768 72.419 ;
     RECT  32.904 72.229 34.224 72.755 ;
     RECT  40.512 72.275 41.064 72.997 ;
     RECT  69.432 72.325 70.704 72.563 ;
     RECT  2.712 72.419 3.744 74.147 ;
     RECT  43.488 72.419 43.896 72.901 ;
     RECT  67.848 72.421 68.976 72.901 ;
     RECT  28.464 72.467 29.232 72.949 ;
     RECT  49.56 72.467 51 74.339 ;
     RECT  69.432 72.563 69.96 72.805 ;
     RECT  6.408 72.851 7.8 72.995 ;
     RECT  22.488 72.901 24 75.443 ;
     RECT  43.488 72.901 43.872 73.477 ;
     RECT  5.784 72.995 7.8 74.053 ;
     RECT  65.256 72.995 66.672 73.571 ;
     RECT  40.512 72.997 41.664 75.299 ;
     RECT  15.672 73.189 16.944 73.237 ;
     RECT  72.912 73.523 73.224 74.629 ;
     RECT  28.464 73.715 29.232 74.101 ;
     RECT  67.512 73.811 68.88 75.623 ;
     RECT  39.552 73.859 40.2 73.861 ;
     RECT  39.552 73.861 40.032 74.581 ;
     RECT  29.832 74.003 30.024 75.061 ;
     RECT  5.784 74.053 7.104 74.867 ;
     RECT  78.408 74.053 79.392 74.339 ;
     RECT  28.008 74.101 29.232 74.723 ;
     RECT  2.712 74.147 3.936 74.723 ;
     RECT  78.408 74.339 79.416 75.637 ;
     RECT  24.312 74.581 25.68 75.443 ;
     RECT  72.912 74.629 74.064 75.299 ;
     RECT  77.136 74.675 77.376 75.781 ;
     RECT  68.112 75.623 68.88 75.781 ;
     RECT  79.176 75.637 79.416 75.781 ;
     RECT  68.112 75.781 68.592 76.357 ;
     RECT  68.112 76.357 68.208 76.885 ;
  END
END ot_hgi_qdq_core
END LIBRARY
